VERSION 5.8 ;
BUSBITCHARS "[]" ;
DIVIDERCHAR "/" ;
UNITS
    DATABASE MICRONS 1000 ;
END UNITS

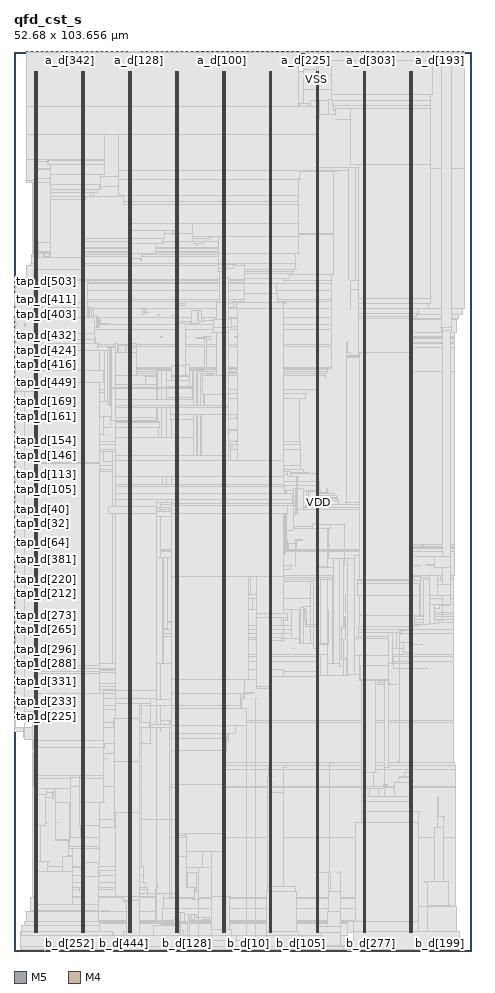
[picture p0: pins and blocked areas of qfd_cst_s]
MACRO qfd_cst_s
  FOREIGN qfd_cst_s 0 0 ;
  CLASS BLOCK ;
  SIZE 52.68 BY 103.656 ;
  PIN a_d[0]
    DIRECTION INPUT ;
    USE SIGNAL ;
    PORT
      LAYER M5 ;
        RECT  20.496 103.572 20.52 103.656 ;
    END
  END a_d[0]
  PIN a_d[100]
    DIRECTION INPUT ;
    USE SIGNAL ;
    PORT
      LAYER M5 ;
        RECT  23.952 103.572 23.976 103.656 ;
    END
  END a_d[100]
  PIN a_d[101]
    DIRECTION INPUT ;
    USE SIGNAL ;
    PORT
      LAYER M5 ;
        RECT  24.048 103.572 24.072 103.656 ;
    END
  END a_d[101]
  PIN a_d[102]
    DIRECTION INPUT ;
    USE SIGNAL ;
    PORT
      LAYER M5 ;
        RECT  24.144 103.572 24.168 103.656 ;
    END
  END a_d[102]
  PIN a_d[103]
    DIRECTION INPUT ;
    USE SIGNAL ;
    PORT
      LAYER M5 ;
        RECT  24.24 103.572 24.264 103.656 ;
    END
  END a_d[103]
  PIN a_d[104]
    DIRECTION INPUT ;
    USE SIGNAL ;
    PORT
      LAYER M5 ;
        RECT  24.336 103.572 24.36 103.656 ;
    END
  END a_d[104]
  PIN a_d[105]
    DIRECTION INPUT ;
    USE SIGNAL ;
    PORT
      LAYER M5 ;
        RECT  24.432 103.572 24.456 103.656 ;
    END
  END a_d[105]
  PIN a_d[106]
    DIRECTION INPUT ;
    USE SIGNAL ;
    PORT
      LAYER M5 ;
        RECT  24.528 103.572 24.552 103.656 ;
    END
  END a_d[106]
  PIN a_d[107]
    DIRECTION INPUT ;
    USE SIGNAL ;
    PORT
      LAYER M5 ;
        RECT  24.624 103.572 24.648 103.656 ;
    END
  END a_d[107]
  PIN a_d[108]
    DIRECTION INPUT ;
    USE SIGNAL ;
    PORT
      LAYER M5 ;
        RECT  24.72 103.572 24.744 103.656 ;
    END
  END a_d[108]
  PIN a_d[109]
    DIRECTION INPUT ;
    USE SIGNAL ;
    PORT
      LAYER M5 ;
        RECT  24.816 103.572 24.84 103.656 ;
    END
  END a_d[109]
  PIN a_d[10]
    DIRECTION INPUT ;
    USE SIGNAL ;
    PORT
      LAYER M5 ;
        RECT  21.456 103.572 21.48 103.656 ;
    END
  END a_d[10]
  PIN a_d[110]
    DIRECTION INPUT ;
    USE SIGNAL ;
    PORT
      LAYER M5 ;
        RECT  24.912 103.572 24.936 103.656 ;
    END
  END a_d[110]
  PIN a_d[111]
    DIRECTION INPUT ;
    USE SIGNAL ;
    PORT
      LAYER M5 ;
        RECT  25.008 103.572 25.032 103.656 ;
    END
  END a_d[111]
  PIN a_d[112]
    DIRECTION INPUT ;
    USE SIGNAL ;
    PORT
      LAYER M5 ;
        RECT  25.104 103.572 25.128 103.656 ;
    END
  END a_d[112]
  PIN a_d[113]
    DIRECTION INPUT ;
    USE SIGNAL ;
    PORT
      LAYER M5 ;
        RECT  25.2 103.572 25.224 103.656 ;
    END
  END a_d[113]
  PIN a_d[114]
    DIRECTION INPUT ;
    USE SIGNAL ;
    PORT
      LAYER M5 ;
        RECT  25.296 103.572 25.32 103.656 ;
    END
  END a_d[114]
  PIN a_d[115]
    DIRECTION INPUT ;
    USE SIGNAL ;
    PORT
      LAYER M5 ;
        RECT  25.392 103.572 25.416 103.656 ;
    END
  END a_d[115]
  PIN a_d[116]
    DIRECTION INPUT ;
    USE SIGNAL ;
    PORT
      LAYER M5 ;
        RECT  25.488 103.572 25.512 103.656 ;
    END
  END a_d[116]
  PIN a_d[117]
    DIRECTION INPUT ;
    USE SIGNAL ;
    PORT
      LAYER M5 ;
        RECT  25.584 103.572 25.608 103.656 ;
    END
  END a_d[117]
  PIN a_d[118]
    DIRECTION INPUT ;
    USE SIGNAL ;
    PORT
      LAYER M5 ;
        RECT  25.68 103.572 25.704 103.656 ;
    END
  END a_d[118]
  PIN a_d[119]
    DIRECTION INPUT ;
    USE SIGNAL ;
    PORT
      LAYER M5 ;
        RECT  25.776 103.572 25.8 103.656 ;
    END
  END a_d[119]
  PIN a_d[11]
    DIRECTION INPUT ;
    USE SIGNAL ;
    PORT
      LAYER M5 ;
        RECT  21.552 103.572 21.576 103.656 ;
    END
  END a_d[11]
  PIN a_d[120]
    DIRECTION INPUT ;
    USE SIGNAL ;
    PORT
      LAYER M5 ;
        RECT  25.872 103.572 25.896 103.656 ;
    END
  END a_d[120]
  PIN a_d[121]
    DIRECTION INPUT ;
    USE SIGNAL ;
    PORT
      LAYER M5 ;
        RECT  25.968 103.572 25.992 103.656 ;
    END
  END a_d[121]
  PIN a_d[122]
    DIRECTION INPUT ;
    USE SIGNAL ;
    PORT
      LAYER M5 ;
        RECT  26.064 103.572 26.088 103.656 ;
    END
  END a_d[122]
  PIN a_d[123]
    DIRECTION INPUT ;
    USE SIGNAL ;
    PORT
      LAYER M5 ;
        RECT  26.16 103.572 26.184 103.656 ;
    END
  END a_d[123]
  PIN a_d[124]
    DIRECTION INPUT ;
    USE SIGNAL ;
    PORT
      LAYER M5 ;
        RECT  26.256 103.572 26.28 103.656 ;
    END
  END a_d[124]
  PIN a_d[125]
    DIRECTION INPUT ;
    USE SIGNAL ;
    PORT
      LAYER M5 ;
        RECT  26.352 103.572 26.376 103.656 ;
    END
  END a_d[125]
  PIN a_d[126]
    DIRECTION INPUT ;
    USE SIGNAL ;
    PORT
      LAYER M5 ;
        RECT  26.448 103.572 26.472 103.656 ;
    END
  END a_d[126]
  PIN a_d[127]
    DIRECTION INPUT ;
    USE SIGNAL ;
    PORT
      LAYER M5 ;
        RECT  26.544 103.572 26.568 103.656 ;
    END
  END a_d[127]
  PIN a_d[128]
    DIRECTION INPUT ;
    USE SIGNAL ;
    PORT
      LAYER M5 ;
        RECT  14.352 103.572 14.376 103.656 ;
    END
  END a_d[128]
  PIN a_d[129]
    DIRECTION INPUT ;
    USE SIGNAL ;
    PORT
      LAYER M5 ;
        RECT  14.448 103.572 14.472 103.656 ;
    END
  END a_d[129]
  PIN a_d[12]
    DIRECTION INPUT ;
    USE SIGNAL ;
    PORT
      LAYER M5 ;
        RECT  21.648 103.572 21.672 103.656 ;
    END
  END a_d[12]
  PIN a_d[130]
    DIRECTION INPUT ;
    USE SIGNAL ;
    PORT
      LAYER M5 ;
        RECT  14.544 103.572 14.568 103.656 ;
    END
  END a_d[130]
  PIN a_d[131]
    DIRECTION INPUT ;
    USE SIGNAL ;
    PORT
      LAYER M5 ;
        RECT  14.64 103.572 14.664 103.656 ;
    END
  END a_d[131]
  PIN a_d[132]
    DIRECTION INPUT ;
    USE SIGNAL ;
    PORT
      LAYER M5 ;
        RECT  14.736 103.572 14.76 103.656 ;
    END
  END a_d[132]
  PIN a_d[133]
    DIRECTION INPUT ;
    USE SIGNAL ;
    PORT
      LAYER M5 ;
        RECT  14.832 103.572 14.856 103.656 ;
    END
  END a_d[133]
  PIN a_d[134]
    DIRECTION INPUT ;
    USE SIGNAL ;
    PORT
      LAYER M5 ;
        RECT  14.928 103.572 14.952 103.656 ;
    END
  END a_d[134]
  PIN a_d[135]
    DIRECTION INPUT ;
    USE SIGNAL ;
    PORT
      LAYER M5 ;
        RECT  15.024 103.572 15.048 103.656 ;
    END
  END a_d[135]
  PIN a_d[136]
    DIRECTION INPUT ;
    USE SIGNAL ;
    PORT
      LAYER M5 ;
        RECT  15.12 103.572 15.144 103.656 ;
    END
  END a_d[136]
  PIN a_d[137]
    DIRECTION INPUT ;
    USE SIGNAL ;
    PORT
      LAYER M5 ;
        RECT  15.216 103.572 15.24 103.656 ;
    END
  END a_d[137]
  PIN a_d[138]
    DIRECTION INPUT ;
    USE SIGNAL ;
    PORT
      LAYER M5 ;
        RECT  15.312 103.572 15.336 103.656 ;
    END
  END a_d[138]
  PIN a_d[139]
    DIRECTION INPUT ;
    USE SIGNAL ;
    PORT
      LAYER M5 ;
        RECT  15.408 103.572 15.432 103.656 ;
    END
  END a_d[139]
  PIN a_d[13]
    DIRECTION INPUT ;
    USE SIGNAL ;
    PORT
      LAYER M5 ;
        RECT  21.744 103.572 21.768 103.656 ;
    END
  END a_d[13]
  PIN a_d[140]
    DIRECTION INPUT ;
    USE SIGNAL ;
    PORT
      LAYER M5 ;
        RECT  15.504 103.572 15.528 103.656 ;
    END
  END a_d[140]
  PIN a_d[141]
    DIRECTION INPUT ;
    USE SIGNAL ;
    PORT
      LAYER M5 ;
        RECT  15.6 103.572 15.624 103.656 ;
    END
  END a_d[141]
  PIN a_d[142]
    DIRECTION INPUT ;
    USE SIGNAL ;
    PORT
      LAYER M5 ;
        RECT  15.696 103.572 15.72 103.656 ;
    END
  END a_d[142]
  PIN a_d[143]
    DIRECTION INPUT ;
    USE SIGNAL ;
    PORT
      LAYER M5 ;
        RECT  15.792 103.572 15.816 103.656 ;
    END
  END a_d[143]
  PIN a_d[144]
    DIRECTION INPUT ;
    USE SIGNAL ;
    PORT
      LAYER M5 ;
        RECT  15.888 103.572 15.912 103.656 ;
    END
  END a_d[144]
  PIN a_d[145]
    DIRECTION INPUT ;
    USE SIGNAL ;
    PORT
      LAYER M5 ;
        RECT  15.984 103.572 16.008 103.656 ;
    END
  END a_d[145]
  PIN a_d[146]
    DIRECTION INPUT ;
    USE SIGNAL ;
    PORT
      LAYER M5 ;
        RECT  16.08 103.572 16.104 103.656 ;
    END
  END a_d[146]
  PIN a_d[147]
    DIRECTION INPUT ;
    USE SIGNAL ;
    PORT
      LAYER M5 ;
        RECT  16.176 103.572 16.2 103.656 ;
    END
  END a_d[147]
  PIN a_d[148]
    DIRECTION INPUT ;
    USE SIGNAL ;
    PORT
      LAYER M5 ;
        RECT  16.272 103.572 16.296 103.656 ;
    END
  END a_d[148]
  PIN a_d[149]
    DIRECTION INPUT ;
    USE SIGNAL ;
    PORT
      LAYER M5 ;
        RECT  16.368 103.572 16.392 103.656 ;
    END
  END a_d[149]
  PIN a_d[14]
    DIRECTION INPUT ;
    USE SIGNAL ;
    PORT
      LAYER M5 ;
        RECT  21.84 103.572 21.864 103.656 ;
    END
  END a_d[14]
  PIN a_d[150]
    DIRECTION INPUT ;
    USE SIGNAL ;
    PORT
      LAYER M5 ;
        RECT  16.464 103.572 16.488 103.656 ;
    END
  END a_d[150]
  PIN a_d[151]
    DIRECTION INPUT ;
    USE SIGNAL ;
    PORT
      LAYER M5 ;
        RECT  16.56 103.572 16.584 103.656 ;
    END
  END a_d[151]
  PIN a_d[152]
    DIRECTION INPUT ;
    USE SIGNAL ;
    PORT
      LAYER M5 ;
        RECT  16.656 103.572 16.68 103.656 ;
    END
  END a_d[152]
  PIN a_d[153]
    DIRECTION INPUT ;
    USE SIGNAL ;
    PORT
      LAYER M5 ;
        RECT  16.752 103.572 16.776 103.656 ;
    END
  END a_d[153]
  PIN a_d[154]
    DIRECTION INPUT ;
    USE SIGNAL ;
    PORT
      LAYER M5 ;
        RECT  16.848 103.572 16.872 103.656 ;
    END
  END a_d[154]
  PIN a_d[155]
    DIRECTION INPUT ;
    USE SIGNAL ;
    PORT
      LAYER M5 ;
        RECT  16.944 103.572 16.968 103.656 ;
    END
  END a_d[155]
  PIN a_d[156]
    DIRECTION INPUT ;
    USE SIGNAL ;
    PORT
      LAYER M5 ;
        RECT  17.04 103.572 17.064 103.656 ;
    END
  END a_d[156]
  PIN a_d[157]
    DIRECTION INPUT ;
    USE SIGNAL ;
    PORT
      LAYER M5 ;
        RECT  17.136 103.572 17.16 103.656 ;
    END
  END a_d[157]
  PIN a_d[158]
    DIRECTION INPUT ;
    USE SIGNAL ;
    PORT
      LAYER M5 ;
        RECT  17.232 103.572 17.256 103.656 ;
    END
  END a_d[158]
  PIN a_d[159]
    DIRECTION INPUT ;
    USE SIGNAL ;
    PORT
      LAYER M5 ;
        RECT  17.328 103.572 17.352 103.656 ;
    END
  END a_d[159]
  PIN a_d[15]
    DIRECTION INPUT ;
    USE SIGNAL ;
    PORT
      LAYER M5 ;
        RECT  21.936 103.572 21.96 103.656 ;
    END
  END a_d[15]
  PIN a_d[160]
    DIRECTION INPUT ;
    USE SIGNAL ;
    PORT
      LAYER M5 ;
        RECT  17.424 103.572 17.448 103.656 ;
    END
  END a_d[160]
  PIN a_d[161]
    DIRECTION INPUT ;
    USE SIGNAL ;
    PORT
      LAYER M5 ;
        RECT  17.52 103.572 17.544 103.656 ;
    END
  END a_d[161]
  PIN a_d[162]
    DIRECTION INPUT ;
    USE SIGNAL ;
    PORT
      LAYER M5 ;
        RECT  17.616 103.572 17.64 103.656 ;
    END
  END a_d[162]
  PIN a_d[163]
    DIRECTION INPUT ;
    USE SIGNAL ;
    PORT
      LAYER M5 ;
        RECT  17.712 103.572 17.736 103.656 ;
    END
  END a_d[163]
  PIN a_d[164]
    DIRECTION INPUT ;
    USE SIGNAL ;
    PORT
      LAYER M5 ;
        RECT  17.808 103.572 17.832 103.656 ;
    END
  END a_d[164]
  PIN a_d[165]
    DIRECTION INPUT ;
    USE SIGNAL ;
    PORT
      LAYER M5 ;
        RECT  17.904 103.572 17.928 103.656 ;
    END
  END a_d[165]
  PIN a_d[166]
    DIRECTION INPUT ;
    USE SIGNAL ;
    PORT
      LAYER M5 ;
        RECT  18 103.572 18.024 103.656 ;
    END
  END a_d[166]
  PIN a_d[167]
    DIRECTION INPUT ;
    USE SIGNAL ;
    PORT
      LAYER M5 ;
        RECT  18.096 103.572 18.12 103.656 ;
    END
  END a_d[167]
  PIN a_d[168]
    DIRECTION INPUT ;
    USE SIGNAL ;
    PORT
      LAYER M5 ;
        RECT  18.192 103.572 18.216 103.656 ;
    END
  END a_d[168]
  PIN a_d[169]
    DIRECTION INPUT ;
    USE SIGNAL ;
    PORT
      LAYER M5 ;
        RECT  18.288 103.572 18.312 103.656 ;
    END
  END a_d[169]
  PIN a_d[16]
    DIRECTION INPUT ;
    USE SIGNAL ;
    PORT
      LAYER M5 ;
        RECT  22.032 103.572 22.056 103.656 ;
    END
  END a_d[16]
  PIN a_d[170]
    DIRECTION INPUT ;
    USE SIGNAL ;
    PORT
      LAYER M5 ;
        RECT  18.384 103.572 18.408 103.656 ;
    END
  END a_d[170]
  PIN a_d[171]
    DIRECTION INPUT ;
    USE SIGNAL ;
    PORT
      LAYER M5 ;
        RECT  18.48 103.572 18.504 103.656 ;
    END
  END a_d[171]
  PIN a_d[172]
    DIRECTION INPUT ;
    USE SIGNAL ;
    PORT
      LAYER M5 ;
        RECT  18.576 103.572 18.6 103.656 ;
    END
  END a_d[172]
  PIN a_d[173]
    DIRECTION INPUT ;
    USE SIGNAL ;
    PORT
      LAYER M5 ;
        RECT  18.672 103.572 18.696 103.656 ;
    END
  END a_d[173]
  PIN a_d[174]
    DIRECTION INPUT ;
    USE SIGNAL ;
    PORT
      LAYER M5 ;
        RECT  18.768 103.572 18.792 103.656 ;
    END
  END a_d[174]
  PIN a_d[175]
    DIRECTION INPUT ;
    USE SIGNAL ;
    PORT
      LAYER M5 ;
        RECT  18.864 103.572 18.888 103.656 ;
    END
  END a_d[175]
  PIN a_d[176]
    DIRECTION INPUT ;
    USE SIGNAL ;
    PORT
      LAYER M5 ;
        RECT  18.96 103.572 18.984 103.656 ;
    END
  END a_d[176]
  PIN a_d[177]
    DIRECTION INPUT ;
    USE SIGNAL ;
    PORT
      LAYER M5 ;
        RECT  19.056 103.572 19.08 103.656 ;
    END
  END a_d[177]
  PIN a_d[178]
    DIRECTION INPUT ;
    USE SIGNAL ;
    PORT
      LAYER M5 ;
        RECT  19.152 103.572 19.176 103.656 ;
    END
  END a_d[178]
  PIN a_d[179]
    DIRECTION INPUT ;
    USE SIGNAL ;
    PORT
      LAYER M5 ;
        RECT  19.248 103.572 19.272 103.656 ;
    END
  END a_d[179]
  PIN a_d[17]
    DIRECTION INPUT ;
    USE SIGNAL ;
    PORT
      LAYER M5 ;
        RECT  22.128 103.572 22.152 103.656 ;
    END
  END a_d[17]
  PIN a_d[180]
    DIRECTION INPUT ;
    USE SIGNAL ;
    PORT
      LAYER M5 ;
        RECT  19.344 103.572 19.368 103.656 ;
    END
  END a_d[180]
  PIN a_d[181]
    DIRECTION INPUT ;
    USE SIGNAL ;
    PORT
      LAYER M5 ;
        RECT  19.44 103.572 19.464 103.656 ;
    END
  END a_d[181]
  PIN a_d[182]
    DIRECTION INPUT ;
    USE SIGNAL ;
    PORT
      LAYER M5 ;
        RECT  19.536 103.572 19.56 103.656 ;
    END
  END a_d[182]
  PIN a_d[183]
    DIRECTION INPUT ;
    USE SIGNAL ;
    PORT
      LAYER M5 ;
        RECT  19.632 103.572 19.656 103.656 ;
    END
  END a_d[183]
  PIN a_d[184]
    DIRECTION INPUT ;
    USE SIGNAL ;
    PORT
      LAYER M5 ;
        RECT  19.728 103.572 19.752 103.656 ;
    END
  END a_d[184]
  PIN a_d[185]
    DIRECTION INPUT ;
    USE SIGNAL ;
    PORT
      LAYER M5 ;
        RECT  19.824 103.572 19.848 103.656 ;
    END
  END a_d[185]
  PIN a_d[186]
    DIRECTION INPUT ;
    USE SIGNAL ;
    PORT
      LAYER M5 ;
        RECT  19.92 103.572 19.944 103.656 ;
    END
  END a_d[186]
  PIN a_d[187]
    DIRECTION INPUT ;
    USE SIGNAL ;
    PORT
      LAYER M5 ;
        RECT  20.016 103.572 20.04 103.656 ;
    END
  END a_d[187]
  PIN a_d[188]
    DIRECTION INPUT ;
    USE SIGNAL ;
    PORT
      LAYER M5 ;
        RECT  20.112 103.572 20.136 103.656 ;
    END
  END a_d[188]
  PIN a_d[189]
    DIRECTION INPUT ;
    USE SIGNAL ;
    PORT
      LAYER M5 ;
        RECT  20.208 103.572 20.232 103.656 ;
    END
  END a_d[189]
  PIN a_d[18]
    DIRECTION INPUT ;
    USE SIGNAL ;
    PORT
      LAYER M5 ;
        RECT  22.224 103.572 22.248 103.656 ;
    END
  END a_d[18]
  PIN a_d[190]
    DIRECTION INPUT ;
    USE SIGNAL ;
    PORT
      LAYER M5 ;
        RECT  20.304 103.572 20.328 103.656 ;
    END
  END a_d[190]
  PIN a_d[191]
    DIRECTION INPUT ;
    USE SIGNAL ;
    PORT
      LAYER M5 ;
        RECT  20.4 103.572 20.424 103.656 ;
    END
  END a_d[191]
  PIN a_d[192]
    DIRECTION INPUT ;
    USE SIGNAL ;
    PORT
      LAYER M5 ;
        RECT  48.912 103.572 48.936 103.656 ;
    END
  END a_d[192]
  PIN a_d[193]
    DIRECTION INPUT ;
    USE SIGNAL ;
    PORT
      LAYER M5 ;
        RECT  49.008 103.572 49.032 103.656 ;
    END
  END a_d[193]
  PIN a_d[194]
    DIRECTION INPUT ;
    USE SIGNAL ;
    PORT
      LAYER M5 ;
        RECT  49.104 103.572 49.128 103.656 ;
    END
  END a_d[194]
  PIN a_d[195]
    DIRECTION INPUT ;
    USE SIGNAL ;
    PORT
      LAYER M5 ;
        RECT  49.2 103.572 49.224 103.656 ;
    END
  END a_d[195]
  PIN a_d[196]
    DIRECTION INPUT ;
    USE SIGNAL ;
    PORT
      LAYER M5 ;
        RECT  49.296 103.572 49.32 103.656 ;
    END
  END a_d[196]
  PIN a_d[197]
    DIRECTION INPUT ;
    USE SIGNAL ;
    PORT
      LAYER M5 ;
        RECT  49.392 103.572 49.416 103.656 ;
    END
  END a_d[197]
  PIN a_d[198]
    DIRECTION INPUT ;
    USE SIGNAL ;
    PORT
      LAYER M5 ;
        RECT  49.488 103.572 49.512 103.656 ;
    END
  END a_d[198]
  PIN a_d[199]
    DIRECTION INPUT ;
    USE SIGNAL ;
    PORT
      LAYER M5 ;
        RECT  49.584 103.572 49.608 103.656 ;
    END
  END a_d[199]
  PIN a_d[19]
    DIRECTION INPUT ;
    USE SIGNAL ;
    PORT
      LAYER M5 ;
        RECT  22.32 103.572 22.344 103.656 ;
    END
  END a_d[19]
  PIN a_d[1]
    DIRECTION INPUT ;
    USE SIGNAL ;
    PORT
      LAYER M5 ;
        RECT  20.592 103.572 20.616 103.656 ;
    END
  END a_d[1]
  PIN a_d[200]
    DIRECTION INPUT ;
    USE SIGNAL ;
    PORT
      LAYER M5 ;
        RECT  49.68 103.572 49.704 103.656 ;
    END
  END a_d[200]
  PIN a_d[201]
    DIRECTION INPUT ;
    USE SIGNAL ;
    PORT
      LAYER M5 ;
        RECT  49.776 103.572 49.8 103.656 ;
    END
  END a_d[201]
  PIN a_d[202]
    DIRECTION INPUT ;
    USE SIGNAL ;
    PORT
      LAYER M5 ;
        RECT  49.872 103.572 49.896 103.656 ;
    END
  END a_d[202]
  PIN a_d[203]
    DIRECTION INPUT ;
    USE SIGNAL ;
    PORT
      LAYER M5 ;
        RECT  49.968 103.572 49.992 103.656 ;
    END
  END a_d[203]
  PIN a_d[204]
    DIRECTION INPUT ;
    USE SIGNAL ;
    PORT
      LAYER M5 ;
        RECT  50.064 103.572 50.088 103.656 ;
    END
  END a_d[204]
  PIN a_d[205]
    DIRECTION INPUT ;
    USE SIGNAL ;
    PORT
      LAYER M5 ;
        RECT  50.16 103.572 50.184 103.656 ;
    END
  END a_d[205]
  PIN a_d[206]
    DIRECTION INPUT ;
    USE SIGNAL ;
    PORT
      LAYER M5 ;
        RECT  50.256 103.572 50.28 103.656 ;
    END
  END a_d[206]
  PIN a_d[207]
    DIRECTION INPUT ;
    USE SIGNAL ;
    PORT
      LAYER M5 ;
        RECT  50.352 103.572 50.376 103.656 ;
    END
  END a_d[207]
  PIN a_d[208]
    DIRECTION INPUT ;
    USE SIGNAL ;
    PORT
      LAYER M5 ;
        RECT  50.448 103.572 50.472 103.656 ;
    END
  END a_d[208]
  PIN a_d[209]
    DIRECTION INPUT ;
    USE SIGNAL ;
    PORT
      LAYER M5 ;
        RECT  50.544 103.572 50.568 103.656 ;
    END
  END a_d[209]
  PIN a_d[20]
    DIRECTION INPUT ;
    USE SIGNAL ;
    PORT
      LAYER M5 ;
        RECT  22.416 103.572 22.44 103.656 ;
    END
  END a_d[20]
  PIN a_d[210]
    DIRECTION INPUT ;
    USE SIGNAL ;
    PORT
      LAYER M5 ;
        RECT  50.64 103.572 50.664 103.656 ;
    END
  END a_d[210]
  PIN a_d[211]
    DIRECTION INPUT ;
    USE SIGNAL ;
    PORT
      LAYER M5 ;
        RECT  50.736 103.572 50.76 103.656 ;
    END
  END a_d[211]
  PIN a_d[212]
    DIRECTION INPUT ;
    USE SIGNAL ;
    PORT
      LAYER M5 ;
        RECT  50.832 103.572 50.856 103.656 ;
    END
  END a_d[212]
  PIN a_d[213]
    DIRECTION INPUT ;
    USE SIGNAL ;
    PORT
      LAYER M5 ;
        RECT  50.928 103.572 50.952 103.656 ;
    END
  END a_d[213]
  PIN a_d[214]
    DIRECTION INPUT ;
    USE SIGNAL ;
    PORT
      LAYER M5 ;
        RECT  51.024 103.572 51.048 103.656 ;
    END
  END a_d[214]
  PIN a_d[215]
    DIRECTION INPUT ;
    USE SIGNAL ;
    PORT
      LAYER M5 ;
        RECT  51.12 103.572 51.144 103.656 ;
    END
  END a_d[215]
  PIN a_d[216]
    DIRECTION INPUT ;
    USE SIGNAL ;
    PORT
      LAYER M5 ;
        RECT  51.216 103.572 51.24 103.656 ;
    END
  END a_d[216]
  PIN a_d[217]
    DIRECTION INPUT ;
    USE SIGNAL ;
    PORT
      LAYER M5 ;
        RECT  51.312 103.572 51.336 103.656 ;
    END
  END a_d[217]
  PIN a_d[218]
    DIRECTION INPUT ;
    USE SIGNAL ;
    PORT
      LAYER M5 ;
        RECT  51.408 103.572 51.432 103.656 ;
    END
  END a_d[218]
  PIN a_d[219]
    DIRECTION INPUT ;
    USE SIGNAL ;
    PORT
      LAYER M5 ;
        RECT  51.504 103.572 51.528 103.656 ;
    END
  END a_d[219]
  PIN a_d[21]
    DIRECTION INPUT ;
    USE SIGNAL ;
    PORT
      LAYER M5 ;
        RECT  22.512 103.572 22.536 103.656 ;
    END
  END a_d[21]
  PIN a_d[220]
    DIRECTION INPUT ;
    USE SIGNAL ;
    PORT
      LAYER M5 ;
        RECT  51.6 103.572 51.624 103.656 ;
    END
  END a_d[220]
  PIN a_d[221]
    DIRECTION INPUT ;
    USE SIGNAL ;
    PORT
      LAYER M5 ;
        RECT  51.696 103.572 51.72 103.656 ;
    END
  END a_d[221]
  PIN a_d[222]
    DIRECTION INPUT ;
    USE SIGNAL ;
    PORT
      LAYER M5 ;
        RECT  51.792 103.572 51.816 103.656 ;
    END
  END a_d[222]
  PIN a_d[223]
    DIRECTION INPUT ;
    USE SIGNAL ;
    PORT
      LAYER M5 ;
        RECT  51.888 103.572 51.912 103.656 ;
    END
  END a_d[223]
  PIN a_d[224]
    DIRECTION INPUT ;
    USE SIGNAL ;
    PORT
      LAYER M5 ;
        RECT  33.552 103.572 33.576 103.656 ;
    END
  END a_d[224]
  PIN a_d[225]
    DIRECTION INPUT ;
    USE SIGNAL ;
    PORT
      LAYER M5 ;
        RECT  33.648 103.572 33.672 103.656 ;
    END
  END a_d[225]
  PIN a_d[226]
    DIRECTION INPUT ;
    USE SIGNAL ;
    PORT
      LAYER M5 ;
        RECT  33.744 103.572 33.768 103.656 ;
    END
  END a_d[226]
  PIN a_d[227]
    DIRECTION INPUT ;
    USE SIGNAL ;
    PORT
      LAYER M5 ;
        RECT  33.84 103.572 33.864 103.656 ;
    END
  END a_d[227]
  PIN a_d[228]
    DIRECTION INPUT ;
    USE SIGNAL ;
    PORT
      LAYER M5 ;
        RECT  33.936 103.572 33.96 103.656 ;
    END
  END a_d[228]
  PIN a_d[229]
    DIRECTION INPUT ;
    USE SIGNAL ;
    PORT
      LAYER M5 ;
        RECT  34.032 103.572 34.056 103.656 ;
    END
  END a_d[229]
  PIN a_d[22]
    DIRECTION INPUT ;
    USE SIGNAL ;
    PORT
      LAYER M5 ;
        RECT  22.608 103.572 22.632 103.656 ;
    END
  END a_d[22]
  PIN a_d[230]
    DIRECTION INPUT ;
    USE SIGNAL ;
    PORT
      LAYER M5 ;
        RECT  34.128 103.572 34.152 103.656 ;
    END
  END a_d[230]
  PIN a_d[231]
    DIRECTION INPUT ;
    USE SIGNAL ;
    PORT
      LAYER M5 ;
        RECT  34.224 103.572 34.248 103.656 ;
    END
  END a_d[231]
  PIN a_d[232]
    DIRECTION INPUT ;
    USE SIGNAL ;
    PORT
      LAYER M5 ;
        RECT  34.32 103.572 34.344 103.656 ;
    END
  END a_d[232]
  PIN a_d[233]
    DIRECTION INPUT ;
    USE SIGNAL ;
    PORT
      LAYER M5 ;
        RECT  34.416 103.572 34.44 103.656 ;
    END
  END a_d[233]
  PIN a_d[234]
    DIRECTION INPUT ;
    USE SIGNAL ;
    PORT
      LAYER M5 ;
        RECT  34.512 103.572 34.536 103.656 ;
    END
  END a_d[234]
  PIN a_d[235]
    DIRECTION INPUT ;
    USE SIGNAL ;
    PORT
      LAYER M5 ;
        RECT  34.608 103.572 34.632 103.656 ;
    END
  END a_d[235]
  PIN a_d[236]
    DIRECTION INPUT ;
    USE SIGNAL ;
    PORT
      LAYER M5 ;
        RECT  34.704 103.572 34.728 103.656 ;
    END
  END a_d[236]
  PIN a_d[237]
    DIRECTION INPUT ;
    USE SIGNAL ;
    PORT
      LAYER M5 ;
        RECT  34.8 103.572 34.824 103.656 ;
    END
  END a_d[237]
  PIN a_d[238]
    DIRECTION INPUT ;
    USE SIGNAL ;
    PORT
      LAYER M5 ;
        RECT  34.896 103.572 34.92 103.656 ;
    END
  END a_d[238]
  PIN a_d[239]
    DIRECTION INPUT ;
    USE SIGNAL ;
    PORT
      LAYER M5 ;
        RECT  34.992 103.572 35.016 103.656 ;
    END
  END a_d[239]
  PIN a_d[23]
    DIRECTION INPUT ;
    USE SIGNAL ;
    PORT
      LAYER M5 ;
        RECT  22.704 103.572 22.728 103.656 ;
    END
  END a_d[23]
  PIN a_d[240]
    DIRECTION INPUT ;
    USE SIGNAL ;
    PORT
      LAYER M5 ;
        RECT  35.088 103.572 35.112 103.656 ;
    END
  END a_d[240]
  PIN a_d[241]
    DIRECTION INPUT ;
    USE SIGNAL ;
    PORT
      LAYER M5 ;
        RECT  35.184 103.572 35.208 103.656 ;
    END
  END a_d[241]
  PIN a_d[242]
    DIRECTION INPUT ;
    USE SIGNAL ;
    PORT
      LAYER M5 ;
        RECT  35.28 103.572 35.304 103.656 ;
    END
  END a_d[242]
  PIN a_d[243]
    DIRECTION INPUT ;
    USE SIGNAL ;
    PORT
      LAYER M5 ;
        RECT  35.376 103.572 35.4 103.656 ;
    END
  END a_d[243]
  PIN a_d[244]
    DIRECTION INPUT ;
    USE SIGNAL ;
    PORT
      LAYER M5 ;
        RECT  35.472 103.572 35.496 103.656 ;
    END
  END a_d[244]
  PIN a_d[245]
    DIRECTION INPUT ;
    USE SIGNAL ;
    PORT
      LAYER M5 ;
        RECT  35.568 103.572 35.592 103.656 ;
    END
  END a_d[245]
  PIN a_d[246]
    DIRECTION INPUT ;
    USE SIGNAL ;
    PORT
      LAYER M5 ;
        RECT  35.664 103.572 35.688 103.656 ;
    END
  END a_d[246]
  PIN a_d[247]
    DIRECTION INPUT ;
    USE SIGNAL ;
    PORT
      LAYER M5 ;
        RECT  35.76 103.572 35.784 103.656 ;
    END
  END a_d[247]
  PIN a_d[248]
    DIRECTION INPUT ;
    USE SIGNAL ;
    PORT
      LAYER M5 ;
        RECT  35.856 103.572 35.88 103.656 ;
    END
  END a_d[248]
  PIN a_d[249]
    DIRECTION INPUT ;
    USE SIGNAL ;
    PORT
      LAYER M5 ;
        RECT  35.952 103.572 35.976 103.656 ;
    END
  END a_d[249]
  PIN a_d[24]
    DIRECTION INPUT ;
    USE SIGNAL ;
    PORT
      LAYER M5 ;
        RECT  22.8 103.572 22.824 103.656 ;
    END
  END a_d[24]
  PIN a_d[250]
    DIRECTION INPUT ;
    USE SIGNAL ;
    PORT
      LAYER M5 ;
        RECT  36.048 103.572 36.072 103.656 ;
    END
  END a_d[250]
  PIN a_d[251]
    DIRECTION INPUT ;
    USE SIGNAL ;
    PORT
      LAYER M5 ;
        RECT  36.144 103.572 36.168 103.656 ;
    END
  END a_d[251]
  PIN a_d[252]
    DIRECTION INPUT ;
    USE SIGNAL ;
    PORT
      LAYER M5 ;
        RECT  36.24 103.572 36.264 103.656 ;
    END
  END a_d[252]
  PIN a_d[253]
    DIRECTION INPUT ;
    USE SIGNAL ;
    PORT
      LAYER M5 ;
        RECT  36.336 103.572 36.36 103.656 ;
    END
  END a_d[253]
  PIN a_d[254]
    DIRECTION INPUT ;
    USE SIGNAL ;
    PORT
      LAYER M5 ;
        RECT  36.432 103.572 36.456 103.656 ;
    END
  END a_d[254]
  PIN a_d[255]
    DIRECTION INPUT ;
    USE SIGNAL ;
    PORT
      LAYER M5 ;
        RECT  36.528 103.572 36.552 103.656 ;
    END
  END a_d[255]
  PIN a_d[256]
    DIRECTION INPUT ;
    USE SIGNAL ;
    PORT
      LAYER M5 ;
        RECT  42.768 103.572 42.792 103.656 ;
    END
  END a_d[256]
  PIN a_d[257]
    DIRECTION INPUT ;
    USE SIGNAL ;
    PORT
      LAYER M5 ;
        RECT  42.864 103.572 42.888 103.656 ;
    END
  END a_d[257]
  PIN a_d[258]
    DIRECTION INPUT ;
    USE SIGNAL ;
    PORT
      LAYER M5 ;
        RECT  42.96 103.572 42.984 103.656 ;
    END
  END a_d[258]
  PIN a_d[259]
    DIRECTION INPUT ;
    USE SIGNAL ;
    PORT
      LAYER M5 ;
        RECT  43.056 103.572 43.08 103.656 ;
    END
  END a_d[259]
  PIN a_d[25]
    DIRECTION INPUT ;
    USE SIGNAL ;
    PORT
      LAYER M5 ;
        RECT  22.896 103.572 22.92 103.656 ;
    END
  END a_d[25]
  PIN a_d[260]
    DIRECTION INPUT ;
    USE SIGNAL ;
    PORT
      LAYER M5 ;
        RECT  43.152 103.572 43.176 103.656 ;
    END
  END a_d[260]
  PIN a_d[261]
    DIRECTION INPUT ;
    USE SIGNAL ;
    PORT
      LAYER M5 ;
        RECT  43.248 103.572 43.272 103.656 ;
    END
  END a_d[261]
  PIN a_d[262]
    DIRECTION INPUT ;
    USE SIGNAL ;
    PORT
      LAYER M5 ;
        RECT  43.344 103.572 43.368 103.656 ;
    END
  END a_d[262]
  PIN a_d[263]
    DIRECTION INPUT ;
    USE SIGNAL ;
    PORT
      LAYER M5 ;
        RECT  43.44 103.572 43.464 103.656 ;
    END
  END a_d[263]
  PIN a_d[264]
    DIRECTION INPUT ;
    USE SIGNAL ;
    PORT
      LAYER M5 ;
        RECT  43.536 103.572 43.56 103.656 ;
    END
  END a_d[264]
  PIN a_d[265]
    DIRECTION INPUT ;
    USE SIGNAL ;
    PORT
      LAYER M5 ;
        RECT  43.632 103.572 43.656 103.656 ;
    END
  END a_d[265]
  PIN a_d[266]
    DIRECTION INPUT ;
    USE SIGNAL ;
    PORT
      LAYER M5 ;
        RECT  43.728 103.572 43.752 103.656 ;
    END
  END a_d[266]
  PIN a_d[267]
    DIRECTION INPUT ;
    USE SIGNAL ;
    PORT
      LAYER M5 ;
        RECT  43.824 103.572 43.848 103.656 ;
    END
  END a_d[267]
  PIN a_d[268]
    DIRECTION INPUT ;
    USE SIGNAL ;
    PORT
      LAYER M5 ;
        RECT  43.92 103.572 43.944 103.656 ;
    END
  END a_d[268]
  PIN a_d[269]
    DIRECTION INPUT ;
    USE SIGNAL ;
    PORT
      LAYER M5 ;
        RECT  44.016 103.572 44.04 103.656 ;
    END
  END a_d[269]
  PIN a_d[26]
    DIRECTION INPUT ;
    USE SIGNAL ;
    PORT
      LAYER M5 ;
        RECT  22.992 103.572 23.016 103.656 ;
    END
  END a_d[26]
  PIN a_d[270]
    DIRECTION INPUT ;
    USE SIGNAL ;
    PORT
      LAYER M5 ;
        RECT  44.112 103.572 44.136 103.656 ;
    END
  END a_d[270]
  PIN a_d[271]
    DIRECTION INPUT ;
    USE SIGNAL ;
    PORT
      LAYER M5 ;
        RECT  44.208 103.572 44.232 103.656 ;
    END
  END a_d[271]
  PIN a_d[272]
    DIRECTION INPUT ;
    USE SIGNAL ;
    PORT
      LAYER M5 ;
        RECT  44.304 103.572 44.328 103.656 ;
    END
  END a_d[272]
  PIN a_d[273]
    DIRECTION INPUT ;
    USE SIGNAL ;
    PORT
      LAYER M5 ;
        RECT  44.4 103.572 44.424 103.656 ;
    END
  END a_d[273]
  PIN a_d[274]
    DIRECTION INPUT ;
    USE SIGNAL ;
    PORT
      LAYER M5 ;
        RECT  44.496 103.572 44.52 103.656 ;
    END
  END a_d[274]
  PIN a_d[275]
    DIRECTION INPUT ;
    USE SIGNAL ;
    PORT
      LAYER M5 ;
        RECT  44.592 103.572 44.616 103.656 ;
    END
  END a_d[275]
  PIN a_d[276]
    DIRECTION INPUT ;
    USE SIGNAL ;
    PORT
      LAYER M5 ;
        RECT  44.688 103.572 44.712 103.656 ;
    END
  END a_d[276]
  PIN a_d[277]
    DIRECTION INPUT ;
    USE SIGNAL ;
    PORT
      LAYER M5 ;
        RECT  44.784 103.572 44.808 103.656 ;
    END
  END a_d[277]
  PIN a_d[278]
    DIRECTION INPUT ;
    USE SIGNAL ;
    PORT
      LAYER M5 ;
        RECT  44.88 103.572 44.904 103.656 ;
    END
  END a_d[278]
  PIN a_d[279]
    DIRECTION INPUT ;
    USE SIGNAL ;
    PORT
      LAYER M5 ;
        RECT  44.976 103.572 45 103.656 ;
    END
  END a_d[279]
  PIN a_d[27]
    DIRECTION INPUT ;
    USE SIGNAL ;
    PORT
      LAYER M5 ;
        RECT  23.088 103.572 23.112 103.656 ;
    END
  END a_d[27]
  PIN a_d[280]
    DIRECTION INPUT ;
    USE SIGNAL ;
    PORT
      LAYER M5 ;
        RECT  45.072 103.572 45.096 103.656 ;
    END
  END a_d[280]
  PIN a_d[281]
    DIRECTION INPUT ;
    USE SIGNAL ;
    PORT
      LAYER M5 ;
        RECT  45.168 103.572 45.192 103.656 ;
    END
  END a_d[281]
  PIN a_d[282]
    DIRECTION INPUT ;
    USE SIGNAL ;
    PORT
      LAYER M5 ;
        RECT  45.264 103.572 45.288 103.656 ;
    END
  END a_d[282]
  PIN a_d[283]
    DIRECTION INPUT ;
    USE SIGNAL ;
    PORT
      LAYER M5 ;
        RECT  45.36 103.572 45.384 103.656 ;
    END
  END a_d[283]
  PIN a_d[284]
    DIRECTION INPUT ;
    USE SIGNAL ;
    PORT
      LAYER M5 ;
        RECT  45.456 103.572 45.48 103.656 ;
    END
  END a_d[284]
  PIN a_d[285]
    DIRECTION INPUT ;
    USE SIGNAL ;
    PORT
      LAYER M5 ;
        RECT  45.552 103.572 45.576 103.656 ;
    END
  END a_d[285]
  PIN a_d[286]
    DIRECTION INPUT ;
    USE SIGNAL ;
    PORT
      LAYER M5 ;
        RECT  45.648 103.572 45.672 103.656 ;
    END
  END a_d[286]
  PIN a_d[287]
    DIRECTION INPUT ;
    USE SIGNAL ;
    PORT
      LAYER M5 ;
        RECT  45.744 103.572 45.768 103.656 ;
    END
  END a_d[287]
  PIN a_d[288]
    DIRECTION INPUT ;
    USE SIGNAL ;
    PORT
      LAYER M5 ;
        RECT  39.696 103.572 39.72 103.656 ;
    END
  END a_d[288]
  PIN a_d[289]
    DIRECTION INPUT ;
    USE SIGNAL ;
    PORT
      LAYER M5 ;
        RECT  39.792 103.572 39.816 103.656 ;
    END
  END a_d[289]
  PIN a_d[28]
    DIRECTION INPUT ;
    USE SIGNAL ;
    PORT
      LAYER M5 ;
        RECT  23.184 103.572 23.208 103.656 ;
    END
  END a_d[28]
  PIN a_d[290]
    DIRECTION INPUT ;
    USE SIGNAL ;
    PORT
      LAYER M5 ;
        RECT  39.888 103.572 39.912 103.656 ;
    END
  END a_d[290]
  PIN a_d[291]
    DIRECTION INPUT ;
    USE SIGNAL ;
    PORT
      LAYER M5 ;
        RECT  39.984 103.572 40.008 103.656 ;
    END
  END a_d[291]
  PIN a_d[292]
    DIRECTION INPUT ;
    USE SIGNAL ;
    PORT
      LAYER M5 ;
        RECT  40.08 103.572 40.104 103.656 ;
    END
  END a_d[292]
  PIN a_d[293]
    DIRECTION INPUT ;
    USE SIGNAL ;
    PORT
      LAYER M5 ;
        RECT  40.176 103.572 40.2 103.656 ;
    END
  END a_d[293]
  PIN a_d[294]
    DIRECTION INPUT ;
    USE SIGNAL ;
    PORT
      LAYER M5 ;
        RECT  40.272 103.572 40.296 103.656 ;
    END
  END a_d[294]
  PIN a_d[295]
    DIRECTION INPUT ;
    USE SIGNAL ;
    PORT
      LAYER M5 ;
        RECT  40.368 103.572 40.392 103.656 ;
    END
  END a_d[295]
  PIN a_d[296]
    DIRECTION INPUT ;
    USE SIGNAL ;
    PORT
      LAYER M5 ;
        RECT  40.464 103.572 40.488 103.656 ;
    END
  END a_d[296]
  PIN a_d[297]
    DIRECTION INPUT ;
    USE SIGNAL ;
    PORT
      LAYER M5 ;
        RECT  40.56 103.572 40.584 103.656 ;
    END
  END a_d[297]
  PIN a_d[298]
    DIRECTION INPUT ;
    USE SIGNAL ;
    PORT
      LAYER M5 ;
        RECT  40.656 103.572 40.68 103.656 ;
    END
  END a_d[298]
  PIN a_d[299]
    DIRECTION INPUT ;
    USE SIGNAL ;
    PORT
      LAYER M5 ;
        RECT  40.752 103.572 40.776 103.656 ;
    END
  END a_d[299]
  PIN a_d[29]
    DIRECTION INPUT ;
    USE SIGNAL ;
    PORT
      LAYER M5 ;
        RECT  23.28 103.572 23.304 103.656 ;
    END
  END a_d[29]
  PIN a_d[2]
    DIRECTION INPUT ;
    USE SIGNAL ;
    PORT
      LAYER M5 ;
        RECT  20.688 103.572 20.712 103.656 ;
    END
  END a_d[2]
  PIN a_d[300]
    DIRECTION INPUT ;
    USE SIGNAL ;
    PORT
      LAYER M5 ;
        RECT  40.848 103.572 40.872 103.656 ;
    END
  END a_d[300]
  PIN a_d[301]
    DIRECTION INPUT ;
    USE SIGNAL ;
    PORT
      LAYER M5 ;
        RECT  40.944 103.572 40.968 103.656 ;
    END
  END a_d[301]
  PIN a_d[302]
    DIRECTION INPUT ;
    USE SIGNAL ;
    PORT
      LAYER M5 ;
        RECT  41.04 103.572 41.064 103.656 ;
    END
  END a_d[302]
  PIN a_d[303]
    DIRECTION INPUT ;
    USE SIGNAL ;
    PORT
      LAYER M5 ;
        RECT  41.136 103.572 41.16 103.656 ;
    END
  END a_d[303]
  PIN a_d[304]
    DIRECTION INPUT ;
    USE SIGNAL ;
    PORT
      LAYER M5 ;
        RECT  41.232 103.572 41.256 103.656 ;
    END
  END a_d[304]
  PIN a_d[305]
    DIRECTION INPUT ;
    USE SIGNAL ;
    PORT
      LAYER M5 ;
        RECT  41.328 103.572 41.352 103.656 ;
    END
  END a_d[305]
  PIN a_d[306]
    DIRECTION INPUT ;
    USE SIGNAL ;
    PORT
      LAYER M5 ;
        RECT  41.424 103.572 41.448 103.656 ;
    END
  END a_d[306]
  PIN a_d[307]
    DIRECTION INPUT ;
    USE SIGNAL ;
    PORT
      LAYER M5 ;
        RECT  41.52 103.572 41.544 103.656 ;
    END
  END a_d[307]
  PIN a_d[308]
    DIRECTION INPUT ;
    USE SIGNAL ;
    PORT
      LAYER M5 ;
        RECT  41.616 103.572 41.64 103.656 ;
    END
  END a_d[308]
  PIN a_d[309]
    DIRECTION INPUT ;
    USE SIGNAL ;
    PORT
      LAYER M5 ;
        RECT  41.712 103.572 41.736 103.656 ;
    END
  END a_d[309]
  PIN a_d[30]
    DIRECTION INPUT ;
    USE SIGNAL ;
    PORT
      LAYER M5 ;
        RECT  23.376 103.572 23.4 103.656 ;
    END
  END a_d[30]
  PIN a_d[310]
    DIRECTION INPUT ;
    USE SIGNAL ;
    PORT
      LAYER M5 ;
        RECT  41.808 103.572 41.832 103.656 ;
    END
  END a_d[310]
  PIN a_d[311]
    DIRECTION INPUT ;
    USE SIGNAL ;
    PORT
      LAYER M5 ;
        RECT  41.904 103.572 41.928 103.656 ;
    END
  END a_d[311]
  PIN a_d[312]
    DIRECTION INPUT ;
    USE SIGNAL ;
    PORT
      LAYER M5 ;
        RECT  42 103.572 42.024 103.656 ;
    END
  END a_d[312]
  PIN a_d[313]
    DIRECTION INPUT ;
    USE SIGNAL ;
    PORT
      LAYER M5 ;
        RECT  42.096 103.572 42.12 103.656 ;
    END
  END a_d[313]
  PIN a_d[314]
    DIRECTION INPUT ;
    USE SIGNAL ;
    PORT
      LAYER M5 ;
        RECT  42.192 103.572 42.216 103.656 ;
    END
  END a_d[314]
  PIN a_d[315]
    DIRECTION INPUT ;
    USE SIGNAL ;
    PORT
      LAYER M5 ;
        RECT  42.288 103.572 42.312 103.656 ;
    END
  END a_d[315]
  PIN a_d[316]
    DIRECTION INPUT ;
    USE SIGNAL ;
    PORT
      LAYER M5 ;
        RECT  42.384 103.572 42.408 103.656 ;
    END
  END a_d[316]
  PIN a_d[317]
    DIRECTION INPUT ;
    USE SIGNAL ;
    PORT
      LAYER M5 ;
        RECT  42.48 103.572 42.504 103.656 ;
    END
  END a_d[317]
  PIN a_d[318]
    DIRECTION INPUT ;
    USE SIGNAL ;
    PORT
      LAYER M5 ;
        RECT  42.576 103.572 42.6 103.656 ;
    END
  END a_d[318]
  PIN a_d[319]
    DIRECTION INPUT ;
    USE SIGNAL ;
    PORT
      LAYER M5 ;
        RECT  42.672 103.572 42.696 103.656 ;
    END
  END a_d[319]
  PIN a_d[31]
    DIRECTION INPUT ;
    USE SIGNAL ;
    PORT
      LAYER M5 ;
        RECT  23.472 103.572 23.496 103.656 ;
    END
  END a_d[31]
  PIN a_d[320]
    DIRECTION INPUT ;
    USE SIGNAL ;
    PORT
      LAYER M5 ;
        RECT  4.368 103.572 4.392 103.656 ;
    END
  END a_d[320]
  PIN a_d[321]
    DIRECTION INPUT ;
    USE SIGNAL ;
    PORT
      LAYER M5 ;
        RECT  4.464 103.572 4.488 103.656 ;
    END
  END a_d[321]
  PIN a_d[322]
    DIRECTION INPUT ;
    USE SIGNAL ;
    PORT
      LAYER M5 ;
        RECT  4.56 103.572 4.584 103.656 ;
    END
  END a_d[322]
  PIN a_d[323]
    DIRECTION INPUT ;
    USE SIGNAL ;
    PORT
      LAYER M5 ;
        RECT  4.656 103.572 4.68 103.656 ;
    END
  END a_d[323]
  PIN a_d[324]
    DIRECTION INPUT ;
    USE SIGNAL ;
    PORT
      LAYER M5 ;
        RECT  4.752 103.572 4.776 103.656 ;
    END
  END a_d[324]
  PIN a_d[325]
    DIRECTION INPUT ;
    USE SIGNAL ;
    PORT
      LAYER M5 ;
        RECT  4.848 103.572 4.872 103.656 ;
    END
  END a_d[325]
  PIN a_d[326]
    DIRECTION INPUT ;
    USE SIGNAL ;
    PORT
      LAYER M5 ;
        RECT  4.944 103.572 4.968 103.656 ;
    END
  END a_d[326]
  PIN a_d[327]
    DIRECTION INPUT ;
    USE SIGNAL ;
    PORT
      LAYER M5 ;
        RECT  5.04 103.572 5.064 103.656 ;
    END
  END a_d[327]
  PIN a_d[328]
    DIRECTION INPUT ;
    USE SIGNAL ;
    PORT
      LAYER M5 ;
        RECT  5.136 103.572 5.16 103.656 ;
    END
  END a_d[328]
  PIN a_d[329]
    DIRECTION INPUT ;
    USE SIGNAL ;
    PORT
      LAYER M5 ;
        RECT  5.232 103.572 5.256 103.656 ;
    END
  END a_d[329]
  PIN a_d[32]
    DIRECTION INPUT ;
    USE SIGNAL ;
    PORT
      LAYER M5 ;
        RECT  29.712 103.572 29.736 103.656 ;
    END
  END a_d[32]
  PIN a_d[330]
    DIRECTION INPUT ;
    USE SIGNAL ;
    PORT
      LAYER M5 ;
        RECT  5.328 103.572 5.352 103.656 ;
    END
  END a_d[330]
  PIN a_d[331]
    DIRECTION INPUT ;
    USE SIGNAL ;
    PORT
      LAYER M5 ;
        RECT  5.424 103.572 5.448 103.656 ;
    END
  END a_d[331]
  PIN a_d[332]
    DIRECTION INPUT ;
    USE SIGNAL ;
    PORT
      LAYER M5 ;
        RECT  5.52 103.572 5.544 103.656 ;
    END
  END a_d[332]
  PIN a_d[333]
    DIRECTION INPUT ;
    USE SIGNAL ;
    PORT
      LAYER M5 ;
        RECT  5.616 103.572 5.64 103.656 ;
    END
  END a_d[333]
  PIN a_d[334]
    DIRECTION INPUT ;
    USE SIGNAL ;
    PORT
      LAYER M5 ;
        RECT  5.712 103.572 5.736 103.656 ;
    END
  END a_d[334]
  PIN a_d[335]
    DIRECTION INPUT ;
    USE SIGNAL ;
    PORT
      LAYER M5 ;
        RECT  5.808 103.572 5.832 103.656 ;
    END
  END a_d[335]
  PIN a_d[336]
    DIRECTION INPUT ;
    USE SIGNAL ;
    PORT
      LAYER M5 ;
        RECT  5.904 103.572 5.928 103.656 ;
    END
  END a_d[336]
  PIN a_d[337]
    DIRECTION INPUT ;
    USE SIGNAL ;
    PORT
      LAYER M5 ;
        RECT  6 103.572 6.024 103.656 ;
    END
  END a_d[337]
  PIN a_d[338]
    DIRECTION INPUT ;
    USE SIGNAL ;
    PORT
      LAYER M5 ;
        RECT  6.096 103.572 6.12 103.656 ;
    END
  END a_d[338]
  PIN a_d[339]
    DIRECTION INPUT ;
    USE SIGNAL ;
    PORT
      LAYER M5 ;
        RECT  6.192 103.572 6.216 103.656 ;
    END
  END a_d[339]
  PIN a_d[33]
    DIRECTION INPUT ;
    USE SIGNAL ;
    PORT
      LAYER M5 ;
        RECT  29.808 103.572 29.832 103.656 ;
    END
  END a_d[33]
  PIN a_d[340]
    DIRECTION INPUT ;
    USE SIGNAL ;
    PORT
      LAYER M5 ;
        RECT  6.288 103.572 6.312 103.656 ;
    END
  END a_d[340]
  PIN a_d[341]
    DIRECTION INPUT ;
    USE SIGNAL ;
    PORT
      LAYER M5 ;
        RECT  6.384 103.572 6.408 103.656 ;
    END
  END a_d[341]
  PIN a_d[342]
    DIRECTION INPUT ;
    USE SIGNAL ;
    PORT
      LAYER M5 ;
        RECT  6.48 103.572 6.504 103.656 ;
    END
  END a_d[342]
  PIN a_d[343]
    DIRECTION INPUT ;
    USE SIGNAL ;
    PORT
      LAYER M5 ;
        RECT  6.576 103.572 6.6 103.656 ;
    END
  END a_d[343]
  PIN a_d[344]
    DIRECTION INPUT ;
    USE SIGNAL ;
    PORT
      LAYER M5 ;
        RECT  6.672 103.572 6.696 103.656 ;
    END
  END a_d[344]
  PIN a_d[345]
    DIRECTION INPUT ;
    USE SIGNAL ;
    PORT
      LAYER M5 ;
        RECT  6.768 103.572 6.792 103.656 ;
    END
  END a_d[345]
  PIN a_d[346]
    DIRECTION INPUT ;
    USE SIGNAL ;
    PORT
      LAYER M5 ;
        RECT  6.864 103.572 6.888 103.656 ;
    END
  END a_d[346]
  PIN a_d[347]
    DIRECTION INPUT ;
    USE SIGNAL ;
    PORT
      LAYER M5 ;
        RECT  6.96 103.572 6.984 103.656 ;
    END
  END a_d[347]
  PIN a_d[348]
    DIRECTION INPUT ;
    USE SIGNAL ;
    PORT
      LAYER M5 ;
        RECT  7.056 103.572 7.08 103.656 ;
    END
  END a_d[348]
  PIN a_d[349]
    DIRECTION INPUT ;
    USE SIGNAL ;
    PORT
      LAYER M5 ;
        RECT  7.152 103.572 7.176 103.656 ;
    END
  END a_d[349]
  PIN a_d[34]
    DIRECTION INPUT ;
    USE SIGNAL ;
    PORT
      LAYER M5 ;
        RECT  29.904 103.572 29.928 103.656 ;
    END
  END a_d[34]
  PIN a_d[350]
    DIRECTION INPUT ;
    USE SIGNAL ;
    PORT
      LAYER M5 ;
        RECT  7.248 103.572 7.272 103.656 ;
    END
  END a_d[350]
  PIN a_d[351]
    DIRECTION INPUT ;
    USE SIGNAL ;
    PORT
      LAYER M5 ;
        RECT  7.344 103.572 7.368 103.656 ;
    END
  END a_d[351]
  PIN a_d[352]
    DIRECTION INPUT ;
    USE SIGNAL ;
    PORT
      LAYER M5 ;
        RECT  45.84 103.572 45.864 103.656 ;
    END
  END a_d[352]
  PIN a_d[353]
    DIRECTION INPUT ;
    USE SIGNAL ;
    PORT
      LAYER M5 ;
        RECT  45.936 103.572 45.96 103.656 ;
    END
  END a_d[353]
  PIN a_d[354]
    DIRECTION INPUT ;
    USE SIGNAL ;
    PORT
      LAYER M5 ;
        RECT  46.032 103.572 46.056 103.656 ;
    END
  END a_d[354]
  PIN a_d[355]
    DIRECTION INPUT ;
    USE SIGNAL ;
    PORT
      LAYER M5 ;
        RECT  46.128 103.572 46.152 103.656 ;
    END
  END a_d[355]
  PIN a_d[356]
    DIRECTION INPUT ;
    USE SIGNAL ;
    PORT
      LAYER M5 ;
        RECT  46.224 103.572 46.248 103.656 ;
    END
  END a_d[356]
  PIN a_d[357]
    DIRECTION INPUT ;
    USE SIGNAL ;
    PORT
      LAYER M5 ;
        RECT  46.32 103.572 46.344 103.656 ;
    END
  END a_d[357]
  PIN a_d[358]
    DIRECTION INPUT ;
    USE SIGNAL ;
    PORT
      LAYER M5 ;
        RECT  46.416 103.572 46.44 103.656 ;
    END
  END a_d[358]
  PIN a_d[359]
    DIRECTION INPUT ;
    USE SIGNAL ;
    PORT
      LAYER M5 ;
        RECT  46.512 103.572 46.536 103.656 ;
    END
  END a_d[359]
  PIN a_d[35]
    DIRECTION INPUT ;
    USE SIGNAL ;
    PORT
      LAYER M5 ;
        RECT  30 103.572 30.024 103.656 ;
    END
  END a_d[35]
  PIN a_d[360]
    DIRECTION INPUT ;
    USE SIGNAL ;
    PORT
      LAYER M5 ;
        RECT  46.608 103.572 46.632 103.656 ;
    END
  END a_d[360]
  PIN a_d[361]
    DIRECTION INPUT ;
    USE SIGNAL ;
    PORT
      LAYER M5 ;
        RECT  46.704 103.572 46.728 103.656 ;
    END
  END a_d[361]
  PIN a_d[362]
    DIRECTION INPUT ;
    USE SIGNAL ;
    PORT
      LAYER M5 ;
        RECT  46.8 103.572 46.824 103.656 ;
    END
  END a_d[362]
  PIN a_d[363]
    DIRECTION INPUT ;
    USE SIGNAL ;
    PORT
      LAYER M5 ;
        RECT  46.896 103.572 46.92 103.656 ;
    END
  END a_d[363]
  PIN a_d[364]
    DIRECTION INPUT ;
    USE SIGNAL ;
    PORT
      LAYER M5 ;
        RECT  46.992 103.572 47.016 103.656 ;
    END
  END a_d[364]
  PIN a_d[365]
    DIRECTION INPUT ;
    USE SIGNAL ;
    PORT
      LAYER M5 ;
        RECT  47.088 103.572 47.112 103.656 ;
    END
  END a_d[365]
  PIN a_d[366]
    DIRECTION INPUT ;
    USE SIGNAL ;
    PORT
      LAYER M5 ;
        RECT  47.184 103.572 47.208 103.656 ;
    END
  END a_d[366]
  PIN a_d[367]
    DIRECTION INPUT ;
    USE SIGNAL ;
    PORT
      LAYER M5 ;
        RECT  47.28 103.572 47.304 103.656 ;
    END
  END a_d[367]
  PIN a_d[368]
    DIRECTION INPUT ;
    USE SIGNAL ;
    PORT
      LAYER M5 ;
        RECT  47.376 103.572 47.4 103.656 ;
    END
  END a_d[368]
  PIN a_d[369]
    DIRECTION INPUT ;
    USE SIGNAL ;
    PORT
      LAYER M5 ;
        RECT  47.472 103.572 47.496 103.656 ;
    END
  END a_d[369]
  PIN a_d[36]
    DIRECTION INPUT ;
    USE SIGNAL ;
    PORT
      LAYER M5 ;
        RECT  30.096 103.572 30.12 103.656 ;
    END
  END a_d[36]
  PIN a_d[370]
    DIRECTION INPUT ;
    USE SIGNAL ;
    PORT
      LAYER M5 ;
        RECT  47.568 103.572 47.592 103.656 ;
    END
  END a_d[370]
  PIN a_d[371]
    DIRECTION INPUT ;
    USE SIGNAL ;
    PORT
      LAYER M5 ;
        RECT  47.664 103.572 47.688 103.656 ;
    END
  END a_d[371]
  PIN a_d[372]
    DIRECTION INPUT ;
    USE SIGNAL ;
    PORT
      LAYER M5 ;
        RECT  47.76 103.572 47.784 103.656 ;
    END
  END a_d[372]
  PIN a_d[373]
    DIRECTION INPUT ;
    USE SIGNAL ;
    PORT
      LAYER M5 ;
        RECT  47.856 103.572 47.88 103.656 ;
    END
  END a_d[373]
  PIN a_d[374]
    DIRECTION INPUT ;
    USE SIGNAL ;
    PORT
      LAYER M5 ;
        RECT  47.952 103.572 47.976 103.656 ;
    END
  END a_d[374]
  PIN a_d[375]
    DIRECTION INPUT ;
    USE SIGNAL ;
    PORT
      LAYER M5 ;
        RECT  48.048 103.572 48.072 103.656 ;
    END
  END a_d[375]
  PIN a_d[376]
    DIRECTION INPUT ;
    USE SIGNAL ;
    PORT
      LAYER M5 ;
        RECT  48.144 103.572 48.168 103.656 ;
    END
  END a_d[376]
  PIN a_d[377]
    DIRECTION INPUT ;
    USE SIGNAL ;
    PORT
      LAYER M5 ;
        RECT  48.24 103.572 48.264 103.656 ;
    END
  END a_d[377]
  PIN a_d[378]
    DIRECTION INPUT ;
    USE SIGNAL ;
    PORT
      LAYER M5 ;
        RECT  48.336 103.572 48.36 103.656 ;
    END
  END a_d[378]
  PIN a_d[379]
    DIRECTION INPUT ;
    USE SIGNAL ;
    PORT
      LAYER M5 ;
        RECT  48.432 103.572 48.456 103.656 ;
    END
  END a_d[379]
  PIN a_d[37]
    DIRECTION INPUT ;
    USE SIGNAL ;
    PORT
      LAYER M5 ;
        RECT  30.192 103.572 30.216 103.656 ;
    END
  END a_d[37]
  PIN a_d[380]
    DIRECTION INPUT ;
    USE SIGNAL ;
    PORT
      LAYER M5 ;
        RECT  48.528 103.572 48.552 103.656 ;
    END
  END a_d[380]
  PIN a_d[381]
    DIRECTION INPUT ;
    USE SIGNAL ;
    PORT
      LAYER M5 ;
        RECT  48.624 103.572 48.648 103.656 ;
    END
  END a_d[381]
  PIN a_d[382]
    DIRECTION INPUT ;
    USE SIGNAL ;
    PORT
      LAYER M5 ;
        RECT  48.72 103.572 48.744 103.656 ;
    END
  END a_d[382]
  PIN a_d[383]
    DIRECTION INPUT ;
    USE SIGNAL ;
    PORT
      LAYER M5 ;
        RECT  48.816 103.572 48.84 103.656 ;
    END
  END a_d[383]
  PIN a_d[384]
    DIRECTION INPUT ;
    USE SIGNAL ;
    PORT
      LAYER M5 ;
        RECT  36.624 103.572 36.648 103.656 ;
    END
  END a_d[384]
  PIN a_d[385]
    DIRECTION INPUT ;
    USE SIGNAL ;
    PORT
      LAYER M5 ;
        RECT  36.72 103.572 36.744 103.656 ;
    END
  END a_d[385]
  PIN a_d[386]
    DIRECTION INPUT ;
    USE SIGNAL ;
    PORT
      LAYER M5 ;
        RECT  36.816 103.572 36.84 103.656 ;
    END
  END a_d[386]
  PIN a_d[387]
    DIRECTION INPUT ;
    USE SIGNAL ;
    PORT
      LAYER M5 ;
        RECT  36.912 103.572 36.936 103.656 ;
    END
  END a_d[387]
  PIN a_d[388]
    DIRECTION INPUT ;
    USE SIGNAL ;
    PORT
      LAYER M5 ;
        RECT  37.008 103.572 37.032 103.656 ;
    END
  END a_d[388]
  PIN a_d[389]
    DIRECTION INPUT ;
    USE SIGNAL ;
    PORT
      LAYER M5 ;
        RECT  37.104 103.572 37.128 103.656 ;
    END
  END a_d[389]
  PIN a_d[38]
    DIRECTION INPUT ;
    USE SIGNAL ;
    PORT
      LAYER M5 ;
        RECT  30.288 103.572 30.312 103.656 ;
    END
  END a_d[38]
  PIN a_d[390]
    DIRECTION INPUT ;
    USE SIGNAL ;
    PORT
      LAYER M5 ;
        RECT  37.2 103.572 37.224 103.656 ;
    END
  END a_d[390]
  PIN a_d[391]
    DIRECTION INPUT ;
    USE SIGNAL ;
    PORT
      LAYER M5 ;
        RECT  37.296 103.572 37.32 103.656 ;
    END
  END a_d[391]
  PIN a_d[392]
    DIRECTION INPUT ;
    USE SIGNAL ;
    PORT
      LAYER M5 ;
        RECT  37.392 103.572 37.416 103.656 ;
    END
  END a_d[392]
  PIN a_d[393]
    DIRECTION INPUT ;
    USE SIGNAL ;
    PORT
      LAYER M5 ;
        RECT  37.488 103.572 37.512 103.656 ;
    END
  END a_d[393]
  PIN a_d[394]
    DIRECTION INPUT ;
    USE SIGNAL ;
    PORT
      LAYER M5 ;
        RECT  37.584 103.572 37.608 103.656 ;
    END
  END a_d[394]
  PIN a_d[395]
    DIRECTION INPUT ;
    USE SIGNAL ;
    PORT
      LAYER M5 ;
        RECT  37.68 103.572 37.704 103.656 ;
    END
  END a_d[395]
  PIN a_d[396]
    DIRECTION INPUT ;
    USE SIGNAL ;
    PORT
      LAYER M5 ;
        RECT  37.776 103.572 37.8 103.656 ;
    END
  END a_d[396]
  PIN a_d[397]
    DIRECTION INPUT ;
    USE SIGNAL ;
    PORT
      LAYER M5 ;
        RECT  37.872 103.572 37.896 103.656 ;
    END
  END a_d[397]
  PIN a_d[398]
    DIRECTION INPUT ;
    USE SIGNAL ;
    PORT
      LAYER M5 ;
        RECT  37.968 103.572 37.992 103.656 ;
    END
  END a_d[398]
  PIN a_d[399]
    DIRECTION INPUT ;
    USE SIGNAL ;
    PORT
      LAYER M5 ;
        RECT  38.064 103.572 38.088 103.656 ;
    END
  END a_d[399]
  PIN a_d[39]
    DIRECTION INPUT ;
    USE SIGNAL ;
    PORT
      LAYER M5 ;
        RECT  30.384 103.572 30.408 103.656 ;
    END
  END a_d[39]
  PIN a_d[3]
    DIRECTION INPUT ;
    USE SIGNAL ;
    PORT
      LAYER M5 ;
        RECT  20.784 103.572 20.808 103.656 ;
    END
  END a_d[3]
  PIN a_d[400]
    DIRECTION INPUT ;
    USE SIGNAL ;
    PORT
      LAYER M5 ;
        RECT  38.16 103.572 38.184 103.656 ;
    END
  END a_d[400]
  PIN a_d[401]
    DIRECTION INPUT ;
    USE SIGNAL ;
    PORT
      LAYER M5 ;
        RECT  38.256 103.572 38.28 103.656 ;
    END
  END a_d[401]
  PIN a_d[402]
    DIRECTION INPUT ;
    USE SIGNAL ;
    PORT
      LAYER M5 ;
        RECT  38.352 103.572 38.376 103.656 ;
    END
  END a_d[402]
  PIN a_d[403]
    DIRECTION INPUT ;
    USE SIGNAL ;
    PORT
      LAYER M5 ;
        RECT  38.448 103.572 38.472 103.656 ;
    END
  END a_d[403]
  PIN a_d[404]
    DIRECTION INPUT ;
    USE SIGNAL ;
    PORT
      LAYER M5 ;
        RECT  38.544 103.572 38.568 103.656 ;
    END
  END a_d[404]
  PIN a_d[405]
    DIRECTION INPUT ;
    USE SIGNAL ;
    PORT
      LAYER M5 ;
        RECT  38.64 103.572 38.664 103.656 ;
    END
  END a_d[405]
  PIN a_d[406]
    DIRECTION INPUT ;
    USE SIGNAL ;
    PORT
      LAYER M5 ;
        RECT  38.736 103.572 38.76 103.656 ;
    END
  END a_d[406]
  PIN a_d[407]
    DIRECTION INPUT ;
    USE SIGNAL ;
    PORT
      LAYER M5 ;
        RECT  38.832 103.572 38.856 103.656 ;
    END
  END a_d[407]
  PIN a_d[408]
    DIRECTION INPUT ;
    USE SIGNAL ;
    PORT
      LAYER M5 ;
        RECT  38.928 103.572 38.952 103.656 ;
    END
  END a_d[408]
  PIN a_d[409]
    DIRECTION INPUT ;
    USE SIGNAL ;
    PORT
      LAYER M5 ;
        RECT  39.024 103.572 39.048 103.656 ;
    END
  END a_d[409]
  PIN a_d[40]
    DIRECTION INPUT ;
    USE SIGNAL ;
    PORT
      LAYER M5 ;
        RECT  30.48 103.572 30.504 103.656 ;
    END
  END a_d[40]
  PIN a_d[410]
    DIRECTION INPUT ;
    USE SIGNAL ;
    PORT
      LAYER M5 ;
        RECT  39.12 103.572 39.144 103.656 ;
    END
  END a_d[410]
  PIN a_d[411]
    DIRECTION INPUT ;
    USE SIGNAL ;
    PORT
      LAYER M5 ;
        RECT  39.216 103.572 39.24 103.656 ;
    END
  END a_d[411]
  PIN a_d[412]
    DIRECTION INPUT ;
    USE SIGNAL ;
    PORT
      LAYER M5 ;
        RECT  39.312 103.572 39.336 103.656 ;
    END
  END a_d[412]
  PIN a_d[413]
    DIRECTION INPUT ;
    USE SIGNAL ;
    PORT
      LAYER M5 ;
        RECT  39.408 103.572 39.432 103.656 ;
    END
  END a_d[413]
  PIN a_d[414]
    DIRECTION INPUT ;
    USE SIGNAL ;
    PORT
      LAYER M5 ;
        RECT  39.504 103.572 39.528 103.656 ;
    END
  END a_d[414]
  PIN a_d[415]
    DIRECTION INPUT ;
    USE SIGNAL ;
    PORT
      LAYER M5 ;
        RECT  39.6 103.572 39.624 103.656 ;
    END
  END a_d[415]
  PIN a_d[416]
    DIRECTION INPUT ;
    USE SIGNAL ;
    PORT
      LAYER M5 ;
        RECT  7.44 103.572 7.464 103.656 ;
    END
  END a_d[416]
  PIN a_d[417]
    DIRECTION INPUT ;
    USE SIGNAL ;
    PORT
      LAYER M5 ;
        RECT  7.536 103.572 7.56 103.656 ;
    END
  END a_d[417]
  PIN a_d[418]
    DIRECTION INPUT ;
    USE SIGNAL ;
    PORT
      LAYER M5 ;
        RECT  7.632 103.572 7.656 103.656 ;
    END
  END a_d[418]
  PIN a_d[419]
    DIRECTION INPUT ;
    USE SIGNAL ;
    PORT
      LAYER M5 ;
        RECT  7.728 103.572 7.752 103.656 ;
    END
  END a_d[419]
  PIN a_d[41]
    DIRECTION INPUT ;
    USE SIGNAL ;
    PORT
      LAYER M5 ;
        RECT  30.576 103.572 30.6 103.656 ;
    END
  END a_d[41]
  PIN a_d[420]
    DIRECTION INPUT ;
    USE SIGNAL ;
    PORT
      LAYER M5 ;
        RECT  7.824 103.572 7.848 103.656 ;
    END
  END a_d[420]
  PIN a_d[421]
    DIRECTION INPUT ;
    USE SIGNAL ;
    PORT
      LAYER M5 ;
        RECT  7.92 103.572 7.944 103.656 ;
    END
  END a_d[421]
  PIN a_d[422]
    DIRECTION INPUT ;
    USE SIGNAL ;
    PORT
      LAYER M5 ;
        RECT  8.016 103.572 8.04 103.656 ;
    END
  END a_d[422]
  PIN a_d[423]
    DIRECTION INPUT ;
    USE SIGNAL ;
    PORT
      LAYER M5 ;
        RECT  8.112 103.572 8.136 103.656 ;
    END
  END a_d[423]
  PIN a_d[424]
    DIRECTION INPUT ;
    USE SIGNAL ;
    PORT
      LAYER M5 ;
        RECT  8.208 103.572 8.232 103.656 ;
    END
  END a_d[424]
  PIN a_d[425]
    DIRECTION INPUT ;
    USE SIGNAL ;
    PORT
      LAYER M5 ;
        RECT  8.304 103.572 8.328 103.656 ;
    END
  END a_d[425]
  PIN a_d[426]
    DIRECTION INPUT ;
    USE SIGNAL ;
    PORT
      LAYER M5 ;
        RECT  8.4 103.572 8.424 103.656 ;
    END
  END a_d[426]
  PIN a_d[427]
    DIRECTION INPUT ;
    USE SIGNAL ;
    PORT
      LAYER M5 ;
        RECT  8.496 103.572 8.52 103.656 ;
    END
  END a_d[427]
  PIN a_d[428]
    DIRECTION INPUT ;
    USE SIGNAL ;
    PORT
      LAYER M5 ;
        RECT  8.592 103.572 8.616 103.656 ;
    END
  END a_d[428]
  PIN a_d[429]
    DIRECTION INPUT ;
    USE SIGNAL ;
    PORT
      LAYER M5 ;
        RECT  8.688 103.572 8.712 103.656 ;
    END
  END a_d[429]
  PIN a_d[42]
    DIRECTION INPUT ;
    USE SIGNAL ;
    PORT
      LAYER M5 ;
        RECT  30.672 103.572 30.696 103.656 ;
    END
  END a_d[42]
  PIN a_d[430]
    DIRECTION INPUT ;
    USE SIGNAL ;
    PORT
      LAYER M5 ;
        RECT  8.784 103.572 8.808 103.656 ;
    END
  END a_d[430]
  PIN a_d[431]
    DIRECTION INPUT ;
    USE SIGNAL ;
    PORT
      LAYER M5 ;
        RECT  8.88 103.572 8.904 103.656 ;
    END
  END a_d[431]
  PIN a_d[432]
    DIRECTION INPUT ;
    USE SIGNAL ;
    PORT
      LAYER M5 ;
        RECT  8.976 103.572 9 103.656 ;
    END
  END a_d[432]
  PIN a_d[433]
    DIRECTION INPUT ;
    USE SIGNAL ;
    PORT
      LAYER M5 ;
        RECT  9.072 103.572 9.096 103.656 ;
    END
  END a_d[433]
  PIN a_d[434]
    DIRECTION INPUT ;
    USE SIGNAL ;
    PORT
      LAYER M5 ;
        RECT  9.168 103.572 9.192 103.656 ;
    END
  END a_d[434]
  PIN a_d[435]
    DIRECTION INPUT ;
    USE SIGNAL ;
    PORT
      LAYER M5 ;
        RECT  9.264 103.572 9.288 103.656 ;
    END
  END a_d[435]
  PIN a_d[436]
    DIRECTION INPUT ;
    USE SIGNAL ;
    PORT
      LAYER M5 ;
        RECT  9.36 103.572 9.384 103.656 ;
    END
  END a_d[436]
  PIN a_d[437]
    DIRECTION INPUT ;
    USE SIGNAL ;
    PORT
      LAYER M5 ;
        RECT  9.456 103.572 9.48 103.656 ;
    END
  END a_d[437]
  PIN a_d[438]
    DIRECTION INPUT ;
    USE SIGNAL ;
    PORT
      LAYER M5 ;
        RECT  9.552 103.572 9.576 103.656 ;
    END
  END a_d[438]
  PIN a_d[439]
    DIRECTION INPUT ;
    USE SIGNAL ;
    PORT
      LAYER M5 ;
        RECT  9.648 103.572 9.672 103.656 ;
    END
  END a_d[439]
  PIN a_d[43]
    DIRECTION INPUT ;
    USE SIGNAL ;
    PORT
      LAYER M5 ;
        RECT  30.768 103.572 30.792 103.656 ;
    END
  END a_d[43]
  PIN a_d[440]
    DIRECTION INPUT ;
    USE SIGNAL ;
    PORT
      LAYER M5 ;
        RECT  9.744 103.572 9.768 103.656 ;
    END
  END a_d[440]
  PIN a_d[441]
    DIRECTION INPUT ;
    USE SIGNAL ;
    PORT
      LAYER M5 ;
        RECT  9.84 103.572 9.864 103.656 ;
    END
  END a_d[441]
  PIN a_d[442]
    DIRECTION INPUT ;
    USE SIGNAL ;
    PORT
      LAYER M5 ;
        RECT  9.936 103.572 9.96 103.656 ;
    END
  END a_d[442]
  PIN a_d[443]
    DIRECTION INPUT ;
    USE SIGNAL ;
    PORT
      LAYER M5 ;
        RECT  10.032 103.572 10.056 103.656 ;
    END
  END a_d[443]
  PIN a_d[444]
    DIRECTION INPUT ;
    USE SIGNAL ;
    PORT
      LAYER M5 ;
        RECT  10.128 103.572 10.152 103.656 ;
    END
  END a_d[444]
  PIN a_d[445]
    DIRECTION INPUT ;
    USE SIGNAL ;
    PORT
      LAYER M5 ;
        RECT  10.224 103.572 10.248 103.656 ;
    END
  END a_d[445]
  PIN a_d[446]
    DIRECTION INPUT ;
    USE SIGNAL ;
    PORT
      LAYER M5 ;
        RECT  10.32 103.572 10.344 103.656 ;
    END
  END a_d[446]
  PIN a_d[447]
    DIRECTION INPUT ;
    USE SIGNAL ;
    PORT
      LAYER M5 ;
        RECT  10.416 103.572 10.44 103.656 ;
    END
  END a_d[447]
  PIN a_d[448]
    DIRECTION INPUT ;
    USE SIGNAL ;
    PORT
      LAYER M5 ;
        RECT  10.512 103.572 10.536 103.656 ;
    END
  END a_d[448]
  PIN a_d[449]
    DIRECTION INPUT ;
    USE SIGNAL ;
    PORT
      LAYER M5 ;
        RECT  10.608 103.572 10.632 103.656 ;
    END
  END a_d[449]
  PIN a_d[44]
    DIRECTION INPUT ;
    USE SIGNAL ;
    PORT
      LAYER M5 ;
        RECT  30.864 103.572 30.888 103.656 ;
    END
  END a_d[44]
  PIN a_d[450]
    DIRECTION INPUT ;
    USE SIGNAL ;
    PORT
      LAYER M5 ;
        RECT  10.704 103.572 10.728 103.656 ;
    END
  END a_d[450]
  PIN a_d[451]
    DIRECTION INPUT ;
    USE SIGNAL ;
    PORT
      LAYER M5 ;
        RECT  10.8 103.572 10.824 103.656 ;
    END
  END a_d[451]
  PIN a_d[452]
    DIRECTION INPUT ;
    USE SIGNAL ;
    PORT
      LAYER M5 ;
        RECT  10.896 103.572 10.92 103.656 ;
    END
  END a_d[452]
  PIN a_d[453]
    DIRECTION INPUT ;
    USE SIGNAL ;
    PORT
      LAYER M5 ;
        RECT  10.992 103.572 11.016 103.656 ;
    END
  END a_d[453]
  PIN a_d[454]
    DIRECTION INPUT ;
    USE SIGNAL ;
    PORT
      LAYER M5 ;
        RECT  11.088 103.572 11.112 103.656 ;
    END
  END a_d[454]
  PIN a_d[455]
    DIRECTION INPUT ;
    USE SIGNAL ;
    PORT
      LAYER M5 ;
        RECT  11.184 103.572 11.208 103.656 ;
    END
  END a_d[455]
  PIN a_d[456]
    DIRECTION INPUT ;
    USE SIGNAL ;
    PORT
      LAYER M5 ;
        RECT  11.28 103.572 11.304 103.656 ;
    END
  END a_d[456]
  PIN a_d[457]
    DIRECTION INPUT ;
    USE SIGNAL ;
    PORT
      LAYER M5 ;
        RECT  11.376 103.572 11.4 103.656 ;
    END
  END a_d[457]
  PIN a_d[458]
    DIRECTION INPUT ;
    USE SIGNAL ;
    PORT
      LAYER M5 ;
        RECT  11.472 103.572 11.496 103.656 ;
    END
  END a_d[458]
  PIN a_d[459]
    DIRECTION INPUT ;
    USE SIGNAL ;
    PORT
      LAYER M5 ;
        RECT  11.568 103.572 11.592 103.656 ;
    END
  END a_d[459]
  PIN a_d[45]
    DIRECTION INPUT ;
    USE SIGNAL ;
    PORT
      LAYER M5 ;
        RECT  30.96 103.572 30.984 103.656 ;
    END
  END a_d[45]
  PIN a_d[460]
    DIRECTION INPUT ;
    USE SIGNAL ;
    PORT
      LAYER M5 ;
        RECT  11.664 103.572 11.688 103.656 ;
    END
  END a_d[460]
  PIN a_d[461]
    DIRECTION INPUT ;
    USE SIGNAL ;
    PORT
      LAYER M5 ;
        RECT  11.76 103.572 11.784 103.656 ;
    END
  END a_d[461]
  PIN a_d[462]
    DIRECTION INPUT ;
    USE SIGNAL ;
    PORT
      LAYER M5 ;
        RECT  11.856 103.572 11.88 103.656 ;
    END
  END a_d[462]
  PIN a_d[463]
    DIRECTION INPUT ;
    USE SIGNAL ;
    PORT
      LAYER M5 ;
        RECT  11.952 103.572 11.976 103.656 ;
    END
  END a_d[463]
  PIN a_d[464]
    DIRECTION INPUT ;
    USE SIGNAL ;
    PORT
      LAYER M5 ;
        RECT  12.048 103.572 12.072 103.656 ;
    END
  END a_d[464]
  PIN a_d[465]
    DIRECTION INPUT ;
    USE SIGNAL ;
    PORT
      LAYER M5 ;
        RECT  12.144 103.572 12.168 103.656 ;
    END
  END a_d[465]
  PIN a_d[466]
    DIRECTION INPUT ;
    USE SIGNAL ;
    PORT
      LAYER M5 ;
        RECT  12.24 103.572 12.264 103.656 ;
    END
  END a_d[466]
  PIN a_d[467]
    DIRECTION INPUT ;
    USE SIGNAL ;
    PORT
      LAYER M5 ;
        RECT  12.336 103.572 12.36 103.656 ;
    END
  END a_d[467]
  PIN a_d[468]
    DIRECTION INPUT ;
    USE SIGNAL ;
    PORT
      LAYER M5 ;
        RECT  12.432 103.572 12.456 103.656 ;
    END
  END a_d[468]
  PIN a_d[469]
    DIRECTION INPUT ;
    USE SIGNAL ;
    PORT
      LAYER M5 ;
        RECT  12.528 103.572 12.552 103.656 ;
    END
  END a_d[469]
  PIN a_d[46]
    DIRECTION INPUT ;
    USE SIGNAL ;
    PORT
      LAYER M5 ;
        RECT  31.056 103.572 31.08 103.656 ;
    END
  END a_d[46]
  PIN a_d[470]
    DIRECTION INPUT ;
    USE SIGNAL ;
    PORT
      LAYER M5 ;
        RECT  12.624 103.572 12.648 103.656 ;
    END
  END a_d[470]
  PIN a_d[471]
    DIRECTION INPUT ;
    USE SIGNAL ;
    PORT
      LAYER M5 ;
        RECT  12.72 103.572 12.744 103.656 ;
    END
  END a_d[471]
  PIN a_d[472]
    DIRECTION INPUT ;
    USE SIGNAL ;
    PORT
      LAYER M5 ;
        RECT  12.816 103.572 12.84 103.656 ;
    END
  END a_d[472]
  PIN a_d[473]
    DIRECTION INPUT ;
    USE SIGNAL ;
    PORT
      LAYER M5 ;
        RECT  12.912 103.572 12.936 103.656 ;
    END
  END a_d[473]
  PIN a_d[474]
    DIRECTION INPUT ;
    USE SIGNAL ;
    PORT
      LAYER M5 ;
        RECT  13.008 103.572 13.032 103.656 ;
    END
  END a_d[474]
  PIN a_d[475]
    DIRECTION INPUT ;
    USE SIGNAL ;
    PORT
      LAYER M5 ;
        RECT  13.104 103.572 13.128 103.656 ;
    END
  END a_d[475]
  PIN a_d[476]
    DIRECTION INPUT ;
    USE SIGNAL ;
    PORT
      LAYER M5 ;
        RECT  13.2 103.572 13.224 103.656 ;
    END
  END a_d[476]
  PIN a_d[477]
    DIRECTION INPUT ;
    USE SIGNAL ;
    PORT
      LAYER M5 ;
        RECT  13.296 103.572 13.32 103.656 ;
    END
  END a_d[477]
  PIN a_d[478]
    DIRECTION INPUT ;
    USE SIGNAL ;
    PORT
      LAYER M5 ;
        RECT  13.392 103.572 13.416 103.656 ;
    END
  END a_d[478]
  PIN a_d[479]
    DIRECTION INPUT ;
    USE SIGNAL ;
    PORT
      LAYER M5 ;
        RECT  13.488 103.572 13.512 103.656 ;
    END
  END a_d[479]
  PIN a_d[47]
    DIRECTION INPUT ;
    USE SIGNAL ;
    PORT
      LAYER M5 ;
        RECT  31.152 103.572 31.176 103.656 ;
    END
  END a_d[47]
  PIN a_d[480]
    DIRECTION INPUT ;
    USE SIGNAL ;
    PORT
      LAYER M5 ;
        RECT  1.392 103.572 1.416 103.656 ;
    END
  END a_d[480]
  PIN a_d[481]
    DIRECTION INPUT ;
    USE SIGNAL ;
    PORT
      LAYER M5 ;
        RECT  1.488 103.572 1.512 103.656 ;
    END
  END a_d[481]
  PIN a_d[482]
    DIRECTION INPUT ;
    USE SIGNAL ;
    PORT
      LAYER M5 ;
        RECT  1.584 103.572 1.608 103.656 ;
    END
  END a_d[482]
  PIN a_d[483]
    DIRECTION INPUT ;
    USE SIGNAL ;
    PORT
      LAYER M5 ;
        RECT  1.68 103.572 1.704 103.656 ;
    END
  END a_d[483]
  PIN a_d[484]
    DIRECTION INPUT ;
    USE SIGNAL ;
    PORT
      LAYER M5 ;
        RECT  1.776 103.572 1.8 103.656 ;
    END
  END a_d[484]
  PIN a_d[485]
    DIRECTION INPUT ;
    USE SIGNAL ;
    PORT
      LAYER M5 ;
        RECT  1.872 103.572 1.896 103.656 ;
    END
  END a_d[485]
  PIN a_d[486]
    DIRECTION INPUT ;
    USE SIGNAL ;
    PORT
      LAYER M5 ;
        RECT  1.968 103.572 1.992 103.656 ;
    END
  END a_d[486]
  PIN a_d[487]
    DIRECTION INPUT ;
    USE SIGNAL ;
    PORT
      LAYER M5 ;
        RECT  2.064 103.572 2.088 103.656 ;
    END
  END a_d[487]
  PIN a_d[488]
    DIRECTION INPUT ;
    USE SIGNAL ;
    PORT
      LAYER M5 ;
        RECT  2.16 103.572 2.184 103.656 ;
    END
  END a_d[488]
  PIN a_d[489]
    DIRECTION INPUT ;
    USE SIGNAL ;
    PORT
      LAYER M5 ;
        RECT  2.256 103.572 2.28 103.656 ;
    END
  END a_d[489]
  PIN a_d[48]
    DIRECTION INPUT ;
    USE SIGNAL ;
    PORT
      LAYER M5 ;
        RECT  31.248 103.572 31.272 103.656 ;
    END
  END a_d[48]
  PIN a_d[490]
    DIRECTION INPUT ;
    USE SIGNAL ;
    PORT
      LAYER M5 ;
        RECT  2.352 103.572 2.376 103.656 ;
    END
  END a_d[490]
  PIN a_d[491]
    DIRECTION INPUT ;
    USE SIGNAL ;
    PORT
      LAYER M5 ;
        RECT  2.448 103.572 2.472 103.656 ;
    END
  END a_d[491]
  PIN a_d[492]
    DIRECTION INPUT ;
    USE SIGNAL ;
    PORT
      LAYER M5 ;
        RECT  2.544 103.572 2.568 103.656 ;
    END
  END a_d[492]
  PIN a_d[493]
    DIRECTION INPUT ;
    USE SIGNAL ;
    PORT
      LAYER M5 ;
        RECT  2.64 103.572 2.664 103.656 ;
    END
  END a_d[493]
  PIN a_d[494]
    DIRECTION INPUT ;
    USE SIGNAL ;
    PORT
      LAYER M5 ;
        RECT  2.736 103.572 2.76 103.656 ;
    END
  END a_d[494]
  PIN a_d[495]
    DIRECTION INPUT ;
    USE SIGNAL ;
    PORT
      LAYER M5 ;
        RECT  2.832 103.572 2.856 103.656 ;
    END
  END a_d[495]
  PIN a_d[496]
    DIRECTION INPUT ;
    USE SIGNAL ;
    PORT
      LAYER M5 ;
        RECT  2.928 103.572 2.952 103.656 ;
    END
  END a_d[496]
  PIN a_d[497]
    DIRECTION INPUT ;
    USE SIGNAL ;
    PORT
      LAYER M5 ;
        RECT  3.024 103.572 3.048 103.656 ;
    END
  END a_d[497]
  PIN a_d[498]
    DIRECTION INPUT ;
    USE SIGNAL ;
    PORT
      LAYER M5 ;
        RECT  3.12 103.572 3.144 103.656 ;
    END
  END a_d[498]
  PIN a_d[499]
    DIRECTION INPUT ;
    USE SIGNAL ;
    PORT
      LAYER M5 ;
        RECT  3.216 103.572 3.24 103.656 ;
    END
  END a_d[499]
  PIN a_d[49]
    DIRECTION INPUT ;
    USE SIGNAL ;
    PORT
      LAYER M5 ;
        RECT  31.344 103.572 31.368 103.656 ;
    END
  END a_d[49]
  PIN a_d[4]
    DIRECTION INPUT ;
    USE SIGNAL ;
    PORT
      LAYER M5 ;
        RECT  20.88 103.572 20.904 103.656 ;
    END
  END a_d[4]
  PIN a_d[500]
    DIRECTION INPUT ;
    USE SIGNAL ;
    PORT
      LAYER M5 ;
        RECT  3.312 103.572 3.336 103.656 ;
    END
  END a_d[500]
  PIN a_d[501]
    DIRECTION INPUT ;
    USE SIGNAL ;
    PORT
      LAYER M5 ;
        RECT  3.408 103.572 3.432 103.656 ;
    END
  END a_d[501]
  PIN a_d[502]
    DIRECTION INPUT ;
    USE SIGNAL ;
    PORT
      LAYER M5 ;
        RECT  3.504 103.572 3.528 103.656 ;
    END
  END a_d[502]
  PIN a_d[503]
    DIRECTION INPUT ;
    USE SIGNAL ;
    PORT
      LAYER M5 ;
        RECT  3.6 103.572 3.624 103.656 ;
    END
  END a_d[503]
  PIN a_d[504]
    DIRECTION INPUT ;
    USE SIGNAL ;
    PORT
      LAYER M5 ;
        RECT  3.696 103.572 3.72 103.656 ;
    END
  END a_d[504]
  PIN a_d[505]
    DIRECTION INPUT ;
    USE SIGNAL ;
    PORT
      LAYER M5 ;
        RECT  3.792 103.572 3.816 103.656 ;
    END
  END a_d[505]
  PIN a_d[506]
    DIRECTION INPUT ;
    USE SIGNAL ;
    PORT
      LAYER M5 ;
        RECT  3.888 103.572 3.912 103.656 ;
    END
  END a_d[506]
  PIN a_d[507]
    DIRECTION INPUT ;
    USE SIGNAL ;
    PORT
      LAYER M5 ;
        RECT  3.984 103.572 4.008 103.656 ;
    END
  END a_d[507]
  PIN a_d[50]
    DIRECTION INPUT ;
    USE SIGNAL ;
    PORT
      LAYER M5 ;
        RECT  31.44 103.572 31.464 103.656 ;
    END
  END a_d[50]
  PIN a_d[51]
    DIRECTION INPUT ;
    USE SIGNAL ;
    PORT
      LAYER M5 ;
        RECT  31.536 103.572 31.56 103.656 ;
    END
  END a_d[51]
  PIN a_d[52]
    DIRECTION INPUT ;
    USE SIGNAL ;
    PORT
      LAYER M5 ;
        RECT  31.632 103.572 31.656 103.656 ;
    END
  END a_d[52]
  PIN a_d[53]
    DIRECTION INPUT ;
    USE SIGNAL ;
    PORT
      LAYER M5 ;
        RECT  31.728 103.572 31.752 103.656 ;
    END
  END a_d[53]
  PIN a_d[54]
    DIRECTION INPUT ;
    USE SIGNAL ;
    PORT
      LAYER M5 ;
        RECT  31.824 103.572 31.848 103.656 ;
    END
  END a_d[54]
  PIN a_d[55]
    DIRECTION INPUT ;
    USE SIGNAL ;
    PORT
      LAYER M5 ;
        RECT  31.92 103.572 31.944 103.656 ;
    END
  END a_d[55]
  PIN a_d[56]
    DIRECTION INPUT ;
    USE SIGNAL ;
    PORT
      LAYER M5 ;
        RECT  32.016 103.572 32.04 103.656 ;
    END
  END a_d[56]
  PIN a_d[57]
    DIRECTION INPUT ;
    USE SIGNAL ;
    PORT
      LAYER M5 ;
        RECT  32.112 103.572 32.136 103.656 ;
    END
  END a_d[57]
  PIN a_d[58]
    DIRECTION INPUT ;
    USE SIGNAL ;
    PORT
      LAYER M5 ;
        RECT  32.208 103.572 32.232 103.656 ;
    END
  END a_d[58]
  PIN a_d[59]
    DIRECTION INPUT ;
    USE SIGNAL ;
    PORT
      LAYER M5 ;
        RECT  32.304 103.572 32.328 103.656 ;
    END
  END a_d[59]
  PIN a_d[5]
    DIRECTION INPUT ;
    USE SIGNAL ;
    PORT
      LAYER M5 ;
        RECT  20.976 103.572 21 103.656 ;
    END
  END a_d[5]
  PIN a_d[60]
    DIRECTION INPUT ;
    USE SIGNAL ;
    PORT
      LAYER M5 ;
        RECT  32.4 103.572 32.424 103.656 ;
    END
  END a_d[60]
  PIN a_d[61]
    DIRECTION INPUT ;
    USE SIGNAL ;
    PORT
      LAYER M5 ;
        RECT  32.496 103.572 32.52 103.656 ;
    END
  END a_d[61]
  PIN a_d[62]
    DIRECTION INPUT ;
    USE SIGNAL ;
    PORT
      LAYER M5 ;
        RECT  32.592 103.572 32.616 103.656 ;
    END
  END a_d[62]
  PIN a_d[63]
    DIRECTION INPUT ;
    USE SIGNAL ;
    PORT
      LAYER M5 ;
        RECT  32.688 103.572 32.712 103.656 ;
    END
  END a_d[63]
  PIN a_d[64]
    DIRECTION INPUT ;
    USE SIGNAL ;
    PORT
      LAYER M5 ;
        RECT  26.64 103.572 26.664 103.656 ;
    END
  END a_d[64]
  PIN a_d[65]
    DIRECTION INPUT ;
    USE SIGNAL ;
    PORT
      LAYER M5 ;
        RECT  26.736 103.572 26.76 103.656 ;
    END
  END a_d[65]
  PIN a_d[66]
    DIRECTION INPUT ;
    USE SIGNAL ;
    PORT
      LAYER M5 ;
        RECT  26.832 103.572 26.856 103.656 ;
    END
  END a_d[66]
  PIN a_d[67]
    DIRECTION INPUT ;
    USE SIGNAL ;
    PORT
      LAYER M5 ;
        RECT  26.928 103.572 26.952 103.656 ;
    END
  END a_d[67]
  PIN a_d[68]
    DIRECTION INPUT ;
    USE SIGNAL ;
    PORT
      LAYER M5 ;
        RECT  27.024 103.572 27.048 103.656 ;
    END
  END a_d[68]
  PIN a_d[69]
    DIRECTION INPUT ;
    USE SIGNAL ;
    PORT
      LAYER M5 ;
        RECT  27.12 103.572 27.144 103.656 ;
    END
  END a_d[69]
  PIN a_d[6]
    DIRECTION INPUT ;
    USE SIGNAL ;
    PORT
      LAYER M5 ;
        RECT  21.072 103.572 21.096 103.656 ;
    END
  END a_d[6]
  PIN a_d[70]
    DIRECTION INPUT ;
    USE SIGNAL ;
    PORT
      LAYER M5 ;
        RECT  27.216 103.572 27.24 103.656 ;
    END
  END a_d[70]
  PIN a_d[71]
    DIRECTION INPUT ;
    USE SIGNAL ;
    PORT
      LAYER M5 ;
        RECT  27.312 103.572 27.336 103.656 ;
    END
  END a_d[71]
  PIN a_d[72]
    DIRECTION INPUT ;
    USE SIGNAL ;
    PORT
      LAYER M5 ;
        RECT  27.408 103.572 27.432 103.656 ;
    END
  END a_d[72]
  PIN a_d[73]
    DIRECTION INPUT ;
    USE SIGNAL ;
    PORT
      LAYER M5 ;
        RECT  27.504 103.572 27.528 103.656 ;
    END
  END a_d[73]
  PIN a_d[74]
    DIRECTION INPUT ;
    USE SIGNAL ;
    PORT
      LAYER M5 ;
        RECT  27.6 103.572 27.624 103.656 ;
    END
  END a_d[74]
  PIN a_d[75]
    DIRECTION INPUT ;
    USE SIGNAL ;
    PORT
      LAYER M5 ;
        RECT  27.696 103.572 27.72 103.656 ;
    END
  END a_d[75]
  PIN a_d[76]
    DIRECTION INPUT ;
    USE SIGNAL ;
    PORT
      LAYER M5 ;
        RECT  27.792 103.572 27.816 103.656 ;
    END
  END a_d[76]
  PIN a_d[77]
    DIRECTION INPUT ;
    USE SIGNAL ;
    PORT
      LAYER M5 ;
        RECT  27.888 103.572 27.912 103.656 ;
    END
  END a_d[77]
  PIN a_d[78]
    DIRECTION INPUT ;
    USE SIGNAL ;
    PORT
      LAYER M5 ;
        RECT  27.984 103.572 28.008 103.656 ;
    END
  END a_d[78]
  PIN a_d[79]
    DIRECTION INPUT ;
    USE SIGNAL ;
    PORT
      LAYER M5 ;
        RECT  28.08 103.572 28.104 103.656 ;
    END
  END a_d[79]
  PIN a_d[7]
    DIRECTION INPUT ;
    USE SIGNAL ;
    PORT
      LAYER M5 ;
        RECT  21.168 103.572 21.192 103.656 ;
    END
  END a_d[7]
  PIN a_d[80]
    DIRECTION INPUT ;
    USE SIGNAL ;
    PORT
      LAYER M5 ;
        RECT  28.176 103.572 28.2 103.656 ;
    END
  END a_d[80]
  PIN a_d[81]
    DIRECTION INPUT ;
    USE SIGNAL ;
    PORT
      LAYER M5 ;
        RECT  28.272 103.572 28.296 103.656 ;
    END
  END a_d[81]
  PIN a_d[82]
    DIRECTION INPUT ;
    USE SIGNAL ;
    PORT
      LAYER M5 ;
        RECT  28.368 103.572 28.392 103.656 ;
    END
  END a_d[82]
  PIN a_d[83]
    DIRECTION INPUT ;
    USE SIGNAL ;
    PORT
      LAYER M5 ;
        RECT  28.464 103.572 28.488 103.656 ;
    END
  END a_d[83]
  PIN a_d[84]
    DIRECTION INPUT ;
    USE SIGNAL ;
    PORT
      LAYER M5 ;
        RECT  28.56 103.572 28.584 103.656 ;
    END
  END a_d[84]
  PIN a_d[85]
    DIRECTION INPUT ;
    USE SIGNAL ;
    PORT
      LAYER M5 ;
        RECT  28.656 103.572 28.68 103.656 ;
    END
  END a_d[85]
  PIN a_d[86]
    DIRECTION INPUT ;
    USE SIGNAL ;
    PORT
      LAYER M5 ;
        RECT  28.752 103.572 28.776 103.656 ;
    END
  END a_d[86]
  PIN a_d[87]
    DIRECTION INPUT ;
    USE SIGNAL ;
    PORT
      LAYER M5 ;
        RECT  28.848 103.572 28.872 103.656 ;
    END
  END a_d[87]
  PIN a_d[88]
    DIRECTION INPUT ;
    USE SIGNAL ;
    PORT
      LAYER M5 ;
        RECT  28.944 103.572 28.968 103.656 ;
    END
  END a_d[88]
  PIN a_d[89]
    DIRECTION INPUT ;
    USE SIGNAL ;
    PORT
      LAYER M5 ;
        RECT  29.04 103.572 29.064 103.656 ;
    END
  END a_d[89]
  PIN a_d[8]
    DIRECTION INPUT ;
    USE SIGNAL ;
    PORT
      LAYER M5 ;
        RECT  21.264 103.572 21.288 103.656 ;
    END
  END a_d[8]
  PIN a_d[90]
    DIRECTION INPUT ;
    USE SIGNAL ;
    PORT
      LAYER M5 ;
        RECT  29.136 103.572 29.16 103.656 ;
    END
  END a_d[90]
  PIN a_d[91]
    DIRECTION INPUT ;
    USE SIGNAL ;
    PORT
      LAYER M5 ;
        RECT  29.232 103.572 29.256 103.656 ;
    END
  END a_d[91]
  PIN a_d[92]
    DIRECTION INPUT ;
    USE SIGNAL ;
    PORT
      LAYER M5 ;
        RECT  29.328 103.572 29.352 103.656 ;
    END
  END a_d[92]
  PIN a_d[93]
    DIRECTION INPUT ;
    USE SIGNAL ;
    PORT
      LAYER M5 ;
        RECT  29.424 103.572 29.448 103.656 ;
    END
  END a_d[93]
  PIN a_d[94]
    DIRECTION INPUT ;
    USE SIGNAL ;
    PORT
      LAYER M5 ;
        RECT  29.52 103.572 29.544 103.656 ;
    END
  END a_d[94]
  PIN a_d[95]
    DIRECTION INPUT ;
    USE SIGNAL ;
    PORT
      LAYER M5 ;
        RECT  29.616 103.572 29.64 103.656 ;
    END
  END a_d[95]
  PIN a_d[96]
    DIRECTION INPUT ;
    USE SIGNAL ;
    PORT
      LAYER M5 ;
        RECT  23.568 103.572 23.592 103.656 ;
    END
  END a_d[96]
  PIN a_d[97]
    DIRECTION INPUT ;
    USE SIGNAL ;
    PORT
      LAYER M5 ;
        RECT  23.664 103.572 23.688 103.656 ;
    END
  END a_d[97]
  PIN a_d[98]
    DIRECTION INPUT ;
    USE SIGNAL ;
    PORT
      LAYER M5 ;
        RECT  23.76 103.572 23.784 103.656 ;
    END
  END a_d[98]
  PIN a_d[99]
    DIRECTION INPUT ;
    USE SIGNAL ;
    PORT
      LAYER M5 ;
        RECT  23.856 103.572 23.88 103.656 ;
    END
  END a_d[99]
  PIN a_d[9]
    DIRECTION INPUT ;
    USE SIGNAL ;
    PORT
      LAYER M5 ;
        RECT  21.36 103.572 21.384 103.656 ;
    END
  END a_d[9]
  PIN a_r
    DIRECTION OUTPUT ;
    USE SIGNAL ;
    PORT
      LAYER M5 ;
        RECT  4.08 103.572 4.104 103.656 ;
    END
  END a_r
  PIN b_d[0]
    DIRECTION OUTPUT ;
    USE SIGNAL ;
    PORT
      LAYER M5 ;
        RECT  26.064 0 26.088 0.084 ;
    END
  END b_d[0]
  PIN b_d[100]
    DIRECTION OUTPUT ;
    USE SIGNAL ;
    PORT
      LAYER M5 ;
        RECT  32.592 0 32.616 0.084 ;
    END
  END b_d[100]
  PIN b_d[101]
    DIRECTION OUTPUT ;
    USE SIGNAL ;
    PORT
      LAYER M5 ;
        RECT  32.688 0 32.712 0.084 ;
    END
  END b_d[101]
  PIN b_d[102]
    DIRECTION OUTPUT ;
    USE SIGNAL ;
    PORT
      LAYER M5 ;
        RECT  32.784 0 32.808 0.084 ;
    END
  END b_d[102]
  PIN b_d[103]
    DIRECTION OUTPUT ;
    USE SIGNAL ;
    PORT
      LAYER M5 ;
        RECT  32.88 0 32.904 0.084 ;
    END
  END b_d[103]
  PIN b_d[104]
    DIRECTION OUTPUT ;
    USE SIGNAL ;
    PORT
      LAYER M5 ;
        RECT  32.976 0 33 0.084 ;
    END
  END b_d[104]
  PIN b_d[105]
    DIRECTION OUTPUT ;
    USE SIGNAL ;
    PORT
      LAYER M5 ;
        RECT  33.072 0 33.096 0.084 ;
    END
  END b_d[105]
  PIN b_d[106]
    DIRECTION OUTPUT ;
    USE SIGNAL ;
    PORT
      LAYER M5 ;
        RECT  33.168 0 33.192 0.084 ;
    END
  END b_d[106]
  PIN b_d[107]
    DIRECTION OUTPUT ;
    USE SIGNAL ;
    PORT
      LAYER M5 ;
        RECT  33.264 0 33.288 0.084 ;
    END
  END b_d[107]
  PIN b_d[108]
    DIRECTION OUTPUT ;
    USE SIGNAL ;
    PORT
      LAYER M5 ;
        RECT  33.36 0 33.384 0.084 ;
    END
  END b_d[108]
  PIN b_d[109]
    DIRECTION OUTPUT ;
    USE SIGNAL ;
    PORT
      LAYER M5 ;
        RECT  33.456 0 33.48 0.084 ;
    END
  END b_d[109]
  PIN b_d[10]
    DIRECTION OUTPUT ;
    USE SIGNAL ;
    PORT
      LAYER M5 ;
        RECT  27.024 0 27.048 0.084 ;
    END
  END b_d[10]
  PIN b_d[110]
    DIRECTION OUTPUT ;
    USE SIGNAL ;
    PORT
      LAYER M5 ;
        RECT  33.552 0 33.576 0.084 ;
    END
  END b_d[110]
  PIN b_d[111]
    DIRECTION OUTPUT ;
    USE SIGNAL ;
    PORT
      LAYER M5 ;
        RECT  33.648 0 33.672 0.084 ;
    END
  END b_d[111]
  PIN b_d[112]
    DIRECTION OUTPUT ;
    USE SIGNAL ;
    PORT
      LAYER M5 ;
        RECT  33.744 0 33.768 0.084 ;
    END
  END b_d[112]
  PIN b_d[113]
    DIRECTION OUTPUT ;
    USE SIGNAL ;
    PORT
      LAYER M5 ;
        RECT  33.84 0 33.864 0.084 ;
    END
  END b_d[113]
  PIN b_d[114]
    DIRECTION OUTPUT ;
    USE SIGNAL ;
    PORT
      LAYER M5 ;
        RECT  33.936 0 33.96 0.084 ;
    END
  END b_d[114]
  PIN b_d[115]
    DIRECTION OUTPUT ;
    USE SIGNAL ;
    PORT
      LAYER M5 ;
        RECT  34.032 0 34.056 0.084 ;
    END
  END b_d[115]
  PIN b_d[116]
    DIRECTION OUTPUT ;
    USE SIGNAL ;
    PORT
      LAYER M5 ;
        RECT  34.128 0 34.152 0.084 ;
    END
  END b_d[116]
  PIN b_d[117]
    DIRECTION OUTPUT ;
    USE SIGNAL ;
    PORT
      LAYER M5 ;
        RECT  34.224 0 34.248 0.084 ;
    END
  END b_d[117]
  PIN b_d[118]
    DIRECTION OUTPUT ;
    USE SIGNAL ;
    PORT
      LAYER M5 ;
        RECT  34.32 0 34.344 0.084 ;
    END
  END b_d[118]
  PIN b_d[119]
    DIRECTION OUTPUT ;
    USE SIGNAL ;
    PORT
      LAYER M5 ;
        RECT  34.416 0 34.44 0.084 ;
    END
  END b_d[119]
  PIN b_d[11]
    DIRECTION OUTPUT ;
    USE SIGNAL ;
    PORT
      LAYER M5 ;
        RECT  27.12 0 27.144 0.084 ;
    END
  END b_d[11]
  PIN b_d[120]
    DIRECTION OUTPUT ;
    USE SIGNAL ;
    PORT
      LAYER M5 ;
        RECT  34.512 0 34.536 0.084 ;
    END
  END b_d[120]
  PIN b_d[121]
    DIRECTION OUTPUT ;
    USE SIGNAL ;
    PORT
      LAYER M5 ;
        RECT  34.608 0 34.632 0.084 ;
    END
  END b_d[121]
  PIN b_d[122]
    DIRECTION OUTPUT ;
    USE SIGNAL ;
    PORT
      LAYER M5 ;
        RECT  34.704 0 34.728 0.084 ;
    END
  END b_d[122]
  PIN b_d[123]
    DIRECTION OUTPUT ;
    USE SIGNAL ;
    PORT
      LAYER M5 ;
        RECT  34.8 0 34.824 0.084 ;
    END
  END b_d[123]
  PIN b_d[124]
    DIRECTION OUTPUT ;
    USE SIGNAL ;
    PORT
      LAYER M5 ;
        RECT  34.896 0 34.92 0.084 ;
    END
  END b_d[124]
  PIN b_d[125]
    DIRECTION OUTPUT ;
    USE SIGNAL ;
    PORT
      LAYER M5 ;
        RECT  34.992 0 35.016 0.084 ;
    END
  END b_d[125]
  PIN b_d[126]
    DIRECTION OUTPUT ;
    USE SIGNAL ;
    PORT
      LAYER M5 ;
        RECT  35.088 0 35.112 0.084 ;
    END
  END b_d[126]
  PIN b_d[127]
    DIRECTION OUTPUT ;
    USE SIGNAL ;
    PORT
      LAYER M5 ;
        RECT  35.184 0 35.208 0.084 ;
    END
  END b_d[127]
  PIN b_d[128]
    DIRECTION OUTPUT ;
    USE SIGNAL ;
    PORT
      LAYER M5 ;
        RECT  19.92 0 19.944 0.084 ;
    END
  END b_d[128]
  PIN b_d[129]
    DIRECTION OUTPUT ;
    USE SIGNAL ;
    PORT
      LAYER M5 ;
        RECT  20.016 0 20.04 0.084 ;
    END
  END b_d[129]
  PIN b_d[12]
    DIRECTION OUTPUT ;
    USE SIGNAL ;
    PORT
      LAYER M5 ;
        RECT  27.216 0 27.24 0.084 ;
    END
  END b_d[12]
  PIN b_d[130]
    DIRECTION OUTPUT ;
    USE SIGNAL ;
    PORT
      LAYER M5 ;
        RECT  20.112 0 20.136 0.084 ;
    END
  END b_d[130]
  PIN b_d[131]
    DIRECTION OUTPUT ;
    USE SIGNAL ;
    PORT
      LAYER M5 ;
        RECT  20.208 0 20.232 0.084 ;
    END
  END b_d[131]
  PIN b_d[132]
    DIRECTION OUTPUT ;
    USE SIGNAL ;
    PORT
      LAYER M5 ;
        RECT  20.304 0 20.328 0.084 ;
    END
  END b_d[132]
  PIN b_d[133]
    DIRECTION OUTPUT ;
    USE SIGNAL ;
    PORT
      LAYER M5 ;
        RECT  20.4 0 20.424 0.084 ;
    END
  END b_d[133]
  PIN b_d[134]
    DIRECTION OUTPUT ;
    USE SIGNAL ;
    PORT
      LAYER M5 ;
        RECT  20.496 0 20.52 0.084 ;
    END
  END b_d[134]
  PIN b_d[135]
    DIRECTION OUTPUT ;
    USE SIGNAL ;
    PORT
      LAYER M5 ;
        RECT  20.592 0 20.616 0.084 ;
    END
  END b_d[135]
  PIN b_d[136]
    DIRECTION OUTPUT ;
    USE SIGNAL ;
    PORT
      LAYER M5 ;
        RECT  20.688 0 20.712 0.084 ;
    END
  END b_d[136]
  PIN b_d[137]
    DIRECTION OUTPUT ;
    USE SIGNAL ;
    PORT
      LAYER M5 ;
        RECT  20.784 0 20.808 0.084 ;
    END
  END b_d[137]
  PIN b_d[138]
    DIRECTION OUTPUT ;
    USE SIGNAL ;
    PORT
      LAYER M5 ;
        RECT  20.88 0 20.904 0.084 ;
    END
  END b_d[138]
  PIN b_d[139]
    DIRECTION OUTPUT ;
    USE SIGNAL ;
    PORT
      LAYER M5 ;
        RECT  20.976 0 21 0.084 ;
    END
  END b_d[139]
  PIN b_d[13]
    DIRECTION OUTPUT ;
    USE SIGNAL ;
    PORT
      LAYER M5 ;
        RECT  27.312 0 27.336 0.084 ;
    END
  END b_d[13]
  PIN b_d[140]
    DIRECTION OUTPUT ;
    USE SIGNAL ;
    PORT
      LAYER M5 ;
        RECT  21.072 0 21.096 0.084 ;
    END
  END b_d[140]
  PIN b_d[141]
    DIRECTION OUTPUT ;
    USE SIGNAL ;
    PORT
      LAYER M5 ;
        RECT  21.168 0 21.192 0.084 ;
    END
  END b_d[141]
  PIN b_d[142]
    DIRECTION OUTPUT ;
    USE SIGNAL ;
    PORT
      LAYER M5 ;
        RECT  21.264 0 21.288 0.084 ;
    END
  END b_d[142]
  PIN b_d[143]
    DIRECTION OUTPUT ;
    USE SIGNAL ;
    PORT
      LAYER M5 ;
        RECT  21.36 0 21.384 0.084 ;
    END
  END b_d[143]
  PIN b_d[144]
    DIRECTION OUTPUT ;
    USE SIGNAL ;
    PORT
      LAYER M5 ;
        RECT  21.456 0 21.48 0.084 ;
    END
  END b_d[144]
  PIN b_d[145]
    DIRECTION OUTPUT ;
    USE SIGNAL ;
    PORT
      LAYER M5 ;
        RECT  21.552 0 21.576 0.084 ;
    END
  END b_d[145]
  PIN b_d[146]
    DIRECTION OUTPUT ;
    USE SIGNAL ;
    PORT
      LAYER M5 ;
        RECT  21.648 0 21.672 0.084 ;
    END
  END b_d[146]
  PIN b_d[147]
    DIRECTION OUTPUT ;
    USE SIGNAL ;
    PORT
      LAYER M5 ;
        RECT  21.744 0 21.768 0.084 ;
    END
  END b_d[147]
  PIN b_d[148]
    DIRECTION OUTPUT ;
    USE SIGNAL ;
    PORT
      LAYER M5 ;
        RECT  21.84 0 21.864 0.084 ;
    END
  END b_d[148]
  PIN b_d[149]
    DIRECTION OUTPUT ;
    USE SIGNAL ;
    PORT
      LAYER M5 ;
        RECT  21.936 0 21.96 0.084 ;
    END
  END b_d[149]
  PIN b_d[14]
    DIRECTION OUTPUT ;
    USE SIGNAL ;
    PORT
      LAYER M5 ;
        RECT  27.408 0 27.432 0.084 ;
    END
  END b_d[14]
  PIN b_d[150]
    DIRECTION OUTPUT ;
    USE SIGNAL ;
    PORT
      LAYER M5 ;
        RECT  22.032 0 22.056 0.084 ;
    END
  END b_d[150]
  PIN b_d[151]
    DIRECTION OUTPUT ;
    USE SIGNAL ;
    PORT
      LAYER M5 ;
        RECT  22.128 0 22.152 0.084 ;
    END
  END b_d[151]
  PIN b_d[152]
    DIRECTION OUTPUT ;
    USE SIGNAL ;
    PORT
      LAYER M5 ;
        RECT  22.224 0 22.248 0.084 ;
    END
  END b_d[152]
  PIN b_d[153]
    DIRECTION OUTPUT ;
    USE SIGNAL ;
    PORT
      LAYER M5 ;
        RECT  22.32 0 22.344 0.084 ;
    END
  END b_d[153]
  PIN b_d[154]
    DIRECTION OUTPUT ;
    USE SIGNAL ;
    PORT
      LAYER M5 ;
        RECT  22.416 0 22.44 0.084 ;
    END
  END b_d[154]
  PIN b_d[155]
    DIRECTION OUTPUT ;
    USE SIGNAL ;
    PORT
      LAYER M5 ;
        RECT  22.512 0 22.536 0.084 ;
    END
  END b_d[155]
  PIN b_d[156]
    DIRECTION OUTPUT ;
    USE SIGNAL ;
    PORT
      LAYER M5 ;
        RECT  22.608 0 22.632 0.084 ;
    END
  END b_d[156]
  PIN b_d[157]
    DIRECTION OUTPUT ;
    USE SIGNAL ;
    PORT
      LAYER M5 ;
        RECT  22.704 0 22.728 0.084 ;
    END
  END b_d[157]
  PIN b_d[158]
    DIRECTION OUTPUT ;
    USE SIGNAL ;
    PORT
      LAYER M5 ;
        RECT  22.8 0 22.824 0.084 ;
    END
  END b_d[158]
  PIN b_d[159]
    DIRECTION OUTPUT ;
    USE SIGNAL ;
    PORT
      LAYER M5 ;
        RECT  22.896 0 22.92 0.084 ;
    END
  END b_d[159]
  PIN b_d[15]
    DIRECTION OUTPUT ;
    USE SIGNAL ;
    PORT
      LAYER M5 ;
        RECT  27.504 0 27.528 0.084 ;
    END
  END b_d[15]
  PIN b_d[160]
    DIRECTION OUTPUT ;
    USE SIGNAL ;
    PORT
      LAYER M5 ;
        RECT  22.992 0 23.016 0.084 ;
    END
  END b_d[160]
  PIN b_d[161]
    DIRECTION OUTPUT ;
    USE SIGNAL ;
    PORT
      LAYER M5 ;
        RECT  23.088 0 23.112 0.084 ;
    END
  END b_d[161]
  PIN b_d[162]
    DIRECTION OUTPUT ;
    USE SIGNAL ;
    PORT
      LAYER M5 ;
        RECT  23.184 0 23.208 0.084 ;
    END
  END b_d[162]
  PIN b_d[163]
    DIRECTION OUTPUT ;
    USE SIGNAL ;
    PORT
      LAYER M5 ;
        RECT  23.28 0 23.304 0.084 ;
    END
  END b_d[163]
  PIN b_d[164]
    DIRECTION OUTPUT ;
    USE SIGNAL ;
    PORT
      LAYER M5 ;
        RECT  23.376 0 23.4 0.084 ;
    END
  END b_d[164]
  PIN b_d[165]
    DIRECTION OUTPUT ;
    USE SIGNAL ;
    PORT
      LAYER M5 ;
        RECT  23.472 0 23.496 0.084 ;
    END
  END b_d[165]
  PIN b_d[166]
    DIRECTION OUTPUT ;
    USE SIGNAL ;
    PORT
      LAYER M5 ;
        RECT  23.568 0 23.592 0.084 ;
    END
  END b_d[166]
  PIN b_d[167]
    DIRECTION OUTPUT ;
    USE SIGNAL ;
    PORT
      LAYER M5 ;
        RECT  23.664 0 23.688 0.084 ;
    END
  END b_d[167]
  PIN b_d[168]
    DIRECTION OUTPUT ;
    USE SIGNAL ;
    PORT
      LAYER M5 ;
        RECT  23.76 0 23.784 0.084 ;
    END
  END b_d[168]
  PIN b_d[169]
    DIRECTION OUTPUT ;
    USE SIGNAL ;
    PORT
      LAYER M5 ;
        RECT  23.856 0 23.88 0.084 ;
    END
  END b_d[169]
  PIN b_d[16]
    DIRECTION OUTPUT ;
    USE SIGNAL ;
    PORT
      LAYER M5 ;
        RECT  27.6 0 27.624 0.084 ;
    END
  END b_d[16]
  PIN b_d[170]
    DIRECTION OUTPUT ;
    USE SIGNAL ;
    PORT
      LAYER M5 ;
        RECT  23.952 0 23.976 0.084 ;
    END
  END b_d[170]
  PIN b_d[171]
    DIRECTION OUTPUT ;
    USE SIGNAL ;
    PORT
      LAYER M5 ;
        RECT  24.048 0 24.072 0.084 ;
    END
  END b_d[171]
  PIN b_d[172]
    DIRECTION OUTPUT ;
    USE SIGNAL ;
    PORT
      LAYER M5 ;
        RECT  24.144 0 24.168 0.084 ;
    END
  END b_d[172]
  PIN b_d[173]
    DIRECTION OUTPUT ;
    USE SIGNAL ;
    PORT
      LAYER M5 ;
        RECT  24.24 0 24.264 0.084 ;
    END
  END b_d[173]
  PIN b_d[174]
    DIRECTION OUTPUT ;
    USE SIGNAL ;
    PORT
      LAYER M5 ;
        RECT  24.336 0 24.36 0.084 ;
    END
  END b_d[174]
  PIN b_d[175]
    DIRECTION OUTPUT ;
    USE SIGNAL ;
    PORT
      LAYER M5 ;
        RECT  24.432 0 24.456 0.084 ;
    END
  END b_d[175]
  PIN b_d[176]
    DIRECTION OUTPUT ;
    USE SIGNAL ;
    PORT
      LAYER M5 ;
        RECT  24.528 0 24.552 0.084 ;
    END
  END b_d[176]
  PIN b_d[177]
    DIRECTION OUTPUT ;
    USE SIGNAL ;
    PORT
      LAYER M5 ;
        RECT  24.624 0 24.648 0.084 ;
    END
  END b_d[177]
  PIN b_d[178]
    DIRECTION OUTPUT ;
    USE SIGNAL ;
    PORT
      LAYER M5 ;
        RECT  24.72 0 24.744 0.084 ;
    END
  END b_d[178]
  PIN b_d[179]
    DIRECTION OUTPUT ;
    USE SIGNAL ;
    PORT
      LAYER M5 ;
        RECT  24.816 0 24.84 0.084 ;
    END
  END b_d[179]
  PIN b_d[17]
    DIRECTION OUTPUT ;
    USE SIGNAL ;
    PORT
      LAYER M5 ;
        RECT  27.696 0 27.72 0.084 ;
    END
  END b_d[17]
  PIN b_d[180]
    DIRECTION OUTPUT ;
    USE SIGNAL ;
    PORT
      LAYER M5 ;
        RECT  24.912 0 24.936 0.084 ;
    END
  END b_d[180]
  PIN b_d[181]
    DIRECTION OUTPUT ;
    USE SIGNAL ;
    PORT
      LAYER M5 ;
        RECT  25.008 0 25.032 0.084 ;
    END
  END b_d[181]
  PIN b_d[182]
    DIRECTION OUTPUT ;
    USE SIGNAL ;
    PORT
      LAYER M5 ;
        RECT  25.104 0 25.128 0.084 ;
    END
  END b_d[182]
  PIN b_d[183]
    DIRECTION OUTPUT ;
    USE SIGNAL ;
    PORT
      LAYER M5 ;
        RECT  25.2 0 25.224 0.084 ;
    END
  END b_d[183]
  PIN b_d[184]
    DIRECTION OUTPUT ;
    USE SIGNAL ;
    PORT
      LAYER M5 ;
        RECT  25.296 0 25.32 0.084 ;
    END
  END b_d[184]
  PIN b_d[185]
    DIRECTION OUTPUT ;
    USE SIGNAL ;
    PORT
      LAYER M5 ;
        RECT  25.392 0 25.416 0.084 ;
    END
  END b_d[185]
  PIN b_d[186]
    DIRECTION OUTPUT ;
    USE SIGNAL ;
    PORT
      LAYER M5 ;
        RECT  25.488 0 25.512 0.084 ;
    END
  END b_d[186]
  PIN b_d[187]
    DIRECTION OUTPUT ;
    USE SIGNAL ;
    PORT
      LAYER M5 ;
        RECT  25.584 0 25.608 0.084 ;
    END
  END b_d[187]
  PIN b_d[188]
    DIRECTION OUTPUT ;
    USE SIGNAL ;
    PORT
      LAYER M5 ;
        RECT  25.68 0 25.704 0.084 ;
    END
  END b_d[188]
  PIN b_d[189]
    DIRECTION OUTPUT ;
    USE SIGNAL ;
    PORT
      LAYER M5 ;
        RECT  25.776 0 25.8 0.084 ;
    END
  END b_d[189]
  PIN b_d[18]
    DIRECTION OUTPUT ;
    USE SIGNAL ;
    PORT
      LAYER M5 ;
        RECT  27.792 0 27.816 0.084 ;
    END
  END b_d[18]
  PIN b_d[190]
    DIRECTION OUTPUT ;
    USE SIGNAL ;
    PORT
      LAYER M5 ;
        RECT  25.872 0 25.896 0.084 ;
    END
  END b_d[190]
  PIN b_d[191]
    DIRECTION OUTPUT ;
    USE SIGNAL ;
    PORT
      LAYER M5 ;
        RECT  25.968 0 25.992 0.084 ;
    END
  END b_d[191]
  PIN b_d[192]
    DIRECTION OUTPUT ;
    USE SIGNAL ;
    PORT
      LAYER M5 ;
        RECT  48.336 0 48.36 0.084 ;
    END
  END b_d[192]
  PIN b_d[193]
    DIRECTION OUTPUT ;
    USE SIGNAL ;
    PORT
      LAYER M5 ;
        RECT  48.432 0 48.456 0.084 ;
    END
  END b_d[193]
  PIN b_d[194]
    DIRECTION OUTPUT ;
    USE SIGNAL ;
    PORT
      LAYER M5 ;
        RECT  48.528 0 48.552 0.084 ;
    END
  END b_d[194]
  PIN b_d[195]
    DIRECTION OUTPUT ;
    USE SIGNAL ;
    PORT
      LAYER M5 ;
        RECT  48.624 0 48.648 0.084 ;
    END
  END b_d[195]
  PIN b_d[196]
    DIRECTION OUTPUT ;
    USE SIGNAL ;
    PORT
      LAYER M5 ;
        RECT  48.72 0 48.744 0.084 ;
    END
  END b_d[196]
  PIN b_d[197]
    DIRECTION OUTPUT ;
    USE SIGNAL ;
    PORT
      LAYER M5 ;
        RECT  48.816 0 48.84 0.084 ;
    END
  END b_d[197]
  PIN b_d[198]
    DIRECTION OUTPUT ;
    USE SIGNAL ;
    PORT
      LAYER M5 ;
        RECT  48.912 0 48.936 0.084 ;
    END
  END b_d[198]
  PIN b_d[199]
    DIRECTION OUTPUT ;
    USE SIGNAL ;
    PORT
      LAYER M5 ;
        RECT  49.008 0 49.032 0.084 ;
    END
  END b_d[199]
  PIN b_d[19]
    DIRECTION OUTPUT ;
    USE SIGNAL ;
    PORT
      LAYER M5 ;
        RECT  27.888 0 27.912 0.084 ;
    END
  END b_d[19]
  PIN b_d[1]
    DIRECTION OUTPUT ;
    USE SIGNAL ;
    PORT
      LAYER M5 ;
        RECT  26.16 0 26.184 0.084 ;
    END
  END b_d[1]
  PIN b_d[200]
    DIRECTION OUTPUT ;
    USE SIGNAL ;
    PORT
      LAYER M5 ;
        RECT  49.104 0 49.128 0.084 ;
    END
  END b_d[200]
  PIN b_d[201]
    DIRECTION OUTPUT ;
    USE SIGNAL ;
    PORT
      LAYER M5 ;
        RECT  49.2 0 49.224 0.084 ;
    END
  END b_d[201]
  PIN b_d[202]
    DIRECTION OUTPUT ;
    USE SIGNAL ;
    PORT
      LAYER M5 ;
        RECT  49.296 0 49.32 0.084 ;
    END
  END b_d[202]
  PIN b_d[203]
    DIRECTION OUTPUT ;
    USE SIGNAL ;
    PORT
      LAYER M5 ;
        RECT  49.392 0 49.416 0.084 ;
    END
  END b_d[203]
  PIN b_d[204]
    DIRECTION OUTPUT ;
    USE SIGNAL ;
    PORT
      LAYER M5 ;
        RECT  49.488 0 49.512 0.084 ;
    END
  END b_d[204]
  PIN b_d[205]
    DIRECTION OUTPUT ;
    USE SIGNAL ;
    PORT
      LAYER M5 ;
        RECT  49.584 0 49.608 0.084 ;
    END
  END b_d[205]
  PIN b_d[206]
    DIRECTION OUTPUT ;
    USE SIGNAL ;
    PORT
      LAYER M5 ;
        RECT  49.68 0 49.704 0.084 ;
    END
  END b_d[206]
  PIN b_d[207]
    DIRECTION OUTPUT ;
    USE SIGNAL ;
    PORT
      LAYER M5 ;
        RECT  49.776 0 49.8 0.084 ;
    END
  END b_d[207]
  PIN b_d[208]
    DIRECTION OUTPUT ;
    USE SIGNAL ;
    PORT
      LAYER M5 ;
        RECT  49.872 0 49.896 0.084 ;
    END
  END b_d[208]
  PIN b_d[209]
    DIRECTION OUTPUT ;
    USE SIGNAL ;
    PORT
      LAYER M5 ;
        RECT  49.968 0 49.992 0.084 ;
    END
  END b_d[209]
  PIN b_d[20]
    DIRECTION OUTPUT ;
    USE SIGNAL ;
    PORT
      LAYER M5 ;
        RECT  27.984 0 28.008 0.084 ;
    END
  END b_d[20]
  PIN b_d[210]
    DIRECTION OUTPUT ;
    USE SIGNAL ;
    PORT
      LAYER M5 ;
        RECT  50.064 0 50.088 0.084 ;
    END
  END b_d[210]
  PIN b_d[211]
    DIRECTION OUTPUT ;
    USE SIGNAL ;
    PORT
      LAYER M5 ;
        RECT  50.16 0 50.184 0.084 ;
    END
  END b_d[211]
  PIN b_d[212]
    DIRECTION OUTPUT ;
    USE SIGNAL ;
    PORT
      LAYER M5 ;
        RECT  50.256 0 50.28 0.084 ;
    END
  END b_d[212]
  PIN b_d[213]
    DIRECTION OUTPUT ;
    USE SIGNAL ;
    PORT
      LAYER M5 ;
        RECT  50.352 0 50.376 0.084 ;
    END
  END b_d[213]
  PIN b_d[214]
    DIRECTION OUTPUT ;
    USE SIGNAL ;
    PORT
      LAYER M5 ;
        RECT  50.448 0 50.472 0.084 ;
    END
  END b_d[214]
  PIN b_d[215]
    DIRECTION OUTPUT ;
    USE SIGNAL ;
    PORT
      LAYER M5 ;
        RECT  50.544 0 50.568 0.084 ;
    END
  END b_d[215]
  PIN b_d[216]
    DIRECTION OUTPUT ;
    USE SIGNAL ;
    PORT
      LAYER M5 ;
        RECT  50.64 0 50.664 0.084 ;
    END
  END b_d[216]
  PIN b_d[217]
    DIRECTION OUTPUT ;
    USE SIGNAL ;
    PORT
      LAYER M5 ;
        RECT  50.736 0 50.76 0.084 ;
    END
  END b_d[217]
  PIN b_d[218]
    DIRECTION OUTPUT ;
    USE SIGNAL ;
    PORT
      LAYER M5 ;
        RECT  50.832 0 50.856 0.084 ;
    END
  END b_d[218]
  PIN b_d[219]
    DIRECTION OUTPUT ;
    USE SIGNAL ;
    PORT
      LAYER M5 ;
        RECT  50.928 0 50.952 0.084 ;
    END
  END b_d[219]
  PIN b_d[21]
    DIRECTION OUTPUT ;
    USE SIGNAL ;
    PORT
      LAYER M5 ;
        RECT  28.08 0 28.104 0.084 ;
    END
  END b_d[21]
  PIN b_d[220]
    DIRECTION OUTPUT ;
    USE SIGNAL ;
    PORT
      LAYER M5 ;
        RECT  51.024 0 51.048 0.084 ;
    END
  END b_d[220]
  PIN b_d[221]
    DIRECTION OUTPUT ;
    USE SIGNAL ;
    PORT
      LAYER M5 ;
        RECT  51.12 0 51.144 0.084 ;
    END
  END b_d[221]
  PIN b_d[222]
    DIRECTION OUTPUT ;
    USE SIGNAL ;
    PORT
      LAYER M5 ;
        RECT  51.216 0 51.24 0.084 ;
    END
  END b_d[222]
  PIN b_d[223]
    DIRECTION OUTPUT ;
    USE SIGNAL ;
    PORT
      LAYER M5 ;
        RECT  51.312 0 51.336 0.084 ;
    END
  END b_d[223]
  PIN b_d[224]
    DIRECTION OUTPUT ;
    USE SIGNAL ;
    PORT
      LAYER M5 ;
        RECT  3.792 0 3.816 0.084 ;
    END
  END b_d[224]
  PIN b_d[225]
    DIRECTION OUTPUT ;
    USE SIGNAL ;
    PORT
      LAYER M5 ;
        RECT  3.888 0 3.912 0.084 ;
    END
  END b_d[225]
  PIN b_d[226]
    DIRECTION OUTPUT ;
    USE SIGNAL ;
    PORT
      LAYER M5 ;
        RECT  3.984 0 4.008 0.084 ;
    END
  END b_d[226]
  PIN b_d[227]
    DIRECTION OUTPUT ;
    USE SIGNAL ;
    PORT
      LAYER M5 ;
        RECT  4.08 0 4.104 0.084 ;
    END
  END b_d[227]
  PIN b_d[228]
    DIRECTION OUTPUT ;
    USE SIGNAL ;
    PORT
      LAYER M5 ;
        RECT  4.176 0 4.2 0.084 ;
    END
  END b_d[228]
  PIN b_d[229]
    DIRECTION OUTPUT ;
    USE SIGNAL ;
    PORT
      LAYER M5 ;
        RECT  4.272 0 4.296 0.084 ;
    END
  END b_d[229]
  PIN b_d[22]
    DIRECTION OUTPUT ;
    USE SIGNAL ;
    PORT
      LAYER M5 ;
        RECT  28.176 0 28.2 0.084 ;
    END
  END b_d[22]
  PIN b_d[230]
    DIRECTION OUTPUT ;
    USE SIGNAL ;
    PORT
      LAYER M5 ;
        RECT  4.368 0 4.392 0.084 ;
    END
  END b_d[230]
  PIN b_d[231]
    DIRECTION OUTPUT ;
    USE SIGNAL ;
    PORT
      LAYER M5 ;
        RECT  4.464 0 4.488 0.084 ;
    END
  END b_d[231]
  PIN b_d[232]
    DIRECTION OUTPUT ;
    USE SIGNAL ;
    PORT
      LAYER M5 ;
        RECT  4.56 0 4.584 0.084 ;
    END
  END b_d[232]
  PIN b_d[233]
    DIRECTION OUTPUT ;
    USE SIGNAL ;
    PORT
      LAYER M5 ;
        RECT  4.656 0 4.68 0.084 ;
    END
  END b_d[233]
  PIN b_d[234]
    DIRECTION OUTPUT ;
    USE SIGNAL ;
    PORT
      LAYER M5 ;
        RECT  4.752 0 4.776 0.084 ;
    END
  END b_d[234]
  PIN b_d[235]
    DIRECTION OUTPUT ;
    USE SIGNAL ;
    PORT
      LAYER M5 ;
        RECT  4.848 0 4.872 0.084 ;
    END
  END b_d[235]
  PIN b_d[236]
    DIRECTION OUTPUT ;
    USE SIGNAL ;
    PORT
      LAYER M5 ;
        RECT  4.944 0 4.968 0.084 ;
    END
  END b_d[236]
  PIN b_d[237]
    DIRECTION OUTPUT ;
    USE SIGNAL ;
    PORT
      LAYER M5 ;
        RECT  5.04 0 5.064 0.084 ;
    END
  END b_d[237]
  PIN b_d[238]
    DIRECTION OUTPUT ;
    USE SIGNAL ;
    PORT
      LAYER M5 ;
        RECT  5.136 0 5.16 0.084 ;
    END
  END b_d[238]
  PIN b_d[239]
    DIRECTION OUTPUT ;
    USE SIGNAL ;
    PORT
      LAYER M5 ;
        RECT  5.232 0 5.256 0.084 ;
    END
  END b_d[239]
  PIN b_d[23]
    DIRECTION OUTPUT ;
    USE SIGNAL ;
    PORT
      LAYER M5 ;
        RECT  28.272 0 28.296 0.084 ;
    END
  END b_d[23]
  PIN b_d[240]
    DIRECTION OUTPUT ;
    USE SIGNAL ;
    PORT
      LAYER M5 ;
        RECT  5.328 0 5.352 0.084 ;
    END
  END b_d[240]
  PIN b_d[241]
    DIRECTION OUTPUT ;
    USE SIGNAL ;
    PORT
      LAYER M5 ;
        RECT  5.424 0 5.448 0.084 ;
    END
  END b_d[241]
  PIN b_d[242]
    DIRECTION OUTPUT ;
    USE SIGNAL ;
    PORT
      LAYER M5 ;
        RECT  5.52 0 5.544 0.084 ;
    END
  END b_d[242]
  PIN b_d[243]
    DIRECTION OUTPUT ;
    USE SIGNAL ;
    PORT
      LAYER M5 ;
        RECT  5.616 0 5.64 0.084 ;
    END
  END b_d[243]
  PIN b_d[244]
    DIRECTION OUTPUT ;
    USE SIGNAL ;
    PORT
      LAYER M5 ;
        RECT  5.712 0 5.736 0.084 ;
    END
  END b_d[244]
  PIN b_d[245]
    DIRECTION OUTPUT ;
    USE SIGNAL ;
    PORT
      LAYER M5 ;
        RECT  5.808 0 5.832 0.084 ;
    END
  END b_d[245]
  PIN b_d[246]
    DIRECTION OUTPUT ;
    USE SIGNAL ;
    PORT
      LAYER M5 ;
        RECT  5.904 0 5.928 0.084 ;
    END
  END b_d[246]
  PIN b_d[247]
    DIRECTION OUTPUT ;
    USE SIGNAL ;
    PORT
      LAYER M5 ;
        RECT  6 0 6.024 0.084 ;
    END
  END b_d[247]
  PIN b_d[248]
    DIRECTION OUTPUT ;
    USE SIGNAL ;
    PORT
      LAYER M5 ;
        RECT  6.096 0 6.12 0.084 ;
    END
  END b_d[248]
  PIN b_d[249]
    DIRECTION OUTPUT ;
    USE SIGNAL ;
    PORT
      LAYER M5 ;
        RECT  6.192 0 6.216 0.084 ;
    END
  END b_d[249]
  PIN b_d[24]
    DIRECTION OUTPUT ;
    USE SIGNAL ;
    PORT
      LAYER M5 ;
        RECT  28.368 0 28.392 0.084 ;
    END
  END b_d[24]
  PIN b_d[250]
    DIRECTION OUTPUT ;
    USE SIGNAL ;
    PORT
      LAYER M5 ;
        RECT  6.288 0 6.312 0.084 ;
    END
  END b_d[250]
  PIN b_d[251]
    DIRECTION OUTPUT ;
    USE SIGNAL ;
    PORT
      LAYER M5 ;
        RECT  6.384 0 6.408 0.084 ;
    END
  END b_d[251]
  PIN b_d[252]
    DIRECTION OUTPUT ;
    USE SIGNAL ;
    PORT
      LAYER M5 ;
        RECT  6.48 0 6.504 0.084 ;
    END
  END b_d[252]
  PIN b_d[253]
    DIRECTION OUTPUT ;
    USE SIGNAL ;
    PORT
      LAYER M5 ;
        RECT  6.576 0 6.6 0.084 ;
    END
  END b_d[253]
  PIN b_d[254]
    DIRECTION OUTPUT ;
    USE SIGNAL ;
    PORT
      LAYER M5 ;
        RECT  6.672 0 6.696 0.084 ;
    END
  END b_d[254]
  PIN b_d[255]
    DIRECTION OUTPUT ;
    USE SIGNAL ;
    PORT
      LAYER M5 ;
        RECT  6.768 0 6.792 0.084 ;
    END
  END b_d[255]
  PIN b_d[256]
    DIRECTION OUTPUT ;
    USE SIGNAL ;
    PORT
      LAYER M5 ;
        RECT  39.12 0 39.144 0.084 ;
    END
  END b_d[256]
  PIN b_d[257]
    DIRECTION OUTPUT ;
    USE SIGNAL ;
    PORT
      LAYER M5 ;
        RECT  39.216 0 39.24 0.084 ;
    END
  END b_d[257]
  PIN b_d[258]
    DIRECTION OUTPUT ;
    USE SIGNAL ;
    PORT
      LAYER M5 ;
        RECT  39.312 0 39.336 0.084 ;
    END
  END b_d[258]
  PIN b_d[259]
    DIRECTION OUTPUT ;
    USE SIGNAL ;
    PORT
      LAYER M5 ;
        RECT  39.408 0 39.432 0.084 ;
    END
  END b_d[259]
  PIN b_d[25]
    DIRECTION OUTPUT ;
    USE SIGNAL ;
    PORT
      LAYER M5 ;
        RECT  28.464 0 28.488 0.084 ;
    END
  END b_d[25]
  PIN b_d[260]
    DIRECTION OUTPUT ;
    USE SIGNAL ;
    PORT
      LAYER M5 ;
        RECT  39.504 0 39.528 0.084 ;
    END
  END b_d[260]
  PIN b_d[261]
    DIRECTION OUTPUT ;
    USE SIGNAL ;
    PORT
      LAYER M5 ;
        RECT  39.6 0 39.624 0.084 ;
    END
  END b_d[261]
  PIN b_d[262]
    DIRECTION OUTPUT ;
    USE SIGNAL ;
    PORT
      LAYER M5 ;
        RECT  39.696 0 39.72 0.084 ;
    END
  END b_d[262]
  PIN b_d[263]
    DIRECTION OUTPUT ;
    USE SIGNAL ;
    PORT
      LAYER M5 ;
        RECT  39.792 0 39.816 0.084 ;
    END
  END b_d[263]
  PIN b_d[264]
    DIRECTION OUTPUT ;
    USE SIGNAL ;
    PORT
      LAYER M5 ;
        RECT  39.888 0 39.912 0.084 ;
    END
  END b_d[264]
  PIN b_d[265]
    DIRECTION OUTPUT ;
    USE SIGNAL ;
    PORT
      LAYER M5 ;
        RECT  39.984 0 40.008 0.084 ;
    END
  END b_d[265]
  PIN b_d[266]
    DIRECTION OUTPUT ;
    USE SIGNAL ;
    PORT
      LAYER M5 ;
        RECT  40.08 0 40.104 0.084 ;
    END
  END b_d[266]
  PIN b_d[267]
    DIRECTION OUTPUT ;
    USE SIGNAL ;
    PORT
      LAYER M5 ;
        RECT  40.176 0 40.2 0.084 ;
    END
  END b_d[267]
  PIN b_d[268]
    DIRECTION OUTPUT ;
    USE SIGNAL ;
    PORT
      LAYER M5 ;
        RECT  40.272 0 40.296 0.084 ;
    END
  END b_d[268]
  PIN b_d[269]
    DIRECTION OUTPUT ;
    USE SIGNAL ;
    PORT
      LAYER M5 ;
        RECT  40.368 0 40.392 0.084 ;
    END
  END b_d[269]
  PIN b_d[26]
    DIRECTION OUTPUT ;
    USE SIGNAL ;
    PORT
      LAYER M5 ;
        RECT  28.56 0 28.584 0.084 ;
    END
  END b_d[26]
  PIN b_d[270]
    DIRECTION OUTPUT ;
    USE SIGNAL ;
    PORT
      LAYER M5 ;
        RECT  40.464 0 40.488 0.084 ;
    END
  END b_d[270]
  PIN b_d[271]
    DIRECTION OUTPUT ;
    USE SIGNAL ;
    PORT
      LAYER M5 ;
        RECT  40.56 0 40.584 0.084 ;
    END
  END b_d[271]
  PIN b_d[272]
    DIRECTION OUTPUT ;
    USE SIGNAL ;
    PORT
      LAYER M5 ;
        RECT  40.656 0 40.68 0.084 ;
    END
  END b_d[272]
  PIN b_d[273]
    DIRECTION OUTPUT ;
    USE SIGNAL ;
    PORT
      LAYER M5 ;
        RECT  40.752 0 40.776 0.084 ;
    END
  END b_d[273]
  PIN b_d[274]
    DIRECTION OUTPUT ;
    USE SIGNAL ;
    PORT
      LAYER M5 ;
        RECT  40.848 0 40.872 0.084 ;
    END
  END b_d[274]
  PIN b_d[275]
    DIRECTION OUTPUT ;
    USE SIGNAL ;
    PORT
      LAYER M5 ;
        RECT  40.944 0 40.968 0.084 ;
    END
  END b_d[275]
  PIN b_d[276]
    DIRECTION OUTPUT ;
    USE SIGNAL ;
    PORT
      LAYER M5 ;
        RECT  41.04 0 41.064 0.084 ;
    END
  END b_d[276]
  PIN b_d[277]
    DIRECTION OUTPUT ;
    USE SIGNAL ;
    PORT
      LAYER M5 ;
        RECT  41.136 0 41.16 0.084 ;
    END
  END b_d[277]
  PIN b_d[278]
    DIRECTION OUTPUT ;
    USE SIGNAL ;
    PORT
      LAYER M5 ;
        RECT  41.232 0 41.256 0.084 ;
    END
  END b_d[278]
  PIN b_d[279]
    DIRECTION OUTPUT ;
    USE SIGNAL ;
    PORT
      LAYER M5 ;
        RECT  41.328 0 41.352 0.084 ;
    END
  END b_d[279]
  PIN b_d[27]
    DIRECTION OUTPUT ;
    USE SIGNAL ;
    PORT
      LAYER M5 ;
        RECT  28.656 0 28.68 0.084 ;
    END
  END b_d[27]
  PIN b_d[280]
    DIRECTION OUTPUT ;
    USE SIGNAL ;
    PORT
      LAYER M5 ;
        RECT  41.424 0 41.448 0.084 ;
    END
  END b_d[280]
  PIN b_d[281]
    DIRECTION OUTPUT ;
    USE SIGNAL ;
    PORT
      LAYER M5 ;
        RECT  41.52 0 41.544 0.084 ;
    END
  END b_d[281]
  PIN b_d[282]
    DIRECTION OUTPUT ;
    USE SIGNAL ;
    PORT
      LAYER M5 ;
        RECT  41.616 0 41.64 0.084 ;
    END
  END b_d[282]
  PIN b_d[283]
    DIRECTION OUTPUT ;
    USE SIGNAL ;
    PORT
      LAYER M5 ;
        RECT  41.712 0 41.736 0.084 ;
    END
  END b_d[283]
  PIN b_d[284]
    DIRECTION OUTPUT ;
    USE SIGNAL ;
    PORT
      LAYER M5 ;
        RECT  41.808 0 41.832 0.084 ;
    END
  END b_d[284]
  PIN b_d[285]
    DIRECTION OUTPUT ;
    USE SIGNAL ;
    PORT
      LAYER M5 ;
        RECT  41.904 0 41.928 0.084 ;
    END
  END b_d[285]
  PIN b_d[286]
    DIRECTION OUTPUT ;
    USE SIGNAL ;
    PORT
      LAYER M5 ;
        RECT  42 0 42.024 0.084 ;
    END
  END b_d[286]
  PIN b_d[287]
    DIRECTION OUTPUT ;
    USE SIGNAL ;
    PORT
      LAYER M5 ;
        RECT  42.096 0 42.12 0.084 ;
    END
  END b_d[287]
  PIN b_d[288]
    DIRECTION OUTPUT ;
    USE SIGNAL ;
    PORT
      LAYER M5 ;
        RECT  45.264 0 45.288 0.084 ;
    END
  END b_d[288]
  PIN b_d[289]
    DIRECTION OUTPUT ;
    USE SIGNAL ;
    PORT
      LAYER M5 ;
        RECT  45.36 0 45.384 0.084 ;
    END
  END b_d[289]
  PIN b_d[28]
    DIRECTION OUTPUT ;
    USE SIGNAL ;
    PORT
      LAYER M5 ;
        RECT  28.752 0 28.776 0.084 ;
    END
  END b_d[28]
  PIN b_d[290]
    DIRECTION OUTPUT ;
    USE SIGNAL ;
    PORT
      LAYER M5 ;
        RECT  45.456 0 45.48 0.084 ;
    END
  END b_d[290]
  PIN b_d[291]
    DIRECTION OUTPUT ;
    USE SIGNAL ;
    PORT
      LAYER M5 ;
        RECT  45.552 0 45.576 0.084 ;
    END
  END b_d[291]
  PIN b_d[292]
    DIRECTION OUTPUT ;
    USE SIGNAL ;
    PORT
      LAYER M5 ;
        RECT  45.648 0 45.672 0.084 ;
    END
  END b_d[292]
  PIN b_d[293]
    DIRECTION OUTPUT ;
    USE SIGNAL ;
    PORT
      LAYER M5 ;
        RECT  45.744 0 45.768 0.084 ;
    END
  END b_d[293]
  PIN b_d[294]
    DIRECTION OUTPUT ;
    USE SIGNAL ;
    PORT
      LAYER M5 ;
        RECT  45.84 0 45.864 0.084 ;
    END
  END b_d[294]
  PIN b_d[295]
    DIRECTION OUTPUT ;
    USE SIGNAL ;
    PORT
      LAYER M5 ;
        RECT  45.936 0 45.96 0.084 ;
    END
  END b_d[295]
  PIN b_d[296]
    DIRECTION OUTPUT ;
    USE SIGNAL ;
    PORT
      LAYER M5 ;
        RECT  46.032 0 46.056 0.084 ;
    END
  END b_d[296]
  PIN b_d[297]
    DIRECTION OUTPUT ;
    USE SIGNAL ;
    PORT
      LAYER M5 ;
        RECT  46.128 0 46.152 0.084 ;
    END
  END b_d[297]
  PIN b_d[298]
    DIRECTION OUTPUT ;
    USE SIGNAL ;
    PORT
      LAYER M5 ;
        RECT  46.224 0 46.248 0.084 ;
    END
  END b_d[298]
  PIN b_d[299]
    DIRECTION OUTPUT ;
    USE SIGNAL ;
    PORT
      LAYER M5 ;
        RECT  46.32 0 46.344 0.084 ;
    END
  END b_d[299]
  PIN b_d[29]
    DIRECTION OUTPUT ;
    USE SIGNAL ;
    PORT
      LAYER M5 ;
        RECT  28.848 0 28.872 0.084 ;
    END
  END b_d[29]
  PIN b_d[2]
    DIRECTION OUTPUT ;
    USE SIGNAL ;
    PORT
      LAYER M5 ;
        RECT  26.256 0 26.28 0.084 ;
    END
  END b_d[2]
  PIN b_d[300]
    DIRECTION OUTPUT ;
    USE SIGNAL ;
    PORT
      LAYER M5 ;
        RECT  46.416 0 46.44 0.084 ;
    END
  END b_d[300]
  PIN b_d[301]
    DIRECTION OUTPUT ;
    USE SIGNAL ;
    PORT
      LAYER M5 ;
        RECT  46.512 0 46.536 0.084 ;
    END
  END b_d[301]
  PIN b_d[302]
    DIRECTION OUTPUT ;
    USE SIGNAL ;
    PORT
      LAYER M5 ;
        RECT  46.608 0 46.632 0.084 ;
    END
  END b_d[302]
  PIN b_d[303]
    DIRECTION OUTPUT ;
    USE SIGNAL ;
    PORT
      LAYER M5 ;
        RECT  46.704 0 46.728 0.084 ;
    END
  END b_d[303]
  PIN b_d[304]
    DIRECTION OUTPUT ;
    USE SIGNAL ;
    PORT
      LAYER M5 ;
        RECT  46.8 0 46.824 0.084 ;
    END
  END b_d[304]
  PIN b_d[305]
    DIRECTION OUTPUT ;
    USE SIGNAL ;
    PORT
      LAYER M5 ;
        RECT  46.896 0 46.92 0.084 ;
    END
  END b_d[305]
  PIN b_d[306]
    DIRECTION OUTPUT ;
    USE SIGNAL ;
    PORT
      LAYER M5 ;
        RECT  46.992 0 47.016 0.084 ;
    END
  END b_d[306]
  PIN b_d[307]
    DIRECTION OUTPUT ;
    USE SIGNAL ;
    PORT
      LAYER M5 ;
        RECT  47.088 0 47.112 0.084 ;
    END
  END b_d[307]
  PIN b_d[308]
    DIRECTION OUTPUT ;
    USE SIGNAL ;
    PORT
      LAYER M5 ;
        RECT  47.184 0 47.208 0.084 ;
    END
  END b_d[308]
  PIN b_d[309]
    DIRECTION OUTPUT ;
    USE SIGNAL ;
    PORT
      LAYER M5 ;
        RECT  47.28 0 47.304 0.084 ;
    END
  END b_d[309]
  PIN b_d[30]
    DIRECTION OUTPUT ;
    USE SIGNAL ;
    PORT
      LAYER M5 ;
        RECT  28.944 0 28.968 0.084 ;
    END
  END b_d[30]
  PIN b_d[310]
    DIRECTION OUTPUT ;
    USE SIGNAL ;
    PORT
      LAYER M5 ;
        RECT  47.376 0 47.4 0.084 ;
    END
  END b_d[310]
  PIN b_d[311]
    DIRECTION OUTPUT ;
    USE SIGNAL ;
    PORT
      LAYER M5 ;
        RECT  47.472 0 47.496 0.084 ;
    END
  END b_d[311]
  PIN b_d[312]
    DIRECTION OUTPUT ;
    USE SIGNAL ;
    PORT
      LAYER M5 ;
        RECT  47.568 0 47.592 0.084 ;
    END
  END b_d[312]
  PIN b_d[313]
    DIRECTION OUTPUT ;
    USE SIGNAL ;
    PORT
      LAYER M5 ;
        RECT  47.664 0 47.688 0.084 ;
    END
  END b_d[313]
  PIN b_d[314]
    DIRECTION OUTPUT ;
    USE SIGNAL ;
    PORT
      LAYER M5 ;
        RECT  47.76 0 47.784 0.084 ;
    END
  END b_d[314]
  PIN b_d[315]
    DIRECTION OUTPUT ;
    USE SIGNAL ;
    PORT
      LAYER M5 ;
        RECT  47.856 0 47.88 0.084 ;
    END
  END b_d[315]
  PIN b_d[316]
    DIRECTION OUTPUT ;
    USE SIGNAL ;
    PORT
      LAYER M5 ;
        RECT  47.952 0 47.976 0.084 ;
    END
  END b_d[316]
  PIN b_d[317]
    DIRECTION OUTPUT ;
    USE SIGNAL ;
    PORT
      LAYER M5 ;
        RECT  48.048 0 48.072 0.084 ;
    END
  END b_d[317]
  PIN b_d[318]
    DIRECTION OUTPUT ;
    USE SIGNAL ;
    PORT
      LAYER M5 ;
        RECT  48.144 0 48.168 0.084 ;
    END
  END b_d[318]
  PIN b_d[319]
    DIRECTION OUTPUT ;
    USE SIGNAL ;
    PORT
      LAYER M5 ;
        RECT  48.24 0 48.264 0.084 ;
    END
  END b_d[319]
  PIN b_d[31]
    DIRECTION OUTPUT ;
    USE SIGNAL ;
    PORT
      LAYER M5 ;
        RECT  29.04 0 29.064 0.084 ;
    END
  END b_d[31]
  PIN b_d[320]
    DIRECTION OUTPUT ;
    USE SIGNAL ;
    PORT
      LAYER M5 ;
        RECT  6.864 0 6.888 0.084 ;
    END
  END b_d[320]
  PIN b_d[321]
    DIRECTION OUTPUT ;
    USE SIGNAL ;
    PORT
      LAYER M5 ;
        RECT  6.96 0 6.984 0.084 ;
    END
  END b_d[321]
  PIN b_d[322]
    DIRECTION OUTPUT ;
    USE SIGNAL ;
    PORT
      LAYER M5 ;
        RECT  7.056 0 7.08 0.084 ;
    END
  END b_d[322]
  PIN b_d[323]
    DIRECTION OUTPUT ;
    USE SIGNAL ;
    PORT
      LAYER M5 ;
        RECT  7.152 0 7.176 0.084 ;
    END
  END b_d[323]
  PIN b_d[324]
    DIRECTION OUTPUT ;
    USE SIGNAL ;
    PORT
      LAYER M5 ;
        RECT  7.248 0 7.272 0.084 ;
    END
  END b_d[324]
  PIN b_d[325]
    DIRECTION OUTPUT ;
    USE SIGNAL ;
    PORT
      LAYER M5 ;
        RECT  7.344 0 7.368 0.084 ;
    END
  END b_d[325]
  PIN b_d[326]
    DIRECTION OUTPUT ;
    USE SIGNAL ;
    PORT
      LAYER M5 ;
        RECT  7.44 0 7.464 0.084 ;
    END
  END b_d[326]
  PIN b_d[327]
    DIRECTION OUTPUT ;
    USE SIGNAL ;
    PORT
      LAYER M5 ;
        RECT  7.536 0 7.56 0.084 ;
    END
  END b_d[327]
  PIN b_d[328]
    DIRECTION OUTPUT ;
    USE SIGNAL ;
    PORT
      LAYER M5 ;
        RECT  7.632 0 7.656 0.084 ;
    END
  END b_d[328]
  PIN b_d[329]
    DIRECTION OUTPUT ;
    USE SIGNAL ;
    PORT
      LAYER M5 ;
        RECT  7.728 0 7.752 0.084 ;
    END
  END b_d[329]
  PIN b_d[32]
    DIRECTION OUTPUT ;
    USE SIGNAL ;
    PORT
      LAYER M5 ;
        RECT  35.28 0 35.304 0.084 ;
    END
  END b_d[32]
  PIN b_d[330]
    DIRECTION OUTPUT ;
    USE SIGNAL ;
    PORT
      LAYER M5 ;
        RECT  7.824 0 7.848 0.084 ;
    END
  END b_d[330]
  PIN b_d[331]
    DIRECTION OUTPUT ;
    USE SIGNAL ;
    PORT
      LAYER M5 ;
        RECT  7.92 0 7.944 0.084 ;
    END
  END b_d[331]
  PIN b_d[332]
    DIRECTION OUTPUT ;
    USE SIGNAL ;
    PORT
      LAYER M5 ;
        RECT  8.016 0 8.04 0.084 ;
    END
  END b_d[332]
  PIN b_d[333]
    DIRECTION OUTPUT ;
    USE SIGNAL ;
    PORT
      LAYER M5 ;
        RECT  8.112 0 8.136 0.084 ;
    END
  END b_d[333]
  PIN b_d[334]
    DIRECTION OUTPUT ;
    USE SIGNAL ;
    PORT
      LAYER M5 ;
        RECT  8.208 0 8.232 0.084 ;
    END
  END b_d[334]
  PIN b_d[335]
    DIRECTION OUTPUT ;
    USE SIGNAL ;
    PORT
      LAYER M5 ;
        RECT  8.304 0 8.328 0.084 ;
    END
  END b_d[335]
  PIN b_d[336]
    DIRECTION OUTPUT ;
    USE SIGNAL ;
    PORT
      LAYER M5 ;
        RECT  8.4 0 8.424 0.084 ;
    END
  END b_d[336]
  PIN b_d[337]
    DIRECTION OUTPUT ;
    USE SIGNAL ;
    PORT
      LAYER M5 ;
        RECT  8.496 0 8.52 0.084 ;
    END
  END b_d[337]
  PIN b_d[338]
    DIRECTION OUTPUT ;
    USE SIGNAL ;
    PORT
      LAYER M5 ;
        RECT  8.592 0 8.616 0.084 ;
    END
  END b_d[338]
  PIN b_d[339]
    DIRECTION OUTPUT ;
    USE SIGNAL ;
    PORT
      LAYER M5 ;
        RECT  8.688 0 8.712 0.084 ;
    END
  END b_d[339]
  PIN b_d[33]
    DIRECTION OUTPUT ;
    USE SIGNAL ;
    PORT
      LAYER M5 ;
        RECT  35.376 0 35.4 0.084 ;
    END
  END b_d[33]
  PIN b_d[340]
    DIRECTION OUTPUT ;
    USE SIGNAL ;
    PORT
      LAYER M5 ;
        RECT  8.784 0 8.808 0.084 ;
    END
  END b_d[340]
  PIN b_d[341]
    DIRECTION OUTPUT ;
    USE SIGNAL ;
    PORT
      LAYER M5 ;
        RECT  8.88 0 8.904 0.084 ;
    END
  END b_d[341]
  PIN b_d[342]
    DIRECTION OUTPUT ;
    USE SIGNAL ;
    PORT
      LAYER M5 ;
        RECT  8.976 0 9 0.084 ;
    END
  END b_d[342]
  PIN b_d[343]
    DIRECTION OUTPUT ;
    USE SIGNAL ;
    PORT
      LAYER M5 ;
        RECT  9.072 0 9.096 0.084 ;
    END
  END b_d[343]
  PIN b_d[344]
    DIRECTION OUTPUT ;
    USE SIGNAL ;
    PORT
      LAYER M5 ;
        RECT  9.168 0 9.192 0.084 ;
    END
  END b_d[344]
  PIN b_d[345]
    DIRECTION OUTPUT ;
    USE SIGNAL ;
    PORT
      LAYER M5 ;
        RECT  9.264 0 9.288 0.084 ;
    END
  END b_d[345]
  PIN b_d[346]
    DIRECTION OUTPUT ;
    USE SIGNAL ;
    PORT
      LAYER M5 ;
        RECT  9.36 0 9.384 0.084 ;
    END
  END b_d[346]
  PIN b_d[347]
    DIRECTION OUTPUT ;
    USE SIGNAL ;
    PORT
      LAYER M5 ;
        RECT  9.456 0 9.48 0.084 ;
    END
  END b_d[347]
  PIN b_d[348]
    DIRECTION OUTPUT ;
    USE SIGNAL ;
    PORT
      LAYER M5 ;
        RECT  9.552 0 9.576 0.084 ;
    END
  END b_d[348]
  PIN b_d[349]
    DIRECTION OUTPUT ;
    USE SIGNAL ;
    PORT
      LAYER M5 ;
        RECT  9.648 0 9.672 0.084 ;
    END
  END b_d[349]
  PIN b_d[34]
    DIRECTION OUTPUT ;
    USE SIGNAL ;
    PORT
      LAYER M5 ;
        RECT  35.472 0 35.496 0.084 ;
    END
  END b_d[34]
  PIN b_d[350]
    DIRECTION OUTPUT ;
    USE SIGNAL ;
    PORT
      LAYER M5 ;
        RECT  9.744 0 9.768 0.084 ;
    END
  END b_d[350]
  PIN b_d[351]
    DIRECTION OUTPUT ;
    USE SIGNAL ;
    PORT
      LAYER M5 ;
        RECT  9.84 0 9.864 0.084 ;
    END
  END b_d[351]
  PIN b_d[352]
    DIRECTION OUTPUT ;
    USE SIGNAL ;
    PORT
      LAYER M5 ;
        RECT  42.192 0 42.216 0.084 ;
    END
  END b_d[352]
  PIN b_d[353]
    DIRECTION OUTPUT ;
    USE SIGNAL ;
    PORT
      LAYER M5 ;
        RECT  42.288 0 42.312 0.084 ;
    END
  END b_d[353]
  PIN b_d[354]
    DIRECTION OUTPUT ;
    USE SIGNAL ;
    PORT
      LAYER M5 ;
        RECT  42.384 0 42.408 0.084 ;
    END
  END b_d[354]
  PIN b_d[355]
    DIRECTION OUTPUT ;
    USE SIGNAL ;
    PORT
      LAYER M5 ;
        RECT  42.48 0 42.504 0.084 ;
    END
  END b_d[355]
  PIN b_d[356]
    DIRECTION OUTPUT ;
    USE SIGNAL ;
    PORT
      LAYER M5 ;
        RECT  42.576 0 42.6 0.084 ;
    END
  END b_d[356]
  PIN b_d[357]
    DIRECTION OUTPUT ;
    USE SIGNAL ;
    PORT
      LAYER M5 ;
        RECT  42.672 0 42.696 0.084 ;
    END
  END b_d[357]
  PIN b_d[358]
    DIRECTION OUTPUT ;
    USE SIGNAL ;
    PORT
      LAYER M5 ;
        RECT  42.768 0 42.792 0.084 ;
    END
  END b_d[358]
  PIN b_d[359]
    DIRECTION OUTPUT ;
    USE SIGNAL ;
    PORT
      LAYER M5 ;
        RECT  42.864 0 42.888 0.084 ;
    END
  END b_d[359]
  PIN b_d[35]
    DIRECTION OUTPUT ;
    USE SIGNAL ;
    PORT
      LAYER M5 ;
        RECT  35.568 0 35.592 0.084 ;
    END
  END b_d[35]
  PIN b_d[360]
    DIRECTION OUTPUT ;
    USE SIGNAL ;
    PORT
      LAYER M5 ;
        RECT  42.96 0 42.984 0.084 ;
    END
  END b_d[360]
  PIN b_d[361]
    DIRECTION OUTPUT ;
    USE SIGNAL ;
    PORT
      LAYER M5 ;
        RECT  43.056 0 43.08 0.084 ;
    END
  END b_d[361]
  PIN b_d[362]
    DIRECTION OUTPUT ;
    USE SIGNAL ;
    PORT
      LAYER M5 ;
        RECT  43.152 0 43.176 0.084 ;
    END
  END b_d[362]
  PIN b_d[363]
    DIRECTION OUTPUT ;
    USE SIGNAL ;
    PORT
      LAYER M5 ;
        RECT  43.248 0 43.272 0.084 ;
    END
  END b_d[363]
  PIN b_d[364]
    DIRECTION OUTPUT ;
    USE SIGNAL ;
    PORT
      LAYER M5 ;
        RECT  43.344 0 43.368 0.084 ;
    END
  END b_d[364]
  PIN b_d[365]
    DIRECTION OUTPUT ;
    USE SIGNAL ;
    PORT
      LAYER M5 ;
        RECT  43.44 0 43.464 0.084 ;
    END
  END b_d[365]
  PIN b_d[366]
    DIRECTION OUTPUT ;
    USE SIGNAL ;
    PORT
      LAYER M5 ;
        RECT  43.536 0 43.56 0.084 ;
    END
  END b_d[366]
  PIN b_d[367]
    DIRECTION OUTPUT ;
    USE SIGNAL ;
    PORT
      LAYER M5 ;
        RECT  43.632 0 43.656 0.084 ;
    END
  END b_d[367]
  PIN b_d[368]
    DIRECTION OUTPUT ;
    USE SIGNAL ;
    PORT
      LAYER M5 ;
        RECT  43.728 0 43.752 0.084 ;
    END
  END b_d[368]
  PIN b_d[369]
    DIRECTION OUTPUT ;
    USE SIGNAL ;
    PORT
      LAYER M5 ;
        RECT  43.824 0 43.848 0.084 ;
    END
  END b_d[369]
  PIN b_d[36]
    DIRECTION OUTPUT ;
    USE SIGNAL ;
    PORT
      LAYER M5 ;
        RECT  35.664 0 35.688 0.084 ;
    END
  END b_d[36]
  PIN b_d[370]
    DIRECTION OUTPUT ;
    USE SIGNAL ;
    PORT
      LAYER M5 ;
        RECT  43.92 0 43.944 0.084 ;
    END
  END b_d[370]
  PIN b_d[371]
    DIRECTION OUTPUT ;
    USE SIGNAL ;
    PORT
      LAYER M5 ;
        RECT  44.016 0 44.04 0.084 ;
    END
  END b_d[371]
  PIN b_d[372]
    DIRECTION OUTPUT ;
    USE SIGNAL ;
    PORT
      LAYER M5 ;
        RECT  44.112 0 44.136 0.084 ;
    END
  END b_d[372]
  PIN b_d[373]
    DIRECTION OUTPUT ;
    USE SIGNAL ;
    PORT
      LAYER M5 ;
        RECT  44.208 0 44.232 0.084 ;
    END
  END b_d[373]
  PIN b_d[374]
    DIRECTION OUTPUT ;
    USE SIGNAL ;
    PORT
      LAYER M5 ;
        RECT  44.304 0 44.328 0.084 ;
    END
  END b_d[374]
  PIN b_d[375]
    DIRECTION OUTPUT ;
    USE SIGNAL ;
    PORT
      LAYER M5 ;
        RECT  44.4 0 44.424 0.084 ;
    END
  END b_d[375]
  PIN b_d[376]
    DIRECTION OUTPUT ;
    USE SIGNAL ;
    PORT
      LAYER M5 ;
        RECT  44.496 0 44.52 0.084 ;
    END
  END b_d[376]
  PIN b_d[377]
    DIRECTION OUTPUT ;
    USE SIGNAL ;
    PORT
      LAYER M5 ;
        RECT  44.592 0 44.616 0.084 ;
    END
  END b_d[377]
  PIN b_d[378]
    DIRECTION OUTPUT ;
    USE SIGNAL ;
    PORT
      LAYER M5 ;
        RECT  44.688 0 44.712 0.084 ;
    END
  END b_d[378]
  PIN b_d[379]
    DIRECTION OUTPUT ;
    USE SIGNAL ;
    PORT
      LAYER M5 ;
        RECT  44.784 0 44.808 0.084 ;
    END
  END b_d[379]
  PIN b_d[37]
    DIRECTION OUTPUT ;
    USE SIGNAL ;
    PORT
      LAYER M5 ;
        RECT  35.76 0 35.784 0.084 ;
    END
  END b_d[37]
  PIN b_d[380]
    DIRECTION OUTPUT ;
    USE SIGNAL ;
    PORT
      LAYER M5 ;
        RECT  44.88 0 44.904 0.084 ;
    END
  END b_d[380]
  PIN b_d[381]
    DIRECTION OUTPUT ;
    USE SIGNAL ;
    PORT
      LAYER M5 ;
        RECT  44.976 0 45 0.084 ;
    END
  END b_d[381]
  PIN b_d[382]
    DIRECTION OUTPUT ;
    USE SIGNAL ;
    PORT
      LAYER M5 ;
        RECT  45.072 0 45.096 0.084 ;
    END
  END b_d[382]
  PIN b_d[383]
    DIRECTION OUTPUT ;
    USE SIGNAL ;
    PORT
      LAYER M5 ;
        RECT  45.168 0 45.192 0.084 ;
    END
  END b_d[383]
  PIN b_d[384]
    DIRECTION OUTPUT ;
    USE SIGNAL ;
    PORT
      LAYER M5 ;
        RECT  16.08 0 16.104 0.084 ;
    END
  END b_d[384]
  PIN b_d[385]
    DIRECTION OUTPUT ;
    USE SIGNAL ;
    PORT
      LAYER M5 ;
        RECT  16.176 0 16.2 0.084 ;
    END
  END b_d[385]
  PIN b_d[386]
    DIRECTION OUTPUT ;
    USE SIGNAL ;
    PORT
      LAYER M5 ;
        RECT  16.272 0 16.296 0.084 ;
    END
  END b_d[386]
  PIN b_d[387]
    DIRECTION OUTPUT ;
    USE SIGNAL ;
    PORT
      LAYER M5 ;
        RECT  16.368 0 16.392 0.084 ;
    END
  END b_d[387]
  PIN b_d[388]
    DIRECTION OUTPUT ;
    USE SIGNAL ;
    PORT
      LAYER M5 ;
        RECT  16.464 0 16.488 0.084 ;
    END
  END b_d[388]
  PIN b_d[389]
    DIRECTION OUTPUT ;
    USE SIGNAL ;
    PORT
      LAYER M5 ;
        RECT  16.56 0 16.584 0.084 ;
    END
  END b_d[389]
  PIN b_d[38]
    DIRECTION OUTPUT ;
    USE SIGNAL ;
    PORT
      LAYER M5 ;
        RECT  35.856 0 35.88 0.084 ;
    END
  END b_d[38]
  PIN b_d[390]
    DIRECTION OUTPUT ;
    USE SIGNAL ;
    PORT
      LAYER M5 ;
        RECT  16.656 0 16.68 0.084 ;
    END
  END b_d[390]
  PIN b_d[391]
    DIRECTION OUTPUT ;
    USE SIGNAL ;
    PORT
      LAYER M5 ;
        RECT  16.752 0 16.776 0.084 ;
    END
  END b_d[391]
  PIN b_d[392]
    DIRECTION OUTPUT ;
    USE SIGNAL ;
    PORT
      LAYER M5 ;
        RECT  16.848 0 16.872 0.084 ;
    END
  END b_d[392]
  PIN b_d[393]
    DIRECTION OUTPUT ;
    USE SIGNAL ;
    PORT
      LAYER M5 ;
        RECT  16.944 0 16.968 0.084 ;
    END
  END b_d[393]
  PIN b_d[394]
    DIRECTION OUTPUT ;
    USE SIGNAL ;
    PORT
      LAYER M5 ;
        RECT  17.04 0 17.064 0.084 ;
    END
  END b_d[394]
  PIN b_d[395]
    DIRECTION OUTPUT ;
    USE SIGNAL ;
    PORT
      LAYER M5 ;
        RECT  17.136 0 17.16 0.084 ;
    END
  END b_d[395]
  PIN b_d[396]
    DIRECTION OUTPUT ;
    USE SIGNAL ;
    PORT
      LAYER M5 ;
        RECT  17.232 0 17.256 0.084 ;
    END
  END b_d[396]
  PIN b_d[397]
    DIRECTION OUTPUT ;
    USE SIGNAL ;
    PORT
      LAYER M5 ;
        RECT  17.328 0 17.352 0.084 ;
    END
  END b_d[397]
  PIN b_d[398]
    DIRECTION OUTPUT ;
    USE SIGNAL ;
    PORT
      LAYER M5 ;
        RECT  17.424 0 17.448 0.084 ;
    END
  END b_d[398]
  PIN b_d[399]
    DIRECTION OUTPUT ;
    USE SIGNAL ;
    PORT
      LAYER M5 ;
        RECT  17.52 0 17.544 0.084 ;
    END
  END b_d[399]
  PIN b_d[39]
    DIRECTION OUTPUT ;
    USE SIGNAL ;
    PORT
      LAYER M5 ;
        RECT  35.952 0 35.976 0.084 ;
    END
  END b_d[39]
  PIN b_d[3]
    DIRECTION OUTPUT ;
    USE SIGNAL ;
    PORT
      LAYER M5 ;
        RECT  26.352 0 26.376 0.084 ;
    END
  END b_d[3]
  PIN b_d[400]
    DIRECTION OUTPUT ;
    USE SIGNAL ;
    PORT
      LAYER M5 ;
        RECT  17.616 0 17.64 0.084 ;
    END
  END b_d[400]
  PIN b_d[401]
    DIRECTION OUTPUT ;
    USE SIGNAL ;
    PORT
      LAYER M5 ;
        RECT  17.712 0 17.736 0.084 ;
    END
  END b_d[401]
  PIN b_d[402]
    DIRECTION OUTPUT ;
    USE SIGNAL ;
    PORT
      LAYER M5 ;
        RECT  17.808 0 17.832 0.084 ;
    END
  END b_d[402]
  PIN b_d[403]
    DIRECTION OUTPUT ;
    USE SIGNAL ;
    PORT
      LAYER M5 ;
        RECT  17.904 0 17.928 0.084 ;
    END
  END b_d[403]
  PIN b_d[404]
    DIRECTION OUTPUT ;
    USE SIGNAL ;
    PORT
      LAYER M5 ;
        RECT  18 0 18.024 0.084 ;
    END
  END b_d[404]
  PIN b_d[405]
    DIRECTION OUTPUT ;
    USE SIGNAL ;
    PORT
      LAYER M5 ;
        RECT  18.096 0 18.12 0.084 ;
    END
  END b_d[405]
  PIN b_d[406]
    DIRECTION OUTPUT ;
    USE SIGNAL ;
    PORT
      LAYER M5 ;
        RECT  18.192 0 18.216 0.084 ;
    END
  END b_d[406]
  PIN b_d[407]
    DIRECTION OUTPUT ;
    USE SIGNAL ;
    PORT
      LAYER M5 ;
        RECT  18.288 0 18.312 0.084 ;
    END
  END b_d[407]
  PIN b_d[408]
    DIRECTION OUTPUT ;
    USE SIGNAL ;
    PORT
      LAYER M5 ;
        RECT  18.384 0 18.408 0.084 ;
    END
  END b_d[408]
  PIN b_d[409]
    DIRECTION OUTPUT ;
    USE SIGNAL ;
    PORT
      LAYER M5 ;
        RECT  18.48 0 18.504 0.084 ;
    END
  END b_d[409]
  PIN b_d[40]
    DIRECTION OUTPUT ;
    USE SIGNAL ;
    PORT
      LAYER M5 ;
        RECT  36.048 0 36.072 0.084 ;
    END
  END b_d[40]
  PIN b_d[410]
    DIRECTION OUTPUT ;
    USE SIGNAL ;
    PORT
      LAYER M5 ;
        RECT  18.576 0 18.6 0.084 ;
    END
  END b_d[410]
  PIN b_d[411]
    DIRECTION OUTPUT ;
    USE SIGNAL ;
    PORT
      LAYER M5 ;
        RECT  18.672 0 18.696 0.084 ;
    END
  END b_d[411]
  PIN b_d[412]
    DIRECTION OUTPUT ;
    USE SIGNAL ;
    PORT
      LAYER M5 ;
        RECT  18.768 0 18.792 0.084 ;
    END
  END b_d[412]
  PIN b_d[413]
    DIRECTION OUTPUT ;
    USE SIGNAL ;
    PORT
      LAYER M5 ;
        RECT  18.864 0 18.888 0.084 ;
    END
  END b_d[413]
  PIN b_d[414]
    DIRECTION OUTPUT ;
    USE SIGNAL ;
    PORT
      LAYER M5 ;
        RECT  18.96 0 18.984 0.084 ;
    END
  END b_d[414]
  PIN b_d[415]
    DIRECTION OUTPUT ;
    USE SIGNAL ;
    PORT
      LAYER M5 ;
        RECT  19.056 0 19.08 0.084 ;
    END
  END b_d[415]
  PIN b_d[416]
    DIRECTION OUTPUT ;
    USE SIGNAL ;
    PORT
      LAYER M5 ;
        RECT  9.936 0 9.96 0.084 ;
    END
  END b_d[416]
  PIN b_d[417]
    DIRECTION OUTPUT ;
    USE SIGNAL ;
    PORT
      LAYER M5 ;
        RECT  10.032 0 10.056 0.084 ;
    END
  END b_d[417]
  PIN b_d[418]
    DIRECTION OUTPUT ;
    USE SIGNAL ;
    PORT
      LAYER M5 ;
        RECT  10.128 0 10.152 0.084 ;
    END
  END b_d[418]
  PIN b_d[419]
    DIRECTION OUTPUT ;
    USE SIGNAL ;
    PORT
      LAYER M5 ;
        RECT  10.224 0 10.248 0.084 ;
    END
  END b_d[419]
  PIN b_d[41]
    DIRECTION OUTPUT ;
    USE SIGNAL ;
    PORT
      LAYER M5 ;
        RECT  36.144 0 36.168 0.084 ;
    END
  END b_d[41]
  PIN b_d[420]
    DIRECTION OUTPUT ;
    USE SIGNAL ;
    PORT
      LAYER M5 ;
        RECT  10.32 0 10.344 0.084 ;
    END
  END b_d[420]
  PIN b_d[421]
    DIRECTION OUTPUT ;
    USE SIGNAL ;
    PORT
      LAYER M5 ;
        RECT  10.416 0 10.44 0.084 ;
    END
  END b_d[421]
  PIN b_d[422]
    DIRECTION OUTPUT ;
    USE SIGNAL ;
    PORT
      LAYER M5 ;
        RECT  10.512 0 10.536 0.084 ;
    END
  END b_d[422]
  PIN b_d[423]
    DIRECTION OUTPUT ;
    USE SIGNAL ;
    PORT
      LAYER M5 ;
        RECT  10.608 0 10.632 0.084 ;
    END
  END b_d[423]
  PIN b_d[424]
    DIRECTION OUTPUT ;
    USE SIGNAL ;
    PORT
      LAYER M5 ;
        RECT  10.704 0 10.728 0.084 ;
    END
  END b_d[424]
  PIN b_d[425]
    DIRECTION OUTPUT ;
    USE SIGNAL ;
    PORT
      LAYER M5 ;
        RECT  10.8 0 10.824 0.084 ;
    END
  END b_d[425]
  PIN b_d[426]
    DIRECTION OUTPUT ;
    USE SIGNAL ;
    PORT
      LAYER M5 ;
        RECT  10.896 0 10.92 0.084 ;
    END
  END b_d[426]
  PIN b_d[427]
    DIRECTION OUTPUT ;
    USE SIGNAL ;
    PORT
      LAYER M5 ;
        RECT  10.992 0 11.016 0.084 ;
    END
  END b_d[427]
  PIN b_d[428]
    DIRECTION OUTPUT ;
    USE SIGNAL ;
    PORT
      LAYER M5 ;
        RECT  11.088 0 11.112 0.084 ;
    END
  END b_d[428]
  PIN b_d[429]
    DIRECTION OUTPUT ;
    USE SIGNAL ;
    PORT
      LAYER M5 ;
        RECT  11.184 0 11.208 0.084 ;
    END
  END b_d[429]
  PIN b_d[42]
    DIRECTION OUTPUT ;
    USE SIGNAL ;
    PORT
      LAYER M5 ;
        RECT  36.24 0 36.264 0.084 ;
    END
  END b_d[42]
  PIN b_d[430]
    DIRECTION OUTPUT ;
    USE SIGNAL ;
    PORT
      LAYER M5 ;
        RECT  11.28 0 11.304 0.084 ;
    END
  END b_d[430]
  PIN b_d[431]
    DIRECTION OUTPUT ;
    USE SIGNAL ;
    PORT
      LAYER M5 ;
        RECT  11.376 0 11.4 0.084 ;
    END
  END b_d[431]
  PIN b_d[432]
    DIRECTION OUTPUT ;
    USE SIGNAL ;
    PORT
      LAYER M5 ;
        RECT  11.472 0 11.496 0.084 ;
    END
  END b_d[432]
  PIN b_d[433]
    DIRECTION OUTPUT ;
    USE SIGNAL ;
    PORT
      LAYER M5 ;
        RECT  11.568 0 11.592 0.084 ;
    END
  END b_d[433]
  PIN b_d[434]
    DIRECTION OUTPUT ;
    USE SIGNAL ;
    PORT
      LAYER M5 ;
        RECT  11.664 0 11.688 0.084 ;
    END
  END b_d[434]
  PIN b_d[435]
    DIRECTION OUTPUT ;
    USE SIGNAL ;
    PORT
      LAYER M5 ;
        RECT  11.76 0 11.784 0.084 ;
    END
  END b_d[435]
  PIN b_d[436]
    DIRECTION OUTPUT ;
    USE SIGNAL ;
    PORT
      LAYER M5 ;
        RECT  11.856 0 11.88 0.084 ;
    END
  END b_d[436]
  PIN b_d[437]
    DIRECTION OUTPUT ;
    USE SIGNAL ;
    PORT
      LAYER M5 ;
        RECT  11.952 0 11.976 0.084 ;
    END
  END b_d[437]
  PIN b_d[438]
    DIRECTION OUTPUT ;
    USE SIGNAL ;
    PORT
      LAYER M5 ;
        RECT  12.048 0 12.072 0.084 ;
    END
  END b_d[438]
  PIN b_d[439]
    DIRECTION OUTPUT ;
    USE SIGNAL ;
    PORT
      LAYER M5 ;
        RECT  12.144 0 12.168 0.084 ;
    END
  END b_d[439]
  PIN b_d[43]
    DIRECTION OUTPUT ;
    USE SIGNAL ;
    PORT
      LAYER M5 ;
        RECT  36.336 0 36.36 0.084 ;
    END
  END b_d[43]
  PIN b_d[440]
    DIRECTION OUTPUT ;
    USE SIGNAL ;
    PORT
      LAYER M5 ;
        RECT  12.24 0 12.264 0.084 ;
    END
  END b_d[440]
  PIN b_d[441]
    DIRECTION OUTPUT ;
    USE SIGNAL ;
    PORT
      LAYER M5 ;
        RECT  12.336 0 12.36 0.084 ;
    END
  END b_d[441]
  PIN b_d[442]
    DIRECTION OUTPUT ;
    USE SIGNAL ;
    PORT
      LAYER M5 ;
        RECT  12.432 0 12.456 0.084 ;
    END
  END b_d[442]
  PIN b_d[443]
    DIRECTION OUTPUT ;
    USE SIGNAL ;
    PORT
      LAYER M5 ;
        RECT  12.528 0 12.552 0.084 ;
    END
  END b_d[443]
  PIN b_d[444]
    DIRECTION OUTPUT ;
    USE SIGNAL ;
    PORT
      LAYER M5 ;
        RECT  12.624 0 12.648 0.084 ;
    END
  END b_d[444]
  PIN b_d[445]
    DIRECTION OUTPUT ;
    USE SIGNAL ;
    PORT
      LAYER M5 ;
        RECT  12.72 0 12.744 0.084 ;
    END
  END b_d[445]
  PIN b_d[446]
    DIRECTION OUTPUT ;
    USE SIGNAL ;
    PORT
      LAYER M5 ;
        RECT  12.816 0 12.84 0.084 ;
    END
  END b_d[446]
  PIN b_d[447]
    DIRECTION OUTPUT ;
    USE SIGNAL ;
    PORT
      LAYER M5 ;
        RECT  12.912 0 12.936 0.084 ;
    END
  END b_d[447]
  PIN b_d[448]
    DIRECTION OUTPUT ;
    USE SIGNAL ;
    PORT
      LAYER M5 ;
        RECT  13.008 0 13.032 0.084 ;
    END
  END b_d[448]
  PIN b_d[449]
    DIRECTION OUTPUT ;
    USE SIGNAL ;
    PORT
      LAYER M5 ;
        RECT  13.104 0 13.128 0.084 ;
    END
  END b_d[449]
  PIN b_d[44]
    DIRECTION OUTPUT ;
    USE SIGNAL ;
    PORT
      LAYER M5 ;
        RECT  36.432 0 36.456 0.084 ;
    END
  END b_d[44]
  PIN b_d[450]
    DIRECTION OUTPUT ;
    USE SIGNAL ;
    PORT
      LAYER M5 ;
        RECT  13.2 0 13.224 0.084 ;
    END
  END b_d[450]
  PIN b_d[451]
    DIRECTION OUTPUT ;
    USE SIGNAL ;
    PORT
      LAYER M5 ;
        RECT  13.296 0 13.32 0.084 ;
    END
  END b_d[451]
  PIN b_d[452]
    DIRECTION OUTPUT ;
    USE SIGNAL ;
    PORT
      LAYER M5 ;
        RECT  13.392 0 13.416 0.084 ;
    END
  END b_d[452]
  PIN b_d[453]
    DIRECTION OUTPUT ;
    USE SIGNAL ;
    PORT
      LAYER M5 ;
        RECT  13.488 0 13.512 0.084 ;
    END
  END b_d[453]
  PIN b_d[454]
    DIRECTION OUTPUT ;
    USE SIGNAL ;
    PORT
      LAYER M5 ;
        RECT  13.584 0 13.608 0.084 ;
    END
  END b_d[454]
  PIN b_d[455]
    DIRECTION OUTPUT ;
    USE SIGNAL ;
    PORT
      LAYER M5 ;
        RECT  13.68 0 13.704 0.084 ;
    END
  END b_d[455]
  PIN b_d[456]
    DIRECTION OUTPUT ;
    USE SIGNAL ;
    PORT
      LAYER M5 ;
        RECT  13.776 0 13.8 0.084 ;
    END
  END b_d[456]
  PIN b_d[457]
    DIRECTION OUTPUT ;
    USE SIGNAL ;
    PORT
      LAYER M5 ;
        RECT  13.872 0 13.896 0.084 ;
    END
  END b_d[457]
  PIN b_d[458]
    DIRECTION OUTPUT ;
    USE SIGNAL ;
    PORT
      LAYER M5 ;
        RECT  13.968 0 13.992 0.084 ;
    END
  END b_d[458]
  PIN b_d[459]
    DIRECTION OUTPUT ;
    USE SIGNAL ;
    PORT
      LAYER M5 ;
        RECT  14.064 0 14.088 0.084 ;
    END
  END b_d[459]
  PIN b_d[45]
    DIRECTION OUTPUT ;
    USE SIGNAL ;
    PORT
      LAYER M5 ;
        RECT  36.528 0 36.552 0.084 ;
    END
  END b_d[45]
  PIN b_d[460]
    DIRECTION OUTPUT ;
    USE SIGNAL ;
    PORT
      LAYER M5 ;
        RECT  14.16 0 14.184 0.084 ;
    END
  END b_d[460]
  PIN b_d[461]
    DIRECTION OUTPUT ;
    USE SIGNAL ;
    PORT
      LAYER M5 ;
        RECT  14.256 0 14.28 0.084 ;
    END
  END b_d[461]
  PIN b_d[462]
    DIRECTION OUTPUT ;
    USE SIGNAL ;
    PORT
      LAYER M5 ;
        RECT  14.352 0 14.376 0.084 ;
    END
  END b_d[462]
  PIN b_d[463]
    DIRECTION OUTPUT ;
    USE SIGNAL ;
    PORT
      LAYER M5 ;
        RECT  14.448 0 14.472 0.084 ;
    END
  END b_d[463]
  PIN b_d[464]
    DIRECTION OUTPUT ;
    USE SIGNAL ;
    PORT
      LAYER M5 ;
        RECT  14.544 0 14.568 0.084 ;
    END
  END b_d[464]
  PIN b_d[465]
    DIRECTION OUTPUT ;
    USE SIGNAL ;
    PORT
      LAYER M5 ;
        RECT  14.64 0 14.664 0.084 ;
    END
  END b_d[465]
  PIN b_d[466]
    DIRECTION OUTPUT ;
    USE SIGNAL ;
    PORT
      LAYER M5 ;
        RECT  14.736 0 14.76 0.084 ;
    END
  END b_d[466]
  PIN b_d[467]
    DIRECTION OUTPUT ;
    USE SIGNAL ;
    PORT
      LAYER M5 ;
        RECT  14.832 0 14.856 0.084 ;
    END
  END b_d[467]
  PIN b_d[468]
    DIRECTION OUTPUT ;
    USE SIGNAL ;
    PORT
      LAYER M5 ;
        RECT  14.928 0 14.952 0.084 ;
    END
  END b_d[468]
  PIN b_d[469]
    DIRECTION OUTPUT ;
    USE SIGNAL ;
    PORT
      LAYER M5 ;
        RECT  15.024 0 15.048 0.084 ;
    END
  END b_d[469]
  PIN b_d[46]
    DIRECTION OUTPUT ;
    USE SIGNAL ;
    PORT
      LAYER M5 ;
        RECT  36.624 0 36.648 0.084 ;
    END
  END b_d[46]
  PIN b_d[470]
    DIRECTION OUTPUT ;
    USE SIGNAL ;
    PORT
      LAYER M5 ;
        RECT  15.12 0 15.144 0.084 ;
    END
  END b_d[470]
  PIN b_d[471]
    DIRECTION OUTPUT ;
    USE SIGNAL ;
    PORT
      LAYER M5 ;
        RECT  15.216 0 15.24 0.084 ;
    END
  END b_d[471]
  PIN b_d[472]
    DIRECTION OUTPUT ;
    USE SIGNAL ;
    PORT
      LAYER M5 ;
        RECT  15.312 0 15.336 0.084 ;
    END
  END b_d[472]
  PIN b_d[473]
    DIRECTION OUTPUT ;
    USE SIGNAL ;
    PORT
      LAYER M5 ;
        RECT  15.408 0 15.432 0.084 ;
    END
  END b_d[473]
  PIN b_d[474]
    DIRECTION OUTPUT ;
    USE SIGNAL ;
    PORT
      LAYER M5 ;
        RECT  15.504 0 15.528 0.084 ;
    END
  END b_d[474]
  PIN b_d[475]
    DIRECTION OUTPUT ;
    USE SIGNAL ;
    PORT
      LAYER M5 ;
        RECT  15.6 0 15.624 0.084 ;
    END
  END b_d[475]
  PIN b_d[476]
    DIRECTION OUTPUT ;
    USE SIGNAL ;
    PORT
      LAYER M5 ;
        RECT  15.696 0 15.72 0.084 ;
    END
  END b_d[476]
  PIN b_d[477]
    DIRECTION OUTPUT ;
    USE SIGNAL ;
    PORT
      LAYER M5 ;
        RECT  15.792 0 15.816 0.084 ;
    END
  END b_d[477]
  PIN b_d[478]
    DIRECTION OUTPUT ;
    USE SIGNAL ;
    PORT
      LAYER M5 ;
        RECT  15.888 0 15.912 0.084 ;
    END
  END b_d[478]
  PIN b_d[479]
    DIRECTION OUTPUT ;
    USE SIGNAL ;
    PORT
      LAYER M5 ;
        RECT  15.984 0 16.008 0.084 ;
    END
  END b_d[479]
  PIN b_d[47]
    DIRECTION OUTPUT ;
    USE SIGNAL ;
    PORT
      LAYER M5 ;
        RECT  36.72 0 36.744 0.084 ;
    END
  END b_d[47]
  PIN b_d[480]
    DIRECTION OUTPUT ;
    USE SIGNAL ;
    PORT
      LAYER M5 ;
        RECT  0.72 0 0.744 0.084 ;
    END
  END b_d[480]
  PIN b_d[481]
    DIRECTION OUTPUT ;
    USE SIGNAL ;
    PORT
      LAYER M5 ;
        RECT  0.816 0 0.84 0.084 ;
    END
  END b_d[481]
  PIN b_d[482]
    DIRECTION OUTPUT ;
    USE SIGNAL ;
    PORT
      LAYER M5 ;
        RECT  0.912 0 0.936 0.084 ;
    END
  END b_d[482]
  PIN b_d[483]
    DIRECTION OUTPUT ;
    USE SIGNAL ;
    PORT
      LAYER M5 ;
        RECT  1.008 0 1.032 0.084 ;
    END
  END b_d[483]
  PIN b_d[484]
    DIRECTION OUTPUT ;
    USE SIGNAL ;
    PORT
      LAYER M5 ;
        RECT  1.104 0 1.128 0.084 ;
    END
  END b_d[484]
  PIN b_d[485]
    DIRECTION OUTPUT ;
    USE SIGNAL ;
    PORT
      LAYER M5 ;
        RECT  1.2 0 1.224 0.084 ;
    END
  END b_d[485]
  PIN b_d[486]
    DIRECTION OUTPUT ;
    USE SIGNAL ;
    PORT
      LAYER M5 ;
        RECT  1.296 0 1.32 0.084 ;
    END
  END b_d[486]
  PIN b_d[487]
    DIRECTION OUTPUT ;
    USE SIGNAL ;
    PORT
      LAYER M5 ;
        RECT  1.392 0 1.416 0.084 ;
    END
  END b_d[487]
  PIN b_d[488]
    DIRECTION OUTPUT ;
    USE SIGNAL ;
    PORT
      LAYER M5 ;
        RECT  1.488 0 1.512 0.084 ;
    END
  END b_d[488]
  PIN b_d[489]
    DIRECTION OUTPUT ;
    USE SIGNAL ;
    PORT
      LAYER M5 ;
        RECT  1.584 0 1.608 0.084 ;
    END
  END b_d[489]
  PIN b_d[48]
    DIRECTION OUTPUT ;
    USE SIGNAL ;
    PORT
      LAYER M5 ;
        RECT  36.816 0 36.84 0.084 ;
    END
  END b_d[48]
  PIN b_d[490]
    DIRECTION OUTPUT ;
    USE SIGNAL ;
    PORT
      LAYER M5 ;
        RECT  1.68 0 1.704 0.084 ;
    END
  END b_d[490]
  PIN b_d[491]
    DIRECTION OUTPUT ;
    USE SIGNAL ;
    PORT
      LAYER M5 ;
        RECT  1.776 0 1.8 0.084 ;
    END
  END b_d[491]
  PIN b_d[492]
    DIRECTION OUTPUT ;
    USE SIGNAL ;
    PORT
      LAYER M5 ;
        RECT  1.872 0 1.896 0.084 ;
    END
  END b_d[492]
  PIN b_d[493]
    DIRECTION OUTPUT ;
    USE SIGNAL ;
    PORT
      LAYER M5 ;
        RECT  1.968 0 1.992 0.084 ;
    END
  END b_d[493]
  PIN b_d[494]
    DIRECTION OUTPUT ;
    USE SIGNAL ;
    PORT
      LAYER M5 ;
        RECT  2.064 0 2.088 0.084 ;
    END
  END b_d[494]
  PIN b_d[495]
    DIRECTION OUTPUT ;
    USE SIGNAL ;
    PORT
      LAYER M5 ;
        RECT  2.16 0 2.184 0.084 ;
    END
  END b_d[495]
  PIN b_d[496]
    DIRECTION OUTPUT ;
    USE SIGNAL ;
    PORT
      LAYER M5 ;
        RECT  2.256 0 2.28 0.084 ;
    END
  END b_d[496]
  PIN b_d[497]
    DIRECTION OUTPUT ;
    USE SIGNAL ;
    PORT
      LAYER M5 ;
        RECT  2.352 0 2.376 0.084 ;
    END
  END b_d[497]
  PIN b_d[498]
    DIRECTION OUTPUT ;
    USE SIGNAL ;
    PORT
      LAYER M5 ;
        RECT  2.448 0 2.472 0.084 ;
    END
  END b_d[498]
  PIN b_d[499]
    DIRECTION OUTPUT ;
    USE SIGNAL ;
    PORT
      LAYER M5 ;
        RECT  2.544 0 2.568 0.084 ;
    END
  END b_d[499]
  PIN b_d[49]
    DIRECTION OUTPUT ;
    USE SIGNAL ;
    PORT
      LAYER M5 ;
        RECT  36.912 0 36.936 0.084 ;
    END
  END b_d[49]
  PIN b_d[4]
    DIRECTION OUTPUT ;
    USE SIGNAL ;
    PORT
      LAYER M5 ;
        RECT  26.448 0 26.472 0.084 ;
    END
  END b_d[4]
  PIN b_d[500]
    DIRECTION OUTPUT ;
    USE SIGNAL ;
    PORT
      LAYER M5 ;
        RECT  2.64 0 2.664 0.084 ;
    END
  END b_d[500]
  PIN b_d[501]
    DIRECTION OUTPUT ;
    USE SIGNAL ;
    PORT
      LAYER M5 ;
        RECT  2.736 0 2.76 0.084 ;
    END
  END b_d[501]
  PIN b_d[502]
    DIRECTION OUTPUT ;
    USE SIGNAL ;
    PORT
      LAYER M5 ;
        RECT  2.832 0 2.856 0.084 ;
    END
  END b_d[502]
  PIN b_d[503]
    DIRECTION OUTPUT ;
    USE SIGNAL ;
    PORT
      LAYER M5 ;
        RECT  2.928 0 2.952 0.084 ;
    END
  END b_d[503]
  PIN b_d[504]
    DIRECTION OUTPUT ;
    USE SIGNAL ;
    PORT
      LAYER M5 ;
        RECT  3.024 0 3.048 0.084 ;
    END
  END b_d[504]
  PIN b_d[505]
    DIRECTION OUTPUT ;
    USE SIGNAL ;
    PORT
      LAYER M5 ;
        RECT  3.12 0 3.144 0.084 ;
    END
  END b_d[505]
  PIN b_d[506]
    DIRECTION OUTPUT ;
    USE SIGNAL ;
    PORT
      LAYER M5 ;
        RECT  3.216 0 3.24 0.084 ;
    END
  END b_d[506]
  PIN b_d[507]
    DIRECTION OUTPUT ;
    USE SIGNAL ;
    PORT
      LAYER M5 ;
        RECT  3.312 0 3.336 0.084 ;
    END
  END b_d[507]
  PIN b_d[50]
    DIRECTION OUTPUT ;
    USE SIGNAL ;
    PORT
      LAYER M5 ;
        RECT  37.008 0 37.032 0.084 ;
    END
  END b_d[50]
  PIN b_d[51]
    DIRECTION OUTPUT ;
    USE SIGNAL ;
    PORT
      LAYER M5 ;
        RECT  37.104 0 37.128 0.084 ;
    END
  END b_d[51]
  PIN b_d[52]
    DIRECTION OUTPUT ;
    USE SIGNAL ;
    PORT
      LAYER M5 ;
        RECT  37.2 0 37.224 0.084 ;
    END
  END b_d[52]
  PIN b_d[53]
    DIRECTION OUTPUT ;
    USE SIGNAL ;
    PORT
      LAYER M5 ;
        RECT  37.296 0 37.32 0.084 ;
    END
  END b_d[53]
  PIN b_d[54]
    DIRECTION OUTPUT ;
    USE SIGNAL ;
    PORT
      LAYER M5 ;
        RECT  37.392 0 37.416 0.084 ;
    END
  END b_d[54]
  PIN b_d[55]
    DIRECTION OUTPUT ;
    USE SIGNAL ;
    PORT
      LAYER M5 ;
        RECT  37.488 0 37.512 0.084 ;
    END
  END b_d[55]
  PIN b_d[56]
    DIRECTION OUTPUT ;
    USE SIGNAL ;
    PORT
      LAYER M5 ;
        RECT  37.584 0 37.608 0.084 ;
    END
  END b_d[56]
  PIN b_d[57]
    DIRECTION OUTPUT ;
    USE SIGNAL ;
    PORT
      LAYER M5 ;
        RECT  37.68 0 37.704 0.084 ;
    END
  END b_d[57]
  PIN b_d[58]
    DIRECTION OUTPUT ;
    USE SIGNAL ;
    PORT
      LAYER M5 ;
        RECT  37.776 0 37.8 0.084 ;
    END
  END b_d[58]
  PIN b_d[59]
    DIRECTION OUTPUT ;
    USE SIGNAL ;
    PORT
      LAYER M5 ;
        RECT  37.872 0 37.896 0.084 ;
    END
  END b_d[59]
  PIN b_d[5]
    DIRECTION OUTPUT ;
    USE SIGNAL ;
    PORT
      LAYER M5 ;
        RECT  26.544 0 26.568 0.084 ;
    END
  END b_d[5]
  PIN b_d[60]
    DIRECTION OUTPUT ;
    USE SIGNAL ;
    PORT
      LAYER M5 ;
        RECT  37.968 0 37.992 0.084 ;
    END
  END b_d[60]
  PIN b_d[61]
    DIRECTION OUTPUT ;
    USE SIGNAL ;
    PORT
      LAYER M5 ;
        RECT  38.064 0 38.088 0.084 ;
    END
  END b_d[61]
  PIN b_d[62]
    DIRECTION OUTPUT ;
    USE SIGNAL ;
    PORT
      LAYER M5 ;
        RECT  38.16 0 38.184 0.084 ;
    END
  END b_d[62]
  PIN b_d[63]
    DIRECTION OUTPUT ;
    USE SIGNAL ;
    PORT
      LAYER M5 ;
        RECT  38.256 0 38.28 0.084 ;
    END
  END b_d[63]
  PIN b_d[64]
    DIRECTION OUTPUT ;
    USE SIGNAL ;
    PORT
      LAYER M5 ;
        RECT  29.136 0 29.16 0.084 ;
    END
  END b_d[64]
  PIN b_d[65]
    DIRECTION OUTPUT ;
    USE SIGNAL ;
    PORT
      LAYER M5 ;
        RECT  29.232 0 29.256 0.084 ;
    END
  END b_d[65]
  PIN b_d[66]
    DIRECTION OUTPUT ;
    USE SIGNAL ;
    PORT
      LAYER M5 ;
        RECT  29.328 0 29.352 0.084 ;
    END
  END b_d[66]
  PIN b_d[67]
    DIRECTION OUTPUT ;
    USE SIGNAL ;
    PORT
      LAYER M5 ;
        RECT  29.424 0 29.448 0.084 ;
    END
  END b_d[67]
  PIN b_d[68]
    DIRECTION OUTPUT ;
    USE SIGNAL ;
    PORT
      LAYER M5 ;
        RECT  29.52 0 29.544 0.084 ;
    END
  END b_d[68]
  PIN b_d[69]
    DIRECTION OUTPUT ;
    USE SIGNAL ;
    PORT
      LAYER M5 ;
        RECT  29.616 0 29.64 0.084 ;
    END
  END b_d[69]
  PIN b_d[6]
    DIRECTION OUTPUT ;
    USE SIGNAL ;
    PORT
      LAYER M5 ;
        RECT  26.64 0 26.664 0.084 ;
    END
  END b_d[6]
  PIN b_d[70]
    DIRECTION OUTPUT ;
    USE SIGNAL ;
    PORT
      LAYER M5 ;
        RECT  29.712 0 29.736 0.084 ;
    END
  END b_d[70]
  PIN b_d[71]
    DIRECTION OUTPUT ;
    USE SIGNAL ;
    PORT
      LAYER M5 ;
        RECT  29.808 0 29.832 0.084 ;
    END
  END b_d[71]
  PIN b_d[72]
    DIRECTION OUTPUT ;
    USE SIGNAL ;
    PORT
      LAYER M5 ;
        RECT  29.904 0 29.928 0.084 ;
    END
  END b_d[72]
  PIN b_d[73]
    DIRECTION OUTPUT ;
    USE SIGNAL ;
    PORT
      LAYER M5 ;
        RECT  30 0 30.024 0.084 ;
    END
  END b_d[73]
  PIN b_d[74]
    DIRECTION OUTPUT ;
    USE SIGNAL ;
    PORT
      LAYER M5 ;
        RECT  30.096 0 30.12 0.084 ;
    END
  END b_d[74]
  PIN b_d[75]
    DIRECTION OUTPUT ;
    USE SIGNAL ;
    PORT
      LAYER M5 ;
        RECT  30.192 0 30.216 0.084 ;
    END
  END b_d[75]
  PIN b_d[76]
    DIRECTION OUTPUT ;
    USE SIGNAL ;
    PORT
      LAYER M5 ;
        RECT  30.288 0 30.312 0.084 ;
    END
  END b_d[76]
  PIN b_d[77]
    DIRECTION OUTPUT ;
    USE SIGNAL ;
    PORT
      LAYER M5 ;
        RECT  30.384 0 30.408 0.084 ;
    END
  END b_d[77]
  PIN b_d[78]
    DIRECTION OUTPUT ;
    USE SIGNAL ;
    PORT
      LAYER M5 ;
        RECT  30.48 0 30.504 0.084 ;
    END
  END b_d[78]
  PIN b_d[79]
    DIRECTION OUTPUT ;
    USE SIGNAL ;
    PORT
      LAYER M5 ;
        RECT  30.576 0 30.6 0.084 ;
    END
  END b_d[79]
  PIN b_d[7]
    DIRECTION OUTPUT ;
    USE SIGNAL ;
    PORT
      LAYER M5 ;
        RECT  26.736 0 26.76 0.084 ;
    END
  END b_d[7]
  PIN b_d[80]
    DIRECTION OUTPUT ;
    USE SIGNAL ;
    PORT
      LAYER M5 ;
        RECT  30.672 0 30.696 0.084 ;
    END
  END b_d[80]
  PIN b_d[81]
    DIRECTION OUTPUT ;
    USE SIGNAL ;
    PORT
      LAYER M5 ;
        RECT  30.768 0 30.792 0.084 ;
    END
  END b_d[81]
  PIN b_d[82]
    DIRECTION OUTPUT ;
    USE SIGNAL ;
    PORT
      LAYER M5 ;
        RECT  30.864 0 30.888 0.084 ;
    END
  END b_d[82]
  PIN b_d[83]
    DIRECTION OUTPUT ;
    USE SIGNAL ;
    PORT
      LAYER M5 ;
        RECT  30.96 0 30.984 0.084 ;
    END
  END b_d[83]
  PIN b_d[84]
    DIRECTION OUTPUT ;
    USE SIGNAL ;
    PORT
      LAYER M5 ;
        RECT  31.056 0 31.08 0.084 ;
    END
  END b_d[84]
  PIN b_d[85]
    DIRECTION OUTPUT ;
    USE SIGNAL ;
    PORT
      LAYER M5 ;
        RECT  31.152 0 31.176 0.084 ;
    END
  END b_d[85]
  PIN b_d[86]
    DIRECTION OUTPUT ;
    USE SIGNAL ;
    PORT
      LAYER M5 ;
        RECT  31.248 0 31.272 0.084 ;
    END
  END b_d[86]
  PIN b_d[87]
    DIRECTION OUTPUT ;
    USE SIGNAL ;
    PORT
      LAYER M5 ;
        RECT  31.344 0 31.368 0.084 ;
    END
  END b_d[87]
  PIN b_d[88]
    DIRECTION OUTPUT ;
    USE SIGNAL ;
    PORT
      LAYER M5 ;
        RECT  31.44 0 31.464 0.084 ;
    END
  END b_d[88]
  PIN b_d[89]
    DIRECTION OUTPUT ;
    USE SIGNAL ;
    PORT
      LAYER M5 ;
        RECT  31.536 0 31.56 0.084 ;
    END
  END b_d[89]
  PIN b_d[8]
    DIRECTION OUTPUT ;
    USE SIGNAL ;
    PORT
      LAYER M5 ;
        RECT  26.832 0 26.856 0.084 ;
    END
  END b_d[8]
  PIN b_d[90]
    DIRECTION OUTPUT ;
    USE SIGNAL ;
    PORT
      LAYER M5 ;
        RECT  31.632 0 31.656 0.084 ;
    END
  END b_d[90]
  PIN b_d[91]
    DIRECTION OUTPUT ;
    USE SIGNAL ;
    PORT
      LAYER M5 ;
        RECT  31.728 0 31.752 0.084 ;
    END
  END b_d[91]
  PIN b_d[92]
    DIRECTION OUTPUT ;
    USE SIGNAL ;
    PORT
      LAYER M5 ;
        RECT  31.824 0 31.848 0.084 ;
    END
  END b_d[92]
  PIN b_d[93]
    DIRECTION OUTPUT ;
    USE SIGNAL ;
    PORT
      LAYER M5 ;
        RECT  31.92 0 31.944 0.084 ;
    END
  END b_d[93]
  PIN b_d[94]
    DIRECTION OUTPUT ;
    USE SIGNAL ;
    PORT
      LAYER M5 ;
        RECT  32.016 0 32.04 0.084 ;
    END
  END b_d[94]
  PIN b_d[95]
    DIRECTION OUTPUT ;
    USE SIGNAL ;
    PORT
      LAYER M5 ;
        RECT  32.112 0 32.136 0.084 ;
    END
  END b_d[95]
  PIN b_d[96]
    DIRECTION OUTPUT ;
    USE SIGNAL ;
    PORT
      LAYER M5 ;
        RECT  32.208 0 32.232 0.084 ;
    END
  END b_d[96]
  PIN b_d[97]
    DIRECTION OUTPUT ;
    USE SIGNAL ;
    PORT
      LAYER M5 ;
        RECT  32.304 0 32.328 0.084 ;
    END
  END b_d[97]
  PIN b_d[98]
    DIRECTION OUTPUT ;
    USE SIGNAL ;
    PORT
      LAYER M5 ;
        RECT  32.4 0 32.424 0.084 ;
    END
  END b_d[98]
  PIN b_d[99]
    DIRECTION OUTPUT ;
    USE SIGNAL ;
    PORT
      LAYER M5 ;
        RECT  32.496 0 32.52 0.084 ;
    END
  END b_d[99]
  PIN b_d[9]
    DIRECTION OUTPUT ;
    USE SIGNAL ;
    PORT
      LAYER M5 ;
        RECT  26.928 0 26.952 0.084 ;
    END
  END b_d[9]
  PIN b_r
    DIRECTION INPUT ;
    USE SIGNAL ;
    PORT
      LAYER M5 ;
        RECT  3.408 0 3.432 0.084 ;
    END
  END b_r
  PIN ck
    DIRECTION INPUT ;
    USE SIGNAL ;
    PORT
      LAYER M5 ;
        RECT  4.176 103.572 4.2 103.656 ;
    END
  END ck
  PIN rst_n
    DIRECTION INPUT ;
    USE SIGNAL ;
    PORT
      LAYER M5 ;
        RECT  4.272 103.572 4.296 103.656 ;
    END
  END rst_n
  PIN tap_d[0]
    DIRECTION OUTPUT ;
    USE SIGNAL ;
    PORT
      LAYER M4 ;
        RECT  0 58.416 0.084 58.44 ;
    END
  END tap_d[0]
  PIN tap_d[100]
    DIRECTION OUTPUT ;
    USE SIGNAL ;
    PORT
      LAYER M4 ;
        RECT  0 52.656 0.084 52.68 ;
    END
  END tap_d[100]
  PIN tap_d[101]
    DIRECTION OUTPUT ;
    USE SIGNAL ;
    PORT
      LAYER M4 ;
        RECT  0 52.752 0.084 52.776 ;
    END
  END tap_d[101]
  PIN tap_d[102]
    DIRECTION OUTPUT ;
    USE SIGNAL ;
    PORT
      LAYER M4 ;
        RECT  0 52.848 0.084 52.872 ;
    END
  END tap_d[102]
  PIN tap_d[103]
    DIRECTION OUTPUT ;
    USE SIGNAL ;
    PORT
      LAYER M4 ;
        RECT  0 52.944 0.084 52.968 ;
    END
  END tap_d[103]
  PIN tap_d[104]
    DIRECTION OUTPUT ;
    USE SIGNAL ;
    PORT
      LAYER M4 ;
        RECT  0 53.04 0.084 53.064 ;
    END
  END tap_d[104]
  PIN tap_d[105]
    DIRECTION OUTPUT ;
    USE SIGNAL ;
    PORT
      LAYER M4 ;
        RECT  0 53.136 0.084 53.16 ;
    END
  END tap_d[105]
  PIN tap_d[106]
    DIRECTION OUTPUT ;
    USE SIGNAL ;
    PORT
      LAYER M4 ;
        RECT  0 53.232 0.084 53.256 ;
    END
  END tap_d[106]
  PIN tap_d[107]
    DIRECTION OUTPUT ;
    USE SIGNAL ;
    PORT
      LAYER M4 ;
        RECT  0 53.328 0.084 53.352 ;
    END
  END tap_d[107]
  PIN tap_d[108]
    DIRECTION OUTPUT ;
    USE SIGNAL ;
    PORT
      LAYER M4 ;
        RECT  0 53.424 0.084 53.448 ;
    END
  END tap_d[108]
  PIN tap_d[109]
    DIRECTION OUTPUT ;
    USE SIGNAL ;
    PORT
      LAYER M4 ;
        RECT  0 53.52 0.084 53.544 ;
    END
  END tap_d[109]
  PIN tap_d[10]
    DIRECTION OUTPUT ;
    USE SIGNAL ;
    PORT
      LAYER M4 ;
        RECT  0 59.376 0.084 59.4 ;
    END
  END tap_d[10]
  PIN tap_d[110]
    DIRECTION OUTPUT ;
    USE SIGNAL ;
    PORT
      LAYER M4 ;
        RECT  0 53.616 0.084 53.64 ;
    END
  END tap_d[110]
  PIN tap_d[111]
    DIRECTION OUTPUT ;
    USE SIGNAL ;
    PORT
      LAYER M4 ;
        RECT  0 53.712 0.084 53.736 ;
    END
  END tap_d[111]
  PIN tap_d[112]
    DIRECTION OUTPUT ;
    USE SIGNAL ;
    PORT
      LAYER M4 ;
        RECT  0 53.808 0.084 53.832 ;
    END
  END tap_d[112]
  PIN tap_d[113]
    DIRECTION OUTPUT ;
    USE SIGNAL ;
    PORT
      LAYER M4 ;
        RECT  0 53.904 0.084 53.928 ;
    END
  END tap_d[113]
  PIN tap_d[114]
    DIRECTION OUTPUT ;
    USE SIGNAL ;
    PORT
      LAYER M4 ;
        RECT  0 54 0.084 54.024 ;
    END
  END tap_d[114]
  PIN tap_d[115]
    DIRECTION OUTPUT ;
    USE SIGNAL ;
    PORT
      LAYER M4 ;
        RECT  0 54.096 0.084 54.12 ;
    END
  END tap_d[115]
  PIN tap_d[116]
    DIRECTION OUTPUT ;
    USE SIGNAL ;
    PORT
      LAYER M4 ;
        RECT  0 54.192 0.084 54.216 ;
    END
  END tap_d[116]
  PIN tap_d[117]
    DIRECTION OUTPUT ;
    USE SIGNAL ;
    PORT
      LAYER M4 ;
        RECT  0 54.288 0.084 54.312 ;
    END
  END tap_d[117]
  PIN tap_d[118]
    DIRECTION OUTPUT ;
    USE SIGNAL ;
    PORT
      LAYER M4 ;
        RECT  0 54.384 0.084 54.408 ;
    END
  END tap_d[118]
  PIN tap_d[119]
    DIRECTION OUTPUT ;
    USE SIGNAL ;
    PORT
      LAYER M4 ;
        RECT  0 54.48 0.084 54.504 ;
    END
  END tap_d[119]
  PIN tap_d[11]
    DIRECTION OUTPUT ;
    USE SIGNAL ;
    PORT
      LAYER M4 ;
        RECT  0 59.472 0.084 59.496 ;
    END
  END tap_d[11]
  PIN tap_d[120]
    DIRECTION OUTPUT ;
    USE SIGNAL ;
    PORT
      LAYER M4 ;
        RECT  0 54.576 0.084 54.6 ;
    END
  END tap_d[120]
  PIN tap_d[121]
    DIRECTION OUTPUT ;
    USE SIGNAL ;
    PORT
      LAYER M4 ;
        RECT  0 54.672 0.084 54.696 ;
    END
  END tap_d[121]
  PIN tap_d[122]
    DIRECTION OUTPUT ;
    USE SIGNAL ;
    PORT
      LAYER M4 ;
        RECT  0 54.768 0.084 54.792 ;
    END
  END tap_d[122]
  PIN tap_d[123]
    DIRECTION OUTPUT ;
    USE SIGNAL ;
    PORT
      LAYER M4 ;
        RECT  0 54.864 0.084 54.888 ;
    END
  END tap_d[123]
  PIN tap_d[124]
    DIRECTION OUTPUT ;
    USE SIGNAL ;
    PORT
      LAYER M4 ;
        RECT  0 54.96 0.084 54.984 ;
    END
  END tap_d[124]
  PIN tap_d[125]
    DIRECTION OUTPUT ;
    USE SIGNAL ;
    PORT
      LAYER M4 ;
        RECT  0 55.056 0.084 55.08 ;
    END
  END tap_d[125]
  PIN tap_d[126]
    DIRECTION OUTPUT ;
    USE SIGNAL ;
    PORT
      LAYER M4 ;
        RECT  0 55.152 0.084 55.176 ;
    END
  END tap_d[126]
  PIN tap_d[127]
    DIRECTION OUTPUT ;
    USE SIGNAL ;
    PORT
      LAYER M4 ;
        RECT  0 55.248 0.084 55.272 ;
    END
  END tap_d[127]
  PIN tap_d[128]
    DIRECTION OUTPUT ;
    USE SIGNAL ;
    PORT
      LAYER M4 ;
        RECT  0 55.344 0.084 55.368 ;
    END
  END tap_d[128]
  PIN tap_d[129]
    DIRECTION OUTPUT ;
    USE SIGNAL ;
    PORT
      LAYER M4 ;
        RECT  0 55.44 0.084 55.464 ;
    END
  END tap_d[129]
  PIN tap_d[12]
    DIRECTION OUTPUT ;
    USE SIGNAL ;
    PORT
      LAYER M4 ;
        RECT  0 59.568 0.084 59.592 ;
    END
  END tap_d[12]
  PIN tap_d[130]
    DIRECTION OUTPUT ;
    USE SIGNAL ;
    PORT
      LAYER M4 ;
        RECT  0 55.536 0.084 55.56 ;
    END
  END tap_d[130]
  PIN tap_d[131]
    DIRECTION OUTPUT ;
    USE SIGNAL ;
    PORT
      LAYER M4 ;
        RECT  0 55.632 0.084 55.656 ;
    END
  END tap_d[131]
  PIN tap_d[132]
    DIRECTION OUTPUT ;
    USE SIGNAL ;
    PORT
      LAYER M4 ;
        RECT  0 55.728 0.084 55.752 ;
    END
  END tap_d[132]
  PIN tap_d[133]
    DIRECTION OUTPUT ;
    USE SIGNAL ;
    PORT
      LAYER M4 ;
        RECT  0 55.824 0.084 55.848 ;
    END
  END tap_d[133]
  PIN tap_d[134]
    DIRECTION OUTPUT ;
    USE SIGNAL ;
    PORT
      LAYER M4 ;
        RECT  0 55.92 0.084 55.944 ;
    END
  END tap_d[134]
  PIN tap_d[135]
    DIRECTION OUTPUT ;
    USE SIGNAL ;
    PORT
      LAYER M4 ;
        RECT  0 56.016 0.084 56.04 ;
    END
  END tap_d[135]
  PIN tap_d[136]
    DIRECTION OUTPUT ;
    USE SIGNAL ;
    PORT
      LAYER M4 ;
        RECT  0 56.112 0.084 56.136 ;
    END
  END tap_d[136]
  PIN tap_d[137]
    DIRECTION OUTPUT ;
    USE SIGNAL ;
    PORT
      LAYER M4 ;
        RECT  0 56.208 0.084 56.232 ;
    END
  END tap_d[137]
  PIN tap_d[138]
    DIRECTION OUTPUT ;
    USE SIGNAL ;
    PORT
      LAYER M4 ;
        RECT  0 56.304 0.084 56.328 ;
    END
  END tap_d[138]
  PIN tap_d[139]
    DIRECTION OUTPUT ;
    USE SIGNAL ;
    PORT
      LAYER M4 ;
        RECT  0 56.4 0.084 56.424 ;
    END
  END tap_d[139]
  PIN tap_d[13]
    DIRECTION OUTPUT ;
    USE SIGNAL ;
    PORT
      LAYER M4 ;
        RECT  0 59.664 0.084 59.688 ;
    END
  END tap_d[13]
  PIN tap_d[140]
    DIRECTION OUTPUT ;
    USE SIGNAL ;
    PORT
      LAYER M4 ;
        RECT  0 56.496 0.084 56.52 ;
    END
  END tap_d[140]
  PIN tap_d[141]
    DIRECTION OUTPUT ;
    USE SIGNAL ;
    PORT
      LAYER M4 ;
        RECT  0 56.592 0.084 56.616 ;
    END
  END tap_d[141]
  PIN tap_d[142]
    DIRECTION OUTPUT ;
    USE SIGNAL ;
    PORT
      LAYER M4 ;
        RECT  0 56.688 0.084 56.712 ;
    END
  END tap_d[142]
  PIN tap_d[143]
    DIRECTION OUTPUT ;
    USE SIGNAL ;
    PORT
      LAYER M4 ;
        RECT  0 56.784 0.084 56.808 ;
    END
  END tap_d[143]
  PIN tap_d[144]
    DIRECTION OUTPUT ;
    USE SIGNAL ;
    PORT
      LAYER M4 ;
        RECT  0 56.88 0.084 56.904 ;
    END
  END tap_d[144]
  PIN tap_d[145]
    DIRECTION OUTPUT ;
    USE SIGNAL ;
    PORT
      LAYER M4 ;
        RECT  0 56.976 0.084 57 ;
    END
  END tap_d[145]
  PIN tap_d[146]
    DIRECTION OUTPUT ;
    USE SIGNAL ;
    PORT
      LAYER M4 ;
        RECT  0 57.072 0.084 57.096 ;
    END
  END tap_d[146]
  PIN tap_d[147]
    DIRECTION OUTPUT ;
    USE SIGNAL ;
    PORT
      LAYER M4 ;
        RECT  0 57.168 0.084 57.192 ;
    END
  END tap_d[147]
  PIN tap_d[148]
    DIRECTION OUTPUT ;
    USE SIGNAL ;
    PORT
      LAYER M4 ;
        RECT  0 57.264 0.084 57.288 ;
    END
  END tap_d[148]
  PIN tap_d[149]
    DIRECTION OUTPUT ;
    USE SIGNAL ;
    PORT
      LAYER M4 ;
        RECT  0 57.36 0.084 57.384 ;
    END
  END tap_d[149]
  PIN tap_d[14]
    DIRECTION OUTPUT ;
    USE SIGNAL ;
    PORT
      LAYER M4 ;
        RECT  0 59.76 0.084 59.784 ;
    END
  END tap_d[14]
  PIN tap_d[150]
    DIRECTION OUTPUT ;
    USE SIGNAL ;
    PORT
      LAYER M4 ;
        RECT  0 57.456 0.084 57.48 ;
    END
  END tap_d[150]
  PIN tap_d[151]
    DIRECTION OUTPUT ;
    USE SIGNAL ;
    PORT
      LAYER M4 ;
        RECT  0 57.552 0.084 57.576 ;
    END
  END tap_d[151]
  PIN tap_d[152]
    DIRECTION OUTPUT ;
    USE SIGNAL ;
    PORT
      LAYER M4 ;
        RECT  0 57.648 0.084 57.672 ;
    END
  END tap_d[152]
  PIN tap_d[153]
    DIRECTION OUTPUT ;
    USE SIGNAL ;
    PORT
      LAYER M4 ;
        RECT  0 57.744 0.084 57.768 ;
    END
  END tap_d[153]
  PIN tap_d[154]
    DIRECTION OUTPUT ;
    USE SIGNAL ;
    PORT
      LAYER M4 ;
        RECT  0 57.84 0.084 57.864 ;
    END
  END tap_d[154]
  PIN tap_d[155]
    DIRECTION OUTPUT ;
    USE SIGNAL ;
    PORT
      LAYER M4 ;
        RECT  0 57.936 0.084 57.96 ;
    END
  END tap_d[155]
  PIN tap_d[156]
    DIRECTION OUTPUT ;
    USE SIGNAL ;
    PORT
      LAYER M4 ;
        RECT  0 58.032 0.084 58.056 ;
    END
  END tap_d[156]
  PIN tap_d[157]
    DIRECTION OUTPUT ;
    USE SIGNAL ;
    PORT
      LAYER M4 ;
        RECT  0 58.128 0.084 58.152 ;
    END
  END tap_d[157]
  PIN tap_d[158]
    DIRECTION OUTPUT ;
    USE SIGNAL ;
    PORT
      LAYER M4 ;
        RECT  0 58.224 0.084 58.248 ;
    END
  END tap_d[158]
  PIN tap_d[159]
    DIRECTION OUTPUT ;
    USE SIGNAL ;
    PORT
      LAYER M4 ;
        RECT  0 58.32 0.084 58.344 ;
    END
  END tap_d[159]
  PIN tap_d[15]
    DIRECTION OUTPUT ;
    USE SIGNAL ;
    PORT
      LAYER M4 ;
        RECT  0 59.856 0.084 59.88 ;
    END
  END tap_d[15]
  PIN tap_d[160]
    DIRECTION OUTPUT ;
    USE SIGNAL ;
    PORT
      LAYER M4 ;
        RECT  0 61.488 0.084 61.512 ;
    END
  END tap_d[160]
  PIN tap_d[161]
    DIRECTION OUTPUT ;
    USE SIGNAL ;
    PORT
      LAYER M4 ;
        RECT  0 61.584 0.084 61.608 ;
    END
  END tap_d[161]
  PIN tap_d[162]
    DIRECTION OUTPUT ;
    USE SIGNAL ;
    PORT
      LAYER M4 ;
        RECT  0 61.68 0.084 61.704 ;
    END
  END tap_d[162]
  PIN tap_d[163]
    DIRECTION OUTPUT ;
    USE SIGNAL ;
    PORT
      LAYER M4 ;
        RECT  0 61.776 0.084 61.8 ;
    END
  END tap_d[163]
  PIN tap_d[164]
    DIRECTION OUTPUT ;
    USE SIGNAL ;
    PORT
      LAYER M4 ;
        RECT  0 61.872 0.084 61.896 ;
    END
  END tap_d[164]
  PIN tap_d[165]
    DIRECTION OUTPUT ;
    USE SIGNAL ;
    PORT
      LAYER M4 ;
        RECT  0 61.968 0.084 61.992 ;
    END
  END tap_d[165]
  PIN tap_d[166]
    DIRECTION OUTPUT ;
    USE SIGNAL ;
    PORT
      LAYER M4 ;
        RECT  0 62.064 0.084 62.088 ;
    END
  END tap_d[166]
  PIN tap_d[167]
    DIRECTION OUTPUT ;
    USE SIGNAL ;
    PORT
      LAYER M4 ;
        RECT  0 62.16 0.084 62.184 ;
    END
  END tap_d[167]
  PIN tap_d[168]
    DIRECTION OUTPUT ;
    USE SIGNAL ;
    PORT
      LAYER M4 ;
        RECT  0 62.256 0.084 62.28 ;
    END
  END tap_d[168]
  PIN tap_d[169]
    DIRECTION OUTPUT ;
    USE SIGNAL ;
    PORT
      LAYER M4 ;
        RECT  0 62.352 0.084 62.376 ;
    END
  END tap_d[169]
  PIN tap_d[16]
    DIRECTION OUTPUT ;
    USE SIGNAL ;
    PORT
      LAYER M4 ;
        RECT  0 59.952 0.084 59.976 ;
    END
  END tap_d[16]
  PIN tap_d[170]
    DIRECTION OUTPUT ;
    USE SIGNAL ;
    PORT
      LAYER M4 ;
        RECT  0 62.448 0.084 62.472 ;
    END
  END tap_d[170]
  PIN tap_d[171]
    DIRECTION OUTPUT ;
    USE SIGNAL ;
    PORT
      LAYER M4 ;
        RECT  0 62.544 0.084 62.568 ;
    END
  END tap_d[171]
  PIN tap_d[172]
    DIRECTION OUTPUT ;
    USE SIGNAL ;
    PORT
      LAYER M4 ;
        RECT  0 62.64 0.084 62.664 ;
    END
  END tap_d[172]
  PIN tap_d[173]
    DIRECTION OUTPUT ;
    USE SIGNAL ;
    PORT
      LAYER M4 ;
        RECT  0 62.736 0.084 62.76 ;
    END
  END tap_d[173]
  PIN tap_d[174]
    DIRECTION OUTPUT ;
    USE SIGNAL ;
    PORT
      LAYER M4 ;
        RECT  0 62.832 0.084 62.856 ;
    END
  END tap_d[174]
  PIN tap_d[175]
    DIRECTION OUTPUT ;
    USE SIGNAL ;
    PORT
      LAYER M4 ;
        RECT  0 62.928 0.084 62.952 ;
    END
  END tap_d[175]
  PIN tap_d[176]
    DIRECTION OUTPUT ;
    USE SIGNAL ;
    PORT
      LAYER M4 ;
        RECT  0 63.024 0.084 63.048 ;
    END
  END tap_d[176]
  PIN tap_d[177]
    DIRECTION OUTPUT ;
    USE SIGNAL ;
    PORT
      LAYER M4 ;
        RECT  0 63.12 0.084 63.144 ;
    END
  END tap_d[177]
  PIN tap_d[178]
    DIRECTION OUTPUT ;
    USE SIGNAL ;
    PORT
      LAYER M4 ;
        RECT  0 63.216 0.084 63.24 ;
    END
  END tap_d[178]
  PIN tap_d[179]
    DIRECTION OUTPUT ;
    USE SIGNAL ;
    PORT
      LAYER M4 ;
        RECT  0 63.312 0.084 63.336 ;
    END
  END tap_d[179]
  PIN tap_d[17]
    DIRECTION OUTPUT ;
    USE SIGNAL ;
    PORT
      LAYER M4 ;
        RECT  0 60.048 0.084 60.072 ;
    END
  END tap_d[17]
  PIN tap_d[180]
    DIRECTION OUTPUT ;
    USE SIGNAL ;
    PORT
      LAYER M4 ;
        RECT  0 63.408 0.084 63.432 ;
    END
  END tap_d[180]
  PIN tap_d[181]
    DIRECTION OUTPUT ;
    USE SIGNAL ;
    PORT
      LAYER M4 ;
        RECT  0 63.504 0.084 63.528 ;
    END
  END tap_d[181]
  PIN tap_d[182]
    DIRECTION OUTPUT ;
    USE SIGNAL ;
    PORT
      LAYER M4 ;
        RECT  0 63.6 0.084 63.624 ;
    END
  END tap_d[182]
  PIN tap_d[183]
    DIRECTION OUTPUT ;
    USE SIGNAL ;
    PORT
      LAYER M4 ;
        RECT  0 63.696 0.084 63.72 ;
    END
  END tap_d[183]
  PIN tap_d[184]
    DIRECTION OUTPUT ;
    USE SIGNAL ;
    PORT
      LAYER M4 ;
        RECT  0 63.792 0.084 63.816 ;
    END
  END tap_d[184]
  PIN tap_d[185]
    DIRECTION OUTPUT ;
    USE SIGNAL ;
    PORT
      LAYER M4 ;
        RECT  0 63.888 0.084 63.912 ;
    END
  END tap_d[185]
  PIN tap_d[186]
    DIRECTION OUTPUT ;
    USE SIGNAL ;
    PORT
      LAYER M4 ;
        RECT  0 63.984 0.084 64.008 ;
    END
  END tap_d[186]
  PIN tap_d[187]
    DIRECTION OUTPUT ;
    USE SIGNAL ;
    PORT
      LAYER M4 ;
        RECT  0 64.08 0.084 64.104 ;
    END
  END tap_d[187]
  PIN tap_d[188]
    DIRECTION OUTPUT ;
    USE SIGNAL ;
    PORT
      LAYER M4 ;
        RECT  0 64.176 0.084 64.2 ;
    END
  END tap_d[188]
  PIN tap_d[189]
    DIRECTION OUTPUT ;
    USE SIGNAL ;
    PORT
      LAYER M4 ;
        RECT  0 64.272 0.084 64.296 ;
    END
  END tap_d[189]
  PIN tap_d[18]
    DIRECTION OUTPUT ;
    USE SIGNAL ;
    PORT
      LAYER M4 ;
        RECT  0 60.144 0.084 60.168 ;
    END
  END tap_d[18]
  PIN tap_d[190]
    DIRECTION OUTPUT ;
    USE SIGNAL ;
    PORT
      LAYER M4 ;
        RECT  0 64.368 0.084 64.392 ;
    END
  END tap_d[190]
  PIN tap_d[191]
    DIRECTION OUTPUT ;
    USE SIGNAL ;
    PORT
      LAYER M4 ;
        RECT  0 64.464 0.084 64.488 ;
    END
  END tap_d[191]
  PIN tap_d[192]
    DIRECTION OUTPUT ;
    USE SIGNAL ;
    PORT
      LAYER M4 ;
        RECT  0 39.216 0.084 39.24 ;
    END
  END tap_d[192]
  PIN tap_d[193]
    DIRECTION OUTPUT ;
    USE SIGNAL ;
    PORT
      LAYER M4 ;
        RECT  0 39.312 0.084 39.336 ;
    END
  END tap_d[193]
  PIN tap_d[194]
    DIRECTION OUTPUT ;
    USE SIGNAL ;
    PORT
      LAYER M4 ;
        RECT  0 39.408 0.084 39.432 ;
    END
  END tap_d[194]
  PIN tap_d[195]
    DIRECTION OUTPUT ;
    USE SIGNAL ;
    PORT
      LAYER M4 ;
        RECT  0 39.504 0.084 39.528 ;
    END
  END tap_d[195]
  PIN tap_d[196]
    DIRECTION OUTPUT ;
    USE SIGNAL ;
    PORT
      LAYER M4 ;
        RECT  0 39.6 0.084 39.624 ;
    END
  END tap_d[196]
  PIN tap_d[197]
    DIRECTION OUTPUT ;
    USE SIGNAL ;
    PORT
      LAYER M4 ;
        RECT  0 39.696 0.084 39.72 ;
    END
  END tap_d[197]
  PIN tap_d[198]
    DIRECTION OUTPUT ;
    USE SIGNAL ;
    PORT
      LAYER M4 ;
        RECT  0 39.792 0.084 39.816 ;
    END
  END tap_d[198]
  PIN tap_d[199]
    DIRECTION OUTPUT ;
    USE SIGNAL ;
    PORT
      LAYER M4 ;
        RECT  0 39.888 0.084 39.912 ;
    END
  END tap_d[199]
  PIN tap_d[19]
    DIRECTION OUTPUT ;
    USE SIGNAL ;
    PORT
      LAYER M4 ;
        RECT  0 60.24 0.084 60.264 ;
    END
  END tap_d[19]
  PIN tap_d[1]
    DIRECTION OUTPUT ;
    USE SIGNAL ;
    PORT
      LAYER M4 ;
        RECT  0 58.512 0.084 58.536 ;
    END
  END tap_d[1]
  PIN tap_d[200]
    DIRECTION OUTPUT ;
    USE SIGNAL ;
    PORT
      LAYER M4 ;
        RECT  0 39.984 0.084 40.008 ;
    END
  END tap_d[200]
  PIN tap_d[201]
    DIRECTION OUTPUT ;
    USE SIGNAL ;
    PORT
      LAYER M4 ;
        RECT  0 40.08 0.084 40.104 ;
    END
  END tap_d[201]
  PIN tap_d[202]
    DIRECTION OUTPUT ;
    USE SIGNAL ;
    PORT
      LAYER M4 ;
        RECT  0 40.176 0.084 40.2 ;
    END
  END tap_d[202]
  PIN tap_d[203]
    DIRECTION OUTPUT ;
    USE SIGNAL ;
    PORT
      LAYER M4 ;
        RECT  0 40.272 0.084 40.296 ;
    END
  END tap_d[203]
  PIN tap_d[204]
    DIRECTION OUTPUT ;
    USE SIGNAL ;
    PORT
      LAYER M4 ;
        RECT  0 40.368 0.084 40.392 ;
    END
  END tap_d[204]
  PIN tap_d[205]
    DIRECTION OUTPUT ;
    USE SIGNAL ;
    PORT
      LAYER M4 ;
        RECT  0 40.464 0.084 40.488 ;
    END
  END tap_d[205]
  PIN tap_d[206]
    DIRECTION OUTPUT ;
    USE SIGNAL ;
    PORT
      LAYER M4 ;
        RECT  0 40.56 0.084 40.584 ;
    END
  END tap_d[206]
  PIN tap_d[207]
    DIRECTION OUTPUT ;
    USE SIGNAL ;
    PORT
      LAYER M4 ;
        RECT  0 40.656 0.084 40.68 ;
    END
  END tap_d[207]
  PIN tap_d[208]
    DIRECTION OUTPUT ;
    USE SIGNAL ;
    PORT
      LAYER M4 ;
        RECT  0 40.752 0.084 40.776 ;
    END
  END tap_d[208]
  PIN tap_d[209]
    DIRECTION OUTPUT ;
    USE SIGNAL ;
    PORT
      LAYER M4 ;
        RECT  0 40.848 0.084 40.872 ;
    END
  END tap_d[209]
  PIN tap_d[20]
    DIRECTION OUTPUT ;
    USE SIGNAL ;
    PORT
      LAYER M4 ;
        RECT  0 60.336 0.084 60.36 ;
    END
  END tap_d[20]
  PIN tap_d[210]
    DIRECTION OUTPUT ;
    USE SIGNAL ;
    PORT
      LAYER M4 ;
        RECT  0 40.944 0.084 40.968 ;
    END
  END tap_d[210]
  PIN tap_d[211]
    DIRECTION OUTPUT ;
    USE SIGNAL ;
    PORT
      LAYER M4 ;
        RECT  0 41.04 0.084 41.064 ;
    END
  END tap_d[211]
  PIN tap_d[212]
    DIRECTION OUTPUT ;
    USE SIGNAL ;
    PORT
      LAYER M4 ;
        RECT  0 41.136 0.084 41.16 ;
    END
  END tap_d[212]
  PIN tap_d[213]
    DIRECTION OUTPUT ;
    USE SIGNAL ;
    PORT
      LAYER M4 ;
        RECT  0 41.232 0.084 41.256 ;
    END
  END tap_d[213]
  PIN tap_d[214]
    DIRECTION OUTPUT ;
    USE SIGNAL ;
    PORT
      LAYER M4 ;
        RECT  0 41.328 0.084 41.352 ;
    END
  END tap_d[214]
  PIN tap_d[215]
    DIRECTION OUTPUT ;
    USE SIGNAL ;
    PORT
      LAYER M4 ;
        RECT  0 41.424 0.084 41.448 ;
    END
  END tap_d[215]
  PIN tap_d[216]
    DIRECTION OUTPUT ;
    USE SIGNAL ;
    PORT
      LAYER M4 ;
        RECT  0 41.52 0.084 41.544 ;
    END
  END tap_d[216]
  PIN tap_d[217]
    DIRECTION OUTPUT ;
    USE SIGNAL ;
    PORT
      LAYER M4 ;
        RECT  0 41.616 0.084 41.64 ;
    END
  END tap_d[217]
  PIN tap_d[218]
    DIRECTION OUTPUT ;
    USE SIGNAL ;
    PORT
      LAYER M4 ;
        RECT  0 41.712 0.084 41.736 ;
    END
  END tap_d[218]
  PIN tap_d[219]
    DIRECTION OUTPUT ;
    USE SIGNAL ;
    PORT
      LAYER M4 ;
        RECT  0 41.808 0.084 41.832 ;
    END
  END tap_d[219]
  PIN tap_d[21]
    DIRECTION OUTPUT ;
    USE SIGNAL ;
    PORT
      LAYER M4 ;
        RECT  0 60.432 0.084 60.456 ;
    END
  END tap_d[21]
  PIN tap_d[220]
    DIRECTION OUTPUT ;
    USE SIGNAL ;
    PORT
      LAYER M4 ;
        RECT  0 41.904 0.084 41.928 ;
    END
  END tap_d[220]
  PIN tap_d[221]
    DIRECTION OUTPUT ;
    USE SIGNAL ;
    PORT
      LAYER M4 ;
        RECT  0 42 0.084 42.024 ;
    END
  END tap_d[221]
  PIN tap_d[222]
    DIRECTION OUTPUT ;
    USE SIGNAL ;
    PORT
      LAYER M4 ;
        RECT  0 42.096 0.084 42.12 ;
    END
  END tap_d[222]
  PIN tap_d[223]
    DIRECTION OUTPUT ;
    USE SIGNAL ;
    PORT
      LAYER M4 ;
        RECT  0 42.192 0.084 42.216 ;
    END
  END tap_d[223]
  PIN tap_d[224]
    DIRECTION OUTPUT ;
    USE SIGNAL ;
    PORT
      LAYER M4 ;
        RECT  0 26.928 0.084 26.952 ;
    END
  END tap_d[224]
  PIN tap_d[225]
    DIRECTION OUTPUT ;
    USE SIGNAL ;
    PORT
      LAYER M4 ;
        RECT  0 27.024 0.084 27.048 ;
    END
  END tap_d[225]
  PIN tap_d[226]
    DIRECTION OUTPUT ;
    USE SIGNAL ;
    PORT
      LAYER M4 ;
        RECT  0 27.12 0.084 27.144 ;
    END
  END tap_d[226]
  PIN tap_d[227]
    DIRECTION OUTPUT ;
    USE SIGNAL ;
    PORT
      LAYER M4 ;
        RECT  0 27.216 0.084 27.24 ;
    END
  END tap_d[227]
  PIN tap_d[228]
    DIRECTION OUTPUT ;
    USE SIGNAL ;
    PORT
      LAYER M4 ;
        RECT  0 27.312 0.084 27.336 ;
    END
  END tap_d[228]
  PIN tap_d[229]
    DIRECTION OUTPUT ;
    USE SIGNAL ;
    PORT
      LAYER M4 ;
        RECT  0 27.408 0.084 27.432 ;
    END
  END tap_d[229]
  PIN tap_d[22]
    DIRECTION OUTPUT ;
    USE SIGNAL ;
    PORT
      LAYER M4 ;
        RECT  0 60.528 0.084 60.552 ;
    END
  END tap_d[22]
  PIN tap_d[230]
    DIRECTION OUTPUT ;
    USE SIGNAL ;
    PORT
      LAYER M4 ;
        RECT  0 27.504 0.084 27.528 ;
    END
  END tap_d[230]
  PIN tap_d[231]
    DIRECTION OUTPUT ;
    USE SIGNAL ;
    PORT
      LAYER M4 ;
        RECT  0 27.6 0.084 27.624 ;
    END
  END tap_d[231]
  PIN tap_d[232]
    DIRECTION OUTPUT ;
    USE SIGNAL ;
    PORT
      LAYER M4 ;
        RECT  0 27.696 0.084 27.72 ;
    END
  END tap_d[232]
  PIN tap_d[233]
    DIRECTION OUTPUT ;
    USE SIGNAL ;
    PORT
      LAYER M4 ;
        RECT  0 27.792 0.084 27.816 ;
    END
  END tap_d[233]
  PIN tap_d[234]
    DIRECTION OUTPUT ;
    USE SIGNAL ;
    PORT
      LAYER M4 ;
        RECT  0 27.888 0.084 27.912 ;
    END
  END tap_d[234]
  PIN tap_d[235]
    DIRECTION OUTPUT ;
    USE SIGNAL ;
    PORT
      LAYER M4 ;
        RECT  0 27.984 0.084 28.008 ;
    END
  END tap_d[235]
  PIN tap_d[236]
    DIRECTION OUTPUT ;
    USE SIGNAL ;
    PORT
      LAYER M4 ;
        RECT  0 28.08 0.084 28.104 ;
    END
  END tap_d[236]
  PIN tap_d[237]
    DIRECTION OUTPUT ;
    USE SIGNAL ;
    PORT
      LAYER M4 ;
        RECT  0 28.176 0.084 28.2 ;
    END
  END tap_d[237]
  PIN tap_d[238]
    DIRECTION OUTPUT ;
    USE SIGNAL ;
    PORT
      LAYER M4 ;
        RECT  0 28.272 0.084 28.296 ;
    END
  END tap_d[238]
  PIN tap_d[239]
    DIRECTION OUTPUT ;
    USE SIGNAL ;
    PORT
      LAYER M4 ;
        RECT  0 28.368 0.084 28.392 ;
    END
  END tap_d[239]
  PIN tap_d[23]
    DIRECTION OUTPUT ;
    USE SIGNAL ;
    PORT
      LAYER M4 ;
        RECT  0 60.624 0.084 60.648 ;
    END
  END tap_d[23]
  PIN tap_d[240]
    DIRECTION OUTPUT ;
    USE SIGNAL ;
    PORT
      LAYER M4 ;
        RECT  0 28.464 0.084 28.488 ;
    END
  END tap_d[240]
  PIN tap_d[241]
    DIRECTION OUTPUT ;
    USE SIGNAL ;
    PORT
      LAYER M4 ;
        RECT  0 28.56 0.084 28.584 ;
    END
  END tap_d[241]
  PIN tap_d[242]
    DIRECTION OUTPUT ;
    USE SIGNAL ;
    PORT
      LAYER M4 ;
        RECT  0 28.656 0.084 28.68 ;
    END
  END tap_d[242]
  PIN tap_d[243]
    DIRECTION OUTPUT ;
    USE SIGNAL ;
    PORT
      LAYER M4 ;
        RECT  0 28.752 0.084 28.776 ;
    END
  END tap_d[243]
  PIN tap_d[244]
    DIRECTION OUTPUT ;
    USE SIGNAL ;
    PORT
      LAYER M4 ;
        RECT  0 28.848 0.084 28.872 ;
    END
  END tap_d[244]
  PIN tap_d[245]
    DIRECTION OUTPUT ;
    USE SIGNAL ;
    PORT
      LAYER M4 ;
        RECT  0 28.944 0.084 28.968 ;
    END
  END tap_d[245]
  PIN tap_d[246]
    DIRECTION OUTPUT ;
    USE SIGNAL ;
    PORT
      LAYER M4 ;
        RECT  0 29.04 0.084 29.064 ;
    END
  END tap_d[246]
  PIN tap_d[247]
    DIRECTION OUTPUT ;
    USE SIGNAL ;
    PORT
      LAYER M4 ;
        RECT  0 29.136 0.084 29.16 ;
    END
  END tap_d[247]
  PIN tap_d[248]
    DIRECTION OUTPUT ;
    USE SIGNAL ;
    PORT
      LAYER M4 ;
        RECT  0 29.232 0.084 29.256 ;
    END
  END tap_d[248]
  PIN tap_d[249]
    DIRECTION OUTPUT ;
    USE SIGNAL ;
    PORT
      LAYER M4 ;
        RECT  0 29.328 0.084 29.352 ;
    END
  END tap_d[249]
  PIN tap_d[24]
    DIRECTION OUTPUT ;
    USE SIGNAL ;
    PORT
      LAYER M4 ;
        RECT  0 60.72 0.084 60.744 ;
    END
  END tap_d[24]
  PIN tap_d[250]
    DIRECTION OUTPUT ;
    USE SIGNAL ;
    PORT
      LAYER M4 ;
        RECT  0 29.424 0.084 29.448 ;
    END
  END tap_d[250]
  PIN tap_d[251]
    DIRECTION OUTPUT ;
    USE SIGNAL ;
    PORT
      LAYER M4 ;
        RECT  0 29.52 0.084 29.544 ;
    END
  END tap_d[251]
  PIN tap_d[252]
    DIRECTION OUTPUT ;
    USE SIGNAL ;
    PORT
      LAYER M4 ;
        RECT  0 29.616 0.084 29.64 ;
    END
  END tap_d[252]
  PIN tap_d[253]
    DIRECTION OUTPUT ;
    USE SIGNAL ;
    PORT
      LAYER M4 ;
        RECT  0 29.712 0.084 29.736 ;
    END
  END tap_d[253]
  PIN tap_d[254]
    DIRECTION OUTPUT ;
    USE SIGNAL ;
    PORT
      LAYER M4 ;
        RECT  0 29.808 0.084 29.832 ;
    END
  END tap_d[254]
  PIN tap_d[255]
    DIRECTION OUTPUT ;
    USE SIGNAL ;
    PORT
      LAYER M4 ;
        RECT  0 29.904 0.084 29.928 ;
    END
  END tap_d[255]
  PIN tap_d[256]
    DIRECTION OUTPUT ;
    USE SIGNAL ;
    PORT
      LAYER M4 ;
        RECT  0 36.144 0.084 36.168 ;
    END
  END tap_d[256]
  PIN tap_d[257]
    DIRECTION OUTPUT ;
    USE SIGNAL ;
    PORT
      LAYER M4 ;
        RECT  0 36.24 0.084 36.264 ;
    END
  END tap_d[257]
  PIN tap_d[258]
    DIRECTION OUTPUT ;
    USE SIGNAL ;
    PORT
      LAYER M4 ;
        RECT  0 36.336 0.084 36.36 ;
    END
  END tap_d[258]
  PIN tap_d[259]
    DIRECTION OUTPUT ;
    USE SIGNAL ;
    PORT
      LAYER M4 ;
        RECT  0 36.432 0.084 36.456 ;
    END
  END tap_d[259]
  PIN tap_d[25]
    DIRECTION OUTPUT ;
    USE SIGNAL ;
    PORT
      LAYER M4 ;
        RECT  0 60.816 0.084 60.84 ;
    END
  END tap_d[25]
  PIN tap_d[260]
    DIRECTION OUTPUT ;
    USE SIGNAL ;
    PORT
      LAYER M4 ;
        RECT  0 36.528 0.084 36.552 ;
    END
  END tap_d[260]
  PIN tap_d[261]
    DIRECTION OUTPUT ;
    USE SIGNAL ;
    PORT
      LAYER M4 ;
        RECT  0 36.624 0.084 36.648 ;
    END
  END tap_d[261]
  PIN tap_d[262]
    DIRECTION OUTPUT ;
    USE SIGNAL ;
    PORT
      LAYER M4 ;
        RECT  0 36.72 0.084 36.744 ;
    END
  END tap_d[262]
  PIN tap_d[263]
    DIRECTION OUTPUT ;
    USE SIGNAL ;
    PORT
      LAYER M4 ;
        RECT  0 36.816 0.084 36.84 ;
    END
  END tap_d[263]
  PIN tap_d[264]
    DIRECTION OUTPUT ;
    USE SIGNAL ;
    PORT
      LAYER M4 ;
        RECT  0 36.912 0.084 36.936 ;
    END
  END tap_d[264]
  PIN tap_d[265]
    DIRECTION OUTPUT ;
    USE SIGNAL ;
    PORT
      LAYER M4 ;
        RECT  0 37.008 0.084 37.032 ;
    END
  END tap_d[265]
  PIN tap_d[266]
    DIRECTION OUTPUT ;
    USE SIGNAL ;
    PORT
      LAYER M4 ;
        RECT  0 37.104 0.084 37.128 ;
    END
  END tap_d[266]
  PIN tap_d[267]
    DIRECTION OUTPUT ;
    USE SIGNAL ;
    PORT
      LAYER M4 ;
        RECT  0 37.2 0.084 37.224 ;
    END
  END tap_d[267]
  PIN tap_d[268]
    DIRECTION OUTPUT ;
    USE SIGNAL ;
    PORT
      LAYER M4 ;
        RECT  0 37.296 0.084 37.32 ;
    END
  END tap_d[268]
  PIN tap_d[269]
    DIRECTION OUTPUT ;
    USE SIGNAL ;
    PORT
      LAYER M4 ;
        RECT  0 37.392 0.084 37.416 ;
    END
  END tap_d[269]
  PIN tap_d[26]
    DIRECTION OUTPUT ;
    USE SIGNAL ;
    PORT
      LAYER M4 ;
        RECT  0 60.912 0.084 60.936 ;
    END
  END tap_d[26]
  PIN tap_d[270]
    DIRECTION OUTPUT ;
    USE SIGNAL ;
    PORT
      LAYER M4 ;
        RECT  0 37.488 0.084 37.512 ;
    END
  END tap_d[270]
  PIN tap_d[271]
    DIRECTION OUTPUT ;
    USE SIGNAL ;
    PORT
      LAYER M4 ;
        RECT  0 37.584 0.084 37.608 ;
    END
  END tap_d[271]
  PIN tap_d[272]
    DIRECTION OUTPUT ;
    USE SIGNAL ;
    PORT
      LAYER M4 ;
        RECT  0 37.68 0.084 37.704 ;
    END
  END tap_d[272]
  PIN tap_d[273]
    DIRECTION OUTPUT ;
    USE SIGNAL ;
    PORT
      LAYER M4 ;
        RECT  0 37.776 0.084 37.8 ;
    END
  END tap_d[273]
  PIN tap_d[274]
    DIRECTION OUTPUT ;
    USE SIGNAL ;
    PORT
      LAYER M4 ;
        RECT  0 37.872 0.084 37.896 ;
    END
  END tap_d[274]
  PIN tap_d[275]
    DIRECTION OUTPUT ;
    USE SIGNAL ;
    PORT
      LAYER M4 ;
        RECT  0 37.968 0.084 37.992 ;
    END
  END tap_d[275]
  PIN tap_d[276]
    DIRECTION OUTPUT ;
    USE SIGNAL ;
    PORT
      LAYER M4 ;
        RECT  0 38.064 0.084 38.088 ;
    END
  END tap_d[276]
  PIN tap_d[277]
    DIRECTION OUTPUT ;
    USE SIGNAL ;
    PORT
      LAYER M4 ;
        RECT  0 38.16 0.084 38.184 ;
    END
  END tap_d[277]
  PIN tap_d[278]
    DIRECTION OUTPUT ;
    USE SIGNAL ;
    PORT
      LAYER M4 ;
        RECT  0 38.256 0.084 38.28 ;
    END
  END tap_d[278]
  PIN tap_d[279]
    DIRECTION OUTPUT ;
    USE SIGNAL ;
    PORT
      LAYER M4 ;
        RECT  0 38.352 0.084 38.376 ;
    END
  END tap_d[279]
  PIN tap_d[27]
    DIRECTION OUTPUT ;
    USE SIGNAL ;
    PORT
      LAYER M4 ;
        RECT  0 61.008 0.084 61.032 ;
    END
  END tap_d[27]
  PIN tap_d[280]
    DIRECTION OUTPUT ;
    USE SIGNAL ;
    PORT
      LAYER M4 ;
        RECT  0 38.448 0.084 38.472 ;
    END
  END tap_d[280]
  PIN tap_d[281]
    DIRECTION OUTPUT ;
    USE SIGNAL ;
    PORT
      LAYER M4 ;
        RECT  0 38.544 0.084 38.568 ;
    END
  END tap_d[281]
  PIN tap_d[282]
    DIRECTION OUTPUT ;
    USE SIGNAL ;
    PORT
      LAYER M4 ;
        RECT  0 38.64 0.084 38.664 ;
    END
  END tap_d[282]
  PIN tap_d[283]
    DIRECTION OUTPUT ;
    USE SIGNAL ;
    PORT
      LAYER M4 ;
        RECT  0 38.736 0.084 38.76 ;
    END
  END tap_d[283]
  PIN tap_d[284]
    DIRECTION OUTPUT ;
    USE SIGNAL ;
    PORT
      LAYER M4 ;
        RECT  0 38.832 0.084 38.856 ;
    END
  END tap_d[284]
  PIN tap_d[285]
    DIRECTION OUTPUT ;
    USE SIGNAL ;
    PORT
      LAYER M4 ;
        RECT  0 38.928 0.084 38.952 ;
    END
  END tap_d[285]
  PIN tap_d[286]
    DIRECTION OUTPUT ;
    USE SIGNAL ;
    PORT
      LAYER M4 ;
        RECT  0 39.024 0.084 39.048 ;
    END
  END tap_d[286]
  PIN tap_d[287]
    DIRECTION OUTPUT ;
    USE SIGNAL ;
    PORT
      LAYER M4 ;
        RECT  0 39.12 0.084 39.144 ;
    END
  END tap_d[287]
  PIN tap_d[288]
    DIRECTION OUTPUT ;
    USE SIGNAL ;
    PORT
      LAYER M4 ;
        RECT  0 33.072 0.084 33.096 ;
    END
  END tap_d[288]
  PIN tap_d[289]
    DIRECTION OUTPUT ;
    USE SIGNAL ;
    PORT
      LAYER M4 ;
        RECT  0 33.168 0.084 33.192 ;
    END
  END tap_d[289]
  PIN tap_d[28]
    DIRECTION OUTPUT ;
    USE SIGNAL ;
    PORT
      LAYER M4 ;
        RECT  0 61.104 0.084 61.128 ;
    END
  END tap_d[28]
  PIN tap_d[290]
    DIRECTION OUTPUT ;
    USE SIGNAL ;
    PORT
      LAYER M4 ;
        RECT  0 33.264 0.084 33.288 ;
    END
  END tap_d[290]
  PIN tap_d[291]
    DIRECTION OUTPUT ;
    USE SIGNAL ;
    PORT
      LAYER M4 ;
        RECT  0 33.36 0.084 33.384 ;
    END
  END tap_d[291]
  PIN tap_d[292]
    DIRECTION OUTPUT ;
    USE SIGNAL ;
    PORT
      LAYER M4 ;
        RECT  0 33.456 0.084 33.48 ;
    END
  END tap_d[292]
  PIN tap_d[293]
    DIRECTION OUTPUT ;
    USE SIGNAL ;
    PORT
      LAYER M4 ;
        RECT  0 33.552 0.084 33.576 ;
    END
  END tap_d[293]
  PIN tap_d[294]
    DIRECTION OUTPUT ;
    USE SIGNAL ;
    PORT
      LAYER M4 ;
        RECT  0 33.648 0.084 33.672 ;
    END
  END tap_d[294]
  PIN tap_d[295]
    DIRECTION OUTPUT ;
    USE SIGNAL ;
    PORT
      LAYER M4 ;
        RECT  0 33.744 0.084 33.768 ;
    END
  END tap_d[295]
  PIN tap_d[296]
    DIRECTION OUTPUT ;
    USE SIGNAL ;
    PORT
      LAYER M4 ;
        RECT  0 33.84 0.084 33.864 ;
    END
  END tap_d[296]
  PIN tap_d[297]
    DIRECTION OUTPUT ;
    USE SIGNAL ;
    PORT
      LAYER M4 ;
        RECT  0 33.936 0.084 33.96 ;
    END
  END tap_d[297]
  PIN tap_d[298]
    DIRECTION OUTPUT ;
    USE SIGNAL ;
    PORT
      LAYER M4 ;
        RECT  0 34.032 0.084 34.056 ;
    END
  END tap_d[298]
  PIN tap_d[299]
    DIRECTION OUTPUT ;
    USE SIGNAL ;
    PORT
      LAYER M4 ;
        RECT  0 34.128 0.084 34.152 ;
    END
  END tap_d[299]
  PIN tap_d[29]
    DIRECTION OUTPUT ;
    USE SIGNAL ;
    PORT
      LAYER M4 ;
        RECT  0 61.2 0.084 61.224 ;
    END
  END tap_d[29]
  PIN tap_d[2]
    DIRECTION OUTPUT ;
    USE SIGNAL ;
    PORT
      LAYER M4 ;
        RECT  0 58.608 0.084 58.632 ;
    END
  END tap_d[2]
  PIN tap_d[300]
    DIRECTION OUTPUT ;
    USE SIGNAL ;
    PORT
      LAYER M4 ;
        RECT  0 34.224 0.084 34.248 ;
    END
  END tap_d[300]
  PIN tap_d[301]
    DIRECTION OUTPUT ;
    USE SIGNAL ;
    PORT
      LAYER M4 ;
        RECT  0 34.32 0.084 34.344 ;
    END
  END tap_d[301]
  PIN tap_d[302]
    DIRECTION OUTPUT ;
    USE SIGNAL ;
    PORT
      LAYER M4 ;
        RECT  0 34.416 0.084 34.44 ;
    END
  END tap_d[302]
  PIN tap_d[303]
    DIRECTION OUTPUT ;
    USE SIGNAL ;
    PORT
      LAYER M4 ;
        RECT  0 34.512 0.084 34.536 ;
    END
  END tap_d[303]
  PIN tap_d[304]
    DIRECTION OUTPUT ;
    USE SIGNAL ;
    PORT
      LAYER M4 ;
        RECT  0 34.608 0.084 34.632 ;
    END
  END tap_d[304]
  PIN tap_d[305]
    DIRECTION OUTPUT ;
    USE SIGNAL ;
    PORT
      LAYER M4 ;
        RECT  0 34.704 0.084 34.728 ;
    END
  END tap_d[305]
  PIN tap_d[306]
    DIRECTION OUTPUT ;
    USE SIGNAL ;
    PORT
      LAYER M4 ;
        RECT  0 34.8 0.084 34.824 ;
    END
  END tap_d[306]
  PIN tap_d[307]
    DIRECTION OUTPUT ;
    USE SIGNAL ;
    PORT
      LAYER M4 ;
        RECT  0 34.896 0.084 34.92 ;
    END
  END tap_d[307]
  PIN tap_d[308]
    DIRECTION OUTPUT ;
    USE SIGNAL ;
    PORT
      LAYER M4 ;
        RECT  0 34.992 0.084 35.016 ;
    END
  END tap_d[308]
  PIN tap_d[309]
    DIRECTION OUTPUT ;
    USE SIGNAL ;
    PORT
      LAYER M4 ;
        RECT  0 35.088 0.084 35.112 ;
    END
  END tap_d[309]
  PIN tap_d[30]
    DIRECTION OUTPUT ;
    USE SIGNAL ;
    PORT
      LAYER M4 ;
        RECT  0 61.296 0.084 61.32 ;
    END
  END tap_d[30]
  PIN tap_d[310]
    DIRECTION OUTPUT ;
    USE SIGNAL ;
    PORT
      LAYER M4 ;
        RECT  0 35.184 0.084 35.208 ;
    END
  END tap_d[310]
  PIN tap_d[311]
    DIRECTION OUTPUT ;
    USE SIGNAL ;
    PORT
      LAYER M4 ;
        RECT  0 35.28 0.084 35.304 ;
    END
  END tap_d[311]
  PIN tap_d[312]
    DIRECTION OUTPUT ;
    USE SIGNAL ;
    PORT
      LAYER M4 ;
        RECT  0 35.376 0.084 35.4 ;
    END
  END tap_d[312]
  PIN tap_d[313]
    DIRECTION OUTPUT ;
    USE SIGNAL ;
    PORT
      LAYER M4 ;
        RECT  0 35.472 0.084 35.496 ;
    END
  END tap_d[313]
  PIN tap_d[314]
    DIRECTION OUTPUT ;
    USE SIGNAL ;
    PORT
      LAYER M4 ;
        RECT  0 35.568 0.084 35.592 ;
    END
  END tap_d[314]
  PIN tap_d[315]
    DIRECTION OUTPUT ;
    USE SIGNAL ;
    PORT
      LAYER M4 ;
        RECT  0 35.664 0.084 35.688 ;
    END
  END tap_d[315]
  PIN tap_d[316]
    DIRECTION OUTPUT ;
    USE SIGNAL ;
    PORT
      LAYER M4 ;
        RECT  0 35.76 0.084 35.784 ;
    END
  END tap_d[316]
  PIN tap_d[317]
    DIRECTION OUTPUT ;
    USE SIGNAL ;
    PORT
      LAYER M4 ;
        RECT  0 35.856 0.084 35.88 ;
    END
  END tap_d[317]
  PIN tap_d[318]
    DIRECTION OUTPUT ;
    USE SIGNAL ;
    PORT
      LAYER M4 ;
        RECT  0 35.952 0.084 35.976 ;
    END
  END tap_d[318]
  PIN tap_d[319]
    DIRECTION OUTPUT ;
    USE SIGNAL ;
    PORT
      LAYER M4 ;
        RECT  0 36.048 0.084 36.072 ;
    END
  END tap_d[319]
  PIN tap_d[31]
    DIRECTION OUTPUT ;
    USE SIGNAL ;
    PORT
      LAYER M4 ;
        RECT  0 61.392 0.084 61.416 ;
    END
  END tap_d[31]
  PIN tap_d[320]
    DIRECTION OUTPUT ;
    USE SIGNAL ;
    PORT
      LAYER M4 ;
        RECT  0 30 0.084 30.024 ;
    END
  END tap_d[320]
  PIN tap_d[321]
    DIRECTION OUTPUT ;
    USE SIGNAL ;
    PORT
      LAYER M4 ;
        RECT  0 30.096 0.084 30.12 ;
    END
  END tap_d[321]
  PIN tap_d[322]
    DIRECTION OUTPUT ;
    USE SIGNAL ;
    PORT
      LAYER M4 ;
        RECT  0 30.192 0.084 30.216 ;
    END
  END tap_d[322]
  PIN tap_d[323]
    DIRECTION OUTPUT ;
    USE SIGNAL ;
    PORT
      LAYER M4 ;
        RECT  0 30.288 0.084 30.312 ;
    END
  END tap_d[323]
  PIN tap_d[324]
    DIRECTION OUTPUT ;
    USE SIGNAL ;
    PORT
      LAYER M4 ;
        RECT  0 30.384 0.084 30.408 ;
    END
  END tap_d[324]
  PIN tap_d[325]
    DIRECTION OUTPUT ;
    USE SIGNAL ;
    PORT
      LAYER M4 ;
        RECT  0 30.48 0.084 30.504 ;
    END
  END tap_d[325]
  PIN tap_d[326]
    DIRECTION OUTPUT ;
    USE SIGNAL ;
    PORT
      LAYER M4 ;
        RECT  0 30.576 0.084 30.6 ;
    END
  END tap_d[326]
  PIN tap_d[327]
    DIRECTION OUTPUT ;
    USE SIGNAL ;
    PORT
      LAYER M4 ;
        RECT  0 30.672 0.084 30.696 ;
    END
  END tap_d[327]
  PIN tap_d[328]
    DIRECTION OUTPUT ;
    USE SIGNAL ;
    PORT
      LAYER M4 ;
        RECT  0 30.768 0.084 30.792 ;
    END
  END tap_d[328]
  PIN tap_d[329]
    DIRECTION OUTPUT ;
    USE SIGNAL ;
    PORT
      LAYER M4 ;
        RECT  0 30.864 0.084 30.888 ;
    END
  END tap_d[329]
  PIN tap_d[32]
    DIRECTION OUTPUT ;
    USE SIGNAL ;
    PORT
      LAYER M4 ;
        RECT  0 49.2 0.084 49.224 ;
    END
  END tap_d[32]
  PIN tap_d[330]
    DIRECTION OUTPUT ;
    USE SIGNAL ;
    PORT
      LAYER M4 ;
        RECT  0 30.96 0.084 30.984 ;
    END
  END tap_d[330]
  PIN tap_d[331]
    DIRECTION OUTPUT ;
    USE SIGNAL ;
    PORT
      LAYER M4 ;
        RECT  0 31.056 0.084 31.08 ;
    END
  END tap_d[331]
  PIN tap_d[332]
    DIRECTION OUTPUT ;
    USE SIGNAL ;
    PORT
      LAYER M4 ;
        RECT  0 31.152 0.084 31.176 ;
    END
  END tap_d[332]
  PIN tap_d[333]
    DIRECTION OUTPUT ;
    USE SIGNAL ;
    PORT
      LAYER M4 ;
        RECT  0 31.248 0.084 31.272 ;
    END
  END tap_d[333]
  PIN tap_d[334]
    DIRECTION OUTPUT ;
    USE SIGNAL ;
    PORT
      LAYER M4 ;
        RECT  0 31.344 0.084 31.368 ;
    END
  END tap_d[334]
  PIN tap_d[335]
    DIRECTION OUTPUT ;
    USE SIGNAL ;
    PORT
      LAYER M4 ;
        RECT  0 31.44 0.084 31.464 ;
    END
  END tap_d[335]
  PIN tap_d[336]
    DIRECTION OUTPUT ;
    USE SIGNAL ;
    PORT
      LAYER M4 ;
        RECT  0 31.536 0.084 31.56 ;
    END
  END tap_d[336]
  PIN tap_d[337]
    DIRECTION OUTPUT ;
    USE SIGNAL ;
    PORT
      LAYER M4 ;
        RECT  0 31.632 0.084 31.656 ;
    END
  END tap_d[337]
  PIN tap_d[338]
    DIRECTION OUTPUT ;
    USE SIGNAL ;
    PORT
      LAYER M4 ;
        RECT  0 31.728 0.084 31.752 ;
    END
  END tap_d[338]
  PIN tap_d[339]
    DIRECTION OUTPUT ;
    USE SIGNAL ;
    PORT
      LAYER M4 ;
        RECT  0 31.824 0.084 31.848 ;
    END
  END tap_d[339]
  PIN tap_d[33]
    DIRECTION OUTPUT ;
    USE SIGNAL ;
    PORT
      LAYER M4 ;
        RECT  0 49.296 0.084 49.32 ;
    END
  END tap_d[33]
  PIN tap_d[340]
    DIRECTION OUTPUT ;
    USE SIGNAL ;
    PORT
      LAYER M4 ;
        RECT  0 31.92 0.084 31.944 ;
    END
  END tap_d[340]
  PIN tap_d[341]
    DIRECTION OUTPUT ;
    USE SIGNAL ;
    PORT
      LAYER M4 ;
        RECT  0 32.016 0.084 32.04 ;
    END
  END tap_d[341]
  PIN tap_d[342]
    DIRECTION OUTPUT ;
    USE SIGNAL ;
    PORT
      LAYER M4 ;
        RECT  0 32.112 0.084 32.136 ;
    END
  END tap_d[342]
  PIN tap_d[343]
    DIRECTION OUTPUT ;
    USE SIGNAL ;
    PORT
      LAYER M4 ;
        RECT  0 32.208 0.084 32.232 ;
    END
  END tap_d[343]
  PIN tap_d[344]
    DIRECTION OUTPUT ;
    USE SIGNAL ;
    PORT
      LAYER M4 ;
        RECT  0 32.304 0.084 32.328 ;
    END
  END tap_d[344]
  PIN tap_d[345]
    DIRECTION OUTPUT ;
    USE SIGNAL ;
    PORT
      LAYER M4 ;
        RECT  0 32.4 0.084 32.424 ;
    END
  END tap_d[345]
  PIN tap_d[346]
    DIRECTION OUTPUT ;
    USE SIGNAL ;
    PORT
      LAYER M4 ;
        RECT  0 32.496 0.084 32.52 ;
    END
  END tap_d[346]
  PIN tap_d[347]
    DIRECTION OUTPUT ;
    USE SIGNAL ;
    PORT
      LAYER M4 ;
        RECT  0 32.592 0.084 32.616 ;
    END
  END tap_d[347]
  PIN tap_d[348]
    DIRECTION OUTPUT ;
    USE SIGNAL ;
    PORT
      LAYER M4 ;
        RECT  0 32.688 0.084 32.712 ;
    END
  END tap_d[348]
  PIN tap_d[349]
    DIRECTION OUTPUT ;
    USE SIGNAL ;
    PORT
      LAYER M4 ;
        RECT  0 32.784 0.084 32.808 ;
    END
  END tap_d[349]
  PIN tap_d[34]
    DIRECTION OUTPUT ;
    USE SIGNAL ;
    PORT
      LAYER M4 ;
        RECT  0 49.392 0.084 49.416 ;
    END
  END tap_d[34]
  PIN tap_d[350]
    DIRECTION OUTPUT ;
    USE SIGNAL ;
    PORT
      LAYER M4 ;
        RECT  0 32.88 0.084 32.904 ;
    END
  END tap_d[350]
  PIN tap_d[351]
    DIRECTION OUTPUT ;
    USE SIGNAL ;
    PORT
      LAYER M4 ;
        RECT  0 32.976 0.084 33 ;
    END
  END tap_d[351]
  PIN tap_d[352]
    DIRECTION OUTPUT ;
    USE SIGNAL ;
    PORT
      LAYER M4 ;
        RECT  0 42.288 0.084 42.312 ;
    END
  END tap_d[352]
  PIN tap_d[353]
    DIRECTION OUTPUT ;
    USE SIGNAL ;
    PORT
      LAYER M4 ;
        RECT  0 42.384 0.084 42.408 ;
    END
  END tap_d[353]
  PIN tap_d[354]
    DIRECTION OUTPUT ;
    USE SIGNAL ;
    PORT
      LAYER M4 ;
        RECT  0 42.48 0.084 42.504 ;
    END
  END tap_d[354]
  PIN tap_d[355]
    DIRECTION OUTPUT ;
    USE SIGNAL ;
    PORT
      LAYER M4 ;
        RECT  0 42.576 0.084 42.6 ;
    END
  END tap_d[355]
  PIN tap_d[356]
    DIRECTION OUTPUT ;
    USE SIGNAL ;
    PORT
      LAYER M4 ;
        RECT  0 42.672 0.084 42.696 ;
    END
  END tap_d[356]
  PIN tap_d[357]
    DIRECTION OUTPUT ;
    USE SIGNAL ;
    PORT
      LAYER M4 ;
        RECT  0 42.768 0.084 42.792 ;
    END
  END tap_d[357]
  PIN tap_d[358]
    DIRECTION OUTPUT ;
    USE SIGNAL ;
    PORT
      LAYER M4 ;
        RECT  0 42.864 0.084 42.888 ;
    END
  END tap_d[358]
  PIN tap_d[359]
    DIRECTION OUTPUT ;
    USE SIGNAL ;
    PORT
      LAYER M4 ;
        RECT  0 42.96 0.084 42.984 ;
    END
  END tap_d[359]
  PIN tap_d[35]
    DIRECTION OUTPUT ;
    USE SIGNAL ;
    PORT
      LAYER M4 ;
        RECT  0 49.488 0.084 49.512 ;
    END
  END tap_d[35]
  PIN tap_d[360]
    DIRECTION OUTPUT ;
    USE SIGNAL ;
    PORT
      LAYER M4 ;
        RECT  0 43.056 0.084 43.08 ;
    END
  END tap_d[360]
  PIN tap_d[361]
    DIRECTION OUTPUT ;
    USE SIGNAL ;
    PORT
      LAYER M4 ;
        RECT  0 43.152 0.084 43.176 ;
    END
  END tap_d[361]
  PIN tap_d[362]
    DIRECTION OUTPUT ;
    USE SIGNAL ;
    PORT
      LAYER M4 ;
        RECT  0 43.248 0.084 43.272 ;
    END
  END tap_d[362]
  PIN tap_d[363]
    DIRECTION OUTPUT ;
    USE SIGNAL ;
    PORT
      LAYER M4 ;
        RECT  0 43.344 0.084 43.368 ;
    END
  END tap_d[363]
  PIN tap_d[364]
    DIRECTION OUTPUT ;
    USE SIGNAL ;
    PORT
      LAYER M4 ;
        RECT  0 43.44 0.084 43.464 ;
    END
  END tap_d[364]
  PIN tap_d[365]
    DIRECTION OUTPUT ;
    USE SIGNAL ;
    PORT
      LAYER M4 ;
        RECT  0 43.536 0.084 43.56 ;
    END
  END tap_d[365]
  PIN tap_d[366]
    DIRECTION OUTPUT ;
    USE SIGNAL ;
    PORT
      LAYER M4 ;
        RECT  0 43.632 0.084 43.656 ;
    END
  END tap_d[366]
  PIN tap_d[367]
    DIRECTION OUTPUT ;
    USE SIGNAL ;
    PORT
      LAYER M4 ;
        RECT  0 43.728 0.084 43.752 ;
    END
  END tap_d[367]
  PIN tap_d[368]
    DIRECTION OUTPUT ;
    USE SIGNAL ;
    PORT
      LAYER M4 ;
        RECT  0 43.824 0.084 43.848 ;
    END
  END tap_d[368]
  PIN tap_d[369]
    DIRECTION OUTPUT ;
    USE SIGNAL ;
    PORT
      LAYER M4 ;
        RECT  0 43.92 0.084 43.944 ;
    END
  END tap_d[369]
  PIN tap_d[36]
    DIRECTION OUTPUT ;
    USE SIGNAL ;
    PORT
      LAYER M4 ;
        RECT  0 49.584 0.084 49.608 ;
    END
  END tap_d[36]
  PIN tap_d[370]
    DIRECTION OUTPUT ;
    USE SIGNAL ;
    PORT
      LAYER M4 ;
        RECT  0 44.016 0.084 44.04 ;
    END
  END tap_d[370]
  PIN tap_d[371]
    DIRECTION OUTPUT ;
    USE SIGNAL ;
    PORT
      LAYER M4 ;
        RECT  0 44.112 0.084 44.136 ;
    END
  END tap_d[371]
  PIN tap_d[372]
    DIRECTION OUTPUT ;
    USE SIGNAL ;
    PORT
      LAYER M4 ;
        RECT  0 44.208 0.084 44.232 ;
    END
  END tap_d[372]
  PIN tap_d[373]
    DIRECTION OUTPUT ;
    USE SIGNAL ;
    PORT
      LAYER M4 ;
        RECT  0 44.304 0.084 44.328 ;
    END
  END tap_d[373]
  PIN tap_d[374]
    DIRECTION OUTPUT ;
    USE SIGNAL ;
    PORT
      LAYER M4 ;
        RECT  0 44.4 0.084 44.424 ;
    END
  END tap_d[374]
  PIN tap_d[375]
    DIRECTION OUTPUT ;
    USE SIGNAL ;
    PORT
      LAYER M4 ;
        RECT  0 44.496 0.084 44.52 ;
    END
  END tap_d[375]
  PIN tap_d[376]
    DIRECTION OUTPUT ;
    USE SIGNAL ;
    PORT
      LAYER M4 ;
        RECT  0 44.592 0.084 44.616 ;
    END
  END tap_d[376]
  PIN tap_d[377]
    DIRECTION OUTPUT ;
    USE SIGNAL ;
    PORT
      LAYER M4 ;
        RECT  0 44.688 0.084 44.712 ;
    END
  END tap_d[377]
  PIN tap_d[378]
    DIRECTION OUTPUT ;
    USE SIGNAL ;
    PORT
      LAYER M4 ;
        RECT  0 44.784 0.084 44.808 ;
    END
  END tap_d[378]
  PIN tap_d[379]
    DIRECTION OUTPUT ;
    USE SIGNAL ;
    PORT
      LAYER M4 ;
        RECT  0 44.88 0.084 44.904 ;
    END
  END tap_d[379]
  PIN tap_d[37]
    DIRECTION OUTPUT ;
    USE SIGNAL ;
    PORT
      LAYER M4 ;
        RECT  0 49.68 0.084 49.704 ;
    END
  END tap_d[37]
  PIN tap_d[380]
    DIRECTION OUTPUT ;
    USE SIGNAL ;
    PORT
      LAYER M4 ;
        RECT  0 44.976 0.084 45 ;
    END
  END tap_d[380]
  PIN tap_d[381]
    DIRECTION OUTPUT ;
    USE SIGNAL ;
    PORT
      LAYER M4 ;
        RECT  0 45.072 0.084 45.096 ;
    END
  END tap_d[381]
  PIN tap_d[382]
    DIRECTION OUTPUT ;
    USE SIGNAL ;
    PORT
      LAYER M4 ;
        RECT  0 45.168 0.084 45.192 ;
    END
  END tap_d[382]
  PIN tap_d[383]
    DIRECTION OUTPUT ;
    USE SIGNAL ;
    PORT
      LAYER M4 ;
        RECT  0 45.264 0.084 45.288 ;
    END
  END tap_d[383]
  PIN tap_d[384]
    DIRECTION OUTPUT ;
    USE SIGNAL ;
    PORT
      LAYER M4 ;
        RECT  0 71.472 0.084 71.496 ;
    END
  END tap_d[384]
  PIN tap_d[385]
    DIRECTION OUTPUT ;
    USE SIGNAL ;
    PORT
      LAYER M4 ;
        RECT  0 71.568 0.084 71.592 ;
    END
  END tap_d[385]
  PIN tap_d[386]
    DIRECTION OUTPUT ;
    USE SIGNAL ;
    PORT
      LAYER M4 ;
        RECT  0 71.664 0.084 71.688 ;
    END
  END tap_d[386]
  PIN tap_d[387]
    DIRECTION OUTPUT ;
    USE SIGNAL ;
    PORT
      LAYER M4 ;
        RECT  0 71.76 0.084 71.784 ;
    END
  END tap_d[387]
  PIN tap_d[388]
    DIRECTION OUTPUT ;
    USE SIGNAL ;
    PORT
      LAYER M4 ;
        RECT  0 71.856 0.084 71.88 ;
    END
  END tap_d[388]
  PIN tap_d[389]
    DIRECTION OUTPUT ;
    USE SIGNAL ;
    PORT
      LAYER M4 ;
        RECT  0 71.952 0.084 71.976 ;
    END
  END tap_d[389]
  PIN tap_d[38]
    DIRECTION OUTPUT ;
    USE SIGNAL ;
    PORT
      LAYER M4 ;
        RECT  0 49.776 0.084 49.8 ;
    END
  END tap_d[38]
  PIN tap_d[390]
    DIRECTION OUTPUT ;
    USE SIGNAL ;
    PORT
      LAYER M4 ;
        RECT  0 72.048 0.084 72.072 ;
    END
  END tap_d[390]
  PIN tap_d[391]
    DIRECTION OUTPUT ;
    USE SIGNAL ;
    PORT
      LAYER M4 ;
        RECT  0 72.144 0.084 72.168 ;
    END
  END tap_d[391]
  PIN tap_d[392]
    DIRECTION OUTPUT ;
    USE SIGNAL ;
    PORT
      LAYER M4 ;
        RECT  0 72.24 0.084 72.264 ;
    END
  END tap_d[392]
  PIN tap_d[393]
    DIRECTION OUTPUT ;
    USE SIGNAL ;
    PORT
      LAYER M4 ;
        RECT  0 72.336 0.084 72.36 ;
    END
  END tap_d[393]
  PIN tap_d[394]
    DIRECTION OUTPUT ;
    USE SIGNAL ;
    PORT
      LAYER M4 ;
        RECT  0 72.432 0.084 72.456 ;
    END
  END tap_d[394]
  PIN tap_d[395]
    DIRECTION OUTPUT ;
    USE SIGNAL ;
    PORT
      LAYER M4 ;
        RECT  0 72.528 0.084 72.552 ;
    END
  END tap_d[395]
  PIN tap_d[396]
    DIRECTION OUTPUT ;
    USE SIGNAL ;
    PORT
      LAYER M4 ;
        RECT  0 72.624 0.084 72.648 ;
    END
  END tap_d[396]
  PIN tap_d[397]
    DIRECTION OUTPUT ;
    USE SIGNAL ;
    PORT
      LAYER M4 ;
        RECT  0 72.72 0.084 72.744 ;
    END
  END tap_d[397]
  PIN tap_d[398]
    DIRECTION OUTPUT ;
    USE SIGNAL ;
    PORT
      LAYER M4 ;
        RECT  0 72.816 0.084 72.84 ;
    END
  END tap_d[398]
  PIN tap_d[399]
    DIRECTION OUTPUT ;
    USE SIGNAL ;
    PORT
      LAYER M4 ;
        RECT  0 72.912 0.084 72.936 ;
    END
  END tap_d[399]
  PIN tap_d[39]
    DIRECTION OUTPUT ;
    USE SIGNAL ;
    PORT
      LAYER M4 ;
        RECT  0 49.872 0.084 49.896 ;
    END
  END tap_d[39]
  PIN tap_d[3]
    DIRECTION OUTPUT ;
    USE SIGNAL ;
    PORT
      LAYER M4 ;
        RECT  0 58.704 0.084 58.728 ;
    END
  END tap_d[3]
  PIN tap_d[400]
    DIRECTION OUTPUT ;
    USE SIGNAL ;
    PORT
      LAYER M4 ;
        RECT  0 73.008 0.084 73.032 ;
    END
  END tap_d[400]
  PIN tap_d[401]
    DIRECTION OUTPUT ;
    USE SIGNAL ;
    PORT
      LAYER M4 ;
        RECT  0 73.104 0.084 73.128 ;
    END
  END tap_d[401]
  PIN tap_d[402]
    DIRECTION OUTPUT ;
    USE SIGNAL ;
    PORT
      LAYER M4 ;
        RECT  0 73.2 0.084 73.224 ;
    END
  END tap_d[402]
  PIN tap_d[403]
    DIRECTION OUTPUT ;
    USE SIGNAL ;
    PORT
      LAYER M4 ;
        RECT  0 73.296 0.084 73.32 ;
    END
  END tap_d[403]
  PIN tap_d[404]
    DIRECTION OUTPUT ;
    USE SIGNAL ;
    PORT
      LAYER M4 ;
        RECT  0 73.392 0.084 73.416 ;
    END
  END tap_d[404]
  PIN tap_d[405]
    DIRECTION OUTPUT ;
    USE SIGNAL ;
    PORT
      LAYER M4 ;
        RECT  0 73.488 0.084 73.512 ;
    END
  END tap_d[405]
  PIN tap_d[406]
    DIRECTION OUTPUT ;
    USE SIGNAL ;
    PORT
      LAYER M4 ;
        RECT  0 73.584 0.084 73.608 ;
    END
  END tap_d[406]
  PIN tap_d[407]
    DIRECTION OUTPUT ;
    USE SIGNAL ;
    PORT
      LAYER M4 ;
        RECT  0 73.68 0.084 73.704 ;
    END
  END tap_d[407]
  PIN tap_d[408]
    DIRECTION OUTPUT ;
    USE SIGNAL ;
    PORT
      LAYER M4 ;
        RECT  0 73.776 0.084 73.8 ;
    END
  END tap_d[408]
  PIN tap_d[409]
    DIRECTION OUTPUT ;
    USE SIGNAL ;
    PORT
      LAYER M4 ;
        RECT  0 73.872 0.084 73.896 ;
    END
  END tap_d[409]
  PIN tap_d[40]
    DIRECTION OUTPUT ;
    USE SIGNAL ;
    PORT
      LAYER M4 ;
        RECT  0 49.968 0.084 49.992 ;
    END
  END tap_d[40]
  PIN tap_d[410]
    DIRECTION OUTPUT ;
    USE SIGNAL ;
    PORT
      LAYER M4 ;
        RECT  0 73.968 0.084 73.992 ;
    END
  END tap_d[410]
  PIN tap_d[411]
    DIRECTION OUTPUT ;
    USE SIGNAL ;
    PORT
      LAYER M4 ;
        RECT  0 74.064 0.084 74.088 ;
    END
  END tap_d[411]
  PIN tap_d[412]
    DIRECTION OUTPUT ;
    USE SIGNAL ;
    PORT
      LAYER M4 ;
        RECT  0 74.16 0.084 74.184 ;
    END
  END tap_d[412]
  PIN tap_d[413]
    DIRECTION OUTPUT ;
    USE SIGNAL ;
    PORT
      LAYER M4 ;
        RECT  0 74.256 0.084 74.28 ;
    END
  END tap_d[413]
  PIN tap_d[414]
    DIRECTION OUTPUT ;
    USE SIGNAL ;
    PORT
      LAYER M4 ;
        RECT  0 74.352 0.084 74.376 ;
    END
  END tap_d[414]
  PIN tap_d[415]
    DIRECTION OUTPUT ;
    USE SIGNAL ;
    PORT
      LAYER M4 ;
        RECT  0 74.448 0.084 74.472 ;
    END
  END tap_d[415]
  PIN tap_d[416]
    DIRECTION OUTPUT ;
    USE SIGNAL ;
    PORT
      LAYER M4 ;
        RECT  0 68.4 0.084 68.424 ;
    END
  END tap_d[416]
  PIN tap_d[417]
    DIRECTION OUTPUT ;
    USE SIGNAL ;
    PORT
      LAYER M4 ;
        RECT  0 68.496 0.084 68.52 ;
    END
  END tap_d[417]
  PIN tap_d[418]
    DIRECTION OUTPUT ;
    USE SIGNAL ;
    PORT
      LAYER M4 ;
        RECT  0 68.592 0.084 68.616 ;
    END
  END tap_d[418]
  PIN tap_d[419]
    DIRECTION OUTPUT ;
    USE SIGNAL ;
    PORT
      LAYER M4 ;
        RECT  0 68.688 0.084 68.712 ;
    END
  END tap_d[419]
  PIN tap_d[41]
    DIRECTION OUTPUT ;
    USE SIGNAL ;
    PORT
      LAYER M4 ;
        RECT  0 50.064 0.084 50.088 ;
    END
  END tap_d[41]
  PIN tap_d[420]
    DIRECTION OUTPUT ;
    USE SIGNAL ;
    PORT
      LAYER M4 ;
        RECT  0 68.784 0.084 68.808 ;
    END
  END tap_d[420]
  PIN tap_d[421]
    DIRECTION OUTPUT ;
    USE SIGNAL ;
    PORT
      LAYER M4 ;
        RECT  0 68.88 0.084 68.904 ;
    END
  END tap_d[421]
  PIN tap_d[422]
    DIRECTION OUTPUT ;
    USE SIGNAL ;
    PORT
      LAYER M4 ;
        RECT  0 68.976 0.084 69 ;
    END
  END tap_d[422]
  PIN tap_d[423]
    DIRECTION OUTPUT ;
    USE SIGNAL ;
    PORT
      LAYER M4 ;
        RECT  0 69.072 0.084 69.096 ;
    END
  END tap_d[423]
  PIN tap_d[424]
    DIRECTION OUTPUT ;
    USE SIGNAL ;
    PORT
      LAYER M4 ;
        RECT  0 69.168 0.084 69.192 ;
    END
  END tap_d[424]
  PIN tap_d[425]
    DIRECTION OUTPUT ;
    USE SIGNAL ;
    PORT
      LAYER M4 ;
        RECT  0 69.264 0.084 69.288 ;
    END
  END tap_d[425]
  PIN tap_d[426]
    DIRECTION OUTPUT ;
    USE SIGNAL ;
    PORT
      LAYER M4 ;
        RECT  0 69.36 0.084 69.384 ;
    END
  END tap_d[426]
  PIN tap_d[427]
    DIRECTION OUTPUT ;
    USE SIGNAL ;
    PORT
      LAYER M4 ;
        RECT  0 69.456 0.084 69.48 ;
    END
  END tap_d[427]
  PIN tap_d[428]
    DIRECTION OUTPUT ;
    USE SIGNAL ;
    PORT
      LAYER M4 ;
        RECT  0 69.552 0.084 69.576 ;
    END
  END tap_d[428]
  PIN tap_d[429]
    DIRECTION OUTPUT ;
    USE SIGNAL ;
    PORT
      LAYER M4 ;
        RECT  0 69.648 0.084 69.672 ;
    END
  END tap_d[429]
  PIN tap_d[42]
    DIRECTION OUTPUT ;
    USE SIGNAL ;
    PORT
      LAYER M4 ;
        RECT  0 50.16 0.084 50.184 ;
    END
  END tap_d[42]
  PIN tap_d[430]
    DIRECTION OUTPUT ;
    USE SIGNAL ;
    PORT
      LAYER M4 ;
        RECT  0 69.744 0.084 69.768 ;
    END
  END tap_d[430]
  PIN tap_d[431]
    DIRECTION OUTPUT ;
    USE SIGNAL ;
    PORT
      LAYER M4 ;
        RECT  0 69.84 0.084 69.864 ;
    END
  END tap_d[431]
  PIN tap_d[432]
    DIRECTION OUTPUT ;
    USE SIGNAL ;
    PORT
      LAYER M4 ;
        RECT  0 69.936 0.084 69.96 ;
    END
  END tap_d[432]
  PIN tap_d[433]
    DIRECTION OUTPUT ;
    USE SIGNAL ;
    PORT
      LAYER M4 ;
        RECT  0 70.032 0.084 70.056 ;
    END
  END tap_d[433]
  PIN tap_d[434]
    DIRECTION OUTPUT ;
    USE SIGNAL ;
    PORT
      LAYER M4 ;
        RECT  0 70.128 0.084 70.152 ;
    END
  END tap_d[434]
  PIN tap_d[435]
    DIRECTION OUTPUT ;
    USE SIGNAL ;
    PORT
      LAYER M4 ;
        RECT  0 70.224 0.084 70.248 ;
    END
  END tap_d[435]
  PIN tap_d[436]
    DIRECTION OUTPUT ;
    USE SIGNAL ;
    PORT
      LAYER M4 ;
        RECT  0 70.32 0.084 70.344 ;
    END
  END tap_d[436]
  PIN tap_d[437]
    DIRECTION OUTPUT ;
    USE SIGNAL ;
    PORT
      LAYER M4 ;
        RECT  0 70.416 0.084 70.44 ;
    END
  END tap_d[437]
  PIN tap_d[438]
    DIRECTION OUTPUT ;
    USE SIGNAL ;
    PORT
      LAYER M4 ;
        RECT  0 70.512 0.084 70.536 ;
    END
  END tap_d[438]
  PIN tap_d[439]
    DIRECTION OUTPUT ;
    USE SIGNAL ;
    PORT
      LAYER M4 ;
        RECT  0 70.608 0.084 70.632 ;
    END
  END tap_d[439]
  PIN tap_d[43]
    DIRECTION OUTPUT ;
    USE SIGNAL ;
    PORT
      LAYER M4 ;
        RECT  0 50.256 0.084 50.28 ;
    END
  END tap_d[43]
  PIN tap_d[440]
    DIRECTION OUTPUT ;
    USE SIGNAL ;
    PORT
      LAYER M4 ;
        RECT  0 70.704 0.084 70.728 ;
    END
  END tap_d[440]
  PIN tap_d[441]
    DIRECTION OUTPUT ;
    USE SIGNAL ;
    PORT
      LAYER M4 ;
        RECT  0 70.8 0.084 70.824 ;
    END
  END tap_d[441]
  PIN tap_d[442]
    DIRECTION OUTPUT ;
    USE SIGNAL ;
    PORT
      LAYER M4 ;
        RECT  0 70.896 0.084 70.92 ;
    END
  END tap_d[442]
  PIN tap_d[443]
    DIRECTION OUTPUT ;
    USE SIGNAL ;
    PORT
      LAYER M4 ;
        RECT  0 70.992 0.084 71.016 ;
    END
  END tap_d[443]
  PIN tap_d[444]
    DIRECTION OUTPUT ;
    USE SIGNAL ;
    PORT
      LAYER M4 ;
        RECT  0 71.088 0.084 71.112 ;
    END
  END tap_d[444]
  PIN tap_d[445]
    DIRECTION OUTPUT ;
    USE SIGNAL ;
    PORT
      LAYER M4 ;
        RECT  0 71.184 0.084 71.208 ;
    END
  END tap_d[445]
  PIN tap_d[446]
    DIRECTION OUTPUT ;
    USE SIGNAL ;
    PORT
      LAYER M4 ;
        RECT  0 71.28 0.084 71.304 ;
    END
  END tap_d[446]
  PIN tap_d[447]
    DIRECTION OUTPUT ;
    USE SIGNAL ;
    PORT
      LAYER M4 ;
        RECT  0 71.376 0.084 71.4 ;
    END
  END tap_d[447]
  PIN tap_d[448]
    DIRECTION OUTPUT ;
    USE SIGNAL ;
    PORT
      LAYER M4 ;
        RECT  0 65.328 0.084 65.352 ;
    END
  END tap_d[448]
  PIN tap_d[449]
    DIRECTION OUTPUT ;
    USE SIGNAL ;
    PORT
      LAYER M4 ;
        RECT  0 65.424 0.084 65.448 ;
    END
  END tap_d[449]
  PIN tap_d[44]
    DIRECTION OUTPUT ;
    USE SIGNAL ;
    PORT
      LAYER M4 ;
        RECT  0 50.352 0.084 50.376 ;
    END
  END tap_d[44]
  PIN tap_d[450]
    DIRECTION OUTPUT ;
    USE SIGNAL ;
    PORT
      LAYER M4 ;
        RECT  0 65.52 0.084 65.544 ;
    END
  END tap_d[450]
  PIN tap_d[451]
    DIRECTION OUTPUT ;
    USE SIGNAL ;
    PORT
      LAYER M4 ;
        RECT  0 65.616 0.084 65.64 ;
    END
  END tap_d[451]
  PIN tap_d[452]
    DIRECTION OUTPUT ;
    USE SIGNAL ;
    PORT
      LAYER M4 ;
        RECT  0 65.712 0.084 65.736 ;
    END
  END tap_d[452]
  PIN tap_d[453]
    DIRECTION OUTPUT ;
    USE SIGNAL ;
    PORT
      LAYER M4 ;
        RECT  0 65.808 0.084 65.832 ;
    END
  END tap_d[453]
  PIN tap_d[454]
    DIRECTION OUTPUT ;
    USE SIGNAL ;
    PORT
      LAYER M4 ;
        RECT  0 65.904 0.084 65.928 ;
    END
  END tap_d[454]
  PIN tap_d[455]
    DIRECTION OUTPUT ;
    USE SIGNAL ;
    PORT
      LAYER M4 ;
        RECT  0 66 0.084 66.024 ;
    END
  END tap_d[455]
  PIN tap_d[456]
    DIRECTION OUTPUT ;
    USE SIGNAL ;
    PORT
      LAYER M4 ;
        RECT  0 66.096 0.084 66.12 ;
    END
  END tap_d[456]
  PIN tap_d[457]
    DIRECTION OUTPUT ;
    USE SIGNAL ;
    PORT
      LAYER M4 ;
        RECT  0 66.192 0.084 66.216 ;
    END
  END tap_d[457]
  PIN tap_d[458]
    DIRECTION OUTPUT ;
    USE SIGNAL ;
    PORT
      LAYER M4 ;
        RECT  0 66.288 0.084 66.312 ;
    END
  END tap_d[458]
  PIN tap_d[459]
    DIRECTION OUTPUT ;
    USE SIGNAL ;
    PORT
      LAYER M4 ;
        RECT  0 66.384 0.084 66.408 ;
    END
  END tap_d[459]
  PIN tap_d[45]
    DIRECTION OUTPUT ;
    USE SIGNAL ;
    PORT
      LAYER M4 ;
        RECT  0 50.448 0.084 50.472 ;
    END
  END tap_d[45]
  PIN tap_d[460]
    DIRECTION OUTPUT ;
    USE SIGNAL ;
    PORT
      LAYER M4 ;
        RECT  0 66.48 0.084 66.504 ;
    END
  END tap_d[460]
  PIN tap_d[461]
    DIRECTION OUTPUT ;
    USE SIGNAL ;
    PORT
      LAYER M4 ;
        RECT  0 66.576 0.084 66.6 ;
    END
  END tap_d[461]
  PIN tap_d[462]
    DIRECTION OUTPUT ;
    USE SIGNAL ;
    PORT
      LAYER M4 ;
        RECT  0 66.672 0.084 66.696 ;
    END
  END tap_d[462]
  PIN tap_d[463]
    DIRECTION OUTPUT ;
    USE SIGNAL ;
    PORT
      LAYER M4 ;
        RECT  0 66.768 0.084 66.792 ;
    END
  END tap_d[463]
  PIN tap_d[464]
    DIRECTION OUTPUT ;
    USE SIGNAL ;
    PORT
      LAYER M4 ;
        RECT  0 66.864 0.084 66.888 ;
    END
  END tap_d[464]
  PIN tap_d[465]
    DIRECTION OUTPUT ;
    USE SIGNAL ;
    PORT
      LAYER M4 ;
        RECT  0 66.96 0.084 66.984 ;
    END
  END tap_d[465]
  PIN tap_d[466]
    DIRECTION OUTPUT ;
    USE SIGNAL ;
    PORT
      LAYER M4 ;
        RECT  0 67.056 0.084 67.08 ;
    END
  END tap_d[466]
  PIN tap_d[467]
    DIRECTION OUTPUT ;
    USE SIGNAL ;
    PORT
      LAYER M4 ;
        RECT  0 67.152 0.084 67.176 ;
    END
  END tap_d[467]
  PIN tap_d[468]
    DIRECTION OUTPUT ;
    USE SIGNAL ;
    PORT
      LAYER M4 ;
        RECT  0 67.248 0.084 67.272 ;
    END
  END tap_d[468]
  PIN tap_d[469]
    DIRECTION OUTPUT ;
    USE SIGNAL ;
    PORT
      LAYER M4 ;
        RECT  0 67.344 0.084 67.368 ;
    END
  END tap_d[469]
  PIN tap_d[46]
    DIRECTION OUTPUT ;
    USE SIGNAL ;
    PORT
      LAYER M4 ;
        RECT  0 50.544 0.084 50.568 ;
    END
  END tap_d[46]
  PIN tap_d[470]
    DIRECTION OUTPUT ;
    USE SIGNAL ;
    PORT
      LAYER M4 ;
        RECT  0 67.44 0.084 67.464 ;
    END
  END tap_d[470]
  PIN tap_d[471]
    DIRECTION OUTPUT ;
    USE SIGNAL ;
    PORT
      LAYER M4 ;
        RECT  0 67.536 0.084 67.56 ;
    END
  END tap_d[471]
  PIN tap_d[472]
    DIRECTION OUTPUT ;
    USE SIGNAL ;
    PORT
      LAYER M4 ;
        RECT  0 67.632 0.084 67.656 ;
    END
  END tap_d[472]
  PIN tap_d[473]
    DIRECTION OUTPUT ;
    USE SIGNAL ;
    PORT
      LAYER M4 ;
        RECT  0 67.728 0.084 67.752 ;
    END
  END tap_d[473]
  PIN tap_d[474]
    DIRECTION OUTPUT ;
    USE SIGNAL ;
    PORT
      LAYER M4 ;
        RECT  0 67.824 0.084 67.848 ;
    END
  END tap_d[474]
  PIN tap_d[475]
    DIRECTION OUTPUT ;
    USE SIGNAL ;
    PORT
      LAYER M4 ;
        RECT  0 67.92 0.084 67.944 ;
    END
  END tap_d[475]
  PIN tap_d[476]
    DIRECTION OUTPUT ;
    USE SIGNAL ;
    PORT
      LAYER M4 ;
        RECT  0 68.016 0.084 68.04 ;
    END
  END tap_d[476]
  PIN tap_d[477]
    DIRECTION OUTPUT ;
    USE SIGNAL ;
    PORT
      LAYER M4 ;
        RECT  0 68.112 0.084 68.136 ;
    END
  END tap_d[477]
  PIN tap_d[478]
    DIRECTION OUTPUT ;
    USE SIGNAL ;
    PORT
      LAYER M4 ;
        RECT  0 68.208 0.084 68.232 ;
    END
  END tap_d[478]
  PIN tap_d[479]
    DIRECTION OUTPUT ;
    USE SIGNAL ;
    PORT
      LAYER M4 ;
        RECT  0 68.304 0.084 68.328 ;
    END
  END tap_d[479]
  PIN tap_d[47]
    DIRECTION OUTPUT ;
    USE SIGNAL ;
    PORT
      LAYER M4 ;
        RECT  0 50.64 0.084 50.664 ;
    END
  END tap_d[47]
  PIN tap_d[480]
    DIRECTION OUTPUT ;
    USE SIGNAL ;
    PORT
      LAYER M4 ;
        RECT  0 74.832 0.084 74.856 ;
    END
  END tap_d[480]
  PIN tap_d[481]
    DIRECTION OUTPUT ;
    USE SIGNAL ;
    PORT
      LAYER M4 ;
        RECT  0 74.928 0.084 74.952 ;
    END
  END tap_d[481]
  PIN tap_d[482]
    DIRECTION OUTPUT ;
    USE SIGNAL ;
    PORT
      LAYER M4 ;
        RECT  0 75.024 0.084 75.048 ;
    END
  END tap_d[482]
  PIN tap_d[483]
    DIRECTION OUTPUT ;
    USE SIGNAL ;
    PORT
      LAYER M4 ;
        RECT  0 75.12 0.084 75.144 ;
    END
  END tap_d[483]
  PIN tap_d[484]
    DIRECTION OUTPUT ;
    USE SIGNAL ;
    PORT
      LAYER M4 ;
        RECT  0 75.216 0.084 75.24 ;
    END
  END tap_d[484]
  PIN tap_d[485]
    DIRECTION OUTPUT ;
    USE SIGNAL ;
    PORT
      LAYER M4 ;
        RECT  0 75.312 0.084 75.336 ;
    END
  END tap_d[485]
  PIN tap_d[486]
    DIRECTION OUTPUT ;
    USE SIGNAL ;
    PORT
      LAYER M4 ;
        RECT  0 75.408 0.084 75.432 ;
    END
  END tap_d[486]
  PIN tap_d[487]
    DIRECTION OUTPUT ;
    USE SIGNAL ;
    PORT
      LAYER M4 ;
        RECT  0 75.504 0.084 75.528 ;
    END
  END tap_d[487]
  PIN tap_d[488]
    DIRECTION OUTPUT ;
    USE SIGNAL ;
    PORT
      LAYER M4 ;
        RECT  0 75.6 0.084 75.624 ;
    END
  END tap_d[488]
  PIN tap_d[489]
    DIRECTION OUTPUT ;
    USE SIGNAL ;
    PORT
      LAYER M4 ;
        RECT  0 75.696 0.084 75.72 ;
    END
  END tap_d[489]
  PIN tap_d[48]
    DIRECTION OUTPUT ;
    USE SIGNAL ;
    PORT
      LAYER M4 ;
        RECT  0 50.736 0.084 50.76 ;
    END
  END tap_d[48]
  PIN tap_d[490]
    DIRECTION OUTPUT ;
    USE SIGNAL ;
    PORT
      LAYER M4 ;
        RECT  0 75.792 0.084 75.816 ;
    END
  END tap_d[490]
  PIN tap_d[491]
    DIRECTION OUTPUT ;
    USE SIGNAL ;
    PORT
      LAYER M4 ;
        RECT  0 75.888 0.084 75.912 ;
    END
  END tap_d[491]
  PIN tap_d[492]
    DIRECTION OUTPUT ;
    USE SIGNAL ;
    PORT
      LAYER M4 ;
        RECT  0 75.984 0.084 76.008 ;
    END
  END tap_d[492]
  PIN tap_d[493]
    DIRECTION OUTPUT ;
    USE SIGNAL ;
    PORT
      LAYER M4 ;
        RECT  0 76.08 0.084 76.104 ;
    END
  END tap_d[493]
  PIN tap_d[494]
    DIRECTION OUTPUT ;
    USE SIGNAL ;
    PORT
      LAYER M4 ;
        RECT  0 76.176 0.084 76.2 ;
    END
  END tap_d[494]
  PIN tap_d[495]
    DIRECTION OUTPUT ;
    USE SIGNAL ;
    PORT
      LAYER M4 ;
        RECT  0 76.272 0.084 76.296 ;
    END
  END tap_d[495]
  PIN tap_d[496]
    DIRECTION OUTPUT ;
    USE SIGNAL ;
    PORT
      LAYER M4 ;
        RECT  0 76.368 0.084 76.392 ;
    END
  END tap_d[496]
  PIN tap_d[497]
    DIRECTION OUTPUT ;
    USE SIGNAL ;
    PORT
      LAYER M4 ;
        RECT  0 76.464 0.084 76.488 ;
    END
  END tap_d[497]
  PIN tap_d[498]
    DIRECTION OUTPUT ;
    USE SIGNAL ;
    PORT
      LAYER M4 ;
        RECT  0 76.56 0.084 76.584 ;
    END
  END tap_d[498]
  PIN tap_d[499]
    DIRECTION OUTPUT ;
    USE SIGNAL ;
    PORT
      LAYER M4 ;
        RECT  0 76.656 0.084 76.68 ;
    END
  END tap_d[499]
  PIN tap_d[49]
    DIRECTION OUTPUT ;
    USE SIGNAL ;
    PORT
      LAYER M4 ;
        RECT  0 50.832 0.084 50.856 ;
    END
  END tap_d[49]
  PIN tap_d[4]
    DIRECTION OUTPUT ;
    USE SIGNAL ;
    PORT
      LAYER M4 ;
        RECT  0 58.8 0.084 58.824 ;
    END
  END tap_d[4]
  PIN tap_d[500]
    DIRECTION OUTPUT ;
    USE SIGNAL ;
    PORT
      LAYER M4 ;
        RECT  0 76.752 0.084 76.776 ;
    END
  END tap_d[500]
  PIN tap_d[501]
    DIRECTION OUTPUT ;
    USE SIGNAL ;
    PORT
      LAYER M4 ;
        RECT  0 76.848 0.084 76.872 ;
    END
  END tap_d[501]
  PIN tap_d[502]
    DIRECTION OUTPUT ;
    USE SIGNAL ;
    PORT
      LAYER M4 ;
        RECT  0 76.944 0.084 76.968 ;
    END
  END tap_d[502]
  PIN tap_d[503]
    DIRECTION OUTPUT ;
    USE SIGNAL ;
    PORT
      LAYER M4 ;
        RECT  0 77.04 0.084 77.064 ;
    END
  END tap_d[503]
  PIN tap_d[504]
    DIRECTION OUTPUT ;
    USE SIGNAL ;
    PORT
      LAYER M4 ;
        RECT  0 77.136 0.084 77.16 ;
    END
  END tap_d[504]
  PIN tap_d[505]
    DIRECTION OUTPUT ;
    USE SIGNAL ;
    PORT
      LAYER M4 ;
        RECT  0 77.232 0.084 77.256 ;
    END
  END tap_d[505]
  PIN tap_d[506]
    DIRECTION OUTPUT ;
    USE SIGNAL ;
    PORT
      LAYER M4 ;
        RECT  0 77.328 0.084 77.352 ;
    END
  END tap_d[506]
  PIN tap_d[507]
    DIRECTION OUTPUT ;
    USE SIGNAL ;
    PORT
      LAYER M4 ;
        RECT  0 77.424 0.084 77.448 ;
    END
  END tap_d[507]
  PIN tap_d[50]
    DIRECTION OUTPUT ;
    USE SIGNAL ;
    PORT
      LAYER M4 ;
        RECT  0 50.928 0.084 50.952 ;
    END
  END tap_d[50]
  PIN tap_d[51]
    DIRECTION OUTPUT ;
    USE SIGNAL ;
    PORT
      LAYER M4 ;
        RECT  0 51.024 0.084 51.048 ;
    END
  END tap_d[51]
  PIN tap_d[52]
    DIRECTION OUTPUT ;
    USE SIGNAL ;
    PORT
      LAYER M4 ;
        RECT  0 51.12 0.084 51.144 ;
    END
  END tap_d[52]
  PIN tap_d[53]
    DIRECTION OUTPUT ;
    USE SIGNAL ;
    PORT
      LAYER M4 ;
        RECT  0 51.216 0.084 51.24 ;
    END
  END tap_d[53]
  PIN tap_d[54]
    DIRECTION OUTPUT ;
    USE SIGNAL ;
    PORT
      LAYER M4 ;
        RECT  0 51.312 0.084 51.336 ;
    END
  END tap_d[54]
  PIN tap_d[55]
    DIRECTION OUTPUT ;
    USE SIGNAL ;
    PORT
      LAYER M4 ;
        RECT  0 51.408 0.084 51.432 ;
    END
  END tap_d[55]
  PIN tap_d[56]
    DIRECTION OUTPUT ;
    USE SIGNAL ;
    PORT
      LAYER M4 ;
        RECT  0 51.504 0.084 51.528 ;
    END
  END tap_d[56]
  PIN tap_d[57]
    DIRECTION OUTPUT ;
    USE SIGNAL ;
    PORT
      LAYER M4 ;
        RECT  0 51.6 0.084 51.624 ;
    END
  END tap_d[57]
  PIN tap_d[58]
    DIRECTION OUTPUT ;
    USE SIGNAL ;
    PORT
      LAYER M4 ;
        RECT  0 51.696 0.084 51.72 ;
    END
  END tap_d[58]
  PIN tap_d[59]
    DIRECTION OUTPUT ;
    USE SIGNAL ;
    PORT
      LAYER M4 ;
        RECT  0 51.792 0.084 51.816 ;
    END
  END tap_d[59]
  PIN tap_d[5]
    DIRECTION OUTPUT ;
    USE SIGNAL ;
    PORT
      LAYER M4 ;
        RECT  0 58.896 0.084 58.92 ;
    END
  END tap_d[5]
  PIN tap_d[60]
    DIRECTION OUTPUT ;
    USE SIGNAL ;
    PORT
      LAYER M4 ;
        RECT  0 51.888 0.084 51.912 ;
    END
  END tap_d[60]
  PIN tap_d[61]
    DIRECTION OUTPUT ;
    USE SIGNAL ;
    PORT
      LAYER M4 ;
        RECT  0 51.984 0.084 52.008 ;
    END
  END tap_d[61]
  PIN tap_d[62]
    DIRECTION OUTPUT ;
    USE SIGNAL ;
    PORT
      LAYER M4 ;
        RECT  0 52.08 0.084 52.104 ;
    END
  END tap_d[62]
  PIN tap_d[63]
    DIRECTION OUTPUT ;
    USE SIGNAL ;
    PORT
      LAYER M4 ;
        RECT  0 52.176 0.084 52.2 ;
    END
  END tap_d[63]
  PIN tap_d[64]
    DIRECTION OUTPUT ;
    USE SIGNAL ;
    PORT
      LAYER M4 ;
        RECT  0 46.128 0.084 46.152 ;
    END
  END tap_d[64]
  PIN tap_d[65]
    DIRECTION OUTPUT ;
    USE SIGNAL ;
    PORT
      LAYER M4 ;
        RECT  0 46.224 0.084 46.248 ;
    END
  END tap_d[65]
  PIN tap_d[66]
    DIRECTION OUTPUT ;
    USE SIGNAL ;
    PORT
      LAYER M4 ;
        RECT  0 46.32 0.084 46.344 ;
    END
  END tap_d[66]
  PIN tap_d[67]
    DIRECTION OUTPUT ;
    USE SIGNAL ;
    PORT
      LAYER M4 ;
        RECT  0 46.416 0.084 46.44 ;
    END
  END tap_d[67]
  PIN tap_d[68]
    DIRECTION OUTPUT ;
    USE SIGNAL ;
    PORT
      LAYER M4 ;
        RECT  0 46.512 0.084 46.536 ;
    END
  END tap_d[68]
  PIN tap_d[69]
    DIRECTION OUTPUT ;
    USE SIGNAL ;
    PORT
      LAYER M4 ;
        RECT  0 46.608 0.084 46.632 ;
    END
  END tap_d[69]
  PIN tap_d[6]
    DIRECTION OUTPUT ;
    USE SIGNAL ;
    PORT
      LAYER M4 ;
        RECT  0 58.992 0.084 59.016 ;
    END
  END tap_d[6]
  PIN tap_d[70]
    DIRECTION OUTPUT ;
    USE SIGNAL ;
    PORT
      LAYER M4 ;
        RECT  0 46.704 0.084 46.728 ;
    END
  END tap_d[70]
  PIN tap_d[71]
    DIRECTION OUTPUT ;
    USE SIGNAL ;
    PORT
      LAYER M4 ;
        RECT  0 46.8 0.084 46.824 ;
    END
  END tap_d[71]
  PIN tap_d[72]
    DIRECTION OUTPUT ;
    USE SIGNAL ;
    PORT
      LAYER M4 ;
        RECT  0 46.896 0.084 46.92 ;
    END
  END tap_d[72]
  PIN tap_d[73]
    DIRECTION OUTPUT ;
    USE SIGNAL ;
    PORT
      LAYER M4 ;
        RECT  0 46.992 0.084 47.016 ;
    END
  END tap_d[73]
  PIN tap_d[74]
    DIRECTION OUTPUT ;
    USE SIGNAL ;
    PORT
      LAYER M4 ;
        RECT  0 47.088 0.084 47.112 ;
    END
  END tap_d[74]
  PIN tap_d[75]
    DIRECTION OUTPUT ;
    USE SIGNAL ;
    PORT
      LAYER M4 ;
        RECT  0 47.184 0.084 47.208 ;
    END
  END tap_d[75]
  PIN tap_d[76]
    DIRECTION OUTPUT ;
    USE SIGNAL ;
    PORT
      LAYER M4 ;
        RECT  0 47.28 0.084 47.304 ;
    END
  END tap_d[76]
  PIN tap_d[77]
    DIRECTION OUTPUT ;
    USE SIGNAL ;
    PORT
      LAYER M4 ;
        RECT  0 47.376 0.084 47.4 ;
    END
  END tap_d[77]
  PIN tap_d[78]
    DIRECTION OUTPUT ;
    USE SIGNAL ;
    PORT
      LAYER M4 ;
        RECT  0 47.472 0.084 47.496 ;
    END
  END tap_d[78]
  PIN tap_d[79]
    DIRECTION OUTPUT ;
    USE SIGNAL ;
    PORT
      LAYER M4 ;
        RECT  0 47.568 0.084 47.592 ;
    END
  END tap_d[79]
  PIN tap_d[7]
    DIRECTION OUTPUT ;
    USE SIGNAL ;
    PORT
      LAYER M4 ;
        RECT  0 59.088 0.084 59.112 ;
    END
  END tap_d[7]
  PIN tap_d[80]
    DIRECTION OUTPUT ;
    USE SIGNAL ;
    PORT
      LAYER M4 ;
        RECT  0 47.664 0.084 47.688 ;
    END
  END tap_d[80]
  PIN tap_d[81]
    DIRECTION OUTPUT ;
    USE SIGNAL ;
    PORT
      LAYER M4 ;
        RECT  0 47.76 0.084 47.784 ;
    END
  END tap_d[81]
  PIN tap_d[82]
    DIRECTION OUTPUT ;
    USE SIGNAL ;
    PORT
      LAYER M4 ;
        RECT  0 47.856 0.084 47.88 ;
    END
  END tap_d[82]
  PIN tap_d[83]
    DIRECTION OUTPUT ;
    USE SIGNAL ;
    PORT
      LAYER M4 ;
        RECT  0 47.952 0.084 47.976 ;
    END
  END tap_d[83]
  PIN tap_d[84]
    DIRECTION OUTPUT ;
    USE SIGNAL ;
    PORT
      LAYER M4 ;
        RECT  0 48.048 0.084 48.072 ;
    END
  END tap_d[84]
  PIN tap_d[85]
    DIRECTION OUTPUT ;
    USE SIGNAL ;
    PORT
      LAYER M4 ;
        RECT  0 48.144 0.084 48.168 ;
    END
  END tap_d[85]
  PIN tap_d[86]
    DIRECTION OUTPUT ;
    USE SIGNAL ;
    PORT
      LAYER M4 ;
        RECT  0 48.24 0.084 48.264 ;
    END
  END tap_d[86]
  PIN tap_d[87]
    DIRECTION OUTPUT ;
    USE SIGNAL ;
    PORT
      LAYER M4 ;
        RECT  0 48.336 0.084 48.36 ;
    END
  END tap_d[87]
  PIN tap_d[88]
    DIRECTION OUTPUT ;
    USE SIGNAL ;
    PORT
      LAYER M4 ;
        RECT  0 48.432 0.084 48.456 ;
    END
  END tap_d[88]
  PIN tap_d[89]
    DIRECTION OUTPUT ;
    USE SIGNAL ;
    PORT
      LAYER M4 ;
        RECT  0 48.528 0.084 48.552 ;
    END
  END tap_d[89]
  PIN tap_d[8]
    DIRECTION OUTPUT ;
    USE SIGNAL ;
    PORT
      LAYER M4 ;
        RECT  0 59.184 0.084 59.208 ;
    END
  END tap_d[8]
  PIN tap_d[90]
    DIRECTION OUTPUT ;
    USE SIGNAL ;
    PORT
      LAYER M4 ;
        RECT  0 48.624 0.084 48.648 ;
    END
  END tap_d[90]
  PIN tap_d[91]
    DIRECTION OUTPUT ;
    USE SIGNAL ;
    PORT
      LAYER M4 ;
        RECT  0 48.72 0.084 48.744 ;
    END
  END tap_d[91]
  PIN tap_d[92]
    DIRECTION OUTPUT ;
    USE SIGNAL ;
    PORT
      LAYER M4 ;
        RECT  0 48.816 0.084 48.84 ;
    END
  END tap_d[92]
  PIN tap_d[93]
    DIRECTION OUTPUT ;
    USE SIGNAL ;
    PORT
      LAYER M4 ;
        RECT  0 48.912 0.084 48.936 ;
    END
  END tap_d[93]
  PIN tap_d[94]
    DIRECTION OUTPUT ;
    USE SIGNAL ;
    PORT
      LAYER M4 ;
        RECT  0 49.008 0.084 49.032 ;
    END
  END tap_d[94]
  PIN tap_d[95]
    DIRECTION OUTPUT ;
    USE SIGNAL ;
    PORT
      LAYER M4 ;
        RECT  0 49.104 0.084 49.128 ;
    END
  END tap_d[95]
  PIN tap_d[96]
    DIRECTION OUTPUT ;
    USE SIGNAL ;
    PORT
      LAYER M4 ;
        RECT  0 52.272 0.084 52.296 ;
    END
  END tap_d[96]
  PIN tap_d[97]
    DIRECTION OUTPUT ;
    USE SIGNAL ;
    PORT
      LAYER M4 ;
        RECT  0 52.368 0.084 52.392 ;
    END
  END tap_d[97]
  PIN tap_d[98]
    DIRECTION OUTPUT ;
    USE SIGNAL ;
    PORT
      LAYER M4 ;
        RECT  0 52.464 0.084 52.488 ;
    END
  END tap_d[98]
  PIN tap_d[99]
    DIRECTION OUTPUT ;
    USE SIGNAL ;
    PORT
      LAYER M4 ;
        RECT  0 52.56 0.084 52.584 ;
    END
  END tap_d[99]
  PIN tap_d[9]
    DIRECTION OUTPUT ;
    USE SIGNAL ;
    PORT
      LAYER M4 ;
        RECT  0 59.28 0.084 59.304 ;
    END
  END tap_d[9]
  PIN tap_r
    DIRECTION INPUT ;
    USE SIGNAL ;
    PORT
      LAYER M4 ;
        RECT  0 77.52 0.084 77.544 ;
    END
  END tap_r
  PIN VDD
    DIRECTION INOUT ;
    USE POWER ;
    PORT
      LAYER M5 ;
        RECT  45.792 2.151 45.912 101.273 ;
        RECT  40.392 2.151 40.512 101.273 ;
        RECT  34.992 2.151 35.112 101.273 ;
        RECT  29.592 2.151 29.712 101.273 ;
        RECT  24.192 2.151 24.312 101.273 ;
        RECT  18.792 2.151 18.912 101.273 ;
        RECT  13.392 2.151 13.512 101.273 ;
        RECT  7.992 2.151 8.112 101.273 ;
        RECT  2.592 2.151 2.712 101.273 ;
    END
  END VDD
  PIN VSS
    DIRECTION INOUT ;
    USE GROUND ;
    PORT
      LAYER M5 ;
        RECT  45.6 2.137 45.72 101.259 ;
        RECT  40.2 2.137 40.32 101.259 ;
        RECT  34.8 2.137 34.92 101.259 ;
        RECT  29.4 2.137 29.52 101.259 ;
        RECT  24 2.137 24.12 101.259 ;
        RECT  18.6 2.137 18.72 101.259 ;
        RECT  13.2 2.137 13.32 101.259 ;
        RECT  7.8 2.137 7.92 101.259 ;
        RECT  2.4 2.137 2.52 101.259 ;
    END
  END VSS
  OBS
    LAYER RVTN ;
     RECT  2.16 2.16 50.49 2.295 ;
     RECT  2.16 2.565 50.49 2.835 ;
     RECT  2.16 3.105 50.49 3.375 ;
     RECT  2.16 3.645 50.49 3.915 ;
     RECT  2.16 4.185 50.49 4.455 ;
     RECT  2.16 4.725 50.49 4.995 ;
     RECT  2.16 5.265 50.49 5.535 ;
     RECT  2.16 5.805 50.49 6.075 ;
     RECT  2.16 6.345 50.49 6.615 ;
     RECT  2.16 6.885 50.49 7.155 ;
     RECT  2.16 7.425 50.49 7.695 ;
     RECT  2.16 7.965 50.49 8.235 ;
     RECT  2.16 8.505 50.49 8.775 ;
     RECT  2.16 9.045 50.49 9.315 ;
     RECT  2.16 9.585 50.49 9.855 ;
     RECT  2.16 10.125 50.49 10.395 ;
     RECT  2.16 10.665 50.49 10.935 ;
     RECT  2.16 11.205 50.49 11.475 ;
     RECT  2.16 11.745 50.49 12.015 ;
     RECT  2.16 12.285 50.49 12.555 ;
     RECT  2.16 12.825 50.49 13.095 ;
     RECT  2.16 13.365 50.49 13.635 ;
     RECT  2.16 13.905 50.49 14.175 ;
     RECT  2.16 14.445 50.49 14.715 ;
     RECT  2.16 14.985 50.49 15.255 ;
     RECT  2.16 15.525 50.49 15.795 ;
     RECT  2.16 16.065 50.49 16.335 ;
     RECT  2.16 16.605 50.49 16.875 ;
     RECT  2.16 17.145 50.49 17.415 ;
     RECT  2.16 17.685 50.49 17.955 ;
     RECT  2.16 18.225 50.49 18.495 ;
     RECT  2.16 18.765 50.49 19.035 ;
     RECT  2.16 19.305 50.49 19.575 ;
     RECT  2.16 19.845 50.49 20.115 ;
     RECT  2.16 20.385 50.49 20.655 ;
     RECT  2.16 20.925 50.49 21.195 ;
     RECT  2.16 21.465 50.49 21.735 ;
     RECT  2.16 22.005 50.49 22.275 ;
     RECT  2.16 22.545 50.49 22.815 ;
     RECT  2.16 23.085 50.49 23.355 ;
     RECT  2.16 23.625 50.49 23.895 ;
     RECT  2.16 24.165 50.49 24.435 ;
     RECT  2.16 24.705 50.49 24.975 ;
     RECT  2.16 25.245 50.49 25.515 ;
     RECT  2.16 25.785 50.49 26.055 ;
     RECT  2.16 26.325 50.49 26.595 ;
     RECT  2.16 26.865 50.49 27.135 ;
     RECT  2.16 27.405 50.49 27.675 ;
     RECT  2.16 27.945 50.49 28.215 ;
     RECT  2.16 28.485 50.49 28.755 ;
     RECT  2.16 29.025 50.49 29.295 ;
     RECT  2.16 29.565 50.49 29.835 ;
     RECT  2.16 30.105 50.49 30.375 ;
     RECT  2.16 30.645 50.49 30.915 ;
     RECT  2.16 31.185 50.49 31.455 ;
     RECT  2.16 31.725 50.49 31.995 ;
     RECT  2.16 32.265 50.49 32.535 ;
     RECT  2.16 32.805 50.49 33.075 ;
     RECT  2.16 33.345 50.49 33.615 ;
     RECT  2.16 33.885 50.49 34.155 ;
     RECT  2.16 34.425 50.49 34.695 ;
     RECT  2.16 34.965 50.49 35.235 ;
     RECT  2.16 35.505 50.49 35.775 ;
     RECT  2.16 36.045 50.49 36.315 ;
     RECT  2.16 36.585 50.49 36.855 ;
     RECT  2.16 37.125 50.49 37.395 ;
     RECT  2.16 37.665 50.49 37.935 ;
     RECT  2.16 38.205 50.49 38.475 ;
     RECT  2.16 38.745 50.49 39.015 ;
     RECT  2.16 39.285 50.49 39.555 ;
     RECT  2.16 39.825 50.49 40.095 ;
     RECT  2.16 40.365 50.49 40.635 ;
     RECT  2.16 40.905 50.49 41.175 ;
     RECT  2.16 41.445 50.49 41.715 ;
     RECT  2.16 41.985 50.49 42.255 ;
     RECT  2.16 42.525 50.49 42.795 ;
     RECT  2.16 43.065 50.49 43.335 ;
     RECT  2.16 43.605 50.49 43.875 ;
     RECT  2.16 44.145 50.49 44.415 ;
     RECT  2.16 44.685 50.49 44.955 ;
     RECT  2.16 45.225 50.49 45.495 ;
     RECT  2.16 45.765 50.49 46.035 ;
     RECT  2.16 46.305 50.49 46.575 ;
     RECT  2.16 46.845 50.49 47.115 ;
     RECT  2.16 47.385 50.49 47.655 ;
     RECT  2.16 47.925 50.49 48.195 ;
     RECT  2.16 48.465 50.49 48.735 ;
     RECT  2.16 49.005 50.49 49.275 ;
     RECT  2.16 49.545 50.49 49.815 ;
     RECT  2.16 50.085 50.49 50.355 ;
     RECT  2.16 50.625 50.49 50.895 ;
     RECT  2.16 51.165 50.49 51.435 ;
     RECT  2.16 51.705 50.49 51.975 ;
     RECT  2.16 52.245 50.49 52.515 ;
     RECT  2.16 52.785 50.49 53.055 ;
     RECT  2.16 53.325 50.49 53.595 ;
     RECT  2.16 53.865 50.49 54.135 ;
     RECT  2.16 54.405 50.49 54.675 ;
     RECT  2.16 54.945 50.49 55.215 ;
     RECT  2.16 55.485 50.49 55.755 ;
     RECT  2.16 56.025 50.49 56.295 ;
     RECT  2.16 56.565 50.49 56.835 ;
     RECT  2.16 57.105 50.49 57.375 ;
     RECT  2.16 57.645 50.49 57.915 ;
     RECT  2.16 58.185 50.49 58.455 ;
     RECT  2.16 58.725 50.49 58.995 ;
     RECT  2.16 59.265 50.49 59.535 ;
     RECT  2.16 59.805 50.49 60.075 ;
     RECT  2.16 60.345 50.49 60.615 ;
     RECT  2.16 60.885 50.49 61.155 ;
     RECT  2.16 61.425 50.49 61.695 ;
     RECT  2.16 61.965 50.49 62.235 ;
     RECT  2.16 62.505 50.49 62.775 ;
     RECT  2.16 63.045 50.49 63.315 ;
     RECT  2.16 63.585 50.49 63.855 ;
     RECT  2.16 64.125 50.49 64.395 ;
     RECT  2.16 64.665 50.49 64.935 ;
     RECT  2.16 65.205 50.49 65.475 ;
     RECT  2.16 65.745 50.49 66.015 ;
     RECT  2.16 66.285 50.49 66.555 ;
     RECT  2.16 66.825 50.49 67.095 ;
     RECT  2.16 67.365 50.49 67.635 ;
     RECT  2.16 67.905 50.49 68.175 ;
     RECT  2.16 68.445 50.49 68.715 ;
     RECT  2.16 68.985 50.49 69.255 ;
     RECT  2.16 69.525 50.49 69.795 ;
     RECT  2.16 70.065 50.49 70.335 ;
     RECT  2.16 70.605 50.49 70.875 ;
     RECT  2.16 71.145 50.49 71.415 ;
     RECT  2.16 71.685 50.49 71.955 ;
     RECT  2.16 72.225 50.49 72.495 ;
     RECT  2.16 72.765 50.49 73.035 ;
     RECT  2.16 73.305 50.49 73.575 ;
     RECT  2.16 73.845 50.49 74.115 ;
     RECT  2.16 74.385 50.49 74.655 ;
     RECT  2.16 74.925 50.49 75.195 ;
     RECT  2.16 75.465 50.49 75.735 ;
     RECT  2.16 76.005 50.49 76.275 ;
     RECT  2.16 76.545 50.49 76.815 ;
     RECT  2.16 77.085 50.49 77.355 ;
     RECT  2.16 77.625 50.49 77.895 ;
     RECT  2.16 78.165 50.49 78.435 ;
     RECT  2.16 78.705 50.49 78.975 ;
     RECT  2.16 79.245 50.49 79.515 ;
     RECT  2.16 79.785 50.49 80.055 ;
     RECT  2.16 80.325 50.49 80.595 ;
     RECT  2.16 80.865 50.49 81.135 ;
     RECT  2.16 81.405 50.49 81.675 ;
     RECT  2.16 81.945 50.49 82.215 ;
     RECT  2.16 82.485 50.49 82.755 ;
     RECT  2.16 83.025 50.49 83.295 ;
     RECT  2.16 83.565 50.49 83.835 ;
     RECT  2.16 84.105 50.49 84.375 ;
     RECT  2.16 84.645 50.49 84.915 ;
     RECT  2.16 85.185 50.49 85.455 ;
     RECT  2.16 85.725 50.49 85.995 ;
     RECT  2.16 86.265 50.49 86.535 ;
     RECT  2.16 86.805 50.49 87.075 ;
     RECT  2.16 87.345 50.49 87.615 ;
     RECT  2.16 87.885 50.49 88.155 ;
     RECT  2.16 88.425 50.49 88.695 ;
     RECT  2.16 88.965 50.49 89.235 ;
     RECT  2.16 89.505 50.49 89.775 ;
     RECT  2.16 90.045 50.49 90.315 ;
     RECT  2.16 90.585 50.49 90.855 ;
     RECT  2.16 91.125 50.49 91.395 ;
     RECT  2.16 91.665 50.49 91.935 ;
     RECT  2.16 92.205 50.49 92.475 ;
     RECT  2.16 92.745 50.49 93.015 ;
     RECT  2.16 93.285 50.49 93.555 ;
     RECT  2.16 93.825 50.49 94.095 ;
     RECT  2.16 94.365 50.49 94.635 ;
     RECT  2.16 94.905 50.49 95.175 ;
     RECT  2.16 95.445 50.49 95.715 ;
     RECT  2.16 95.985 50.49 96.255 ;
     RECT  2.16 96.525 50.49 96.795 ;
     RECT  2.16 97.065 50.49 97.335 ;
     RECT  2.16 97.605 50.49 97.875 ;
     RECT  2.16 98.145 50.49 98.415 ;
     RECT  2.16 98.685 50.49 98.955 ;
     RECT  2.16 99.225 50.49 99.495 ;
     RECT  2.16 99.765 50.49 100.035 ;
     RECT  2.16 100.305 50.49 100.575 ;
     RECT  2.16 100.845 50.49 101.115 ;
    LAYER RVTP ;
     RECT  2.16 2.295 50.49 2.565 ;
     RECT  2.16 2.835 50.49 3.105 ;
     RECT  2.16 3.375 50.49 3.645 ;
     RECT  2.16 3.915 50.49 4.185 ;
     RECT  2.16 4.455 50.49 4.725 ;
     RECT  2.16 4.995 50.49 5.265 ;
     RECT  2.16 5.535 50.49 5.805 ;
     RECT  2.16 6.075 50.49 6.345 ;
     RECT  2.16 6.615 50.49 6.885 ;
     RECT  2.16 7.155 50.49 7.425 ;
     RECT  2.16 7.695 50.49 7.965 ;
     RECT  2.16 8.235 50.49 8.505 ;
     RECT  2.16 8.775 50.49 9.045 ;
     RECT  2.16 9.315 50.49 9.585 ;
     RECT  2.16 9.855 50.49 10.125 ;
     RECT  2.16 10.395 50.49 10.665 ;
     RECT  2.16 10.935 50.49 11.205 ;
     RECT  2.16 11.475 50.49 11.745 ;
     RECT  2.16 12.015 50.49 12.285 ;
     RECT  2.16 12.555 50.49 12.825 ;
     RECT  2.16 13.095 50.49 13.365 ;
     RECT  2.16 13.635 50.49 13.905 ;
     RECT  2.16 14.175 50.49 14.445 ;
     RECT  2.16 14.715 50.49 14.985 ;
     RECT  2.16 15.255 50.49 15.525 ;
     RECT  2.16 15.795 50.49 16.065 ;
     RECT  2.16 16.335 50.49 16.605 ;
     RECT  2.16 16.875 50.49 17.145 ;
     RECT  2.16 17.415 50.49 17.685 ;
     RECT  2.16 17.955 50.49 18.225 ;
     RECT  2.16 18.495 50.49 18.765 ;
     RECT  2.16 19.035 50.49 19.305 ;
     RECT  2.16 19.575 50.49 19.845 ;
     RECT  2.16 20.115 50.49 20.385 ;
     RECT  2.16 20.655 50.49 20.925 ;
     RECT  2.16 21.195 50.49 21.465 ;
     RECT  2.16 21.735 50.49 22.005 ;
     RECT  2.16 22.275 50.49 22.545 ;
     RECT  2.16 22.815 50.49 23.085 ;
     RECT  2.16 23.355 50.49 23.625 ;
     RECT  2.16 23.895 50.49 24.165 ;
     RECT  2.16 24.435 50.49 24.705 ;
     RECT  2.16 24.975 50.49 25.245 ;
     RECT  2.16 25.515 50.49 25.785 ;
     RECT  2.16 26.055 50.49 26.325 ;
     RECT  2.16 26.595 50.49 26.865 ;
     RECT  2.16 27.135 50.49 27.405 ;
     RECT  2.16 27.675 50.49 27.945 ;
     RECT  2.16 28.215 50.49 28.485 ;
     RECT  2.16 28.755 50.49 29.025 ;
     RECT  2.16 29.295 50.49 29.565 ;
     RECT  2.16 29.835 50.49 30.105 ;
     RECT  2.16 30.375 50.49 30.645 ;
     RECT  2.16 30.915 50.49 31.185 ;
     RECT  2.16 31.455 50.49 31.725 ;
     RECT  2.16 31.995 50.49 32.265 ;
     RECT  2.16 32.535 50.49 32.805 ;
     RECT  2.16 33.075 50.49 33.345 ;
     RECT  2.16 33.615 50.49 33.885 ;
     RECT  2.16 34.155 50.49 34.425 ;
     RECT  2.16 34.695 50.49 34.965 ;
     RECT  2.16 35.235 50.49 35.505 ;
     RECT  2.16 35.775 50.49 36.045 ;
     RECT  2.16 36.315 50.49 36.585 ;
     RECT  2.16 36.855 50.49 37.125 ;
     RECT  2.16 37.395 50.49 37.665 ;
     RECT  2.16 37.935 50.49 38.205 ;
     RECT  2.16 38.475 50.49 38.745 ;
     RECT  2.16 39.015 50.49 39.285 ;
     RECT  2.16 39.555 50.49 39.825 ;
     RECT  2.16 40.095 50.49 40.365 ;
     RECT  2.16 40.635 50.49 40.905 ;
     RECT  2.16 41.175 50.49 41.445 ;
     RECT  2.16 41.715 50.49 41.985 ;
     RECT  2.16 42.255 50.49 42.525 ;
     RECT  2.16 42.795 50.49 43.065 ;
     RECT  2.16 43.335 50.49 43.605 ;
     RECT  2.16 43.875 50.49 44.145 ;
     RECT  2.16 44.415 50.49 44.685 ;
     RECT  2.16 44.955 50.49 45.225 ;
     RECT  2.16 45.495 50.49 45.765 ;
     RECT  2.16 46.035 50.49 46.305 ;
     RECT  2.16 46.575 50.49 46.845 ;
     RECT  2.16 47.115 50.49 47.385 ;
     RECT  2.16 47.655 50.49 47.925 ;
     RECT  2.16 48.195 50.49 48.465 ;
     RECT  2.16 48.735 50.49 49.005 ;
     RECT  2.16 49.275 50.49 49.545 ;
     RECT  2.16 49.815 50.49 50.085 ;
     RECT  2.16 50.355 50.49 50.625 ;
     RECT  2.16 50.895 50.49 51.165 ;
     RECT  2.16 51.435 50.49 51.705 ;
     RECT  2.16 51.975 50.49 52.245 ;
     RECT  2.16 52.515 50.49 52.785 ;
     RECT  2.16 53.055 50.49 53.325 ;
     RECT  2.16 53.595 50.49 53.865 ;
     RECT  2.16 54.135 50.49 54.405 ;
     RECT  2.16 54.675 50.49 54.945 ;
     RECT  2.16 55.215 50.49 55.485 ;
     RECT  2.16 55.755 50.49 56.025 ;
     RECT  2.16 56.295 50.49 56.565 ;
     RECT  2.16 56.835 50.49 57.105 ;
     RECT  2.16 57.375 50.49 57.645 ;
     RECT  2.16 57.915 50.49 58.185 ;
     RECT  2.16 58.455 50.49 58.725 ;
     RECT  2.16 58.995 50.49 59.265 ;
     RECT  2.16 59.535 50.49 59.805 ;
     RECT  2.16 60.075 50.49 60.345 ;
     RECT  2.16 60.615 50.49 60.885 ;
     RECT  2.16 61.155 50.49 61.425 ;
     RECT  2.16 61.695 50.49 61.965 ;
     RECT  2.16 62.235 50.49 62.505 ;
     RECT  2.16 62.775 50.49 63.045 ;
     RECT  2.16 63.315 50.49 63.585 ;
     RECT  2.16 63.855 50.49 64.125 ;
     RECT  2.16 64.395 50.49 64.665 ;
     RECT  2.16 64.935 50.49 65.205 ;
     RECT  2.16 65.475 50.49 65.745 ;
     RECT  2.16 66.015 50.49 66.285 ;
     RECT  2.16 66.555 50.49 66.825 ;
     RECT  2.16 67.095 50.49 67.365 ;
     RECT  2.16 67.635 50.49 67.905 ;
     RECT  2.16 68.175 50.49 68.445 ;
     RECT  2.16 68.715 50.49 68.985 ;
     RECT  2.16 69.255 50.49 69.525 ;
     RECT  2.16 69.795 50.49 70.065 ;
     RECT  2.16 70.335 50.49 70.605 ;
     RECT  2.16 70.875 50.49 71.145 ;
     RECT  2.16 71.415 50.49 71.685 ;
     RECT  2.16 71.955 50.49 72.225 ;
     RECT  2.16 72.495 50.49 72.765 ;
     RECT  2.16 73.035 50.49 73.305 ;
     RECT  2.16 73.575 50.49 73.845 ;
     RECT  2.16 74.115 50.49 74.385 ;
     RECT  2.16 74.655 50.49 74.925 ;
     RECT  2.16 75.195 50.49 75.465 ;
     RECT  2.16 75.735 50.49 76.005 ;
     RECT  2.16 76.275 50.49 76.545 ;
     RECT  2.16 76.815 50.49 77.085 ;
     RECT  2.16 77.355 50.49 77.625 ;
     RECT  2.16 77.895 50.49 78.165 ;
     RECT  2.16 78.435 50.49 78.705 ;
     RECT  2.16 78.975 50.49 79.245 ;
     RECT  2.16 79.515 50.49 79.785 ;
     RECT  2.16 80.055 50.49 80.325 ;
     RECT  2.16 80.595 50.49 80.865 ;
     RECT  2.16 81.135 50.49 81.405 ;
     RECT  2.16 81.675 50.49 81.945 ;
     RECT  2.16 82.215 50.49 82.485 ;
     RECT  2.16 82.755 50.49 83.025 ;
     RECT  2.16 83.295 50.49 83.565 ;
     RECT  2.16 83.835 50.49 84.105 ;
     RECT  2.16 84.375 50.49 84.645 ;
     RECT  2.16 84.915 50.49 85.185 ;
     RECT  2.16 85.455 50.49 85.725 ;
     RECT  2.16 85.995 50.49 86.265 ;
     RECT  2.16 86.535 50.49 86.805 ;
     RECT  2.16 87.075 50.49 87.345 ;
     RECT  2.16 87.615 50.49 87.885 ;
     RECT  2.16 88.155 50.49 88.425 ;
     RECT  2.16 88.695 50.49 88.965 ;
     RECT  2.16 89.235 50.49 89.505 ;
     RECT  2.16 89.775 50.49 90.045 ;
     RECT  2.16 90.315 50.49 90.585 ;
     RECT  2.16 90.855 50.49 91.125 ;
     RECT  2.16 91.395 50.49 91.665 ;
     RECT  2.16 91.935 50.49 92.205 ;
     RECT  2.16 92.475 50.49 92.745 ;
     RECT  2.16 93.015 50.49 93.285 ;
     RECT  2.16 93.555 50.49 93.825 ;
     RECT  2.16 94.095 50.49 94.365 ;
     RECT  2.16 94.635 50.49 94.905 ;
     RECT  2.16 95.175 50.49 95.445 ;
     RECT  2.16 95.715 50.49 95.985 ;
     RECT  2.16 96.255 50.49 96.525 ;
     RECT  2.16 96.795 50.49 97.065 ;
     RECT  2.16 97.335 50.49 97.605 ;
     RECT  2.16 97.875 50.49 98.145 ;
     RECT  2.16 98.415 50.49 98.685 ;
     RECT  2.16 98.955 50.49 99.225 ;
     RECT  2.16 99.495 50.49 99.765 ;
     RECT  2.16 100.035 50.49 100.305 ;
     RECT  2.16 100.575 50.49 100.845 ;
     RECT  2.16 101.115 50.49 101.25 ;
    LAYER M1 ;
     RECT  2.16 2.151 50.49 101.259 ;
    LAYER M2 ;
     RECT  0.031 25.254 0.103 25.272 ;
     RECT  0.031 27.486 0.103 27.504 ;
     RECT  0.103 27.306 0.139 27.504 ;
     RECT  0.103 34.902 0.139 35.766 ;
     RECT  0.103 51.408 0.139 53.199 ;
     RECT  0.103 63.396 0.139 64.044 ;
     RECT  0.103 70.236 0.139 70.254 ;
     RECT  0.103 74.511 0.139 75.024 ;
     RECT  0.139 26.64 0.175 27.504 ;
     RECT  0.139 28.386 0.175 28.404 ;
     RECT  0.103 29.466 0.175 30.564 ;
     RECT  0.139 63.396 0.175 64.116 ;
     RECT  0.139 64.872 0.175 64.89 ;
     RECT  0.103 66.096 0.175 67.014 ;
     RECT  0.103 69.426 0.175 69.444 ;
     RECT  0.139 70.236 0.175 70.632 ;
     RECT  0.103 73.512 0.175 73.53 ;
     RECT  0.103 38.106 0.203 38.736 ;
     RECT  0.103 41.526 0.203 41.544 ;
     RECT  0.103 42.732 0.203 43.362 ;
     RECT  0.103 44.118 0.203 44.559 ;
     RECT  0.103 46.746 0.203 47.34 ;
     RECT  0.103 48.438 0.203 49.032 ;
     RECT  0.103 50.4 0.203 50.418 ;
     RECT  0.139 51.408 0.203 53.316 ;
     RECT  0.103 55.026 0.203 56.169 ;
     RECT  0.103 57.312 0.203 57.33 ;
     RECT  0.103 60.048 0.203 60.642 ;
     RECT  0.103 61.551 0.203 62.064 ;
     RECT  0.175 26.64 0.211 28.404 ;
     RECT  0.103 68.112 0.211 68.364 ;
     RECT  0.175 69.426 0.211 70.632 ;
     RECT  0.139 71.964 0.211 72.054 ;
     RECT  0.139 34.902 0.239 35.874 ;
     RECT  0.203 55.26 0.239 55.278 ;
     RECT  0.211 69.426 0.239 72.054 ;
     RECT  0.175 73.476 0.239 73.53 ;
     RECT  0.139 74.511 0.239 75.222 ;
     RECT  0.211 26.496 0.247 28.404 ;
     RECT  0.175 29.376 0.247 30.834 ;
     RECT  0.175 63.396 0.247 64.89 ;
     RECT  0.175 65.646 0.247 67.014 ;
     RECT  0.103 33.552 0.275 33.57 ;
     RECT  0.239 34.902 0.347 35.226 ;
     RECT  0.203 52.056 0.347 52.2 ;
     RECT  0.347 34.902 0.383 35.028 ;
     RECT  0.211 67.95 0.383 68.364 ;
     RECT  0.239 69.426 0.383 71.982 ;
     RECT  0.383 68.112 0.419 68.364 ;
     RECT  0.347 52.182 0.491 52.2 ;
     RECT  0.419 68.22 0.499 68.364 ;
     RECT  0.103 25.254 1.147 25.704 ;
     RECT  0.535 34.506 1.147 34.524 ;
     RECT  0.383 69.426 1.147 71.244 ;
     RECT  0.239 73.476 1.147 73.494 ;
     RECT  1.147 24.606 1.183 25.704 ;
     RECT  1.147 34.398 1.183 34.524 ;
     RECT  1.183 34.398 1.399 35.154 ;
     RECT  1.327 3.186 1.507 3.204 ;
     RECT  1.147 69.426 1.687 71.946 ;
     RECT  1.147 72.936 1.687 73.494 ;
     RECT  0.139 32.436 1.723 32.454 ;
     RECT  1.399 34.398 1.723 35.334 ;
     RECT  1.723 4.536 1.759 4.554 ;
     RECT  1.723 32.166 1.759 32.454 ;
     RECT  1.723 77.976 1.759 77.994 ;
     RECT  1.759 32.166 1.795 32.832 ;
     RECT  1.723 33.786 1.795 35.334 ;
     RECT  1.759 77.976 1.795 78.084 ;
     RECT  1.399 78.948 1.795 78.966 ;
     RECT  1.795 77.976 1.831 78.966 ;
     RECT  1.831 77.796 1.867 78.966 ;
     RECT  0.247 36.486 1.975 36.504 ;
     RECT  1.903 6.084 2.083 6.102 ;
     RECT  0.247 26.496 2.083 30.834 ;
     RECT  1.795 32.166 2.083 35.334 ;
     RECT  0.103 58.626 2.083 58.644 ;
     RECT  1.183 24.336 2.119 25.704 ;
     RECT  2.083 26.496 2.119 31.104 ;
     RECT  2.083 32.166 2.119 35.604 ;
     RECT  0.239 74.556 2.155 75.222 ;
     RECT  1.867 77.796 2.155 79.164 ;
     RECT  1.507 3.186 2.16 3.294 ;
     RECT  1.759 4.464 2.16 4.554 ;
     RECT  2.083 5.886 2.16 6.102 ;
     RECT  2.155 22.716 2.16 22.734 ;
     RECT  2.119 24.336 2.16 31.104 ;
     RECT  2.119 31.896 2.16 35.604 ;
     RECT  1.975 36.396 2.16 36.504 ;
     RECT  0.203 44.496 2.16 44.514 ;
     RECT  0.203 53.298 2.16 53.316 ;
     RECT  2.083 58.266 2.16 58.644 ;
     RECT  0.203 61.74 2.16 62.064 ;
     RECT  0.247 63.396 2.16 67.014 ;
     RECT  0.499 68.22 2.16 68.544 ;
     RECT  1.687 69.426 2.16 73.494 ;
     RECT  2.155 74.322 2.16 75.222 ;
     RECT  2.119 76.356 2.16 76.374 ;
     RECT  2.155 77.526 2.16 79.164 ;
     RECT  1.975 80.226 2.16 80.244 ;
     RECT  1.687 88.47 2.16 88.92 ;
     RECT  2.16 2.151 2.587 101.259 ;
     RECT  2.587 2.106 2.803 101.259 ;
     RECT  2.803 2.034 2.947 101.259 ;
     RECT  2.947 1.962 4.559 101.259 ;
     RECT  4.559 2.151 10.255 101.259 ;
     RECT  10.255 2.106 10.975 101.259 ;
     RECT  10.975 2.034 11.687 101.259 ;
     RECT  11.687 2.151 16.375 101.259 ;
     RECT  16.375 2.106 17.879 101.259 ;
     RECT  17.879 2.151 18.787 101.259 ;
     RECT  18.787 2.106 19.247 101.259 ;
     RECT  19.975 1.152 20.075 1.17 ;
     RECT  19.247 2.151 23.179 101.259 ;
     RECT  23.179 2.106 23.719 101.259 ;
     RECT  23.719 2.034 24.367 101.259 ;
     RECT  24.367 1.962 25.511 101.259 ;
     RECT  25.511 2.151 50.49 101.259 ;
     RECT  50.49 19.476 50.495 22.068 ;
     RECT  50.49 41.616 50.495 45.018 ;
     RECT  50.495 19.746 50.531 22.068 ;
     RECT  50.495 42.3 50.531 45.018 ;
     RECT  50.531 20.556 50.567 21.798 ;
     RECT  50.531 42.3 50.567 43.326 ;
     RECT  50.567 20.826 50.603 21.798 ;
     RECT  50.567 42.426 50.603 43.326 ;
     RECT  50.603 42.426 50.639 42.444 ;
     RECT  50.531 45 50.639 45.018 ;
     RECT  50.531 19.746 50.675 19.764 ;
     RECT  50.49 40.572 50.675 40.59 ;
     RECT  50.49 71.19 50.675 74.646 ;
     RECT  50.603 43.308 50.711 43.326 ;
     RECT  50.603 20.826 50.747 21.654 ;
     RECT  50.675 72.54 50.783 74.646 ;
     RECT  50.747 20.826 50.819 21.384 ;
     RECT  50.819 20.826 50.855 20.844 ;
     RECT  50.675 71.19 50.891 71.748 ;
     RECT  50.891 71.19 50.963 71.208 ;
     RECT  50.783 72.774 51.071 74.646 ;
     RECT  51.071 72.846 51.251 74.646 ;
     RECT  51.251 73.278 51.467 74.646 ;
     RECT  51.467 73.278 51.539 74.448 ;
     RECT  51.539 73.278 51.647 73.296 ;
     RECT  51.539 74.052 51.827 74.448 ;
     RECT  51.827 74.052 51.935 74.07 ;
    LAYER M3 ;
     RECT  5.724 0.091 5.742 0.139 ;
     RECT  6.984 0.091 7.002 0.139 ;
     RECT  14.148 0.091 15.174 0.139 ;
     RECT  24.732 0.091 29.106 0.139 ;
     RECT  41.148 0.091 41.166 0.139 ;
     RECT  45.288 0.091 45.45 0.139 ;
     RECT  46.44 0.091 46.458 0.139 ;
     RECT  30.888 0.091 30.906 0.187 ;
     RECT  31.644 0.091 31.662 0.187 ;
     RECT  20.412 0.091 23.886 0.379 ;
     RECT  19.98 0.379 23.886 0.427 ;
     RECT  10.512 0.091 12.87 0.475 ;
     RECT  19.512 0.427 23.886 0.475 ;
     RECT  4.392 0.091 4.59 0.523 ;
     RECT  5.724 0.139 5.85 0.523 ;
     RECT  9.18 0.091 9.198 0.523 ;
     RECT  10.332 0.475 12.87 0.523 ;
     RECT  13.716 0.139 15.174 0.523 ;
     RECT  45.18 0.139 45.45 0.523 ;
     RECT  3.168 0.091 3.186 0.571 ;
     RECT  4.212 0.523 4.59 0.571 ;
     RECT  5.508 0.523 5.85 0.571 ;
     RECT  6.984 0.139 7.11 0.571 ;
     RECT  9.18 0.523 15.174 0.571 ;
     RECT  15.912 0.091 15.93 0.571 ;
     RECT  17.496 0.091 17.514 0.571 ;
     RECT  19.44 0.475 23.886 0.571 ;
     RECT  24.732 0.139 29.214 0.571 ;
     RECT  30.888 0.187 31.662 0.571 ;
     RECT  32.796 0.091 38.358 0.571 ;
     RECT  41.148 0.139 41.274 0.571 ;
     RECT  42.228 0.091 42.534 0.571 ;
     RECT  50.472 0.091 50.67 0.571 ;
     RECT  2.88 0.571 3.186 0.619 ;
     RECT  19.44 0.571 23.994 0.619 ;
     RECT  24.732 0.571 38.358 0.619 ;
     RECT  39.96 0.523 39.978 0.701 ;
     RECT  49.86 0.571 50.67 0.955 ;
     RECT  49.86 0.955 50.742 1.003 ;
     RECT  41.148 0.571 42.534 1.051 ;
     RECT  44.352 0.571 44.37 1.051 ;
     RECT  45.108 0.523 45.45 1.051 ;
     RECT  47.412 0.091 47.43 1.051 ;
     RECT  48.168 0.091 48.762 1.051 ;
     RECT  2.88 0.619 3.438 1.147 ;
     RECT  6.696 0.571 7.11 1.147 ;
     RECT  9.18 0.571 15.93 1.147 ;
     RECT  40.176 1.099 40.194 1.147 ;
     RECT  41.148 1.051 43.254 1.147 ;
     RECT  44.352 1.051 45.45 1.147 ;
     RECT  46.44 0.139 46.566 1.147 ;
     RECT  47.412 1.051 48.762 1.147 ;
     RECT  2.556 1.147 3.438 1.723 ;
     RECT  4.212 0.571 5.85 1.723 ;
     RECT  6.696 1.147 7.326 1.723 ;
     RECT  8.136 1.147 16.434 1.723 ;
     RECT  17.388 0.571 17.514 1.723 ;
     RECT  40.176 1.147 43.29 1.723 ;
     RECT  6.696 1.723 16.434 1.771 ;
     RECT  17.388 1.723 18.414 1.771 ;
     RECT  19.44 0.619 38.358 1.771 ;
     RECT  2.376 1.723 3.438 1.819 ;
     RECT  4.176 1.723 5.85 1.819 ;
     RECT  39.816 1.723 43.29 2.251 ;
     RECT  39.348 2.251 43.29 2.299 ;
     RECT  44.352 1.147 48.978 2.299 ;
     RECT  49.86 1.003 50.814 2.299 ;
     RECT  39.348 2.299 43.398 2.347 ;
     RECT  2.376 1.819 5.85 2.605 ;
     RECT  2.34 2.605 5.85 2.767 ;
     RECT  2.304 2.767 5.85 2.875 ;
     RECT  39.348 2.347 43.578 2.875 ;
     RECT  1.728 2.875 5.85 2.923 ;
     RECT  1.332 2.923 5.85 3.181 ;
     RECT  6.696 1.771 38.358 3.181 ;
     RECT  1.332 3.181 38.358 3.209 ;
     RECT  1.512 3.209 38.358 3.299 ;
     RECT  1.728 3.299 38.358 3.403 ;
     RECT  39.24 2.875 43.578 3.403 ;
     RECT  1.728 3.403 43.578 3.569 ;
     RECT  1.728 3.569 16.29 4.559 ;
     RECT  17.136 3.569 43.578 4.919 ;
     RECT  44.352 2.299 50.814 5.083 ;
     RECT  17.244 4.919 43.578 5.999 ;
     RECT  1.908 4.559 16.29 6.107 ;
     RECT  17.964 5.999 43.578 6.179 ;
     RECT  2.304 6.107 16.29 6.269 ;
     RECT  17.172 6.115 17.19 6.449 ;
     RECT  2.304 6.269 15.39 7.079 ;
     RECT  16.272 6.269 16.29 7.079 ;
     RECT  2.415 7.079 15.39 7.349 ;
     RECT  16.524 7.195 16.542 7.727 ;
     RECT  2.415 7.349 15.102 7.889 ;
     RECT  2.415 7.889 14.958 8.699 ;
     RECT  2.415 8.699 14.886 9.779 ;
     RECT  18.144 6.179 43.578 13.099 ;
     RECT  44.352 5.083 50.85 13.099 ;
     RECT  18.144 13.099 50.85 18.811 ;
     RECT  2.415 9.779 14.706 18.931 ;
     RECT  18.072 18.811 50.85 18.995 ;
     RECT  18.144 18.995 50.85 20.849 ;
     RECT  18.144 20.849 50.814 21.389 ;
     RECT  18.144 21.389 50.742 21.659 ;
     RECT  2.232 18.931 14.706 22.711 ;
     RECT  1.188 24.331 1.206 24.601 ;
     RECT  1.152 24.601 1.206 24.871 ;
     RECT  0.036 25.249 0.054 25.681 ;
     RECT  15.624 26.011 15.642 26.285 ;
     RECT  2.16 22.711 14.706 26.329 ;
     RECT  18.144 21.659 50.634 26.365 ;
     RECT  0.036 25.681 0.126 26.491 ;
     RECT  16.848 25.249 16.866 26.563 ;
     RECT  18 26.365 50.634 26.563 ;
     RECT  1.152 24.871 1.242 26.761 ;
     RECT  0.036 26.491 0.234 27.067 ;
     RECT  0.036 27.067 0.306 27.103 ;
     RECT  1.152 26.761 1.278 27.103 ;
     RECT  0.036 27.103 1.278 27.509 ;
     RECT  2.124 26.329 14.706 27.821 ;
     RECT  0.108 27.509 1.278 28.397 ;
     RECT  0.144 28.397 1.278 28.973 ;
     RECT  2.16 27.821 14.706 29.065 ;
     RECT  0.144 28.973 1.17 29.261 ;
     RECT  0.144 29.261 0.342 29.357 ;
     RECT  1.152 29.261 1.17 29.357 ;
     RECT  0.144 29.357 0.27 29.461 ;
     RECT  2.124 29.065 14.706 29.605 ;
     RECT  2.124 29.605 14.814 30.475 ;
     RECT  0.108 29.461 0.27 30.605 ;
     RECT  0.108 30.605 0.198 30.797 ;
     RECT  2.088 30.475 14.814 30.859 ;
     RECT  0.144 30.797 0.198 31.627 ;
     RECT  0.144 31.627 0.558 31.709 ;
     RECT  1.728 30.859 14.814 32.107 ;
     RECT  0.54 31.709 0.558 32.299 ;
     RECT  1.404 32.107 14.814 32.299 ;
     RECT  0.54 32.299 14.814 32.431 ;
     RECT  0.144 32.431 14.814 32.587 ;
     RECT  16.848 26.563 50.634 33.307 ;
     RECT  0.108 32.587 14.814 33.547 ;
     RECT  0.108 33.547 15.426 33.575 ;
     RECT  0.18 33.575 15.426 33.629 ;
     RECT  0.216 33.629 15.426 33.719 ;
     RECT  16.524 33.307 50.634 33.961 ;
     RECT  15.876 33.961 50.634 34.187 ;
     RECT  15.876 34.187 16.038 34.445 ;
     RECT  0.216 33.719 14.814 34.507 ;
     RECT  0.144 34.507 14.814 34.529 ;
     RECT  16.02 34.445 16.038 34.619 ;
     RECT  0.144 34.529 0.378 34.888 ;
     RECT  1.188 34.529 14.814 35.159 ;
     RECT  0.108 34.888 0.378 35.213 ;
     RECT  1.404 35.159 14.814 35.339 ;
     RECT  0.108 35.213 0.342 35.789 ;
     RECT  0.144 35.789 0.342 35.888 ;
     RECT  0.216 35.888 0.342 36.269 ;
     RECT  1.98 35.339 14.814 36.283 ;
     RECT  1.98 36.283 14.85 36.419 ;
     RECT  2.124 36.419 14.85 36.481 ;
     RECT  0.216 36.269 0.27 36.509 ;
     RECT  2.124 36.481 15.426 36.517 ;
     RECT  2.124 36.517 15.966 36.553 ;
     RECT  16.848 34.187 50.634 36.553 ;
     RECT  0.144 36.715 0.162 36.893 ;
     RECT  2.124 36.553 50.634 37.085 ;
     RECT  2.124 37.085 15.678 37.589 ;
     RECT  15.66 37.589 15.678 37.625 ;
     RECT  2.124 37.589 14.85 37.709 ;
     RECT  16.524 37.085 50.634 37.867 ;
     RECT  0.144 37.915 0.162 38.092 ;
     RECT  16.488 37.867 50.634 38.155 ;
     RECT  16.2 38.155 50.634 38.579 ;
     RECT  16.74 38.579 50.634 38.705 ;
     RECT  0.108 38.092 0.198 38.861 ;
     RECT  2.124 37.709 14.814 38.923 ;
     RECT  16.848 38.705 50.634 39.011 ;
     RECT  2.124 38.923 14.958 39.053 ;
     RECT  0.144 38.861 0.198 39.403 ;
     RECT  0.144 39.403 0.342 39.533 ;
     RECT  0.144 39.533 0.234 40.349 ;
     RECT  28.152 39.011 50.634 40.567 ;
     RECT  16.848 39.011 27.414 40.597 ;
     RECT  28.152 40.567 50.67 40.597 ;
     RECT  0.144 40.349 0.162 41.179 ;
     RECT  0.144 41.179 0.234 41.453 ;
     RECT  0.144 41.453 0.198 41.521 ;
     RECT  0.108 41.521 0.198 41.789 ;
     RECT  0.108 41.789 0.126 41.837 ;
     RECT  2.124 39.053 14.814 42.331 ;
     RECT  0.144 42.523 0.162 42.727 ;
     RECT  2.124 42.331 14.85 42.755 ;
     RECT  2.124 42.755 14.814 42.791 ;
     RECT  16.848 40.597 50.67 42.811 ;
     RECT  16.524 42.811 50.67 43.061 ;
     RECT  16.848 43.061 50.67 43.303 ;
     RECT  0.108 42.727 0.198 44.765 ;
     RECT  0.108 44.765 0.126 44.813 ;
     RECT  16.848 43.303 50.706 45.959 ;
     RECT  2.124 42.791 14.742 45.967 ;
     RECT  16.848 45.959 41.598 46.157 ;
     RECT  16.848 46.157 41.562 46.229 ;
     RECT  42.408 45.959 50.706 46.409 ;
     RECT  42.552 46.409 50.706 46.499 ;
     RECT  2.124 45.967 14.814 46.507 ;
     RECT  43.056 46.499 50.706 46.535 ;
     RECT  2.124 46.507 14.886 46.607 ;
     RECT  0.144 46.555 0.162 46.732 ;
     RECT  2.124 46.607 14.814 46.769 ;
     RECT  43.128 46.535 50.706 46.769 ;
     RECT  0.108 46.732 0.198 47.501 ;
     RECT  2.124 46.769 14.706 47.587 ;
     RECT  0.144 47.501 0.198 47.707 ;
     RECT  0.144 47.707 0.234 47.885 ;
     RECT  0.144 47.885 0.198 48.433 ;
     RECT  0.108 48.433 0.198 49.133 ;
     RECT  1.116 49.003 1.134 49.181 ;
     RECT  0.18 49.133 0.198 49.579 ;
     RECT  15.732 49.585 15.75 49.775 ;
     RECT  0.18 49.579 0.378 49.805 ;
     RECT  2.124 47.587 14.814 49.819 ;
     RECT  15.66 49.783 15.678 49.819 ;
     RECT  0.18 49.805 0.27 49.867 ;
     RECT  0.108 49.867 0.27 49.901 ;
     RECT  2.124 49.819 15.678 50.009 ;
     RECT  0.108 49.901 0.198 50.423 ;
     RECT  2.124 50.009 15.534 50.791 ;
     RECT  2.124 50.791 15.858 50.863 ;
     RECT  16.848 46.229 41.274 50.863 ;
     RECT  2.124 50.863 41.274 51.089 ;
     RECT  2.124 51.089 15.966 51.149 ;
     RECT  2.124 51.149 15.93 51.161 ;
     RECT  0.144 50.423 0.162 51.163 ;
     RECT  0.144 51.163 0.198 51.388 ;
     RECT  16.848 51.089 41.274 51.395 ;
     RECT  38.124 51.395 41.274 51.629 ;
     RECT  0.108 51.388 0.198 51.883 ;
     RECT  16.848 51.395 37.386 51.899 ;
     RECT  0.108 51.883 0.342 52.075 ;
     RECT  16.848 51.899 37.314 52.171 ;
     RECT  0.108 52.075 0.414 52.177 ;
     RECT  2.124 51.161 15.606 52.205 ;
     RECT  16.488 52.171 37.314 52.205 ;
     RECT  16.488 52.205 37.098 52.219 ;
     RECT  0.108 52.177 0.486 52.301 ;
     RECT  2.124 52.205 15.21 52.313 ;
     RECT  16.092 52.219 37.098 52.475 ;
     RECT  16.092 52.475 36.954 52.709 ;
     RECT  16.488 52.709 36.27 52.853 ;
     RECT  36.036 52.853 36.27 52.979 ;
     RECT  16.488 52.853 35.298 53.015 ;
     RECT  36.036 52.979 36.054 53.249 ;
     RECT  0.108 52.301 0.198 53.405 ;
     RECT  0.108 53.405 0.126 53.453 ;
     RECT  2.124 52.313 14.958 53.563 ;
     RECT  2.124 53.563 15.606 53.599 ;
     RECT  16.488 53.015 35.226 53.599 ;
     RECT  2.124 53.599 35.226 54.059 ;
     RECT  0.144 54.139 0.162 54.715 ;
     RECT  0.144 54.715 0.198 54.763 ;
     RECT  2.124 54.059 35.097 54.977 ;
     RECT  2.124 54.977 33.966 55.139 ;
     RECT  0.108 54.763 0.198 55.255 ;
     RECT  2.124 55.139 33.39 55.409 ;
     RECT  2.124 55.409 33.21 55.445 ;
     RECT  0.108 55.255 0.234 55.709 ;
     RECT  2.124 55.445 33.03 55.949 ;
     RECT  0.108 55.709 0.198 56.381 ;
     RECT  0.108 56.381 0.162 56.429 ;
     RECT  0.144 56.429 0.162 57.292 ;
     RECT  0.108 57.292 0.198 57.437 ;
     RECT  0.108 57.437 0.126 57.485 ;
     RECT  2.124 55.949 32.958 57.739 ;
     RECT  2.088 57.739 32.958 58.289 ;
     RECT  0.108 58.603 0.126 58.649 ;
     RECT  2.124 58.289 32.958 58.721 ;
     RECT  0.144 59.083 0.162 59.261 ;
     RECT  0.18 59.803 0.198 60.028 ;
     RECT  0.108 60.028 0.198 61.757 ;
     RECT  0.108 61.757 0.162 61.763 ;
     RECT  0.108 61.763 0.126 62.093 ;
     RECT  0.144 62.491 0.162 62.957 ;
     RECT  2.124 58.721 32.922 63.625 ;
     RECT  0.108 63.391 0.126 63.979 ;
     RECT  0.108 63.979 0.342 64.093 ;
     RECT  2.124 63.625 33.606 64.165 ;
     RECT  0.108 64.093 0.378 64.205 ;
     RECT  2.124 64.165 33.678 64.705 ;
     RECT  34.815 54.977 35.097 64.705 ;
     RECT  0.108 64.205 0.306 65.357 ;
     RECT  0.144 65.357 0.306 65.371 ;
     RECT  0.144 65.371 0.378 66.055 ;
     RECT  0.144 66.055 0.558 66.091 ;
     RECT  2.124 64.705 35.097 66.325 ;
     RECT  35.892 65.983 35.91 66.325 ;
     RECT  2.124 66.325 35.91 66.523 ;
     RECT  0.108 66.091 0.558 66.701 ;
     RECT  43.164 46.769 50.706 66.721 ;
     RECT  2.124 66.523 35.982 66.793 ;
     RECT  2.124 66.793 36.09 67.027 ;
     RECT  2.124 67.027 36.126 67.099 ;
     RECT  2.124 67.099 36.486 67.171 ;
     RECT  0.108 66.701 0.342 67.945 ;
     RECT  0.108 67.945 0.378 68.107 ;
     RECT  0.108 68.107 0.414 68.215 ;
     RECT  38.304 51.629 41.274 68.395 ;
     RECT  38.304 68.395 41.31 68.413 ;
     RECT  0.108 68.215 0.558 68.429 ;
     RECT  38.304 68.413 41.418 68.549 ;
     RECT  38.304 68.549 38.79 68.909 ;
     RECT  39.708 68.549 41.418 68.957 ;
     RECT  39.852 68.957 41.418 68.971 ;
     RECT  0.144 68.429 0.558 69.197 ;
     RECT  0.144 69.197 0.198 69.421 ;
     RECT  39.852 68.971 42.066 69.533 ;
     RECT  41.472 69.533 42.066 69.547 ;
     RECT  43.092 66.721 50.706 69.547 ;
     RECT  1.152 69.547 1.17 69.643 ;
     RECT  2.124 67.171 36.558 69.643 ;
     RECT  1.152 69.643 36.558 69.821 ;
     RECT  0.108 69.421 0.198 69.965 ;
     RECT  38.304 68.909 38.466 69.989 ;
     RECT  41.472 69.547 50.706 70.025 ;
     RECT  41.508 70.025 50.706 70.109 ;
     RECT  38.448 69.989 38.466 70.259 ;
     RECT  42.012 70.109 50.706 70.589 ;
     RECT  42.048 70.589 50.706 70.685 ;
     RECT  0.108 69.965 0.162 70.733 ;
     RECT  42.372 70.685 50.706 70.829 ;
     RECT  42.588 70.829 50.706 71.185 ;
     RECT  0.144 70.733 0.162 71.221 ;
     RECT  1.224 69.821 36.558 71.611 ;
     RECT  0.144 71.221 0.234 71.851 ;
     RECT  0.144 71.851 0.342 71.959 ;
     RECT  0.144 71.959 0.378 72.077 ;
     RECT  1.152 71.611 36.558 72.125 ;
     RECT  0.216 72.077 0.378 72.173 ;
     RECT  0.216 72.173 0.342 72.749 ;
     RECT  42.588 71.185 50.958 72.769 ;
     RECT  42.588 72.769 51.066 72.841 ;
     RECT  1.368 72.125 36.558 72.931 ;
     RECT  0.216 72.749 0.234 72.955 ;
     RECT  42.588 72.841 51.246 73.273 ;
     RECT  0.144 72.955 0.234 73.507 ;
     RECT  1.152 72.931 36.558 73.997 ;
     RECT  42.588 73.273 51.642 74.047 ;
     RECT  0.108 73.507 0.234 74.534 ;
     RECT  1.26 73.997 36.558 74.821 ;
     RECT  1.152 74.821 36.558 75.029 ;
     RECT  1.692 75.029 36.558 75.053 ;
     RECT  0.108 74.534 0.198 75.245 ;
     RECT  0.108 75.245 0.162 75.629 ;
     RECT  0.144 75.629 0.162 75.725 ;
     RECT  2.124 75.053 36.558 76.075 ;
     RECT  38.736 73.849 38.754 76.207 ;
     RECT  39.852 69.533 40.698 76.207 ;
     RECT  1.728 76.075 36.558 76.843 ;
     RECT  1.404 76.843 36.558 76.925 ;
     RECT  1.404 76.925 28.35 77.009 ;
     RECT  1.404 77.009 27.378 77.279 ;
     RECT  29.16 76.925 36.558 77.279 ;
     RECT  38.736 76.207 40.698 77.279 ;
     RECT  1.404 77.279 27.306 77.315 ;
     RECT  28.224 77.009 28.35 77.351 ;
     RECT  28.224 77.351 28.314 77.863 ;
     RECT  29.304 77.279 36.558 77.935 ;
     RECT  1.404 77.315 27.198 78.971 ;
     RECT  1.872 78.971 27.198 79.169 ;
     RECT  1.98 79.169 27.198 79.979 ;
     RECT  1.98 79.979 26.658 80.249 ;
     RECT  2.232 80.249 26.658 80.429 ;
     RECT  2.232 80.429 25.11 80.519 ;
     RECT  26.172 80.429 26.478 80.573 ;
     RECT  5.976 80.519 25.11 80.957 ;
     RECT  5.976 80.957 24.498 81.059 ;
     RECT  26.172 80.573 26.19 81.485 ;
     RECT  2.232 80.519 5.166 81.599 ;
     RECT  6.336 81.059 24.498 81.725 ;
     RECT  6.336 81.725 14.85 82.061 ;
     RECT  29.304 77.935 36.774 82.561 ;
     RECT  29.268 82.561 36.774 82.679 ;
     RECT  15.588 81.725 24.498 82.685 ;
     RECT  15.876 82.685 24.498 83.789 ;
     RECT  15.876 83.789 21.078 83.795 ;
     RECT  18.18 83.795 21.078 84.209 ;
     RECT  15.876 83.795 17.262 84.365 ;
     RECT  18.252 84.209 21.078 84.407 ;
     RECT  18.468 84.407 21.078 84.569 ;
     RECT  18.504 84.569 21.078 84.839 ;
     RECT  18.504 84.839 20.826 84.941 ;
     RECT  18.504 84.941 20.754 84.989 ;
     RECT  22.248 83.789 24.498 85.613 ;
     RECT  18.615 84.989 20.754 85.649 ;
     RECT  18.615 85.649 20.61 85.805 ;
     RECT  18.615 85.805 20.466 85.829 ;
     RECT  20.016 85.829 20.466 86.045 ;
     RECT  23.04 85.613 23.058 86.045 ;
     RECT  20.448 86.045 20.466 86.093 ;
     RECT  6.336 82.061 14.202 86.909 ;
     RECT  6.372 86.909 14.202 88.079 ;
     RECT  18.615 85.829 19.278 88.349 ;
     RECT  2.232 81.599 4.878 88.465 ;
     RECT  1.692 88.465 4.878 88.931 ;
     RECT  7.632 88.079 14.202 89.159 ;
     RECT  29.304 82.679 36.774 89.815 ;
     RECT  29.304 89.815 37.314 89.851 ;
     RECT  38.52 77.395 38.538 89.851 ;
     RECT  28.188 77.863 28.314 89.879 ;
     RECT  29.304 89.851 38.538 89.879 ;
     RECT  2.268 88.931 4.878 90.013 ;
     RECT  42.588 74.047 51.93 90.077 ;
     RECT  2.232 90.013 4.878 90.173 ;
     RECT  33.336 89.879 38.538 90.283 ;
     RECT  39.348 77.279 40.698 90.283 ;
     RECT  28.188 89.879 28.242 90.347 ;
     RECT  23.94 85.613 24.498 90.545 ;
     RECT  29.304 89.879 32.526 90.589 ;
     RECT  29.268 90.589 32.526 90.605 ;
     RECT  2.304 90.173 4.878 90.895 ;
     RECT  6.372 88.079 6.858 91.049 ;
     RECT  6.372 91.049 6.822 91.093 ;
     RECT  6.156 91.093 6.822 91.133 ;
     RECT  28.188 90.347 28.206 91.157 ;
     RECT  29.268 90.605 31.194 91.769 ;
     RECT  2.232 90.895 4.878 91.901 ;
     RECT  17.244 84.365 17.262 92.911 ;
     RECT  22.248 85.613 22.266 92.911 ;
     RECT  17.244 92.911 17.334 92.923 ;
     RECT  18.615 88.349 18.897 92.923 ;
     RECT  2.415 91.901 4.878 92.939 ;
     RECT  21.096 92.911 22.266 93.055 ;
     RECT  20.916 93.055 22.266 93.101 ;
     RECT  2.415 92.939 4.338 93.209 ;
     RECT  6.228 91.133 6.822 93.325 ;
     RECT  21.528 93.101 22.266 93.389 ;
     RECT  17.244 92.923 18.897 93.499 ;
     RECT  6.12 93.325 6.822 93.581 ;
     RECT  6.012 93.589 6.03 93.629 ;
     RECT  17.244 93.499 19.17 93.865 ;
     RECT  19.908 93.499 20.322 93.865 ;
     RECT  17.244 93.865 20.322 94.061 ;
     RECT  18.615 94.061 20.322 94.075 ;
     RECT  2.415 93.209 4.23 94.171 ;
     RECT  18.615 94.075 20.862 94.289 ;
     RECT  29.268 91.769 30.366 94.567 ;
     RECT  18.615 94.289 20.682 94.595 ;
     RECT  19.836 94.595 20.682 94.637 ;
     RECT  23.94 90.545 24.462 94.639 ;
     RECT  29.196 94.567 30.366 94.667 ;
     RECT  20.052 94.637 20.682 94.829 ;
     RECT  20.052 94.829 20.574 95.021 ;
     RECT  6.804 93.581 6.822 95.179 ;
     RECT  7.668 89.159 14.202 95.179 ;
     RECT  6.804 95.179 14.202 95.741 ;
     RECT  7.668 95.741 14.202 96.317 ;
     RECT  7.668 96.317 10.206 96.893 ;
     RECT  2.415 94.171 4.302 96.907 ;
     RECT  31.176 91.769 31.194 97.037 ;
     RECT  2.34 96.907 4.302 97.259 ;
     RECT  2.412 97.259 4.302 97.421 ;
     RECT  7.668 96.893 9.702 97.565 ;
     RECT  15.876 84.365 15.93 98.093 ;
     RECT  2.415 97.421 4.302 98.185 ;
     RECT  2.376 98.185 4.302 98.525 ;
     RECT  4.212 98.525 4.302 98.609 ;
     RECT  31.932 90.605 32.526 98.621 ;
     RECT  2.376 98.525 3.402 99.101 ;
     RECT  2.376 99.101 3.078 99.197 ;
     RECT  7.74 97.565 9.702 99.197 ;
     RECT  33.336 90.283 40.698 99.197 ;
     RECT  4.284 98.609 4.302 100.925 ;
     RECT  9.036 99.197 9.702 100.925 ;
     RECT  10.944 96.317 14.202 100.925 ;
     RECT  37.296 99.197 40.698 100.925 ;
     RECT  10.944 100.925 11.826 100.973 ;
     RECT  2.415 99.197 2.826 100.997 ;
     RECT  18.615 94.595 18.897 100.997 ;
     RECT  12.672 100.925 14.202 101.267 ;
     RECT  18.807 100.997 18.897 101.267 ;
     RECT  10.944 100.973 11.718 101.405 ;
     RECT  13.572 101.267 14.202 101.405 ;
     RECT  29.268 94.667 30.366 101.405 ;
     RECT  10.944 101.405 11.61 101.453 ;
     RECT  13.644 101.405 14.202 101.453 ;
     RECT  2.556 100.997 2.826 101.501 ;
     RECT  9.036 100.925 9.594 101.501 ;
     RECT  23.94 94.639 24.498 101.501 ;
     RECT  2.556 101.501 2.754 102.077 ;
     RECT  9.036 101.501 9.45 102.077 ;
     RECT  23.94 101.501 23.958 102.077 ;
     RECT  33.336 99.197 36.558 102.077 ;
     RECT  37.872 100.925 40.698 102.077 ;
     RECT  37.872 102.077 39.042 102.125 ;
     RECT  9.432 102.077 9.45 102.523 ;
     RECT  14.184 101.453 14.202 102.523 ;
     RECT  9.432 102.523 9.846 102.571 ;
     RECT  9.432 102.571 9.954 102.653 ;
     RECT  11.448 101.453 11.466 102.653 ;
     RECT  14.184 102.523 14.454 102.653 ;
     RECT  37.872 102.125 38.754 102.653 ;
     RECT  39.852 102.077 40.698 102.653 ;
     RECT  45.288 90.077 51.93 102.653 ;
     RECT  9.828 102.653 9.954 102.701 ;
     RECT  14.436 102.653 14.454 102.701 ;
     RECT  46.944 102.653 51.93 102.701 ;
     RECT  7.74 99.197 8.154 102.749 ;
     RECT  9.936 102.701 9.954 102.749 ;
     RECT  33.372 102.077 36.558 102.749 ;
     RECT  37.872 102.653 38.394 102.749 ;
     RECT  33.48 102.749 36.558 102.797 ;
     RECT  37.872 102.749 37.89 102.797 ;
     RECT  39.996 102.653 40.698 103.099 ;
     RECT  39.996 103.099 40.95 103.147 ;
     RECT  42.588 90.077 44.55 103.195 ;
     RECT  41.904 103.195 44.55 103.229 ;
     RECT  5.94 103.147 5.958 103.243 ;
     RECT  15.912 98.093 15.93 103.243 ;
     RECT  39.996 103.147 41.022 103.243 ;
     RECT  41.904 103.229 43.614 103.243 ;
     RECT  29.772 101.405 30.366 103.277 ;
     RECT  28.008 103.147 28.278 103.325 ;
     RECT  15.804 103.243 15.93 103.339 ;
     RECT  27.144 103.243 27.162 103.339 ;
     RECT  5.148 103.243 5.958 103.373 ;
     RECT  47.124 102.701 51.93 103.373 ;
     RECT  5.256 103.373 5.958 103.387 ;
     RECT  6.804 95.741 6.822 103.387 ;
     RECT  22.248 93.389 22.266 103.387 ;
     RECT  47.196 103.373 51.93 103.421 ;
     RECT  2.736 102.077 2.754 103.435 ;
     RECT  4.392 103.387 4.41 103.435 ;
     RECT  12.672 101.267 12.69 103.435 ;
     RECT  14.58 103.387 14.598 103.435 ;
     RECT  17.244 94.061 17.37 103.435 ;
     RECT  18.108 103.195 18.126 103.435 ;
     RECT  19.728 103.387 20.07 103.435 ;
     RECT  20.916 103.387 20.934 103.435 ;
     RECT  21.852 103.387 22.266 103.435 ;
     RECT  27.108 103.339 27.162 103.435 ;
     RECT  28.008 103.325 28.026 103.435 ;
     RECT  30.312 103.277 30.366 103.435 ;
     RECT  31.932 98.621 32.382 103.435 ;
     RECT  30.312 103.435 32.382 103.469 ;
     RECT  45.468 102.653 46.134 103.469 ;
     RECT  14.58 103.435 14.67 103.517 ;
     RECT  20.916 103.435 22.266 103.517 ;
     RECT  27.9 103.435 28.026 103.517 ;
     RECT  30.348 103.469 32.382 103.517 ;
     RECT  39.996 103.243 43.614 103.517 ;
     RECT  45.756 103.469 46.134 103.517 ;
     RECT  47.484 103.421 51.93 103.517 ;
     RECT  2.484 103.435 3.15 103.565 ;
     RECT  3.996 103.435 4.518 103.565 ;
     RECT  5.256 103.387 7.398 103.565 ;
     RECT  8.136 102.749 8.154 103.565 ;
     RECT  12.312 103.435 12.69 103.565 ;
     RECT  14.652 103.517 14.67 103.565 ;
     RECT  15.588 103.339 15.93 103.565 ;
     RECT  17.244 103.435 18.99 103.565 ;
     RECT  19.728 103.435 20.142 103.565 ;
     RECT  20.988 103.517 22.266 103.565 ;
     RECT  23.544 103.387 23.562 103.565 ;
     RECT  26.712 103.435 27.162 103.565 ;
     RECT  27.9 103.517 27.918 103.565 ;
     RECT  28.944 103.339 28.962 103.565 ;
     RECT  30.348 103.517 32.238 103.565 ;
     RECT  33.588 102.797 36.558 103.565 ;
     RECT  39.996 103.517 40.014 103.565 ;
     RECT  41.148 103.517 43.614 103.565 ;
     RECT  44.532 103.229 44.55 103.565 ;
     RECT  45.756 103.517 46.062 103.565 ;
     RECT  47.772 103.517 51.822 103.565 ;
    LAYER M4 ;
     RECT  0.06 26.928 0.137 77.544 ;
     RECT  0.137 27.024 0.173 77.544 ;
     RECT  0.173 65.52 0.209 77.544 ;
     RECT  0.709 1.728 0.805 1.752 ;
     RECT  0.805 1.728 0.901 2.28 ;
     RECT  0.173 27.024 1.181 64.488 ;
     RECT  0.901 1.728 1.189 2.904 ;
     RECT  1.181 27.12 1.217 64.488 ;
     RECT  1.217 27.216 1.253 64.488 ;
     RECT  1.381 88.752 1.477 88.776 ;
     RECT  1.189 1.728 1.573 3.432 ;
     RECT  1.381 4.56 1.573 4.584 ;
     RECT  1.477 88.512 1.573 88.776 ;
     RECT  1.573 88.512 1.669 88.92 ;
     RECT  1.669 0.576 1.765 0.6 ;
     RECT  1.669 88.512 1.861 89.544 ;
     RECT  1.573 1.728 1.957 4.584 ;
     RECT  2.149 91.776 2.204 91.8 ;
     RECT  0.209 65.616 2.293 77.544 ;
     RECT  1.861 88.512 2.293 90.408 ;
     RECT  2.285 96.912 2.293 96.936 ;
     RECT  1.765 0.576 2.341 0.648 ;
     RECT  1.957 1.728 2.341 4.68 ;
     RECT  2.293 103.44 2.341 103.464 ;
     RECT  2.293 23.376 2.365 24.216 ;
     RECT  2.341 0.576 2.408 4.68 ;
     RECT  2.252 19.92 2.408 19.944 ;
     RECT  2.365 23.376 2.408 25.032 ;
     RECT  2.329 26.592 2.408 26.616 ;
     RECT  1.253 27.6 2.408 64.488 ;
     RECT  2.293 65.616 2.408 78.456 ;
     RECT  2.257 80.064 2.408 80.088 ;
     RECT  2.293 88.512 2.408 90.552 ;
     RECT  2.204 91.776 2.408 91.896 ;
     RECT  2.293 96.912 2.408 97.416 ;
     RECT  2.365 99.168 2.408 99.192 ;
     RECT  2.408 0.576 2.437 100.992 ;
     RECT  2.341 103.44 2.533 103.56 ;
     RECT  2.437 0.576 2.545 101.4 ;
     RECT  2.545 0.576 2.704 102.072 ;
     RECT  2.704 101.376 2.765 102.072 ;
     RECT  2.765 101.376 2.771 101.592 ;
     RECT  2.704 17.088 2.819 80.424 ;
     RECT  2.771 101.376 2.819 101.496 ;
     RECT  2.533 103.296 2.819 103.56 ;
     RECT  2.819 101.472 2.837 101.496 ;
     RECT  2.704 0.576 2.873 2.904 ;
     RECT  2.819 22.176 2.873 80.328 ;
     RECT  2.704 81.6 2.981 81.624 ;
     RECT  2.873 0.576 3.013 1.896 ;
     RECT  2.704 4.08 3.053 4.68 ;
     RECT  2.704 97.92 3.133 99.192 ;
     RECT  3.013 0.096 3.197 1.896 ;
     RECT  2.819 17.088 3.197 21.144 ;
     RECT  3.197 17.424 3.203 18.264 ;
     RECT  3.197 19.392 3.205 21.144 ;
     RECT  2.873 22.176 3.269 76.872 ;
     RECT  3.053 4.08 3.305 4.104 ;
     RECT  3.197 0.624 3.413 1.896 ;
     RECT  2.873 78.048 3.413 80.328 ;
     RECT  3.133 97.92 3.413 99.096 ;
     RECT  2.704 6.24 3.443 6.264 ;
     RECT  3.269 22.752 3.449 76.872 ;
     RECT  3.413 79.728 3.485 80.328 ;
     RECT  3.205 19.872 3.587 21.144 ;
     RECT  2.704 14.496 3.683 14.856 ;
     RECT  2.704 93.504 3.781 93.624 ;
     RECT  3.587 19.92 3.809 21.144 ;
     RECT  3.781 92.544 3.829 93.624 ;
     RECT  3.683 14.832 3.845 14.856 ;
     RECT  3.413 97.92 3.845 98.52 ;
     RECT  3.781 10.272 3.877 10.296 ;
     RECT  2.704 91.152 3.877 91.176 ;
     RECT  3.877 91.104 3.913 91.176 ;
     RECT  3.449 66.384 3.923 76.872 ;
     RECT  3.845 97.92 3.953 98.232 ;
     RECT  3.809 19.92 3.971 20.856 ;
     RECT  3.923 66.384 3.971 74.712 ;
     RECT  3.923 76.128 3.985 76.872 ;
     RECT  3.413 78.048 3.985 78.696 ;
     RECT  3.913 90.576 3.997 91.176 ;
     RECT  3.953 97.92 4.021 98.04 ;
     RECT  3.877 10.272 4.025 10.344 ;
     RECT  3.485 79.968 4.061 80.328 ;
     RECT  3.985 76.128 4.125 78.696 ;
     RECT  3.413 0.624 4.169 1.848 ;
     RECT  4.025 10.32 4.169 10.344 ;
     RECT  4.169 0.624 4.201 1.752 ;
     RECT  4.201 0.528 4.205 1.752 ;
     RECT  4.021 97.68 4.237 98.04 ;
     RECT  4.165 2.88 4.277 2.904 ;
     RECT  3.829 92.256 4.277 93.624 ;
     RECT  4.277 92.256 4.313 92.28 ;
     RECT  4.237 97.488 4.313 98.04 ;
     RECT  3.997 91.056 4.321 91.176 ;
     RECT  4.313 97.488 4.321 97.512 ;
     RECT  4.205 0.528 4.337 1.128 ;
     RECT  4.261 100.896 4.348 100.92 ;
     RECT  3.203 17.664 4.453 18.264 ;
     RECT  3.449 22.752 4.489 65.304 ;
     RECT  4.453 17.616 4.517 18.264 ;
     RECT  3.941 7.968 4.529 7.992 ;
     RECT  4.489 22.224 4.529 65.304 ;
     RECT  4.337 0.096 4.601 1.128 ;
     RECT  4.529 23.232 4.601 65.304 ;
     RECT  4.529 22.224 4.669 22.248 ;
     RECT  4.601 25.632 4.669 65.304 ;
     RECT  3.971 66.384 4.669 74.664 ;
     RECT  4.601 0.528 4.691 1.128 ;
     RECT  4.669 25.632 4.739 74.664 ;
     RECT  4.517 17.616 4.835 18.792 ;
     RECT  4.601 23.232 4.853 24.552 ;
     RECT  4.741 9.12 4.933 9.144 ;
     RECT  3.971 20.688 4.957 20.856 ;
     RECT  4.835 18.192 4.993 18.792 ;
     RECT  4.691 0.528 4.997 0.6 ;
     RECT  4.125 76.944 4.997 78.696 ;
     RECT  4.993 14.832 5.105 14.856 ;
     RECT  4.739 70.608 5.105 74.664 ;
     RECT  4.061 79.968 5.123 79.992 ;
     RECT  2.819 103.392 5.125 103.56 ;
     RECT  5.125 103.344 5.132 103.56 ;
     RECT  5.029 3.408 5.141 3.432 ;
     RECT  4.993 18.192 5.141 18.84 ;
     RECT  5.125 5.136 5.221 5.16 ;
     RECT  4.997 78.624 5.221 78.696 ;
     RECT  4.933 9.12 5.249 9.192 ;
     RECT  5.221 78.624 5.293 79.272 ;
     RECT  5.141 18.192 5.315 18.216 ;
     RECT  5.221 4.56 5.317 5.16 ;
     RECT  5.317 4.56 5.393 5.736 ;
     RECT  5.132 103.248 5.413 103.56 ;
     RECT  5.393 5.712 5.429 5.736 ;
     RECT  4.957 20.688 5.461 21.096 ;
     RECT  4.669 22.176 5.461 22.248 ;
     RECT  5.42 17.088 5.507 17.112 ;
     RECT  5.249 9.168 5.537 9.192 ;
     RECT  5.293 78.672 5.537 79.272 ;
     RECT  5.413 2.304 5.645 2.328 ;
     RECT  5.353 19.344 5.653 19.368 ;
     RECT  5.461 20.688 5.653 22.248 ;
     RECT  4.997 0.528 5.669 0.552 ;
     RECT  5.393 4.56 5.681 4.584 ;
     RECT  5.653 19.344 5.699 22.248 ;
     RECT  4.739 25.632 5.749 69.096 ;
     RECT  5.669 0.096 5.753 0.552 ;
     RECT  5.749 25.632 5.756 69.48 ;
     RECT  5.105 70.608 5.756 74.472 ;
     RECT  5.753 0.144 5.861 0.552 ;
     RECT  4.853 23.904 5.893 24.552 ;
     RECT  5.756 25.632 5.893 74.472 ;
     RECT  4.277 93.504 6.041 93.624 ;
     RECT  5.605 10.848 6.065 10.872 ;
     RECT  5.413 103.152 6.083 103.56 ;
     RECT  6.065 10.848 6.148 10.92 ;
     RECT  6.041 93.504 6.149 93.576 ;
     RECT  4.321 91.104 6.185 91.176 ;
     RECT  6.148 10.848 6.221 10.968 ;
     RECT  6.185 91.152 6.257 91.176 ;
     RECT  6.149 93.552 6.257 93.576 ;
     RECT  4.789 12.768 6.277 12.792 ;
     RECT  5.893 23.904 6.329 74.472 ;
     RECT  6.221 10.944 6.401 10.968 ;
     RECT  5.989 7.44 6.437 7.464 ;
     RECT  4.997 76.944 6.481 77.496 ;
     RECT  5.537 78.672 6.581 78.696 ;
     RECT  6.421 9.648 6.661 9.672 ;
     RECT  6.277 12 6.757 12.792 ;
     RECT  5.699 20.016 6.761 22.248 ;
     RECT  6.329 28.176 6.829 74.472 ;
     RECT  6.757 12 6.833 13.032 ;
     RECT  6.373 0.576 6.929 0.6 ;
     RECT  6.929 0.096 7.013 0.6 ;
     RECT  7.013 0.144 7.121 0.6 ;
     RECT  6.829 2.832 7.141 2.856 ;
     RECT  7.121 0.192 7.237 0.6 ;
     RECT  6.997 95.184 7.261 95.208 ;
     RECT  7.237 0.192 7.405 1.176 ;
     RECT  7.141 2.304 7.405 2.856 ;
     RECT  6.329 23.904 7.405 26.856 ;
     RECT  6.997 86.88 7.477 86.904 ;
     RECT  6.761 20.016 7.525 21.768 ;
     RECT  7.477 86.592 7.525 86.904 ;
     RECT  7.261 95.184 7.525 95.736 ;
     RECT  6.937 22.8 7.549 22.824 ;
     RECT  7.525 5.136 7.573 5.16 ;
     RECT  7.525 19.824 7.573 21.768 ;
     RECT  7.477 6.816 7.585 6.84 ;
     RECT  6.661 9.648 7.585 9.72 ;
     RECT  7.405 23.904 7.657 26.904 ;
     RECT  7.525 86.496 7.669 86.904 ;
     RECT  6.083 103.2 7.729 103.56 ;
     RECT  7.729 102.72 7.765 103.56 ;
     RECT  7.405 0.192 7.808 2.856 ;
     RECT  7.261 3.936 7.808 3.96 ;
     RECT  7.573 5.136 7.808 5.352 ;
     RECT  7.585 6.816 7.808 7.368 ;
     RECT  7.585 9.504 7.808 9.72 ;
     RECT  7.621 11.76 7.808 11.784 ;
     RECT  6.833 12.768 7.808 13.032 ;
     RECT  7.573 14.496 7.808 14.52 ;
     RECT  7.669 15.984 7.808 16.008 ;
     RECT  7.573 19.536 7.808 21.768 ;
     RECT  7.549 22.8 7.808 22.92 ;
     RECT  7.657 23.904 7.808 27.096 ;
     RECT  6.829 28.176 7.808 74.616 ;
     RECT  6.481 77.472 7.808 77.496 ;
     RECT  7.669 86.496 7.808 87.24 ;
     RECT  7.525 94.656 7.808 95.736 ;
     RECT  7.657 97.536 7.808 97.56 ;
     RECT  7.808 0.192 7.859 100.992 ;
     RECT  7.859 1.152 8 100.992 ;
     RECT  8 1.152 8.104 101.262 ;
     RECT  7.765 102.624 8.165 103.56 ;
     RECT  8.104 1.152 8.243 3 ;
     RECT  8.104 93.504 8.243 93.576 ;
     RECT  8.104 57.36 8.273 74.616 ;
     RECT  8.104 86.544 8.291 87.816 ;
     RECT  8.243 93.552 8.339 93.576 ;
     RECT  8.273 58.656 8.345 74.616 ;
     RECT  8.104 22.8 8.381 55.272 ;
     RECT  8.345 58.656 8.381 74.376 ;
     RECT  8.165 102.624 8.387 103.512 ;
     RECT  8.381 22.8 8.435 30.072 ;
     RECT  8.104 77.136 8.531 77.16 ;
     RECT  8.104 94.656 8.531 97.56 ;
     RECT  8.381 58.656 8.561 74.184 ;
     RECT  8.435 22.8 8.597 22.824 ;
     RECT  8.435 23.904 8.597 30.072 ;
     RECT  8.561 58.656 8.597 74.088 ;
     RECT  8.104 6.816 8.627 7.992 ;
     RECT  8.531 94.656 8.627 96.936 ;
     RECT  8.627 6.816 8.633 7.368 ;
     RECT  8.104 20.016 8.633 20.952 ;
     RECT  8.104 8.976 8.668 13.704 ;
     RECT  8.633 20.016 8.675 20.808 ;
     RECT  8.597 67.92 8.741 74.088 ;
     RECT  8.627 95.184 8.741 96.936 ;
     RECT  8.381 31.92 8.813 55.272 ;
     RECT  8.668 9.216 8.819 13.704 ;
     RECT  8.741 69.648 8.885 74.088 ;
     RECT  8.819 11.904 8.908 13.704 ;
     RECT  8.741 95.184 8.915 96.36 ;
     RECT  8.597 58.656 8.957 66.84 ;
     RECT  8.104 3.984 8.993 4.008 ;
     RECT  8.387 102.624 9.025 102.744 ;
     RECT  8.908 11.952 9.029 13.704 ;
     RECT  8.957 63.312 9.029 66.84 ;
     RECT  8.819 9.216 9.052 10.344 ;
     RECT  8.243 1.152 9.065 1.704 ;
     RECT  8.957 58.656 9.101 62.232 ;
     RECT  8.885 69.648 9.101 73.896 ;
     RECT  8.675 20.016 9.109 20.568 ;
     RECT  8.273 57.36 9.133 57.576 ;
     RECT  8.243 2.88 9.137 3 ;
     RECT  9.109 18.816 9.155 20.568 ;
     RECT  9.101 69.648 9.173 73.176 ;
     RECT  8.291 86.88 9.173 87.816 ;
     RECT  8.104 99.168 9.203 99.192 ;
     RECT  9.125 0.096 9.209 0.12 ;
     RECT  9.029 63.312 9.245 64.392 ;
     RECT  9.029 65.376 9.245 66.84 ;
     RECT  9.109 22.176 9.251 22.296 ;
     RECT  9.133 56.832 9.281 57.576 ;
     RECT  8.597 25.104 9.299 30.072 ;
     RECT  9.212 88.944 9.299 88.968 ;
     RECT  9.281 57.552 9.308 57.576 ;
     RECT  9.101 58.656 9.308 61.56 ;
     RECT  9.308 57.552 9.353 61.56 ;
     RECT  9.029 13.104 9.389 13.704 ;
     RECT  9.173 69.648 9.389 70.68 ;
     RECT  9.353 57.552 9.395 58.152 ;
     RECT  9.313 89.472 9.397 89.496 ;
     RECT  9.025 102.048 9.491 102.744 ;
     RECT  9.052 9.216 9.497 10.248 ;
     RECT  9.173 71.856 9.497 73.176 ;
     RECT  9.389 13.632 9.541 13.704 ;
     RECT  9.497 71.856 9.569 73.032 ;
     RECT  9.541 13.632 9.587 13.752 ;
     RECT  9.173 87.408 9.635 87.816 ;
     RECT  9.587 13.728 9.637 13.752 ;
     RECT  8.104 15.168 9.637 17.688 ;
     RECT  9.341 0.528 9.641 0.648 ;
     RECT  9.299 25.728 9.641 30.072 ;
     RECT  9.245 65.52 9.673 66.84 ;
     RECT  8.741 67.92 9.673 68.568 ;
     RECT  9.565 101.472 9.673 101.496 ;
     RECT  9.637 13.728 9.683 17.688 ;
     RECT  9.389 69.648 9.683 69.96 ;
     RECT  9.569 71.856 9.713 72.984 ;
     RECT  8.633 6.816 9.731 6.84 ;
     RECT  9.497 9.216 9.733 9.24 ;
     RECT  9.673 65.52 9.74 68.568 ;
     RECT  9.635 87.696 9.745 87.816 ;
     RECT  9.029 11.952 9.785 11.976 ;
     RECT  9.155 18.816 9.785 19.368 ;
     RECT  9.349 56.352 9.785 56.376 ;
     RECT  9.683 16.944 9.821 17.688 ;
     RECT  9.641 27.264 9.821 30.072 ;
     RECT  9.497 10.224 9.827 10.248 ;
     RECT  9.821 17.088 9.829 17.688 ;
     RECT  9.785 18.816 9.829 18.84 ;
     RECT  9.745 87.696 9.829 88.344 ;
     RECT  9.491 102.528 9.868 102.744 ;
     RECT  9.829 17.088 9.875 18.84 ;
     RECT  9.733 8.544 9.893 9.24 ;
     RECT  9.713 71.856 9.893 72.744 ;
     RECT  9.875 18.192 9.916 18.216 ;
     RECT  9.829 87.696 9.916 88.296 ;
     RECT  9.916 88.272 9.937 88.296 ;
     RECT  9.829 3.408 9.965 3.432 ;
     RECT  9.868 102.576 9.965 102.744 ;
     RECT  9.673 1.728 9.97 1.752 ;
     RECT  9.893 72.24 10.001 72.744 ;
     RECT  9.965 102.72 10.009 102.744 ;
     RECT  8.915 95.184 10.076 95.736 ;
     RECT  10.076 95.184 10.177 96.6 ;
     RECT  8.597 23.904 10.261 23.928 ;
     RECT  10.177 95.184 10.261 96.888 ;
     RECT  9.395 57.552 10.285 57.576 ;
     RECT  9.641 0.528 10.309 0.552 ;
     RECT  10.261 23.712 10.309 23.928 ;
     RECT  9.353 59.472 10.325 61.56 ;
     RECT  9.821 28.224 10.333 30.072 ;
     RECT  9.673 100.896 10.355 101.496 ;
     RECT  9.875 17.088 10.369 17.112 ;
     RECT  9.245 63.312 10.429 64.344 ;
     RECT  9.74 65.52 10.429 69.192 ;
     RECT  10.309 23.376 10.433 23.928 ;
     RECT  10.393 89.472 10.477 89.496 ;
     RECT  10.261 95.184 10.547 96.312 ;
     RECT  10.573 59.328 10.685 59.352 ;
     RECT  9.97 1.728 10.748 1.8 ;
     RECT  10.429 63.312 10.753 69.192 ;
     RECT  10.753 62.976 10.789 69.192 ;
     RECT  9.251 22.176 10.793 22.2 ;
     RECT  10.547 95.664 10.793 96.312 ;
     RECT  10.001 72.24 10.829 72.264 ;
     RECT  10.748 1.728 10.835 2.28 ;
     RECT  10.793 96.288 10.873 96.312 ;
     RECT  10.105 4.656 10.973 4.68 ;
     RECT  10.355 100.896 10.988 101.448 ;
     RECT  10.789 62.976 11.005 69.528 ;
     RECT  10.988 100.8 11.075 101.448 ;
     RECT  10.325 60.336 11.117 61.56 ;
     RECT  11.005 62.784 11.149 69.528 ;
     RECT  10.997 94.56 11.173 94.584 ;
     RECT  11.117 61.056 11.185 61.56 ;
     RECT  11.149 62.688 11.185 69.528 ;
     RECT  11.173 94.08 11.26 94.584 ;
     RECT  10.309 0.096 11.293 0.552 ;
     RECT  10.835 1.728 11.293 2.184 ;
     RECT  11.26 94.416 11.363 94.584 ;
     RECT  8.813 33.072 11.365 55.272 ;
     RECT  10.285 56.4 11.365 57.576 ;
     RECT  9.641 25.728 11.437 26.28 ;
     RECT  11.293 0.096 11.477 2.184 ;
     RECT  11.42 102.624 11.507 102.648 ;
     RECT  11.468 21.792 11.555 21.816 ;
     RECT  11.437 25.728 11.555 26.808 ;
     RECT  9.683 14.208 11.581 15.192 ;
     RECT  11.075 100.896 11.621 101.448 ;
     RECT  11.581 14.208 11.665 15.96 ;
     RECT  11.605 21.12 11.693 21.144 ;
     RECT  11.477 0.096 11.699 1.752 ;
     RECT  11.185 61.056 11.701 69.528 ;
     RECT  11.621 100.896 11.729 101.4 ;
     RECT  11.665 14.208 11.761 15.192 ;
     RECT  11.365 33.072 11.761 57.576 ;
     RECT  11.761 14.064 11.801 15.192 ;
     RECT  11.761 33.072 11.801 57.864 ;
     RECT  11.729 100.896 11.891 100.968 ;
     RECT  11.701 61.056 11.909 69.96 ;
     RECT  11.891 100.896 11.987 100.92 ;
     RECT  11.948 87.072 12.013 87.096 ;
     RECT  11.801 46.32 12.053 57.864 ;
     RECT  11.909 61.056 12.053 69.72 ;
     RECT  12.053 61.056 12.085 61.896 ;
     RECT  12.013 87.072 12.096 87.192 ;
     RECT  11.989 95.184 12.121 95.208 ;
     RECT  11.689 6.24 12.229 6.264 ;
     RECT  12.053 48.192 12.301 57.864 ;
     RECT  12.229 6.24 12.332 6.6 ;
     RECT  9.893 9.216 12.517 9.24 ;
     RECT  12.096 87.072 12.565 87.24 ;
     RECT  12.121 95.184 12.565 95.736 ;
     RECT  12.565 86.352 12.572 87.24 ;
     RECT  11.699 1.728 12.589 1.752 ;
     RECT  12.332 6.24 12.613 6.84 ;
     RECT  12.613 5.808 12.62 6.84 ;
     RECT  12.517 7.968 12.62 9.24 ;
     RECT  12.62 5.808 12.625 9.24 ;
     RECT  12.085 61.008 12.661 61.896 ;
     RECT  11.699 0.096 12.709 0.552 ;
     RECT  11.905 59.28 12.769 59.304 ;
     RECT  12.565 94.656 12.853 95.736 ;
     RECT  12.572 86.016 12.877 87.24 ;
     RECT  12.805 88.512 12.877 88.536 ;
     RECT  12.625 5.712 13.021 9.24 ;
     RECT  12.589 1.728 13.025 2.28 ;
     RECT  13.021 5.712 13.045 9.672 ;
     RECT  12.301 48.192 13.057 57.96 ;
     RECT  12.661 60.864 13.057 61.896 ;
     RECT  12.053 62.976 13.057 69.72 ;
     RECT  13.045 4.944 13.093 9.672 ;
     RECT  13.057 48.192 13.093 58.2 ;
     RECT  12.769 59.184 13.093 59.304 ;
     RECT  13.057 60.864 13.093 69.72 ;
     RECT  12.853 94.656 13.093 95.832 ;
     RECT  13.025 1.872 13.208 2.28 ;
     RECT  13.093 4.944 13.208 9.816 ;
     RECT  12.565 12.72 13.208 12.744 ;
     RECT  11.801 14.064 13.208 14.088 ;
     RECT  11.801 15.168 13.208 15.192 ;
     RECT  12.553 16.56 13.208 16.584 ;
     RECT  10.433 23.904 13.208 23.928 ;
     RECT  11.555 25.728 13.208 26.28 ;
     RECT  10.333 28.224 13.208 29.064 ;
     RECT  10.333 30.048 13.208 30.072 ;
     RECT  12.997 31.344 13.208 31.368 ;
     RECT  11.801 33.072 13.208 45.288 ;
     RECT  12.053 46.32 13.208 47.064 ;
     RECT  13.093 48.192 13.208 69.72 ;
     RECT  12.877 86.016 13.208 88.536 ;
     RECT  13.093 94.656 13.208 96.312 ;
     RECT  12.841 97.536 13.208 97.56 ;
     RECT  12.517 99.168 13.208 99.192 ;
     RECT  13.208 1.872 13.381 100.992 ;
     RECT  13.381 1.872 13.477 101.4 ;
     RECT  13.477 1.872 13.504 101.448 ;
     RECT  13.504 66.192 13.601 66.312 ;
     RECT  13.504 101.376 13.601 101.448 ;
     RECT  13.504 1.872 13.619 1.896 ;
     RECT  13.504 86.88 13.619 87.144 ;
     RECT  13.504 95.184 13.619 96.312 ;
     RECT  13.504 48.192 13.667 52.296 ;
     RECT  13.619 87.12 13.667 87.144 ;
     RECT  13.619 95.184 13.667 95.544 ;
     RECT  13.504 97.44 13.667 97.56 ;
     RECT  13.667 48.192 13.673 48.216 ;
     RECT  13.667 49.536 13.673 52.296 ;
     RECT  13.667 95.184 13.673 95.448 ;
     RECT  13.601 101.424 13.673 101.448 ;
     RECT  13.673 95.184 13.709 95.208 ;
     RECT  12.709 0.096 13.781 0.6 ;
     RECT  13.781 0.096 13.811 0.552 ;
     RECT  13.504 6.576 13.811 7.992 ;
     RECT  13.504 68.496 13.811 70.008 ;
     RECT  13.504 9.792 13.889 10.248 ;
     RECT  13.811 69.456 14.099 70.008 ;
     RECT  13.889 10.224 14.105 10.248 ;
     RECT  13.811 7.968 14.141 7.992 ;
     RECT  13.504 60.912 14.141 65.016 ;
     RECT  13.811 6.576 14.147 6.744 ;
     RECT  14.099 69.456 14.147 69.48 ;
     RECT  12.274 103.44 14.173 103.56 ;
     RECT  14.141 61.632 14.213 65.016 ;
     RECT  14.173 102.624 14.389 103.56 ;
     RECT  13.673 49.584 14.429 52.296 ;
     RECT  14.389 102.528 14.476 103.56 ;
     RECT  14.476 102.672 14.509 103.56 ;
     RECT  13.504 31.92 14.579 45.288 ;
     RECT  13.504 79.776 14.581 79.8 ;
     RECT  14.581 79.584 14.668 79.8 ;
     RECT  14.668 79.776 14.713 79.8 ;
     RECT  14.579 31.92 14.717 31.944 ;
     RECT  14.429 49.824 14.717 52.296 ;
     RECT  14.213 61.92 14.717 65.016 ;
     RECT  14.713 79.776 14.723 80.376 ;
     RECT  14.533 1.728 14.788 1.752 ;
     RECT  13.811 0.096 14.857 0.504 ;
     RECT  14.749 73.344 14.857 73.368 ;
     RECT  14.821 82.032 14.857 82.056 ;
     RECT  14.857 73.344 15.041 73.848 ;
     RECT  13.601 66.192 15.061 66.216 ;
     RECT  14.857 0.096 15.173 0.552 ;
     RECT  14.788 1.728 15.173 1.8 ;
     RECT  14.717 61.92 15.181 64.68 ;
     RECT  14.717 50.016 15.221 52.296 ;
     RECT  15.041 73.536 15.221 73.848 ;
     RECT  15.181 60.96 15.253 64.68 ;
     RECT  14.857 81.504 15.347 82.056 ;
     RECT  14.723 80.352 15.356 80.376 ;
     RECT  15.347 81.504 15.356 81.576 ;
     RECT  13.504 53.376 15.433 59.832 ;
     RECT  15.253 60.864 15.433 64.68 ;
     RECT  15.221 73.536 15.437 73.56 ;
     RECT  14.509 103.392 15.541 103.56 ;
     RECT  15.548 82.656 15.635 82.68 ;
     RECT  13.504 25.728 15.653 26.28 ;
     RECT  15.433 53.376 15.685 64.68 ;
     RECT  15.173 0.096 15.689 1.8 ;
     RECT  13.504 23.904 15.731 23.928 ;
     RECT  15.541 103.344 15.788 103.56 ;
     RECT  15.788 103.248 15.875 103.56 ;
     RECT  15.356 80.352 15.877 81.576 ;
     RECT  15.689 0.096 15.941 0.12 ;
     RECT  15.875 103.536 15.941 103.56 ;
     RECT  15.221 50.016 15.977 52.248 ;
     RECT  15.865 98.064 16.019 98.088 ;
     RECT  15.877 80.352 16.307 80.376 ;
     RECT  15.685 53.376 16.357 65.208 ;
     RECT  15.061 66.192 16.357 66.264 ;
     RECT  13.504 28.224 16.403 29.064 ;
     RECT  16.357 53.376 16.405 66.264 ;
     RECT  15.689 1.152 16.445 1.8 ;
     RECT  13.504 30.048 16.451 30.072 ;
     RECT  15.877 81.504 16.453 81.576 ;
     RECT  16.405 53.376 16.513 66.888 ;
     RECT  16.445 1.728 16.549 1.8 ;
     RECT  16.069 2.88 16.549 2.904 ;
     RECT  16.477 73.2 16.585 73.224 ;
     RECT  16.541 84.336 16.604 84.36 ;
     RECT  16.585 73.2 16.733 73.32 ;
     RECT  16.549 1.728 16.741 2.904 ;
     RECT  16.733 73.2 16.805 73.224 ;
     RECT  16.513 53.328 16.945 66.888 ;
     RECT  16.741 1.728 17.029 2.952 ;
     RECT  16.837 70.704 17.057 70.728 ;
     RECT  16.604 83.808 17.057 84.36 ;
     RECT  17.057 83.808 17.075 83.832 ;
     RECT  16.453 81.504 17.084 81.624 ;
     RECT  14.579 33.072 17.129 45.288 ;
     RECT  17.084 81.456 17.171 81.624 ;
     RECT  17.125 0.576 17.221 0.6 ;
     RECT  17.129 33.12 17.237 45.288 ;
     RECT  17.189 103.536 17.297 103.56 ;
     RECT  17.305 82.032 17.389 82.056 ;
     RECT  17.221 0.096 17.417 0.6 ;
     RECT  17.276 92.928 17.42 92.952 ;
     RECT  17.42 92.928 17.477 93.384 ;
     RECT  17.413 83.184 17.496 83.784 ;
     RECT  17.417 0.096 17.525 0.12 ;
     RECT  15.977 51.696 17.557 52.248 ;
     RECT  16.945 53.232 17.557 66.888 ;
     RECT  17.237 37.152 17.633 45.288 ;
     RECT  17.297 103.392 17.701 103.56 ;
     RECT  17.496 83.136 17.756 83.784 ;
     RECT  17.701 103.296 17.989 103.56 ;
     RECT  17.989 103.104 18.131 103.56 ;
     RECT  17.557 51.696 18.133 66.888 ;
     RECT  18.061 18.816 18.181 18.84 ;
     RECT  17.756 83.04 18.229 83.784 ;
     RECT  17.029 1.728 18.277 3 ;
     RECT  15.977 50.016 18.277 50.568 ;
     RECT  18.133 51.696 18.277 67.416 ;
     RECT  18.236 72.864 18.277 72.888 ;
     RECT  18.229 83.04 18.284 84.36 ;
     RECT  18.277 1.728 18.373 3.048 ;
     RECT  18.373 1.728 18.421 3.144 ;
     RECT  18.284 82.56 18.469 84.36 ;
     RECT  18.421 1.728 18.608 3.624 ;
     RECT  14.147 6.576 18.608 6.6 ;
     RECT  13.504 15.168 18.608 15.192 ;
     RECT  18.181 18.816 18.608 19.176 ;
     RECT  15.653 25.728 18.608 26.136 ;
     RECT  16.403 28.224 18.608 29.016 ;
     RECT  17.237 33.12 18.608 36.168 ;
     RECT  17.633 37.968 18.608 45.288 ;
     RECT  18.277 50.016 18.608 67.416 ;
     RECT  18.277 72.864 18.608 73.224 ;
     RECT  18.469 82.56 18.608 84.984 ;
     RECT  17.477 92.928 18.608 94.056 ;
     RECT  18.131 103.152 18.611 103.56 ;
     RECT  18.611 103.2 18.707 103.56 ;
     RECT  18.608 1.728 18.8 100.992 ;
     RECT  18.8 1.728 18.904 101.262 ;
     RECT  18.904 39.024 18.965 45.288 ;
     RECT  18.853 0.144 19.043 0.168 ;
     RECT  18.904 20.16 19.043 20.184 ;
     RECT  18.904 70.704 19.043 70.776 ;
     RECT  18.904 6.576 19.073 6.6 ;
     RECT  18.904 1.728 19.145 4.392 ;
     RECT  18.904 88.32 19.289 88.344 ;
     RECT  18.904 50.016 19.469 67.56 ;
     RECT  19.145 1.728 19.505 2.328 ;
     RECT  19.429 0.384 19.537 0.504 ;
     RECT  19.505 2.304 19.613 2.328 ;
     RECT  19.145 3.408 19.613 4.392 ;
     RECT  18.904 13.296 19.649 13.512 ;
     RECT  18.904 31.632 19.657 31.944 ;
     RECT  18.707 103.344 19.669 103.56 ;
     RECT  19.657 31.632 19.763 31.896 ;
     RECT  18.904 74.4 19.793 74.568 ;
     RECT  19.043 70.704 19.829 70.728 ;
     RECT  19.669 103.248 19.859 103.56 ;
     RECT  18.904 83.76 19.873 84.936 ;
     RECT  18.904 18.384 19.907 18.84 ;
     RECT  18.904 24.48 19.907 24.504 ;
     RECT  18.965 39.216 19.937 45.288 ;
     RECT  18.904 46.8 19.969 47.448 ;
     RECT  18.904 33.12 20.005 36.12 ;
     RECT  18.904 93.504 20.005 94.632 ;
     RECT  20.005 93.504 20.012 94.68 ;
     RECT  19.613 3.408 20.051 4.2 ;
     RECT  18.904 25.728 20.051 26.952 ;
     RECT  19.469 50.016 20.053 55.368 ;
     RECT  20.051 25.728 20.117 26.232 ;
     RECT  20.005 33.072 20.153 36.12 ;
     RECT  19.469 56.352 20.189 67.56 ;
     RECT  18.904 72.192 20.189 72.552 ;
     RECT  20.153 34.128 20.225 36.12 ;
     RECT  20.077 18.192 20.291 18.216 ;
     RECT  19.873 84.336 20.291 84.936 ;
     RECT  18.904 15.168 20.297 15.96 ;
     RECT  20.012 93.504 20.333 95.016 ;
     RECT  19.537 0.384 20.357 0.552 ;
     RECT  19.859 103.344 20.387 103.56 ;
     RECT  20.189 72.288 20.401 72.552 ;
     RECT  20.051 3.552 20.405 4.2 ;
     RECT  20.005 86.016 20.437 86.04 ;
     RECT  18.904 28.224 20.477 29.976 ;
     RECT  20.053 49.056 20.509 55.368 ;
     RECT  20.189 56.352 20.509 66.888 ;
     RECT  20.437 86.016 20.531 86.088 ;
     RECT  20.291 84.912 20.533 84.936 ;
     RECT  19.933 9.36 20.545 9.384 ;
     RECT  19.969 46.752 20.545 47.448 ;
     RECT  20.509 49.056 20.545 66.888 ;
     RECT  19.937 39.216 20.549 43.08 ;
     RECT  20.545 46.512 20.581 47.448 ;
     RECT  20.545 48.432 20.581 66.888 ;
     RECT  20.333 94.08 20.585 95.016 ;
     RECT  20.581 46.512 20.617 66.888 ;
     RECT  20.533 84.912 20.621 85.8 ;
     RECT  18.904 10.848 20.653 10.872 ;
     RECT  19.937 44.688 20.657 45.288 ;
     RECT  20.545 9.072 20.675 9.384 ;
     RECT  20.54 82.032 20.677 82.056 ;
     RECT  20.617 14.928 20.689 15.144 ;
     RECT  20.477 28.224 20.689 29.016 ;
     RECT  20.653 10.848 20.693 11.4 ;
     RECT  20.585 94.08 20.693 94.68 ;
     RECT  19.763 31.632 20.725 31.656 ;
     RECT  20.549 39.312 20.729 43.08 ;
     RECT  20.725 31.248 20.761 31.656 ;
     RECT  20.405 3.6 20.765 4.2 ;
     RECT  20.153 33.072 20.771 33.144 ;
     RECT  20.473 5.952 20.789 5.976 ;
     RECT  19.909 7.344 20.789 7.368 ;
     RECT  20.225 34.128 20.837 34.152 ;
     RECT  20.621 84.912 20.867 84.936 ;
     RECT  20.789 5.952 20.873 7.368 ;
     RECT  20.771 33.072 20.873 33.096 ;
     RECT  20.693 94.08 20.873 94.104 ;
     RECT  20.245 24.576 20.917 24.6 ;
     RECT  20.876 18.576 20.963 18.6 ;
     RECT  20.941 70.656 20.965 70.68 ;
     RECT  20.917 24.528 20.977 24.6 ;
     RECT  20.117 25.728 20.977 26.04 ;
     RECT  20.677 81.504 20.977 82.056 ;
     RECT  20.765 3.84 21.017 4.2 ;
     RECT  20.873 7.344 21.017 7.368 ;
     RECT  20.657 44.88 21.049 45.288 ;
     RECT  20.617 46.272 21.049 66.888 ;
     RECT  20.977 24.528 21.061 26.04 ;
     RECT  20.977 81.504 21.061 82.632 ;
     RECT  20.689 27.36 21.085 29.016 ;
     RECT  21.049 44.88 21.089 66.888 ;
     RECT  20.965 70.56 21.089 70.68 ;
     RECT  21.02 7.776 21.107 7.8 ;
     RECT  21.061 81.216 21.116 82.632 ;
     RECT  21.116 81.216 21.148 83.256 ;
     RECT  20.693 11.376 21.193 11.4 ;
     RECT  20.675 9.36 21.269 9.384 ;
     RECT  20.225 35.184 21.269 36.12 ;
     RECT  20.401 72.288 21.305 73.8 ;
     RECT  21.193 11.376 21.356 11.448 ;
     RECT  21.148 81.456 21.395 83.256 ;
     RECT  19.649 13.296 21.397 13.32 ;
     RECT  20.689 14.832 21.397 15.144 ;
     RECT  21.269 35.28 21.409 36.12 ;
     RECT  20.873 5.952 21.413 5.976 ;
     RECT  21.356 11.376 21.413 11.88 ;
     RECT  21.413 11.424 21.443 11.88 ;
     RECT  21.397 13.296 21.443 15.144 ;
     RECT  21.409 35.28 21.449 36.456 ;
     RECT  21.089 44.976 21.449 66.888 ;
     RECT  21.449 45.024 21.485 66.888 ;
     RECT  20.869 92.928 21.493 93.096 ;
     RECT  21.305 72.528 21.557 73.8 ;
     RECT  21.509 83.76 21.593 83.784 ;
     RECT  21.449 35.52 21.635 36.456 ;
     RECT  20.387 103.392 21.637 103.56 ;
     RECT  21.635 35.52 21.701 36.12 ;
     RECT  21.017 3.84 21.733 3.864 ;
     RECT  20.761 30.432 21.737 31.656 ;
     RECT  21.701 36.048 21.737 36.12 ;
     RECT  21.485 65.712 21.737 66.888 ;
     RECT  21.485 45.024 21.773 64.488 ;
     RECT  21.637 103.296 21.779 103.56 ;
     RECT  21.395 81.456 21.817 82.632 ;
     RECT  21.557 72.528 21.881 72.936 ;
     RECT  21.443 14.208 21.917 14.232 ;
     RECT  21.737 30.432 21.925 30.552 ;
     RECT  21.061 24.528 21.971 24.792 ;
     RECT  21.773 45.024 21.989 62.712 ;
     RECT  21.737 65.904 21.989 66.888 ;
     RECT  21.493 92.928 22.06 93.384 ;
     RECT  22.06 92.928 22.061 93 ;
     RECT  21.773 63.744 22.067 64.488 ;
     RECT  21.589 17.472 22.117 17.496 ;
     RECT  21.061 26.016 22.117 26.04 ;
     RECT  21.877 70.704 22.117 70.728 ;
     RECT  21.989 65.904 22.163 66.648 ;
     RECT  20.729 39.36 22.165 43.08 ;
     RECT  22.061 92.976 22.169 93 ;
     RECT  22.117 25.248 22.213 26.04 ;
     RECT  21.085 27.312 22.213 29.016 ;
     RECT  21.925 30.24 22.213 30.552 ;
     RECT  22.117 17.472 22.241 18.216 ;
     RECT  21.443 11.424 22.259 11.448 ;
     RECT  22.067 64.464 22.259 64.488 ;
     RECT  21.779 103.344 22.277 103.56 ;
     RECT  21.589 15.984 22.307 16.008 ;
     RECT  22.213 25.248 22.355 29.016 ;
     RECT  22.213 30.192 22.355 30.552 ;
     RECT  22.165 39.36 22.529 43.32 ;
     RECT  21.589 23.376 22.549 23.4 ;
     RECT  21.733 3.648 22.565 3.864 ;
     RECT  22.117 70.464 22.637 70.728 ;
     RECT  22.355 27.312 22.643 29.016 ;
     RECT  22.277 103.344 22.643 103.464 ;
     RECT  21.817 81.744 22.673 82.632 ;
     RECT  22.673 82.128 22.693 82.632 ;
     RECT  22.529 39.36 22.745 43.176 ;
     RECT  22.693 82.128 22.781 82.824 ;
     RECT  22.633 20.448 22.787 20.472 ;
     RECT  22.781 82.272 22.787 82.824 ;
     RECT  22.787 82.8 22.817 82.824 ;
     RECT  22.789 85.488 22.844 85.512 ;
     RECT  22.745 39.744 22.853 43.176 ;
     RECT  22.163 65.904 22.853 66.36 ;
     RECT  21.989 45.264 22.889 62.712 ;
     RECT  22.853 65.904 22.921 66.312 ;
     RECT  22.844 85.488 22.93 85.56 ;
     RECT  22.777 71.232 22.933 71.256 ;
     RECT  21.881 72.672 22.933 72.936 ;
     RECT  22.565 3.84 22.957 3.864 ;
     RECT  22.643 27.936 22.961 29.016 ;
     RECT  22.933 71.232 22.979 72.936 ;
     RECT  22.355 25.248 22.981 26.04 ;
     RECT  22.921 65.568 23.005 66.312 ;
     RECT  21.409 9.648 23.027 9.672 ;
     RECT  22.241 17.472 23.027 18.024 ;
     RECT  22.961 28.032 23.029 29.016 ;
     RECT  22.355 30.192 23.029 30.216 ;
     RECT  21.737 36.096 23.029 36.12 ;
     RECT  22.93 85.488 23.029 85.608 ;
     RECT  23.005 66.288 23.041 66.312 ;
     RECT  22.549 23.376 23.173 24.12 ;
     RECT  23.173 22.8 23.245 24.12 ;
     RECT  22.981 25.2 23.245 26.04 ;
     RECT  23.269 83.808 23.365 83.832 ;
     RECT  23.029 35.424 23.413 36.12 ;
     RECT  22.643 103.392 23.461 103.464 ;
     RECT  23.461 103.392 23.533 103.512 ;
     RECT  22.889 45.552 23.557 62.712 ;
     RECT  23.468 78.24 23.605 78.264 ;
     RECT  23.533 103.392 23.617 103.56 ;
     RECT  23.365 83.808 23.677 83.88 ;
     RECT  23.557 45.552 23.68 62.76 ;
     RECT  23.269 33.648 23.797 33.672 ;
     RECT  23.413 35.328 23.797 36.12 ;
     RECT  21.737 31.632 23.845 31.656 ;
     RECT  23.845 31.536 23.857 31.656 ;
     RECT  22.957 3.84 23.893 3.912 ;
     RECT  23.68 45.552 23.929 62.808 ;
     RECT  23.605 78.24 23.929 78.696 ;
     RECT  23.617 103.392 23.941 103.512 ;
     RECT  20.357 0.096 23.965 0.552 ;
     RECT  23.324 74.64 24.001 74.664 ;
     RECT  23.893 3.696 24.008 3.912 ;
     RECT  23.137 17.088 24.008 17.112 ;
     RECT  23.245 22.8 24.008 26.04 ;
     RECT  23.029 28.032 24.008 30.216 ;
     RECT  23.857 31.296 24.008 31.656 ;
     RECT  23.797 33.648 24.008 36.12 ;
     RECT  21.589 37.44 24.008 37.464 ;
     RECT  22.853 39.792 24.008 43.176 ;
     RECT  23.929 45.552 24.008 63.096 ;
     RECT  22.979 72.144 24.008 72.936 ;
     RECT  24.001 74.592 24.008 74.664 ;
     RECT  23.929 78.24 24.008 79.224 ;
     RECT  23.677 83.184 24.008 83.88 ;
     RECT  23.029 85.488 24.008 86.04 ;
     RECT  24.008 2.148 24.037 100.992 ;
     RECT  23.929 102.048 24.083 102.072 ;
     RECT  23.965 0.096 24.133 0.6 ;
     RECT  24.037 1.728 24.133 100.992 ;
     RECT  23.941 103.248 24.133 103.512 ;
     RECT  24.133 0.096 24.2 100.992 ;
     RECT  24.2 0.096 24.304 101.496 ;
     RECT  24.304 101.376 24.371 101.496 ;
     RECT  24.304 23.136 24.419 26.04 ;
     RECT  24.304 28.176 24.419 36.12 ;
     RECT  24.304 59.568 24.419 63.528 ;
     RECT  24.133 103.152 24.467 103.512 ;
     RECT  24.371 101.472 24.509 101.496 ;
     RECT  24.419 61.2 24.515 63.528 ;
     RECT  24.467 103.248 24.515 103.272 ;
     RECT  24.515 61.2 24.581 62.616 ;
     RECT  24.581 61.344 24.617 62.616 ;
     RECT  24.617 61.344 24.659 62.472 ;
     RECT  24.304 68.976 24.659 69 ;
     RECT  24.419 24.096 24.689 26.04 ;
     RECT  24.419 30.24 24.689 36.12 ;
     RECT  24.659 61.344 24.689 62.232 ;
     RECT  24.304 71.808 24.7 74.616 ;
     RECT  24.304 77.52 24.707 77.544 ;
     RECT  24.689 33.648 24.755 36.12 ;
     RECT  24.689 61.344 24.761 62.04 ;
     RECT  24.419 59.568 24.869 60.12 ;
     RECT  24.304 6.288 24.941 6.312 ;
     RECT  24.419 28.176 24.941 29.112 ;
     RECT  24.304 44.4 24.941 58.104 ;
     RECT  24.304 0.096 25.043 2.424 ;
     RECT  24.7 71.808 25.085 72.792 ;
     RECT  24.869 59.904 25.121 60.12 ;
     RECT  24.304 80.4 25.165 80.952 ;
     RECT  24.304 78.624 25.273 79.224 ;
     RECT  24.7 74.064 25.297 74.616 ;
     RECT  24.941 58.08 25.301 58.104 ;
     RECT  24.941 28.176 25.333 28.2 ;
     RECT  24.304 66.672 25.369 66.696 ;
     RECT  25.273 79.056 25.468 79.224 ;
     RECT  25.369 66.576 25.481 66.696 ;
     RECT  24.689 25.056 25.523 26.04 ;
     RECT  25.468 79.2 25.523 79.224 ;
     RECT  24.304 41.232 25.525 43.08 ;
     RECT  25.525 41.232 25.573 43.368 ;
     RECT  24.941 44.4 25.573 56.472 ;
     RECT  24.761 61.344 25.589 61.8 ;
     RECT  25.405 70.704 25.625 70.728 ;
     RECT  25.043 0.096 25.633 1.752 ;
     RECT  24.755 33.648 25.697 34.776 ;
     RECT  25.297 74.064 25.715 74.712 ;
     RECT  24.689 30.24 25.813 32.472 ;
     RECT  25.628 79.248 25.848 79.272 ;
     RECT  25.848 79.248 25.849 79.32 ;
     RECT  25.333 27.744 25.913 28.2 ;
     RECT  25.633 0.096 25.921 1.224 ;
     RECT  25.849 79.296 25.945 79.32 ;
     RECT  25.165 80.4 25.945 80.424 ;
     RECT  25.945 79.296 25.948 80.424 ;
     RECT  25.523 26.016 25.955 26.04 ;
     RECT  25.121 59.952 25.955 60.12 ;
     RECT  25.477 58.704 25.985 58.824 ;
     RECT  25.913 27.936 26.005 28.2 ;
     RECT  25.573 41.232 26.005 56.472 ;
     RECT  25.921 0.096 26.029 0.6 ;
     RECT  26.005 41.232 26.093 57.048 ;
     RECT  25.955 59.952 26.099 59.976 ;
     RECT  25.697 34.272 26.101 34.776 ;
     RECT  24.304 37.44 26.101 37.464 ;
     RECT  26.101 37.44 26.125 38.472 ;
     RECT  25.589 61.584 26.125 61.8 ;
     RECT  25.948 79.728 26.137 80.424 ;
     RECT  26.093 41.232 26.147 56.472 ;
     RECT  26.125 61.584 26.165 62.328 ;
     RECT  25.085 71.904 26.197 72.792 ;
     RECT  26.117 81.456 26.201 81.48 ;
     RECT  26.005 27.936 26.237 29.112 ;
     RECT  25.715 74.592 26.237 74.712 ;
     RECT  26.165 61.632 26.243 62.328 ;
     RECT  26.101 34.272 26.27 34.824 ;
     RECT  26.27 34.272 26.273 34.776 ;
     RECT  26.137 80.4 26.331 80.424 ;
     RECT  26.273 34.752 26.387 34.776 ;
     RECT  26.331 80.4 26.437 80.472 ;
     RECT  26.237 29.088 26.485 29.112 ;
     RECT  25.813 30.24 26.485 30.264 ;
     RECT  26.437 80.4 26.524 80.568 ;
     RECT  26.485 29.088 26.525 30.264 ;
     RECT  26.525 29.616 26.561 30.264 ;
     RECT  26.485 75.792 26.581 75.816 ;
     RECT  26.197 59.184 26.605 59.304 ;
     RECT  26.485 58.128 26.629 58.152 ;
     RECT  26.524 80.4 26.669 80.424 ;
     RECT  26.485 103.488 26.674 103.512 ;
     RECT  26.629 57.6 26.713 58.152 ;
     RECT  26.125 37.44 26.773 38.76 ;
     RECT  26.197 71.904 26.813 73.56 ;
     RECT  26.237 27.936 26.832 27.96 ;
     RECT  26.147 41.232 26.953 55.848 ;
     RECT  26.713 58.128 26.953 58.152 ;
     RECT  25.813 31.392 26.965 32.472 ;
     RECT  26.581 74.976 27.02 75.816 ;
     RECT  27.02 74.976 27.059 76.104 ;
     RECT  26.674 103.44 27.061 103.56 ;
     RECT  27.061 103.344 27.133 103.56 ;
     RECT  26.813 73.536 27.205 73.56 ;
     RECT  26.953 41.04 27.277 55.848 ;
     RECT  27.059 75.264 27.529 76.104 ;
     RECT  26.953 58.128 27.569 58.728 ;
     RECT  27.529 75.264 27.596 76.152 ;
     RECT  26.561 29.616 27.605 29.736 ;
     RECT  27.569 58.704 27.605 58.728 ;
     RECT  27.596 75.264 27.673 76.296 ;
     RECT  24.755 35.856 27.817 36.12 ;
     RECT  27.637 59.28 27.845 59.304 ;
     RECT  27.817 60.432 27.845 60.456 ;
     RECT  26.243 62.304 27.884 62.328 ;
     RECT  26.965 31.296 27.925 32.472 ;
     RECT  27.673 75.264 27.929 76.392 ;
     RECT  27.133 103.248 27.929 103.56 ;
     RECT  27.781 29.088 27.965 29.112 ;
     RECT  27.884 62.304 27.971 63.24 ;
     RECT  27.929 75.792 27.973 76.392 ;
     RECT  27.929 103.248 27.997 103.512 ;
     RECT  27.205 73.536 28.069 73.8 ;
     RECT  27.277 41.04 28.105 56.136 ;
     RECT  27.845 59.28 28.141 60.456 ;
     RECT  27.817 35.712 28.213 36.12 ;
     RECT  28.141 59.28 28.259 61.176 ;
     RECT  26.813 71.904 28.261 72.216 ;
     RECT  27.971 62.304 28.307 62.328 ;
     RECT  28.22 63.696 28.307 63.72 ;
     RECT  28.261 71.904 28.307 72.456 ;
     RECT  28.259 59.28 28.325 60.456 ;
     RECT  28.325 59.28 28.333 59.88 ;
     RECT  28.213 34.8 28.361 36.12 ;
     RECT  28.105 40.608 28.397 56.136 ;
     RECT  27.973 75.792 28.853 76.632 ;
     RECT  28.853 75.792 28.861 76.824 ;
     RECT  27.997 103.152 28.933 103.512 ;
     RECT  28.933 103.152 29.017 103.56 ;
     RECT  26.773 37.44 29.069 39.336 ;
     RECT  28.397 40.608 29.069 55.272 ;
     RECT  28.861 75.792 29.077 76.92 ;
     RECT  26.029 0.096 29.117 0.552 ;
     RECT  29.125 6.816 29.173 6.84 ;
     RECT  29.173 3.504 29.221 3.528 ;
     RECT  29.117 0.144 29.225 0.552 ;
     RECT  29.225 0.24 29.363 0.552 ;
     RECT  29.365 2.016 29.408 2.04 ;
     RECT  29.221 3.408 29.408 3.528 ;
     RECT  29.173 6.72 29.408 6.84 ;
     RECT  29.173 20.064 29.408 20.088 ;
     RECT  29.269 21.408 29.408 21.432 ;
     RECT  27.925 30.192 29.408 32.472 ;
     RECT  28.361 35.712 29.408 36.12 ;
     RECT  29.069 37.44 29.408 55.272 ;
     RECT  28.333 59.856 29.408 59.88 ;
     RECT  28.307 72.432 29.408 72.456 ;
     RECT  28.069 73.536 29.408 74.712 ;
     RECT  29.077 75.792 29.408 77.448 ;
     RECT  29.257 101.376 29.408 101.4 ;
     RECT  29.017 103.152 29.459 103.512 ;
     RECT  29.363 0.336 29.555 0.552 ;
     RECT  29.459 103.2 29.555 103.512 ;
     RECT  29.555 0.384 29.651 0.552 ;
     RECT  29.408 2.016 29.651 101.4 ;
     RECT  29.651 2.016 29.704 101.262 ;
     RECT  29.704 20.064 29.765 20.088 ;
     RECT  29.701 0.576 29.797 0.6 ;
     RECT  29.555 103.248 29.801 103.512 ;
     RECT  29.704 40.608 29.973 55.272 ;
     RECT  29.973 40.608 29.981 55.176 ;
     RECT  29.704 75.648 29.981 78.12 ;
     RECT  29.981 40.608 30.017 53.736 ;
     RECT  29.981 75.648 30.035 77.496 ;
     RECT  29.704 15.408 30.053 15.432 ;
     RECT  29.704 16.56 30.125 17.112 ;
     RECT  29.704 4.512 30.131 4.536 ;
     RECT  30.035 76.896 30.133 77.496 ;
     RECT  29.801 103.296 30.181 103.512 ;
     RECT  30.133 76.896 30.227 77.112 ;
     RECT  29.704 18.24 30.233 18.264 ;
     RECT  29.981 54.816 30.233 55.176 ;
     RECT  29.704 2.016 30.257 2.28 ;
     RECT  30.035 75.648 30.323 75.672 ;
     RECT  30.017 40.656 30.413 53.736 ;
     RECT  29.704 79.824 30.419 80.376 ;
     RECT  29.704 91.152 30.493 91.176 ;
     RECT  30.419 80.304 30.521 80.376 ;
     RECT  30.521 80.304 30.629 80.328 ;
     RECT  29.797 0.576 30.757 0.648 ;
     RECT  29.704 37.44 30.769 38.568 ;
     RECT  30.413 40.656 30.773 42.744 ;
     RECT  30.757 0.288 30.805 0.648 ;
     RECT  30.257 1.728 30.805 2.28 ;
     RECT  29.704 35.712 30.809 36.12 ;
     RECT  30.769 37.44 30.809 39.336 ;
     RECT  30.413 43.968 30.809 53.544 ;
     RECT  29.704 72.432 30.809 72.456 ;
     RECT  30.805 0.288 30.833 2.28 ;
     RECT  30.805 78.672 30.841 78.696 ;
     RECT  30.733 89.952 30.841 89.976 ;
     RECT  30.125 17.088 30.881 17.112 ;
     RECT  30.809 43.968 30.881 53.496 ;
     RECT  30.841 78.672 30.947 78.792 ;
     RECT  29.704 31.632 30.989 32.472 ;
     RECT  30.227 76.896 30.997 76.92 ;
     RECT  29.704 74.592 31.045 74.616 ;
     RECT  29.704 97.056 31.045 97.56 ;
     RECT  30.809 35.712 31.091 36.024 ;
     RECT  30.881 45.792 31.139 53.496 ;
     RECT  31.045 74.592 31.241 74.712 ;
     RECT  31.139 45.792 31.277 53.064 ;
     RECT  30.833 0.096 31.283 2.28 ;
     RECT  30.947 78.672 31.321 78.696 ;
     RECT  31.045 21.12 31.385 21.144 ;
     RECT  31.277 45.984 31.385 53.064 ;
     RECT  31.241 74.592 31.421 74.616 ;
     RECT  30.181 103.296 31.429 103.56 ;
     RECT  31.385 45.984 31.457 47.352 ;
     RECT  30.841 89.952 31.475 90.6 ;
     RECT  30.233 54.912 31.525 55.176 ;
     RECT  31.457 45.984 31.565 46.92 ;
     RECT  31.517 80.88 31.669 80.952 ;
     RECT  31.283 0.096 31.673 1.176 ;
     RECT  31.525 2.304 31.708 2.328 ;
     RECT  31.345 77.424 31.763 77.496 ;
     RECT  31.429 103.152 31.763 103.56 ;
     RECT  31.525 54.672 31.817 55.176 ;
     RECT  30.881 43.968 31.889 44.424 ;
     RECT  31.091 36 31.921 36.024 ;
     RECT  30.809 37.536 31.921 39.336 ;
     RECT  31.708 2.304 31.925 2.376 ;
     RECT  31.669 80.784 31.925 80.952 ;
     RECT  31.993 78.048 32.077 78.648 ;
     RECT  31.889 44.352 32.105 44.424 ;
     RECT  31.385 48.384 32.141 53.064 ;
     RECT  32.077 78.24 32.195 78.648 ;
     RECT  32.141 50.304 32.245 53.064 ;
     RECT  31.763 103.392 32.291 103.56 ;
     RECT  32.195 78.48 32.293 78.648 ;
     RECT  32.291 103.488 32.294 103.56 ;
     RECT  31.673 0.576 32.339 1.176 ;
     RECT  32.065 34.848 32.357 34.872 ;
     RECT  32.245 50.304 32.393 53.256 ;
     RECT  32.294 103.488 32.393 103.512 ;
     RECT  31.345 7.392 32.435 7.416 ;
     RECT  31.475 89.952 32.437 90.552 ;
     RECT  31.045 96.912 32.437 97.56 ;
     RECT  31.565 46.224 32.461 46.92 ;
     RECT  32.389 44.448 32.473 44.472 ;
     RECT  31.817 54.672 32.497 54.696 ;
     RECT  32.461 46.224 32.501 47.352 ;
     RECT  32.293 78.48 32.501 78.504 ;
     RECT  32.437 89.856 32.524 90.552 ;
     RECT  32.393 50.352 32.533 53.256 ;
     RECT  32.497 54.624 32.533 54.696 ;
     RECT  32.453 98.592 32.537 98.616 ;
     RECT  32.485 6.864 32.573 6.888 ;
     RECT  32.533 50.352 32.609 54.696 ;
     RECT  32.497 1.68 32.627 2.28 ;
     RECT  32.609 50.88 32.653 54.696 ;
     RECT  32.581 80.352 32.677 80.376 ;
     RECT  32.677 80.304 32.681 80.376 ;
     RECT  32.627 1.728 32.723 2.28 ;
     RECT  32.339 0.576 32.741 0.6 ;
     RECT  31.921 36 32.828 39.336 ;
     RECT  32.828 35.952 32.869 39.336 ;
     RECT  32.437 96.336 32.869 97.56 ;
     RECT  32.653 54.672 32.897 54.696 ;
     RECT  32.681 80.304 32.897 80.328 ;
     RECT  32.857 88.896 32.941 88.92 ;
     RECT  32.501 46.224 32.965 46.248 ;
     RECT  32.741 0.096 33.005 0.6 ;
     RECT  32.965 46.128 33.005 46.248 ;
     RECT  32.869 35.472 33.037 39.336 ;
     RECT  32.501 47.328 33.257 47.352 ;
     RECT  33.037 35.472 33.325 39.576 ;
     RECT  33.005 46.128 33.329 46.152 ;
     RECT  33.325 102.048 33.361 102.072 ;
     RECT  32.723 1.728 33.365 1.752 ;
     RECT  32.653 50.88 33.365 53.256 ;
     RECT  33.361 102.048 33.397 102.744 ;
     RECT  33.397 101.472 33.469 102.744 ;
     RECT  33.469 101.472 33.533 102.792 ;
     RECT  33.365 51.216 33.689 53.064 ;
     RECT  32.869 95.904 33.865 97.56 ;
     RECT  33.005 0.096 33.98 0.504 ;
     RECT  33.865 95.904 34.165 97.608 ;
     RECT  33.325 35.472 34.189 39.624 ;
     RECT  30.773 40.656 34.189 42.6 ;
     RECT  32.141 48.672 34.333 48.936 ;
     RECT  34.189 35.472 34.477 42.6 ;
     RECT  30.989 31.632 34.808 32.232 ;
     RECT  34.477 34.8 34.808 42.744 ;
     RECT  34.333 48.672 34.808 49.224 ;
     RECT  33.689 51.264 34.808 53.064 ;
     RECT  32.524 89.952 34.808 90.552 ;
     RECT  34.477 91.728 34.808 91.752 ;
     RECT  34.165 95.904 34.808 97.944 ;
     RECT  33.533 101.472 34.808 103.56 ;
     RECT  34.808 2.148 34.912 103.56 ;
     RECT  34.912 2.418 34.931 103.56 ;
     RECT  34.931 2.418 35.027 101.496 ;
     RECT  35.027 2.418 35.104 101.262 ;
     RECT  34.931 102.624 35.123 103.56 ;
     RECT  35.104 95.904 35.129 97.944 ;
     RECT  35.104 31.728 35.281 42.84 ;
     RECT  33.98 0.096 35.365 0.552 ;
     RECT  35.104 2.832 35.507 2.856 ;
     RECT  35.365 0.096 35.629 0.6 ;
     RECT  35.629 0.096 35.653 1.128 ;
     RECT  35.653 0.096 35.741 1.176 ;
     RECT  35.741 0.096 35.891 1.128 ;
     RECT  35.891 0.096 35.987 1.08 ;
     RECT  35.104 52.704 36.029 52.728 ;
     RECT  35.123 102.672 36.097 103.56 ;
     RECT  35.281 31.728 36.131 42.744 ;
     RECT  35.104 9.024 36.133 9.048 ;
     RECT  35.104 44.112 36.133 44.28 ;
     RECT  35.129 96.288 36.205 97.944 ;
     RECT  36.133 4.56 36.245 4.584 ;
     RECT  36.133 9.024 36.275 9.096 ;
     RECT  36.241 46.704 36.353 46.728 ;
     RECT  36.097 102.624 36.421 103.56 ;
     RECT  36.325 21.648 36.461 21.672 ;
     RECT  35.104 48.672 36.461 49.176 ;
     RECT  36.275 9.024 36.467 9.048 ;
     RECT  36.493 5.664 36.565 5.688 ;
     RECT  36.421 102.048 36.569 103.56 ;
     RECT  36.131 33.12 36.637 42.744 ;
     RECT  36.565 5.616 36.659 5.688 ;
     RECT  35.987 0.096 36.851 0.552 ;
     RECT  36.637 33.12 36.853 43.08 ;
     RECT  36.133 44.112 36.853 45.192 ;
     RECT  36.601 6.816 36.947 6.84 ;
     RECT  36.659 5.616 37.033 5.64 ;
     RECT  37.033 5.088 37.043 5.64 ;
     RECT  36.205 96.288 37.043 98.04 ;
     RECT  37.043 5.088 37.235 5.112 ;
     RECT  37.033 99.168 37.331 99.192 ;
     RECT  36.853 33.12 37.501 45.192 ;
     RECT  36.385 100.896 37.609 100.92 ;
     RECT  37.285 9.072 37.619 9.096 ;
     RECT  37.609 100.32 37.645 100.92 ;
     RECT  36.851 0.096 37.82 0.168 ;
     RECT  36.569 102.048 37.861 102.696 ;
     RECT  37.82 0.096 37.907 0.552 ;
     RECT  37.043 97.008 37.907 98.04 ;
     RECT  36.131 31.728 38.005 31.752 ;
     RECT  37.501 32.736 38.005 45.192 ;
     RECT  36.461 49.152 38.051 49.176 ;
     RECT  37.645 99.744 38.195 100.92 ;
     RECT  37.907 0.096 38.297 0.216 ;
     RECT  38.297 0.096 38.369 0.12 ;
     RECT  38.005 31.728 38.405 45.192 ;
     RECT  37.907 97.008 38.725 97.464 ;
     RECT  38.725 96.912 38.881 97.464 ;
     RECT  38.881 96.912 38.945 96.936 ;
     RECT  38.195 100.368 39.059 100.92 ;
     RECT  37.861 102.048 39.109 102.792 ;
     RECT  39.013 3.408 39.155 3.432 ;
     RECT  38.405 31.824 39.229 45.192 ;
     RECT  39.185 2.88 39.337 2.952 ;
     RECT  39.109 102.048 39.635 103.512 ;
     RECT  39.337 2.256 39.685 2.952 ;
     RECT  39.685 68.928 39.733 68.952 ;
     RECT  39.229 31.824 39.805 45.576 ;
     RECT  39.733 68.448 39.829 68.952 ;
     RECT  39.877 87.648 39.925 87.672 ;
     RECT  39.635 102.528 39.941 103.512 ;
     RECT  39.925 0.672 39.949 0.696 ;
     RECT  39.949 0.528 39.973 0.696 ;
     RECT  39.685 1.728 39.973 2.952 ;
     RECT  39.877 13.104 39.973 13.128 ;
     RECT  39.973 0.528 40.021 2.952 ;
     RECT  39.985 18.768 40.021 18.792 ;
     RECT  39.941 102.528 40.025 103.56 ;
     RECT  40.021 17.184 40.069 17.208 ;
     RECT  39.805 31.2 40.093 45.576 ;
     RECT  40.021 0.144 40.208 2.952 ;
     RECT  39.925 5.712 40.208 5.736 ;
     RECT  39.973 13.104 40.208 13.224 ;
     RECT  39.26 14.784 40.208 14.808 ;
     RECT  40.069 17.088 40.208 17.64 ;
     RECT  40.021 18.72 40.208 18.792 ;
     RECT  40.093 31.2 40.208 45.72 ;
     RECT  39.829 68.4 40.208 68.952 ;
     RECT  39.925 87.648 40.208 87.768 ;
     RECT  38.684 90.576 40.208 90.6 ;
     RECT  38.761 92.928 40.208 92.952 ;
     RECT  37.069 95.76 40.208 95.784 ;
     RECT  39.059 100.896 40.208 100.92 ;
     RECT  40.208 0.144 40.307 100.992 ;
     RECT  40.307 1.152 40.312 100.992 ;
     RECT  40.312 2.418 40.4 100.992 ;
     RECT  40.025 102.528 40.403 103.512 ;
     RECT  40.4 2.418 40.504 101.4 ;
     RECT  40.312 1.152 40.565 1.224 ;
     RECT  40.504 101.376 40.601 101.4 ;
     RECT  40.565 1.2 40.673 1.224 ;
     RECT  40.504 30.864 40.681 46.2 ;
     RECT  40.403 102.96 40.691 103.512 ;
     RECT  40.504 6.864 40.853 6.888 ;
     RECT  40.504 10.848 40.889 10.872 ;
     RECT  40.504 17.664 40.979 19.368 ;
     RECT  40.691 103.104 41.027 103.512 ;
     RECT  40.504 2.832 41.075 2.856 ;
     RECT  40.307 0.144 41.093 0.168 ;
     RECT  41.027 103.152 41.093 103.512 ;
     RECT  41.093 0.096 41.177 0.168 ;
     RECT  40.979 18.72 41.321 19.368 ;
     RECT  40.504 68.4 41.321 70.248 ;
     RECT  40.504 4.56 41.429 4.584 ;
     RECT  41.321 18.768 41.459 19.368 ;
     RECT  40.681 30.864 41.537 46.152 ;
     RECT  41.321 68.976 41.557 70.248 ;
     RECT  41.537 30.864 41.569 31.224 ;
     RECT  41.177 0.144 41.597 0.168 ;
     RECT  41.459 18.768 41.645 18.888 ;
     RECT  41.597 0.144 41.701 0.6 ;
     RECT  40.979 17.664 41.753 17.736 ;
     RECT  41.701 0.144 41.788 1.176 ;
     RECT  41.753 17.664 41.825 17.688 ;
     RECT  41.557 20.544 41.861 20.568 ;
     RECT  41.569 30.72 41.939 31.224 ;
     RECT  41.645 18.816 42.041 18.888 ;
     RECT  41.557 68.976 42.077 70.776 ;
     RECT  42.077 69.552 42.085 70.776 ;
     RECT  42.041 18.864 42.149 18.888 ;
     RECT  41.788 0.144 42.173 1.224 ;
     RECT  41.093 103.152 42.181 103.56 ;
     RECT  42.173 0.096 42.545 1.224 ;
     RECT  42.085 69.552 42.565 70.824 ;
     RECT  42.545 0.96 42.611 1.224 ;
     RECT  42.181 102.768 42.617 103.56 ;
     RECT  42.613 19.104 42.641 19.128 ;
     RECT  41.537 32.448 42.653 46.152 ;
     RECT  42.641 19.104 42.725 19.992 ;
     RECT  41.939 30.72 42.757 30.936 ;
     RECT  42.757 30.672 42.761 30.936 ;
     RECT  42.611 1.056 42.853 1.224 ;
     RECT  42.853 1.056 42.949 1.752 ;
     RECT  42.757 91.2 42.995 91.224 ;
     RECT  42.725 19.104 43.049 19.128 ;
     RECT  42.653 33.072 43.157 46.152 ;
     RECT  43.045 21.12 43.187 21.144 ;
     RECT  42.949 1.056 43.229 2.328 ;
     RECT  42.565 69.552 43.237 70.872 ;
     RECT  42.761 30.672 43.265 30.888 ;
     RECT  43.229 1.056 43.301 1.176 ;
     RECT  43.292 100.896 43.369 100.92 ;
     RECT  43.237 70.128 43.373 70.872 ;
     RECT  43.369 100.32 43.379 100.92 ;
     RECT  43.229 2.304 43.408 2.328 ;
     RECT  43.408 2.304 43.409 2.376 ;
     RECT  43.373 70.176 43.441 70.872 ;
     RECT  43.379 100.32 43.475 100.344 ;
     RECT  43.409 2.352 43.589 2.376 ;
     RECT  43.157 33.072 43.589 46.056 ;
     RECT  43.525 17.664 43.621 17.688 ;
     RECT  43.589 33.072 43.657 33.816 ;
     RECT  43.621 17.664 43.717 17.736 ;
     RECT  42.617 103.344 43.717 103.56 ;
     RECT  43.657 32.496 43.733 33.816 ;
     RECT  43.265 30.672 43.841 30.744 ;
     RECT  43.717 103.248 43.868 103.56 ;
     RECT  43.717 17.664 43.913 17.784 ;
     RECT  43.441 70.176 43.913 71.256 ;
     RECT  43.868 102.624 43.955 103.56 ;
     RECT  43.913 17.712 43.985 17.784 ;
     RECT  43.909 13.104 44.005 13.128 ;
     RECT  43.589 34.8 44.021 45.96 ;
     RECT  43.981 88.32 44.053 88.344 ;
     RECT  44.005 13.104 44.057 13.176 ;
     RECT  43.985 17.76 44.057 17.784 ;
     RECT  44.057 13.152 44.101 13.176 ;
     RECT  43.913 70.704 44.101 71.256 ;
     RECT  44.101 70.704 44.108 71.496 ;
     RECT  44.053 88.224 44.137 88.344 ;
     RECT  43.841 30.72 44.165 30.744 ;
     RECT  44.101 13.152 44.201 13.224 ;
     RECT  43.955 102.96 44.243 103.56 ;
     RECT  43.813 19.392 44.293 19.416 ;
     RECT  44.201 13.2 44.309 13.224 ;
     RECT  44.021 34.8 44.345 45.576 ;
     RECT  44.293 19.392 44.389 19.992 ;
     RECT  44.341 21.792 44.435 21.816 ;
     RECT  44.137 88.32 44.435 88.344 ;
     RECT  44.449 4.512 44.485 4.536 ;
     RECT  44.197 0.576 44.557 0.6 ;
     RECT  44.389 19.392 44.561 20.088 ;
     RECT  44.345 36.48 44.561 45.576 ;
     RECT  44.243 103.344 44.561 103.56 ;
     RECT  44.561 36.672 44.597 45.576 ;
     RECT  44.485 3.984 44.627 4.536 ;
     RECT  44.108 70.704 44.629 71.784 ;
     RECT  44.557 0.576 44.657 1.128 ;
     RECT  44.629 90.048 44.665 90.072 ;
     RECT  44.629 70.704 44.725 71.832 ;
     RECT  44.345 34.8 44.881 35.496 ;
     RECT  44.725 70.704 45.061 72.408 ;
     RECT  44.657 0.576 45.097 1.176 ;
     RECT  45.097 0.528 45.125 1.176 ;
     RECT  45.125 0.144 45.233 1.176 ;
     RECT  44.561 103.344 45.277 103.512 ;
     RECT  44.737 2.256 45.608 2.28 ;
     RECT  44.627 3.984 45.608 4.008 ;
     RECT  44.561 19.392 45.608 19.416 ;
     RECT  44.965 20.544 45.608 20.568 ;
     RECT  43.733 32.496 45.608 33.096 ;
     RECT  44.881 34.368 45.608 35.496 ;
     RECT  44.597 36.912 45.608 45.576 ;
     RECT  45.061 70.704 45.608 72.936 ;
     RECT  44.665 89.52 45.608 90.072 ;
     RECT  45.277 102.624 45.637 103.512 ;
     RECT  45.233 0.096 45.785 1.176 ;
     RECT  45.608 2.148 45.8 100.992 ;
     RECT  45.8 2.148 45.904 101.262 ;
     RECT  45.904 3.408 46.019 3.96 ;
     RECT  45.785 0.096 46.067 0.36 ;
     RECT  46.019 3.408 46.073 3.432 ;
     RECT  45.637 102.624 46.073 103.56 ;
     RECT  45.904 5.04 46.163 5.064 ;
     RECT  45.904 38.64 46.163 43.128 ;
     RECT  45.904 72.816 46.259 74.088 ;
     RECT  45.904 2.148 46.309 2.28 ;
     RECT  46.259 73.104 46.355 74.088 ;
     RECT  45.904 98.64 46.451 98.664 ;
     RECT  46.355 73.488 46.549 74.088 ;
     RECT  46.067 0.096 46.577 0.168 ;
     RECT  45.904 15.984 46.721 16.008 ;
     RECT  46.309 1.728 46.739 2.28 ;
     RECT  46.739 1.728 46.748 1.8 ;
     RECT  45.904 37.44 46.757 37.608 ;
     RECT  46.163 38.688 46.829 43.128 ;
     RECT  45.904 44.352 46.829 44.376 ;
     RECT  46.748 1.68 46.885 1.8 ;
     RECT  45.904 35.328 47.045 35.352 ;
     RECT  46.933 46.704 47.117 46.728 ;
     RECT  46.757 37.584 47.185 37.608 ;
     RECT  46.829 38.688 47.185 42.792 ;
     RECT  46.885 1.152 47.297 1.8 ;
     RECT  47.293 7.968 47.329 7.992 ;
     RECT  46.073 102.624 47.365 103.512 ;
     RECT  46.549 74.064 47.564 74.088 ;
     RECT  45.904 32.496 47.585 32.52 ;
     RECT  47.329 7.872 47.699 7.992 ;
     RECT  47.564 74.064 47.737 74.424 ;
     RECT  46.577 0.096 47.761 0.12 ;
     RECT  47.297 1.152 47.761 1.704 ;
     RECT  47.185 37.584 47.801 42.792 ;
     RECT  47.801 40.944 47.825 42.792 ;
     RECT  47.699 7.872 47.891 7.896 ;
     RECT  47.825 40.944 47.909 43.368 ;
     RECT  47.9 74.592 47.977 74.616 ;
     RECT  47.977 74.592 47.987 75.24 ;
     RECT  47.987 75.216 48.061 75.24 ;
     RECT  47.941 98.64 48.179 98.664 ;
     RECT  47.761 0.096 48.371 1.704 ;
     RECT  47.545 44.448 48.38 44.472 ;
     RECT  48.38 14.208 48.467 14.232 ;
     RECT  47.801 37.68 48.485 39.912 ;
     RECT  48.38 44.208 48.485 44.472 ;
     RECT  48.371 1.152 48.659 1.704 ;
     RECT  48.371 0.096 48.773 0.12 ;
     RECT  47.909 40.944 48.803 43.224 ;
     RECT  48.485 37.68 48.845 38.232 ;
     RECT  48.803 40.944 48.881 41.64 ;
     RECT  45.904 45.456 48.917 45.48 ;
     RECT  48.659 1.152 48.989 1.176 ;
     RECT  48.805 17.664 48.989 17.688 ;
     RECT  48.085 2.832 48.997 2.856 ;
     RECT  48.845 38.064 49.061 38.184 ;
     RECT  48.485 39.456 49.061 39.912 ;
     RECT  48.997 2.832 49.093 3.432 ;
     RECT  48.803 42.672 49.133 43.224 ;
     RECT  49.093 2.304 49.205 3.432 ;
     RECT  48.881 41.136 49.205 41.64 ;
     RECT  49.165 71.808 49.273 71.832 ;
     RECT  49.061 38.064 49.331 38.136 ;
     RECT  49.133 42.72 49.381 43.224 ;
     RECT  48.485 44.208 49.381 44.28 ;
     RECT  49.331 38.112 49.385 38.136 ;
     RECT  49.205 41.136 49.421 41.592 ;
     RECT  49.381 15.408 49.477 15.432 ;
     RECT  49.381 42.72 49.529 44.28 ;
     RECT  49.477 15.408 49.601 15.528 ;
     RECT  47.365 102.624 49.621 103.56 ;
     RECT  49.601 15.504 49.637 15.528 ;
     RECT  49.529 44.256 49.637 44.28 ;
     RECT  49.621 102.528 49.709 103.56 ;
     RECT  49.669 7.968 49.765 7.992 ;
     RECT  49.273 71.28 49.765 71.832 ;
     RECT  49.765 71.28 49.813 71.88 ;
     RECT  49.765 7.968 49.853 8.04 ;
     RECT  49.421 41.568 49.853 41.592 ;
     RECT  49.813 71.28 49.9 72.024 ;
     RECT  49.205 2.832 50.003 3.432 ;
     RECT  50.003 2.832 50.105 2.904 ;
     RECT  49.9 71.28 50.149 71.832 ;
     RECT  49.853 7.968 50.177 7.992 ;
     RECT  49.529 42.72 50.177 42.744 ;
     RECT  49.061 39.84 50.195 39.912 ;
     RECT  50.209 2.256 50.245 2.28 ;
     RECT  50.149 5.136 50.245 5.16 ;
     RECT  50.245 5.136 50.281 5.208 ;
     RECT  50.149 70.704 50.285 71.832 ;
     RECT  50.195 39.888 50.291 39.912 ;
     RECT  50.285 71.472 50.321 71.832 ;
     RECT  50.281 4.512 50.357 5.208 ;
     RECT  50.357 4.512 50.387 5.16 ;
     RECT  50.321 71.472 50.387 71.496 ;
     RECT  49.573 0.576 50.417 0.6 ;
     RECT  50.387 5.088 50.429 5.16 ;
     RECT  50.245 2.16 50.533 2.28 ;
     RECT  50.533 1.68 50.579 2.28 ;
     RECT  50.417 0.096 50.681 0.6 ;
     RECT  50.579 1.68 50.713 2.232 ;
     RECT  50.713 0.96 50.771 2.232 ;
     RECT  50.771 0.96 50.867 2.184 ;
     RECT  50.429 5.088 50.963 5.112 ;
     RECT  50.867 0.96 51.059 1.128 ;
     RECT  51.059 0.96 51.155 1.032 ;
     RECT  51.155 0.96 51.251 0.984 ;
     RECT  50.867 2.16 51.347 2.184 ;
     RECT  49.709 102.624 51.731 103.56 ;
     RECT  51.731 103.488 51.833 103.56 ;
     RECT  51.833 103.488 51.941 103.512 ;
    LAYER M5 ;
     RECT  0.72 0.016 51.336 0.227 ;
     RECT  0.72 0.227 37.896 0.563 ;
     RECT  35.376 0.563 37.608 0.611 ;
     RECT  22.704 0.563 26.76 1.235 ;
     RECT  0.72 0.563 20.232 1.763 ;
     RECT  22.704 1.235 25.608 1.763 ;
     RECT  29.136 0.563 33.192 1.763 ;
     RECT  13.008 1.763 20.232 1.811 ;
     RECT  35.472 0.611 37.608 2.137 ;
     RECT  0.816 1.763 11.4 2.195 ;
     RECT  39.12 0.227 51.336 2.195 ;
     RECT  0.816 2.195 10.824 2.291 ;
     RECT  29.136 1.763 32.712 2.291 ;
     RECT  39.12 2.195 50.952 2.291 ;
     RECT  22.704 1.763 25.032 2.435 ;
     RECT  34.8 2.137 37.608 2.867 ;
     RECT  0.912 2.291 9.864 2.915 ;
     RECT  16.08 1.811 19.032 2.915 ;
     RECT  16.752 2.915 17.064 2.963 ;
     RECT  17.04 2.963 17.064 3.011 ;
     RECT  18.288 2.915 19.032 3.059 ;
     RECT  18.384 3.059 19.032 3.155 ;
     RECT  1.2 2.915 9.864 3.443 ;
     RECT  18.6 3.155 19.032 3.443 ;
     RECT  20.016 1.811 20.232 3.443 ;
     RECT  39.12 2.291 46.632 3.443 ;
     RECT  20.208 3.443 20.232 3.971 ;
     RECT  1.392 3.443 9.768 4.595 ;
     RECT  36.144 2.867 37.608 4.595 ;
     RECT  1.968 4.595 9.768 4.691 ;
     RECT  47.664 2.291 50.952 5.123 ;
     RECT  47.664 5.123 50.28 5.219 ;
     RECT  2.4 4.691 9.768 5.363 ;
     RECT  13.008 1.811 14.472 5.797 ;
     RECT  21.264 0.563 21.288 5.941 ;
     RECT  12.624 5.797 14.472 6.229 ;
     RECT  22.704 2.435 24.84 6.323 ;
     RECT  29.136 2.291 32.52 6.851 ;
     RECT  36.24 4.595 37.608 6.851 ;
     RECT  20.832 5.941 21.288 6.899 ;
     RECT  29.184 6.851 32.52 6.899 ;
     RECT  29.184 6.899 32.424 7.427 ;
     RECT  47.664 5.219 50.088 8.003 ;
     RECT  48.432 8.003 49.8 8.051 ;
     RECT  7.8 5.363 9.768 8.579 ;
     RECT  36.24 6.851 36.456 9.059 ;
     RECT  19.92 7.333 19.944 9.061 ;
     RECT  21.072 6.899 21.288 9.061 ;
     RECT  36.24 9.059 36.36 9.107 ;
     RECT  37.584 6.851 37.608 9.107 ;
     RECT  2.4 5.363 6.792 9.155 ;
     RECT  4.944 9.155 6.792 9.203 ;
     RECT  19.92 9.061 21.288 9.637 ;
     RECT  7.8 8.579 9.72 10.213 ;
     RECT  2.4 9.155 3.912 10.355 ;
     RECT  5.616 9.203 6.792 10.883 ;
     RECT  6.096 10.883 6.792 10.931 ;
     RECT  6.192 10.931 6.792 10.979 ;
     RECT  19.92 9.637 21.672 11.413 ;
     RECT  22.704 6.323 24.312 11.413 ;
     RECT  6.288 10.979 6.792 11.749 ;
     RECT  7.8 10.213 9.816 11.749 ;
     RECT  6.288 11.749 9.816 12.035 ;
     RECT  6.432 12.035 9.816 13.043 ;
     RECT  18.6 3.443 18.912 13.477 ;
     RECT  19.92 11.413 24.312 13.477 ;
     RECT  48.432 8.051 49.512 14.243 ;
     RECT  2.4 10.355 3.096 14.485 ;
     RECT  7.632 13.043 9.816 14.485 ;
     RECT  39.312 3.443 46.632 14.819 ;
     RECT  48.816 14.243 49.512 15.539 ;
     RECT  11.712 6.229 14.472 15.925 ;
     RECT  40.032 14.819 46.632 16.019 ;
     RECT  4.8 12.757 4.824 17.077 ;
     RECT  6.432 13.043 6.456 17.077 ;
     RECT  7.584 14.485 9.816 17.077 ;
     RECT  40.032 16.019 45.912 17.219 ;
     RECT  48.816 15.539 48.84 17.699 ;
     RECT  40.08 17.219 45.912 17.747 ;
     RECT  43.728 17.747 45.912 17.795 ;
     RECT  2.4 14.485 3.672 17.989 ;
     RECT  29.184 7.427 31.08 18.275 ;
     RECT  40.08 17.747 40.968 18.709 ;
     RECT  2.4 17.989 3.768 18.757 ;
     RECT  4.8 17.077 6.456 18.757 ;
     RECT  40.032 18.709 40.968 18.757 ;
     RECT  42 17.747 42.696 18.757 ;
     RECT  40.032 18.757 42.696 18.899 ;
     RECT  18.6 13.477 24.312 19.141 ;
     RECT  43.824 17.795 45.912 19.427 ;
     RECT  7.584 17.077 10.344 19.813 ;
     RECT  2.4 18.757 6.456 19.909 ;
     RECT  42.624 18.899 42.696 20.003 ;
     RECT  44.304 19.427 45.912 20.003 ;
     RECT  29.184 18.275 29.712 20.099 ;
     RECT  44.4 20.003 45.912 20.099 ;
     RECT  2.304 19.909 6.456 20.197 ;
     RECT  7.536 19.813 10.344 20.197 ;
     RECT  40.032 18.899 41.448 20.533 ;
     RECT  44.976 20.099 45.912 20.579 ;
     RECT  42.624 20.003 42.648 21.109 ;
     RECT  31.056 18.275 31.08 21.155 ;
     RECT  29.28 20.099 29.712 21.443 ;
     RECT  36.336 9.107 36.36 21.683 ;
     RECT  11.616 15.925 14.472 21.781 ;
     RECT  18.192 19.141 24.312 23.125 ;
     RECT  2.304 20.197 10.344 23.411 ;
     RECT  2.304 23.411 10.296 24.227 ;
     RECT  18.192 23.125 24.408 24.469 ;
     RECT  18.192 24.469 24.6 25.045 ;
     RECT  18.192 25.045 25.512 26.005 ;
     RECT  26.736 1.235 26.76 26.005 ;
     RECT  11.52 21.781 14.472 26.819 ;
     RECT  18.192 26.005 26.76 27.971 ;
     RECT  18.192 27.971 26.136 28.309 ;
     RECT  11.712 26.819 14.472 28.453 ;
     RECT  15.696 23.893 15.72 28.453 ;
     RECT  11.712 28.453 15.72 29.029 ;
     RECT  27.792 0.563 27.816 29.123 ;
     RECT  0.144 29.317 0.168 29.603 ;
     RECT  18.144 28.309 26.136 29.605 ;
     RECT  2.4 24.227 10.296 29.699 ;
     RECT  11.712 29.029 16.392 30.037 ;
     RECT  29.4 21.443 29.712 30.181 ;
     RECT  28.272 30.181 29.712 30.421 ;
     RECT  40.032 20.533 41.592 31.189 ;
     RECT  42.624 21.109 43.176 31.189 ;
     RECT  18.144 29.605 26.568 31.285 ;
     RECT  40.032 31.189 43.176 31.285 ;
     RECT  2.4 29.699 9.816 32.005 ;
     RECT  2.304 32.005 9.816 32.197 ;
     RECT  2.256 32.197 9.816 32.531 ;
     RECT  2.304 32.531 9.816 32.867 ;
     RECT  39.936 31.285 43.176 32.869 ;
     RECT  38.304 31.765 38.328 33.589 ;
     RECT  37.728 33.589 38.328 33.779 ;
     RECT  39.744 32.869 43.176 34.021 ;
     RECT  34.8 2.867 35.112 34.117 ;
     RECT  36.096 32.197 36.12 34.117 ;
     RECT  0.144 33.253 0.168 35.125 ;
     RECT  0.144 35.125 0.216 35.315 ;
     RECT  34.8 34.117 36.12 35.317 ;
     RECT  34.8 35.317 36.168 35.459 ;
     RECT  37.728 33.779 37.752 35.845 ;
     RECT  39.264 34.021 43.176 35.939 ;
     RECT  32.88 35.557 32.904 35.987 ;
     RECT  39.504 35.939 43.176 36.179 ;
     RECT  0.144 35.315 0.168 36.275 ;
     RECT  39.648 36.179 43.176 36.661 ;
     RECT  44.4 21.781 44.424 36.661 ;
     RECT  39.648 36.661 44.424 36.997 ;
     RECT  45.6 20.579 45.912 36.997 ;
     RECT  37.728 35.845 38.184 37.139 ;
     RECT  39.648 36.997 45.912 37.331 ;
     RECT  37.728 37.139 38.136 37.379 ;
     RECT  34.8 35.459 35.112 37.429 ;
     RECT  39.744 37.331 45.912 37.429 ;
     RECT  33.6 37.429 35.112 37.571 ;
     RECT  31.056 35.701 31.08 38.101 ;
     RECT  33.6 37.571 33.72 38.149 ;
     RECT  27.984 30.421 29.712 38.389 ;
     RECT  31.056 38.101 31.464 38.389 ;
     RECT  38.112 37.379 38.136 38.579 ;
     RECT  39.744 37.429 46.152 38.677 ;
     RECT  27.984 38.389 31.464 38.819 ;
     RECT  33.504 38.149 33.72 39.059 ;
     RECT  36.144 35.459 36.168 39.251 ;
     RECT  33.504 39.059 33.624 39.395 ;
     RECT  33.504 39.395 33.528 39.491 ;
     RECT  0.144 39.493 0.168 39.779 ;
     RECT  49.296 38.053 49.32 39.829 ;
     RECT  34.8 37.571 35.112 39.877 ;
     RECT  49.296 39.829 50.184 39.877 ;
     RECT  39.744 38.677 46.68 40.981 ;
     RECT  49.296 39.877 50.28 40.981 ;
     RECT  38.16 38.965 38.184 41.027 ;
     RECT  34.8 39.877 35.352 41.795 ;
     RECT  48.768 40.981 50.28 42.227 ;
     RECT  39.552 40.981 46.68 42.277 ;
     RECT  39.552 42.277 46.776 42.707 ;
     RECT  39.552 42.707 45.912 42.803 ;
     RECT  34.8 41.795 35.256 42.851 ;
     RECT  18.144 31.285 27 43.189 ;
     RECT  27.984 38.819 31.08 43.189 ;
     RECT  47.856 42.325 47.88 43.379 ;
     RECT  0.192 43.861 0.216 44.099 ;
     RECT  49.296 42.227 50.28 44.197 ;
     RECT  48.432 44.197 50.28 45.491 ;
     RECT  32.4 44.437 32.424 46.883 ;
     RECT  36.144 45.157 36.168 48.707 ;
     RECT  0.144 48.997 0.168 49.187 ;
     RECT  38.016 44.437 38.04 49.187 ;
     RECT  11.712 30.037 16.44 50.341 ;
     RECT  18.144 43.189 31.08 50.389 ;
     RECT  10.848 50.341 16.44 51.251 ;
     RECT  18.144 50.389 31.512 51.253 ;
     RECT  0.192 51.157 0.216 51.395 ;
     RECT  18.144 51.253 32.28 51.539 ;
     RECT  11.712 51.251 16.44 51.973 ;
     RECT  18.144 51.539 32.04 51.973 ;
     RECT  34.8 42.851 35.112 52.165 ;
     RECT  11.712 51.973 32.04 52.739 ;
     RECT  33.888 52.165 35.112 52.931 ;
     RECT  32.496 52.885 32.52 53.317 ;
     RECT  11.712 52.739 31.128 53.507 ;
     RECT  11.712 53.507 31.08 53.699 ;
     RECT  32.496 53.317 32.616 53.795 ;
     RECT  11.712 53.699 17.16 54.661 ;
     RECT  18.144 53.699 31.08 54.661 ;
     RECT  32.496 53.795 32.52 54.707 ;
     RECT  2.4 32.867 9.816 56.101 ;
     RECT  2.304 56.101 9.816 56.291 ;
     RECT  11.712 54.661 31.08 56.483 ;
     RECT  11.712 56.483 24.744 57.059 ;
     RECT  11.712 57.059 20.664 59.123 ;
     RECT  0.192 59.797 0.216 60.035 ;
     RECT  11.712 59.123 16.68 60.325 ;
     RECT  11.712 60.325 16.728 60.853 ;
     RECT  11.712 60.853 16.776 60.995 ;
     RECT  11.712 60.995 16.44 61.045 ;
     RECT  18.144 59.123 20.664 61.189 ;
     RECT  11.664 61.045 16.44 61.475 ;
     RECT  18 61.189 20.664 61.813 ;
     RECT  21.648 57.059 24.744 61.813 ;
     RECT  11.712 61.475 16.44 62.629 ;
     RECT  18 61.813 24.744 62.629 ;
     RECT  11.712 62.629 24.744 62.867 ;
     RECT  11.712 62.867 20.664 63.491 ;
     RECT  17.52 63.491 20.664 63.779 ;
     RECT  21.888 62.867 24.744 64.069 ;
     RECT  0.192 64.165 0.216 64.355 ;
     RECT  11.712 63.491 16.44 64.789 ;
     RECT  17.52 63.779 20.616 64.789 ;
     RECT  11.184 64.789 20.616 64.931 ;
     RECT  17.52 64.931 20.616 65.027 ;
     RECT  11.712 64.931 16.44 65.219 ;
     RECT  2.4 56.291 9.816 65.509 ;
     RECT  17.52 65.027 20.232 65.651 ;
     RECT  16.368 65.219 16.44 65.747 ;
     RECT  18.096 65.651 20.232 66.179 ;
     RECT  11.712 65.219 15.096 66.275 ;
     RECT  18.144 66.179 20.232 66.323 ;
     RECT  21.744 64.069 24.744 66.323 ;
     RECT  21.744 66.323 22.152 66.469 ;
     RECT  21.024 66.469 22.152 66.707 ;
     RECT  2.4 65.509 10.344 66.803 ;
     RECT  16.416 65.747 16.44 66.899 ;
     RECT  18.144 66.323 19.8 67.427 ;
     RECT  0.144 67.621 0.168 67.811 ;
     RECT  39.744 42.803 45.912 68.917 ;
     RECT  11.712 66.275 14.136 68.963 ;
     RECT  2.4 66.803 9.816 69.203 ;
     RECT  12.864 68.963 14.136 69.491 ;
     RECT  12.864 69.491 14.088 69.731 ;
     RECT  2.4 69.203 9.672 69.971 ;
     RECT  11.712 68.963 11.736 69.971 ;
     RECT  13.2 69.731 14.088 70.019 ;
     RECT  2.4 69.971 9.288 70.405 ;
     RECT  21.888 66.707 22.152 70.499 ;
     RECT  21.888 70.499 21.912 70.549 ;
     RECT  20.976 70.549 21.912 70.691 ;
     RECT  21.888 70.691 21.912 70.739 ;
     RECT  2.304 70.405 9.288 71.171 ;
     RECT  23.376 66.323 24.744 71.221 ;
     RECT  49.296 45.491 50.28 71.461 ;
     RECT  49.296 71.461 50.376 71.797 ;
     RECT  22.944 71.221 24.744 71.843 ;
     RECT  0.144 71.893 0.168 72.133 ;
     RECT  18.6 67.427 19.8 72.227 ;
     RECT  0.144 72.133 0.264 72.275 ;
     RECT  1.248 71.893 1.272 72.275 ;
     RECT  22.944 71.843 24.696 72.707 ;
     RECT  0.144 72.275 0.168 72.755 ;
     RECT  39.696 68.917 45.912 72.805 ;
     RECT  18.6 72.227 18.912 72.853 ;
     RECT  2.4 71.171 9.288 72.995 ;
     RECT  39.696 72.805 46.248 73.093 ;
     RECT  18.288 72.853 18.912 73.235 ;
     RECT  1.152 73.045 1.176 73.283 ;
     RECT  39.696 73.093 46.344 73.477 ;
     RECT  21.168 72.661 21.192 73.811 ;
     RECT  25.776 56.483 31.08 74.053 ;
     RECT  39.696 73.477 46.536 74.053 ;
     RECT  2.4 72.995 8.52 74.101 ;
     RECT  39.696 74.053 47.688 74.581 ;
     RECT  23.376 72.707 24.696 74.675 ;
     RECT  2.304 74.101 8.52 74.723 ;
     RECT  25.68 74.053 31.08 74.723 ;
     RECT  39.696 74.581 47.976 75.205 ;
     RECT  26.592 74.723 30.312 75.683 ;
     RECT  26.592 75.683 30.216 75.781 ;
     RECT  26.496 75.781 30.216 76.885 ;
     RECT  2.4 74.723 8.52 77.171 ;
     RECT  2.4 77.171 8.112 77.317 ;
     RECT  26.496 76.885 30.984 77.413 ;
     RECT  23.616 74.675 24.696 77.555 ;
     RECT  26.496 77.413 31.752 78.037 ;
     RECT  23.616 77.555 24.312 78.229 ;
     RECT  26.496 78.037 32.04 78.229 ;
     RECT  2.304 77.317 8.112 78.467 ;
     RECT  26.496 78.229 32.184 78.469 ;
     RECT  23.52 78.229 24.312 78.613 ;
     RECT  23.52 78.613 25.224 79.045 ;
     RECT  23.52 79.045 25.416 79.189 ;
     RECT  23.52 79.189 25.512 79.237 ;
     RECT  26.496 78.469 32.424 79.237 ;
     RECT  13.2 70.019 13.512 79.765 ;
     RECT  14.592 79.573 14.616 79.765 ;
     RECT  2.4 78.467 8.112 79.859 ;
     RECT  23.52 79.237 32.424 80.293 ;
     RECT  13.2 79.765 14.712 80.341 ;
     RECT  13.2 80.341 16.296 81.445 ;
     RECT  21.072 81.205 21.096 81.445 ;
     RECT  21.072 81.445 21.768 81.493 ;
     RECT  2.4 79.859 2.856 81.635 ;
     RECT  20.688 81.493 21.768 81.733 ;
     RECT  13.2 81.445 17.16 82.021 ;
     RECT  20.688 81.733 22.152 82.021 ;
     RECT  20.592 82.021 22.152 82.069 ;
     RECT  20.592 82.069 22.344 82.117 ;
     RECT  20.592 82.117 22.44 82.261 ;
     RECT  23.52 80.293 32.712 82.261 ;
     RECT  18.6 73.235 18.912 82.549 ;
     RECT  13.2 82.021 17.352 83.029 ;
     RECT  18.336 82.549 18.912 83.029 ;
     RECT  13.2 83.029 18.912 83.749 ;
     RECT  20.592 82.261 32.712 83.749 ;
     RECT  13.2 83.749 32.712 86.005 ;
     RECT  12.624 86.005 32.712 86.341 ;
     RECT  4.176 79.859 8.112 86.533 ;
     RECT  4.176 86.533 8.28 86.869 ;
     RECT  12.576 86.341 32.712 87.061 ;
     RECT  4.176 86.869 8.856 87.397 ;
     RECT  4.176 87.397 9.624 87.685 ;
     RECT  4.176 87.685 9.864 88.261 ;
     RECT  2.4 81.635 2.712 88.501 ;
     RECT  1.488 88.501 2.712 88.741 ;
     RECT  12 87.061 32.712 88.885 ;
     RECT  4.176 88.261 9.912 89.461 ;
     RECT  12 88.885 32.904 89.941 ;
     RECT  34.8 52.931 35.112 89.941 ;
     RECT  4.176 89.461 10.44 90.565 ;
     RECT  39.696 75.205 48.024 90.565 ;
     RECT  3.936 90.565 10.44 91.093 ;
     RECT  1.392 88.741 2.712 91.141 ;
     RECT  3.888 91.093 10.44 91.141 ;
     RECT  1.392 91.141 10.44 94.069 ;
     RECT  12 89.941 35.112 94.069 ;
     RECT  37.008 96.277 37.032 96.757 ;
     RECT  36.816 96.757 37.032 96.997 ;
     RECT  38.736 90.565 48.024 96.997 ;
     RECT  1.392 94.069 35.112 97.235 ;
     RECT  36.816 96.997 48.024 97.333 ;
     RECT  36.72 97.333 48.024 97.909 ;
     RECT  34.176 97.235 35.112 97.955 ;
     RECT  36.624 97.909 48.024 98.629 ;
     RECT  34.8 97.955 35.112 101.259 ;
     RECT  34.896 101.259 35.112 101.273 ;
     RECT  34.896 101.273 35.016 102.613 ;
     RECT  36.624 98.629 48.168 102.613 ;
     RECT  49.2 71.797 50.376 102.613 ;
     RECT  1.392 97.235 32.712 103.477 ;
     RECT  33.936 102.613 35.112 103.477 ;
     RECT  36.24 102.613 50.376 103.477 ;
     RECT  51.696 102.613 51.72 103.477 ;
     RECT  1.392 103.477 51.912 103.632 ;
  END
END qfd_cst_s
END LIBRARY
